VERSION 5.8 ;
BUSBITCHARS "[]" ;
DIVIDERCHAR "/" ;
UNITS
    DATABASE MICRONS 1000 ;
END UNITS

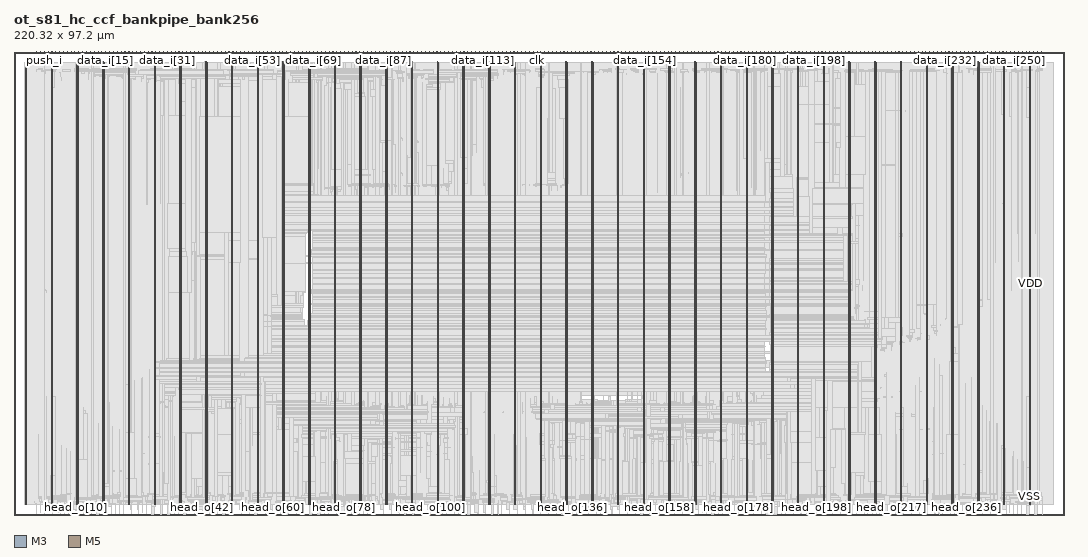
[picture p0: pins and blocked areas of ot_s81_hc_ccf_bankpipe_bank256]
MACRO ot_s81_hc_ccf_bankpipe_bank256
  FOREIGN ot_s81_hc_ccf_bankpipe_bank256 0 0 ;
  CLASS BLOCK ;
  SIZE 220.32 BY 97.2 ;
  PIN clk
    DIRECTION INPUT ;
    USE SIGNAL ;
    PORT
      LAYER M3 ;
        RECT  109.764 97.056 109.782 97.2 ;
    END
  END clk
  PIN data_i[0]
    DIRECTION INPUT ;
    USE SIGNAL ;
    PORT
      LAYER M5 ;
        RECT  7.152 97.008 7.176 97.2 ;
    END
  END data_i[0]
  PIN data_i[100]
    DIRECTION INPUT ;
    USE SIGNAL ;
    PORT
      LAYER M5 ;
        RECT  87.936 97.008 87.96 97.2 ;
    END
  END data_i[100]
  PIN data_i[101]
    DIRECTION INPUT ;
    USE SIGNAL ;
    PORT
      LAYER M3 ;
        RECT  88.74 97.056 88.758 97.2 ;
    END
  END data_i[101]
  PIN data_i[102]
    DIRECTION INPUT ;
    USE SIGNAL ;
    PORT
      LAYER M5 ;
        RECT  89.568 97.008 89.592 97.2 ;
    END
  END data_i[102]
  PIN data_i[103]
    DIRECTION INPUT ;
    USE SIGNAL ;
    PORT
      LAYER M3 ;
        RECT  90.36 97.056 90.378 97.2 ;
    END
  END data_i[103]
  PIN data_i[104]
    DIRECTION INPUT ;
    USE SIGNAL ;
    PORT
      LAYER M5 ;
        RECT  91.152 97.008 91.176 97.2 ;
    END
  END data_i[104]
  PIN data_i[105]
    DIRECTION INPUT ;
    USE SIGNAL ;
    PORT
      LAYER M3 ;
        RECT  91.98 97.056 91.998 97.2 ;
    END
  END data_i[105]
  PIN data_i[106]
    DIRECTION INPUT ;
    USE SIGNAL ;
    PORT
      LAYER M5 ;
        RECT  92.784 97.008 92.808 97.2 ;
    END
  END data_i[106]
  PIN data_i[107]
    DIRECTION INPUT ;
    USE SIGNAL ;
    PORT
      LAYER M3 ;
        RECT  93.6 97.056 93.618 97.2 ;
    END
  END data_i[107]
  PIN data_i[108]
    DIRECTION INPUT ;
    USE SIGNAL ;
    PORT
      LAYER M5 ;
        RECT  94.416 97.008 94.44 97.2 ;
    END
  END data_i[108]
  PIN data_i[109]
    DIRECTION INPUT ;
    USE SIGNAL ;
    PORT
      LAYER M3 ;
        RECT  95.22 97.056 95.238 97.2 ;
    END
  END data_i[109]
  PIN data_i[10]
    DIRECTION INPUT ;
    USE SIGNAL ;
    PORT
      LAYER M5 ;
        RECT  15.216 97.008 15.24 97.2 ;
    END
  END data_i[10]
  PIN data_i[110]
    DIRECTION INPUT ;
    USE SIGNAL ;
    PORT
      LAYER M5 ;
        RECT  96 97.008 96.024 97.2 ;
    END
  END data_i[110]
  PIN data_i[111]
    DIRECTION INPUT ;
    USE SIGNAL ;
    PORT
      LAYER M3 ;
        RECT  96.804 97.056 96.822 97.2 ;
    END
  END data_i[111]
  PIN data_i[112]
    DIRECTION INPUT ;
    USE SIGNAL ;
    PORT
      LAYER M5 ;
        RECT  97.632 97.008 97.656 97.2 ;
    END
  END data_i[112]
  PIN data_i[113]
    DIRECTION INPUT ;
    USE SIGNAL ;
    PORT
      LAYER M3 ;
        RECT  98.424 97.056 98.442 97.2 ;
    END
  END data_i[113]
  PIN data_i[114]
    DIRECTION INPUT ;
    USE SIGNAL ;
    PORT
      LAYER M5 ;
        RECT  99.264 97.008 99.288 97.2 ;
    END
  END data_i[114]
  PIN data_i[115]
    DIRECTION INPUT ;
    USE SIGNAL ;
    PORT
      LAYER M3 ;
        RECT  100.044 97.056 100.062 97.2 ;
    END
  END data_i[115]
  PIN data_i[116]
    DIRECTION INPUT ;
    USE SIGNAL ;
    PORT
      LAYER M5 ;
        RECT  100.848 97.008 100.872 97.2 ;
    END
  END data_i[116]
  PIN data_i[117]
    DIRECTION INPUT ;
    USE SIGNAL ;
    PORT
      LAYER M3 ;
        RECT  101.664 97.056 101.682 97.2 ;
    END
  END data_i[117]
  PIN data_i[118]
    DIRECTION INPUT ;
    USE SIGNAL ;
    PORT
      LAYER M5 ;
        RECT  102.48 97.008 102.504 97.2 ;
    END
  END data_i[118]
  PIN data_i[119]
    DIRECTION INPUT ;
    USE SIGNAL ;
    PORT
      LAYER M3 ;
        RECT  103.284 97.056 103.302 97.2 ;
    END
  END data_i[119]
  PIN data_i[11]
    DIRECTION INPUT ;
    USE SIGNAL ;
    PORT
      LAYER M3 ;
        RECT  16.02 97.056 16.038 97.2 ;
    END
  END data_i[11]
  PIN data_i[120]
    DIRECTION INPUT ;
    USE SIGNAL ;
    PORT
      LAYER M5 ;
        RECT  104.112 97.008 104.136 97.2 ;
    END
  END data_i[120]
  PIN data_i[121]
    DIRECTION INPUT ;
    USE SIGNAL ;
    PORT
      LAYER M3 ;
        RECT  104.904 97.056 104.922 97.2 ;
    END
  END data_i[121]
  PIN data_i[122]
    DIRECTION INPUT ;
    USE SIGNAL ;
    PORT
      LAYER M5 ;
        RECT  105.696 97.008 105.72 97.2 ;
    END
  END data_i[122]
  PIN data_i[123]
    DIRECTION INPUT ;
    USE SIGNAL ;
    PORT
      LAYER M3 ;
        RECT  106.524 97.056 106.542 97.2 ;
    END
  END data_i[123]
  PIN data_i[124]
    DIRECTION INPUT ;
    USE SIGNAL ;
    PORT
      LAYER M5 ;
        RECT  107.328 97.008 107.352 97.2 ;
    END
  END data_i[124]
  PIN data_i[125]
    DIRECTION INPUT ;
    USE SIGNAL ;
    PORT
      LAYER M3 ;
        RECT  108.144 97.056 108.162 97.2 ;
    END
  END data_i[125]
  PIN data_i[126]
    DIRECTION INPUT ;
    USE SIGNAL ;
    PORT
      LAYER M5 ;
        RECT  108.96 97.008 108.984 97.2 ;
    END
  END data_i[126]
  PIN data_i[127]
    DIRECTION INPUT ;
    USE SIGNAL ;
    PORT
      LAYER M5 ;
        RECT  110.544 97.008 110.568 97.2 ;
    END
  END data_i[127]
  PIN data_i[128]
    DIRECTION INPUT ;
    USE SIGNAL ;
    PORT
      LAYER M3 ;
        RECT  111.348 97.056 111.366 97.2 ;
    END
  END data_i[128]
  PIN data_i[129]
    DIRECTION INPUT ;
    USE SIGNAL ;
    PORT
      LAYER M5 ;
        RECT  112.176 97.008 112.2 97.2 ;
    END
  END data_i[129]
  PIN data_i[12]
    DIRECTION INPUT ;
    USE SIGNAL ;
    PORT
      LAYER M5 ;
        RECT  16.848 97.008 16.872 97.2 ;
    END
  END data_i[12]
  PIN data_i[130]
    DIRECTION INPUT ;
    USE SIGNAL ;
    PORT
      LAYER M3 ;
        RECT  112.968 97.056 112.986 97.2 ;
    END
  END data_i[130]
  PIN data_i[131]
    DIRECTION INPUT ;
    USE SIGNAL ;
    PORT
      LAYER M5 ;
        RECT  113.76 97.008 113.784 97.2 ;
    END
  END data_i[131]
  PIN data_i[132]
    DIRECTION INPUT ;
    USE SIGNAL ;
    PORT
      LAYER M3 ;
        RECT  114.588 97.056 114.606 97.2 ;
    END
  END data_i[132]
  PIN data_i[133]
    DIRECTION INPUT ;
    USE SIGNAL ;
    PORT
      LAYER M5 ;
        RECT  115.392 97.008 115.416 97.2 ;
    END
  END data_i[133]
  PIN data_i[134]
    DIRECTION INPUT ;
    USE SIGNAL ;
    PORT
      LAYER M3 ;
        RECT  116.208 97.056 116.226 97.2 ;
    END
  END data_i[134]
  PIN data_i[135]
    DIRECTION INPUT ;
    USE SIGNAL ;
    PORT
      LAYER M5 ;
        RECT  117.024 97.008 117.048 97.2 ;
    END
  END data_i[135]
  PIN data_i[136]
    DIRECTION INPUT ;
    USE SIGNAL ;
    PORT
      LAYER M3 ;
        RECT  117.828 97.056 117.846 97.2 ;
    END
  END data_i[136]
  PIN data_i[137]
    DIRECTION INPUT ;
    USE SIGNAL ;
    PORT
      LAYER M5 ;
        RECT  118.608 97.008 118.632 97.2 ;
    END
  END data_i[137]
  PIN data_i[138]
    DIRECTION INPUT ;
    USE SIGNAL ;
    PORT
      LAYER M3 ;
        RECT  119.448 97.056 119.466 97.2 ;
    END
  END data_i[138]
  PIN data_i[139]
    DIRECTION INPUT ;
    USE SIGNAL ;
    PORT
      LAYER M5 ;
        RECT  120.24 97.008 120.264 97.2 ;
    END
  END data_i[139]
  PIN data_i[13]
    DIRECTION INPUT ;
    USE SIGNAL ;
    PORT
      LAYER M3 ;
        RECT  17.64 97.056 17.658 97.2 ;
    END
  END data_i[13]
  PIN data_i[140]
    DIRECTION INPUT ;
    USE SIGNAL ;
    PORT
      LAYER M3 ;
        RECT  121.068 97.056 121.086 97.2 ;
    END
  END data_i[140]
  PIN data_i[141]
    DIRECTION INPUT ;
    USE SIGNAL ;
    PORT
      LAYER M5 ;
        RECT  121.872 97.008 121.896 97.2 ;
    END
  END data_i[141]
  PIN data_i[142]
    DIRECTION INPUT ;
    USE SIGNAL ;
    PORT
      LAYER M3 ;
        RECT  122.688 97.056 122.706 97.2 ;
    END
  END data_i[142]
  PIN data_i[143]
    DIRECTION INPUT ;
    USE SIGNAL ;
    PORT
      LAYER M5 ;
        RECT  123.456 97.008 123.48 97.2 ;
    END
  END data_i[143]
  PIN data_i[144]
    DIRECTION INPUT ;
    USE SIGNAL ;
    PORT
      LAYER M3 ;
        RECT  124.272 97.056 124.29 97.2 ;
    END
  END data_i[144]
  PIN data_i[145]
    DIRECTION INPUT ;
    USE SIGNAL ;
    PORT
      LAYER M5 ;
        RECT  125.088 97.008 125.112 97.2 ;
    END
  END data_i[145]
  PIN data_i[146]
    DIRECTION INPUT ;
    USE SIGNAL ;
    PORT
      LAYER M3 ;
        RECT  125.892 97.056 125.91 97.2 ;
    END
  END data_i[146]
  PIN data_i[147]
    DIRECTION INPUT ;
    USE SIGNAL ;
    PORT
      LAYER M5 ;
        RECT  126.72 97.008 126.744 97.2 ;
    END
  END data_i[147]
  PIN data_i[148]
    DIRECTION INPUT ;
    USE SIGNAL ;
    PORT
      LAYER M3 ;
        RECT  127.512 97.056 127.53 97.2 ;
    END
  END data_i[148]
  PIN data_i[149]
    DIRECTION INPUT ;
    USE SIGNAL ;
    PORT
      LAYER M5 ;
        RECT  128.304 97.008 128.328 97.2 ;
    END
  END data_i[149]
  PIN data_i[14]
    DIRECTION INPUT ;
    USE SIGNAL ;
    PORT
      LAYER M5 ;
        RECT  18.432 97.008 18.456 97.2 ;
    END
  END data_i[14]
  PIN data_i[150]
    DIRECTION INPUT ;
    USE SIGNAL ;
    PORT
      LAYER M3 ;
        RECT  129.132 97.056 129.15 97.2 ;
    END
  END data_i[150]
  PIN data_i[151]
    DIRECTION INPUT ;
    USE SIGNAL ;
    PORT
      LAYER M5 ;
        RECT  129.936 97.008 129.96 97.2 ;
    END
  END data_i[151]
  PIN data_i[152]
    DIRECTION INPUT ;
    USE SIGNAL ;
    PORT
      LAYER M3 ;
        RECT  130.752 97.056 130.77 97.2 ;
    END
  END data_i[152]
  PIN data_i[153]
    DIRECTION INPUT ;
    USE SIGNAL ;
    PORT
      LAYER M5 ;
        RECT  131.568 97.008 131.592 97.2 ;
    END
  END data_i[153]
  PIN data_i[154]
    DIRECTION INPUT ;
    USE SIGNAL ;
    PORT
      LAYER M3 ;
        RECT  132.372 97.056 132.39 97.2 ;
    END
  END data_i[154]
  PIN data_i[155]
    DIRECTION INPUT ;
    USE SIGNAL ;
    PORT
      LAYER M5 ;
        RECT  133.152 97.008 133.176 97.2 ;
    END
  END data_i[155]
  PIN data_i[156]
    DIRECTION INPUT ;
    USE SIGNAL ;
    PORT
      LAYER M3 ;
        RECT  133.992 97.056 134.01 97.2 ;
    END
  END data_i[156]
  PIN data_i[157]
    DIRECTION INPUT ;
    USE SIGNAL ;
    PORT
      LAYER M5 ;
        RECT  134.784 97.008 134.808 97.2 ;
    END
  END data_i[157]
  PIN data_i[158]
    DIRECTION INPUT ;
    USE SIGNAL ;
    PORT
      LAYER M3 ;
        RECT  135.612 97.056 135.63 97.2 ;
    END
  END data_i[158]
  PIN data_i[159]
    DIRECTION INPUT ;
    USE SIGNAL ;
    PORT
      LAYER M5 ;
        RECT  136.416 97.008 136.44 97.2 ;
    END
  END data_i[159]
  PIN data_i[15]
    DIRECTION INPUT ;
    USE SIGNAL ;
    PORT
      LAYER M3 ;
        RECT  19.26 97.056 19.278 97.2 ;
    END
  END data_i[15]
  PIN data_i[160]
    DIRECTION INPUT ;
    USE SIGNAL ;
    PORT
      LAYER M3 ;
        RECT  137.232 97.056 137.25 97.2 ;
    END
  END data_i[160]
  PIN data_i[161]
    DIRECTION INPUT ;
    USE SIGNAL ;
    PORT
      LAYER M5 ;
        RECT  138 97.008 138.024 97.2 ;
    END
  END data_i[161]
  PIN data_i[162]
    DIRECTION INPUT ;
    USE SIGNAL ;
    PORT
      LAYER M3 ;
        RECT  138.816 97.056 138.834 97.2 ;
    END
  END data_i[162]
  PIN data_i[163]
    DIRECTION INPUT ;
    USE SIGNAL ;
    PORT
      LAYER M5 ;
        RECT  139.632 97.008 139.656 97.2 ;
    END
  END data_i[163]
  PIN data_i[164]
    DIRECTION INPUT ;
    USE SIGNAL ;
    PORT
      LAYER M3 ;
        RECT  140.436 97.056 140.454 97.2 ;
    END
  END data_i[164]
  PIN data_i[165]
    DIRECTION INPUT ;
    USE SIGNAL ;
    PORT
      LAYER M5 ;
        RECT  141.264 97.008 141.288 97.2 ;
    END
  END data_i[165]
  PIN data_i[166]
    DIRECTION INPUT ;
    USE SIGNAL ;
    PORT
      LAYER M3 ;
        RECT  142.056 97.056 142.074 97.2 ;
    END
  END data_i[166]
  PIN data_i[167]
    DIRECTION INPUT ;
    USE SIGNAL ;
    PORT
      LAYER M5 ;
        RECT  142.848 97.008 142.872 97.2 ;
    END
  END data_i[167]
  PIN data_i[168]
    DIRECTION INPUT ;
    USE SIGNAL ;
    PORT
      LAYER M3 ;
        RECT  143.676 97.056 143.694 97.2 ;
    END
  END data_i[168]
  PIN data_i[169]
    DIRECTION INPUT ;
    USE SIGNAL ;
    PORT
      LAYER M5 ;
        RECT  144.48 97.008 144.504 97.2 ;
    END
  END data_i[169]
  PIN data_i[16]
    DIRECTION INPUT ;
    USE SIGNAL ;
    PORT
      LAYER M5 ;
        RECT  20.064 97.008 20.088 97.2 ;
    END
  END data_i[16]
  PIN data_i[170]
    DIRECTION INPUT ;
    USE SIGNAL ;
    PORT
      LAYER M3 ;
        RECT  145.296 97.056 145.314 97.2 ;
    END
  END data_i[170]
  PIN data_i[171]
    DIRECTION INPUT ;
    USE SIGNAL ;
    PORT
      LAYER M5 ;
        RECT  146.112 97.008 146.136 97.2 ;
    END
  END data_i[171]
  PIN data_i[172]
    DIRECTION INPUT ;
    USE SIGNAL ;
    PORT
      LAYER M3 ;
        RECT  146.916 97.056 146.934 97.2 ;
    END
  END data_i[172]
  PIN data_i[173]
    DIRECTION INPUT ;
    USE SIGNAL ;
    PORT
      LAYER M5 ;
        RECT  147.696 97.008 147.72 97.2 ;
    END
  END data_i[173]
  PIN data_i[174]
    DIRECTION INPUT ;
    USE SIGNAL ;
    PORT
      LAYER M3 ;
        RECT  148.536 97.056 148.554 97.2 ;
    END
  END data_i[174]
  PIN data_i[175]
    DIRECTION INPUT ;
    USE SIGNAL ;
    PORT
      LAYER M5 ;
        RECT  149.328 97.008 149.352 97.2 ;
    END
  END data_i[175]
  PIN data_i[176]
    DIRECTION INPUT ;
    USE SIGNAL ;
    PORT
      LAYER M3 ;
        RECT  150.156 97.056 150.174 97.2 ;
    END
  END data_i[176]
  PIN data_i[177]
    DIRECTION INPUT ;
    USE SIGNAL ;
    PORT
      LAYER M5 ;
        RECT  150.96 97.008 150.984 97.2 ;
    END
  END data_i[177]
  PIN data_i[178]
    DIRECTION INPUT ;
    USE SIGNAL ;
    PORT
      LAYER M3 ;
        RECT  151.776 97.056 151.794 97.2 ;
    END
  END data_i[178]
  PIN data_i[179]
    DIRECTION INPUT ;
    USE SIGNAL ;
    PORT
      LAYER M5 ;
        RECT  152.544 97.008 152.568 97.2 ;
    END
  END data_i[179]
  PIN data_i[17]
    DIRECTION INPUT ;
    USE SIGNAL ;
    PORT
      LAYER M3 ;
        RECT  20.88 97.056 20.898 97.2 ;
    END
  END data_i[17]
  PIN data_i[180]
    DIRECTION INPUT ;
    USE SIGNAL ;
    PORT
      LAYER M3 ;
        RECT  153.36 97.056 153.378 97.2 ;
    END
  END data_i[180]
  PIN data_i[181]
    DIRECTION INPUT ;
    USE SIGNAL ;
    PORT
      LAYER M5 ;
        RECT  154.176 97.008 154.2 97.2 ;
    END
  END data_i[181]
  PIN data_i[182]
    DIRECTION INPUT ;
    USE SIGNAL ;
    PORT
      LAYER M3 ;
        RECT  154.98 97.056 154.998 97.2 ;
    END
  END data_i[182]
  PIN data_i[183]
    DIRECTION INPUT ;
    USE SIGNAL ;
    PORT
      LAYER M5 ;
        RECT  155.808 97.008 155.832 97.2 ;
    END
  END data_i[183]
  PIN data_i[184]
    DIRECTION INPUT ;
    USE SIGNAL ;
    PORT
      LAYER M3 ;
        RECT  156.6 97.056 156.618 97.2 ;
    END
  END data_i[184]
  PIN data_i[185]
    DIRECTION INPUT ;
    USE SIGNAL ;
    PORT
      LAYER M5 ;
        RECT  157.392 97.008 157.416 97.2 ;
    END
  END data_i[185]
  PIN data_i[186]
    DIRECTION INPUT ;
    USE SIGNAL ;
    PORT
      LAYER M3 ;
        RECT  158.22 97.056 158.238 97.2 ;
    END
  END data_i[186]
  PIN data_i[187]
    DIRECTION INPUT ;
    USE SIGNAL ;
    PORT
      LAYER M5 ;
        RECT  159.024 97.008 159.048 97.2 ;
    END
  END data_i[187]
  PIN data_i[188]
    DIRECTION INPUT ;
    USE SIGNAL ;
    PORT
      LAYER M3 ;
        RECT  159.84 97.056 159.858 97.2 ;
    END
  END data_i[188]
  PIN data_i[189]
    DIRECTION INPUT ;
    USE SIGNAL ;
    PORT
      LAYER M5 ;
        RECT  160.656 97.008 160.68 97.2 ;
    END
  END data_i[189]
  PIN data_i[18]
    DIRECTION INPUT ;
    USE SIGNAL ;
    PORT
      LAYER M5 ;
        RECT  21.696 97.008 21.72 97.2 ;
    END
  END data_i[18]
  PIN data_i[190]
    DIRECTION INPUT ;
    USE SIGNAL ;
    PORT
      LAYER M3 ;
        RECT  161.46 97.056 161.478 97.2 ;
    END
  END data_i[190]
  PIN data_i[191]
    DIRECTION INPUT ;
    USE SIGNAL ;
    PORT
      LAYER M5 ;
        RECT  162.24 97.008 162.264 97.2 ;
    END
  END data_i[191]
  PIN data_i[192]
    DIRECTION INPUT ;
    USE SIGNAL ;
    PORT
      LAYER M3 ;
        RECT  163.08 97.056 163.098 97.2 ;
    END
  END data_i[192]
  PIN data_i[193]
    DIRECTION INPUT ;
    USE SIGNAL ;
    PORT
      LAYER M5 ;
        RECT  163.872 97.008 163.896 97.2 ;
    END
  END data_i[193]
  PIN data_i[194]
    DIRECTION INPUT ;
    USE SIGNAL ;
    PORT
      LAYER M3 ;
        RECT  164.7 97.056 164.718 97.2 ;
    END
  END data_i[194]
  PIN data_i[195]
    DIRECTION INPUT ;
    USE SIGNAL ;
    PORT
      LAYER M5 ;
        RECT  165.504 97.008 165.528 97.2 ;
    END
  END data_i[195]
  PIN data_i[196]
    DIRECTION INPUT ;
    USE SIGNAL ;
    PORT
      LAYER M3 ;
        RECT  166.32 97.056 166.338 97.2 ;
    END
  END data_i[196]
  PIN data_i[197]
    DIRECTION INPUT ;
    USE SIGNAL ;
    PORT
      LAYER M5 ;
        RECT  167.088 97.008 167.112 97.2 ;
    END
  END data_i[197]
  PIN data_i[198]
    DIRECTION INPUT ;
    USE SIGNAL ;
    PORT
      LAYER M3 ;
        RECT  167.904 97.056 167.922 97.2 ;
    END
  END data_i[198]
  PIN data_i[199]
    DIRECTION INPUT ;
    USE SIGNAL ;
    PORT
      LAYER M5 ;
        RECT  168.72 97.008 168.744 97.2 ;
    END
  END data_i[199]
  PIN data_i[19]
    DIRECTION INPUT ;
    USE SIGNAL ;
    PORT
      LAYER M3 ;
        RECT  22.5 97.056 22.518 97.2 ;
    END
  END data_i[19]
  PIN data_i[1]
    DIRECTION INPUT ;
    USE SIGNAL ;
    PORT
      LAYER M3 ;
        RECT  7.956 97.056 7.974 97.2 ;
    END
  END data_i[1]
  PIN data_i[200]
    DIRECTION INPUT ;
    USE SIGNAL ;
    PORT
      LAYER M3 ;
        RECT  169.524 97.056 169.542 97.2 ;
    END
  END data_i[200]
  PIN data_i[201]
    DIRECTION INPUT ;
    USE SIGNAL ;
    PORT
      LAYER M5 ;
        RECT  170.352 97.008 170.376 97.2 ;
    END
  END data_i[201]
  PIN data_i[202]
    DIRECTION INPUT ;
    USE SIGNAL ;
    PORT
      LAYER M3 ;
        RECT  171.144 97.056 171.162 97.2 ;
    END
  END data_i[202]
  PIN data_i[203]
    DIRECTION INPUT ;
    USE SIGNAL ;
    PORT
      LAYER M5 ;
        RECT  171.936 97.008 171.96 97.2 ;
    END
  END data_i[203]
  PIN data_i[204]
    DIRECTION INPUT ;
    USE SIGNAL ;
    PORT
      LAYER M3 ;
        RECT  172.764 97.056 172.782 97.2 ;
    END
  END data_i[204]
  PIN data_i[205]
    DIRECTION INPUT ;
    USE SIGNAL ;
    PORT
      LAYER M5 ;
        RECT  173.568 97.008 173.592 97.2 ;
    END
  END data_i[205]
  PIN data_i[206]
    DIRECTION INPUT ;
    USE SIGNAL ;
    PORT
      LAYER M3 ;
        RECT  174.384 97.056 174.402 97.2 ;
    END
  END data_i[206]
  PIN data_i[207]
    DIRECTION INPUT ;
    USE SIGNAL ;
    PORT
      LAYER M5 ;
        RECT  175.2 97.008 175.224 97.2 ;
    END
  END data_i[207]
  PIN data_i[208]
    DIRECTION INPUT ;
    USE SIGNAL ;
    PORT
      LAYER M3 ;
        RECT  176.004 97.056 176.022 97.2 ;
    END
  END data_i[208]
  PIN data_i[209]
    DIRECTION INPUT ;
    USE SIGNAL ;
    PORT
      LAYER M5 ;
        RECT  176.784 97.008 176.808 97.2 ;
    END
  END data_i[209]
  PIN data_i[20]
    DIRECTION INPUT ;
    USE SIGNAL ;
    PORT
      LAYER M5 ;
        RECT  23.28 97.008 23.304 97.2 ;
    END
  END data_i[20]
  PIN data_i[210]
    DIRECTION INPUT ;
    USE SIGNAL ;
    PORT
      LAYER M3 ;
        RECT  177.624 97.056 177.642 97.2 ;
    END
  END data_i[210]
  PIN data_i[211]
    DIRECTION INPUT ;
    USE SIGNAL ;
    PORT
      LAYER M5 ;
        RECT  178.416 97.008 178.44 97.2 ;
    END
  END data_i[211]
  PIN data_i[212]
    DIRECTION INPUT ;
    USE SIGNAL ;
    PORT
      LAYER M3 ;
        RECT  179.244 97.056 179.262 97.2 ;
    END
  END data_i[212]
  PIN data_i[213]
    DIRECTION INPUT ;
    USE SIGNAL ;
    PORT
      LAYER M5 ;
        RECT  180.048 97.008 180.072 97.2 ;
    END
  END data_i[213]
  PIN data_i[214]
    DIRECTION INPUT ;
    USE SIGNAL ;
    PORT
      LAYER M3 ;
        RECT  180.828 97.056 180.846 97.2 ;
    END
  END data_i[214]
  PIN data_i[215]
    DIRECTION INPUT ;
    USE SIGNAL ;
    PORT
      LAYER M5 ;
        RECT  181.632 97.008 181.656 97.2 ;
    END
  END data_i[215]
  PIN data_i[216]
    DIRECTION INPUT ;
    USE SIGNAL ;
    PORT
      LAYER M3 ;
        RECT  182.448 97.056 182.466 97.2 ;
    END
  END data_i[216]
  PIN data_i[217]
    DIRECTION INPUT ;
    USE SIGNAL ;
    PORT
      LAYER M5 ;
        RECT  183.264 97.008 183.288 97.2 ;
    END
  END data_i[217]
  PIN data_i[218]
    DIRECTION INPUT ;
    USE SIGNAL ;
    PORT
      LAYER M3 ;
        RECT  184.068 97.056 184.086 97.2 ;
    END
  END data_i[218]
  PIN data_i[219]
    DIRECTION INPUT ;
    USE SIGNAL ;
    PORT
      LAYER M5 ;
        RECT  184.896 97.008 184.92 97.2 ;
    END
  END data_i[219]
  PIN data_i[21]
    DIRECTION INPUT ;
    USE SIGNAL ;
    PORT
      LAYER M3 ;
        RECT  24.12 97.056 24.138 97.2 ;
    END
  END data_i[21]
  PIN data_i[220]
    DIRECTION INPUT ;
    USE SIGNAL ;
    PORT
      LAYER M3 ;
        RECT  185.688 97.056 185.706 97.2 ;
    END
  END data_i[220]
  PIN data_i[221]
    DIRECTION INPUT ;
    USE SIGNAL ;
    PORT
      LAYER M5 ;
        RECT  186.48 97.008 186.504 97.2 ;
    END
  END data_i[221]
  PIN data_i[222]
    DIRECTION INPUT ;
    USE SIGNAL ;
    PORT
      LAYER M3 ;
        RECT  187.308 97.056 187.326 97.2 ;
    END
  END data_i[222]
  PIN data_i[223]
    DIRECTION INPUT ;
    USE SIGNAL ;
    PORT
      LAYER M5 ;
        RECT  188.112 97.008 188.136 97.2 ;
    END
  END data_i[223]
  PIN data_i[224]
    DIRECTION INPUT ;
    USE SIGNAL ;
    PORT
      LAYER M3 ;
        RECT  188.928 97.056 188.946 97.2 ;
    END
  END data_i[224]
  PIN data_i[225]
    DIRECTION INPUT ;
    USE SIGNAL ;
    PORT
      LAYER M5 ;
        RECT  189.744 97.008 189.768 97.2 ;
    END
  END data_i[225]
  PIN data_i[226]
    DIRECTION INPUT ;
    USE SIGNAL ;
    PORT
      LAYER M3 ;
        RECT  190.548 97.056 190.566 97.2 ;
    END
  END data_i[226]
  PIN data_i[227]
    DIRECTION INPUT ;
    USE SIGNAL ;
    PORT
      LAYER M5 ;
        RECT  191.328 97.008 191.352 97.2 ;
    END
  END data_i[227]
  PIN data_i[228]
    DIRECTION INPUT ;
    USE SIGNAL ;
    PORT
      LAYER M3 ;
        RECT  192.168 97.056 192.186 97.2 ;
    END
  END data_i[228]
  PIN data_i[229]
    DIRECTION INPUT ;
    USE SIGNAL ;
    PORT
      LAYER M5 ;
        RECT  192.96 97.008 192.984 97.2 ;
    END
  END data_i[229]
  PIN data_i[22]
    DIRECTION INPUT ;
    USE SIGNAL ;
    PORT
      LAYER M5 ;
        RECT  24.912 97.008 24.936 97.2 ;
    END
  END data_i[22]
  PIN data_i[230]
    DIRECTION INPUT ;
    USE SIGNAL ;
    PORT
      LAYER M3 ;
        RECT  193.788 97.056 193.806 97.2 ;
    END
  END data_i[230]
  PIN data_i[231]
    DIRECTION INPUT ;
    USE SIGNAL ;
    PORT
      LAYER M5 ;
        RECT  194.592 97.008 194.616 97.2 ;
    END
  END data_i[231]
  PIN data_i[232]
    DIRECTION INPUT ;
    USE SIGNAL ;
    PORT
      LAYER M3 ;
        RECT  195.372 97.056 195.39 97.2 ;
    END
  END data_i[232]
  PIN data_i[233]
    DIRECTION INPUT ;
    USE SIGNAL ;
    PORT
      LAYER M5 ;
        RECT  196.176 97.008 196.2 97.2 ;
    END
  END data_i[233]
  PIN data_i[234]
    DIRECTION INPUT ;
    USE SIGNAL ;
    PORT
      LAYER M3 ;
        RECT  196.992 97.056 197.01 97.2 ;
    END
  END data_i[234]
  PIN data_i[235]
    DIRECTION INPUT ;
    USE SIGNAL ;
    PORT
      LAYER M5 ;
        RECT  197.808 97.008 197.832 97.2 ;
    END
  END data_i[235]
  PIN data_i[236]
    DIRECTION INPUT ;
    USE SIGNAL ;
    PORT
      LAYER M3 ;
        RECT  198.612 97.056 198.63 97.2 ;
    END
  END data_i[236]
  PIN data_i[237]
    DIRECTION INPUT ;
    USE SIGNAL ;
    PORT
      LAYER M5 ;
        RECT  199.44 97.008 199.464 97.2 ;
    END
  END data_i[237]
  PIN data_i[238]
    DIRECTION INPUT ;
    USE SIGNAL ;
    PORT
      LAYER M3 ;
        RECT  200.232 97.056 200.25 97.2 ;
    END
  END data_i[238]
  PIN data_i[239]
    DIRECTION INPUT ;
    USE SIGNAL ;
    PORT
      LAYER M5 ;
        RECT  201.024 97.008 201.048 97.2 ;
    END
  END data_i[239]
  PIN data_i[23]
    DIRECTION INPUT ;
    USE SIGNAL ;
    PORT
      LAYER M3 ;
        RECT  25.704 97.056 25.722 97.2 ;
    END
  END data_i[23]
  PIN data_i[240]
    DIRECTION INPUT ;
    USE SIGNAL ;
    PORT
      LAYER M3 ;
        RECT  201.852 97.056 201.87 97.2 ;
    END
  END data_i[240]
  PIN data_i[241]
    DIRECTION INPUT ;
    USE SIGNAL ;
    PORT
      LAYER M5 ;
        RECT  202.656 97.008 202.68 97.2 ;
    END
  END data_i[241]
  PIN data_i[242]
    DIRECTION INPUT ;
    USE SIGNAL ;
    PORT
      LAYER M3 ;
        RECT  203.472 97.056 203.49 97.2 ;
    END
  END data_i[242]
  PIN data_i[243]
    DIRECTION INPUT ;
    USE SIGNAL ;
    PORT
      LAYER M5 ;
        RECT  204.288 97.008 204.312 97.2 ;
    END
  END data_i[243]
  PIN data_i[244]
    DIRECTION INPUT ;
    USE SIGNAL ;
    PORT
      LAYER M3 ;
        RECT  205.092 97.056 205.11 97.2 ;
    END
  END data_i[244]
  PIN data_i[245]
    DIRECTION INPUT ;
    USE SIGNAL ;
    PORT
      LAYER M5 ;
        RECT  205.872 97.008 205.896 97.2 ;
    END
  END data_i[245]
  PIN data_i[246]
    DIRECTION INPUT ;
    USE SIGNAL ;
    PORT
      LAYER M3 ;
        RECT  206.712 97.056 206.73 97.2 ;
    END
  END data_i[246]
  PIN data_i[247]
    DIRECTION INPUT ;
    USE SIGNAL ;
    PORT
      LAYER M5 ;
        RECT  207.504 97.008 207.528 97.2 ;
    END
  END data_i[247]
  PIN data_i[248]
    DIRECTION INPUT ;
    USE SIGNAL ;
    PORT
      LAYER M3 ;
        RECT  208.332 97.056 208.35 97.2 ;
    END
  END data_i[248]
  PIN data_i[249]
    DIRECTION INPUT ;
    USE SIGNAL ;
    PORT
      LAYER M5 ;
        RECT  209.136 97.008 209.16 97.2 ;
    END
  END data_i[249]
  PIN data_i[24]
    DIRECTION INPUT ;
    USE SIGNAL ;
    PORT
      LAYER M5 ;
        RECT  26.544 97.008 26.568 97.2 ;
    END
  END data_i[24]
  PIN data_i[250]
    DIRECTION INPUT ;
    USE SIGNAL ;
    PORT
      LAYER M3 ;
        RECT  209.916 97.056 209.934 97.2 ;
    END
  END data_i[250]
  PIN data_i[251]
    DIRECTION INPUT ;
    USE SIGNAL ;
    PORT
      LAYER M5 ;
        RECT  210.72 97.008 210.744 97.2 ;
    END
  END data_i[251]
  PIN data_i[252]
    DIRECTION INPUT ;
    USE SIGNAL ;
    PORT
      LAYER M3 ;
        RECT  211.536 97.056 211.554 97.2 ;
    END
  END data_i[252]
  PIN data_i[253]
    DIRECTION INPUT ;
    USE SIGNAL ;
    PORT
      LAYER M5 ;
        RECT  212.352 97.008 212.376 97.2 ;
    END
  END data_i[253]
  PIN data_i[254]
    DIRECTION INPUT ;
    USE SIGNAL ;
    PORT
      LAYER M3 ;
        RECT  213.156 97.056 213.174 97.2 ;
    END
  END data_i[254]
  PIN data_i[255]
    DIRECTION INPUT ;
    USE SIGNAL ;
    PORT
      LAYER M5 ;
        RECT  213.984 97.008 214.008 97.2 ;
    END
  END data_i[255]
  PIN data_i[25]
    DIRECTION INPUT ;
    USE SIGNAL ;
    PORT
      LAYER M3 ;
        RECT  27.324 97.056 27.342 97.2 ;
    END
  END data_i[25]
  PIN data_i[26]
    DIRECTION INPUT ;
    USE SIGNAL ;
    PORT
      LAYER M5 ;
        RECT  28.128 97.008 28.152 97.2 ;
    END
  END data_i[26]
  PIN data_i[27]
    DIRECTION INPUT ;
    USE SIGNAL ;
    PORT
      LAYER M3 ;
        RECT  28.944 97.056 28.962 97.2 ;
    END
  END data_i[27]
  PIN data_i[28]
    DIRECTION INPUT ;
    USE SIGNAL ;
    PORT
      LAYER M5 ;
        RECT  29.76 97.008 29.784 97.2 ;
    END
  END data_i[28]
  PIN data_i[29]
    DIRECTION INPUT ;
    USE SIGNAL ;
    PORT
      LAYER M3 ;
        RECT  30.564 97.056 30.582 97.2 ;
    END
  END data_i[29]
  PIN data_i[2]
    DIRECTION INPUT ;
    USE SIGNAL ;
    PORT
      LAYER M5 ;
        RECT  8.736 97.008 8.76 97.2 ;
    END
  END data_i[2]
  PIN data_i[30]
    DIRECTION INPUT ;
    USE SIGNAL ;
    PORT
      LAYER M5 ;
        RECT  31.392 97.008 31.416 97.2 ;
    END
  END data_i[30]
  PIN data_i[31]
    DIRECTION INPUT ;
    USE SIGNAL ;
    PORT
      LAYER M3 ;
        RECT  32.184 97.056 32.202 97.2 ;
    END
  END data_i[31]
  PIN data_i[32]
    DIRECTION INPUT ;
    USE SIGNAL ;
    PORT
      LAYER M5 ;
        RECT  32.976 97.008 33 97.2 ;
    END
  END data_i[32]
  PIN data_i[33]
    DIRECTION INPUT ;
    USE SIGNAL ;
    PORT
      LAYER M3 ;
        RECT  33.804 97.056 33.822 97.2 ;
    END
  END data_i[33]
  PIN data_i[34]
    DIRECTION INPUT ;
    USE SIGNAL ;
    PORT
      LAYER M5 ;
        RECT  34.608 97.008 34.632 97.2 ;
    END
  END data_i[34]
  PIN data_i[35]
    DIRECTION INPUT ;
    USE SIGNAL ;
    PORT
      LAYER M3 ;
        RECT  35.424 97.056 35.442 97.2 ;
    END
  END data_i[35]
  PIN data_i[36]
    DIRECTION INPUT ;
    USE SIGNAL ;
    PORT
      LAYER M5 ;
        RECT  36.24 97.008 36.264 97.2 ;
    END
  END data_i[36]
  PIN data_i[37]
    DIRECTION INPUT ;
    USE SIGNAL ;
    PORT
      LAYER M3 ;
        RECT  37.044 97.056 37.062 97.2 ;
    END
  END data_i[37]
  PIN data_i[38]
    DIRECTION INPUT ;
    USE SIGNAL ;
    PORT
      LAYER M5 ;
        RECT  37.824 97.008 37.848 97.2 ;
    END
  END data_i[38]
  PIN data_i[39]
    DIRECTION INPUT ;
    USE SIGNAL ;
    PORT
      LAYER M3 ;
        RECT  38.664 97.056 38.682 97.2 ;
    END
  END data_i[39]
  PIN data_i[3]
    DIRECTION INPUT ;
    USE SIGNAL ;
    PORT
      LAYER M3 ;
        RECT  9.576 97.056 9.594 97.2 ;
    END
  END data_i[3]
  PIN data_i[40]
    DIRECTION INPUT ;
    USE SIGNAL ;
    PORT
      LAYER M5 ;
        RECT  39.456 97.008 39.48 97.2 ;
    END
  END data_i[40]
  PIN data_i[41]
    DIRECTION INPUT ;
    USE SIGNAL ;
    PORT
      LAYER M3 ;
        RECT  40.248 97.056 40.266 97.2 ;
    END
  END data_i[41]
  PIN data_i[42]
    DIRECTION INPUT ;
    USE SIGNAL ;
    PORT
      LAYER M5 ;
        RECT  41.088 97.008 41.112 97.2 ;
    END
  END data_i[42]
  PIN data_i[43]
    DIRECTION INPUT ;
    USE SIGNAL ;
    PORT
      LAYER M3 ;
        RECT  41.868 97.056 41.886 97.2 ;
    END
  END data_i[43]
  PIN data_i[44]
    DIRECTION INPUT ;
    USE SIGNAL ;
    PORT
      LAYER M5 ;
        RECT  42.672 97.008 42.696 97.2 ;
    END
  END data_i[44]
  PIN data_i[45]
    DIRECTION INPUT ;
    USE SIGNAL ;
    PORT
      LAYER M3 ;
        RECT  43.488 97.056 43.506 97.2 ;
    END
  END data_i[45]
  PIN data_i[46]
    DIRECTION INPUT ;
    USE SIGNAL ;
    PORT
      LAYER M5 ;
        RECT  44.304 97.008 44.328 97.2 ;
    END
  END data_i[46]
  PIN data_i[47]
    DIRECTION INPUT ;
    USE SIGNAL ;
    PORT
      LAYER M3 ;
        RECT  45.108 97.056 45.126 97.2 ;
    END
  END data_i[47]
  PIN data_i[48]
    DIRECTION INPUT ;
    USE SIGNAL ;
    PORT
      LAYER M5 ;
        RECT  45.936 97.008 45.96 97.2 ;
    END
  END data_i[48]
  PIN data_i[49]
    DIRECTION INPUT ;
    USE SIGNAL ;
    PORT
      LAYER M3 ;
        RECT  46.728 97.056 46.746 97.2 ;
    END
  END data_i[49]
  PIN data_i[4]
    DIRECTION INPUT ;
    USE SIGNAL ;
    PORT
      LAYER M5 ;
        RECT  10.368 97.008 10.392 97.2 ;
    END
  END data_i[4]
  PIN data_i[50]
    DIRECTION INPUT ;
    USE SIGNAL ;
    PORT
      LAYER M5 ;
        RECT  47.52 97.008 47.544 97.2 ;
    END
  END data_i[50]
  PIN data_i[51]
    DIRECTION INPUT ;
    USE SIGNAL ;
    PORT
      LAYER M3 ;
        RECT  48.348 97.056 48.366 97.2 ;
    END
  END data_i[51]
  PIN data_i[52]
    DIRECTION INPUT ;
    USE SIGNAL ;
    PORT
      LAYER M5 ;
        RECT  49.152 97.008 49.176 97.2 ;
    END
  END data_i[52]
  PIN data_i[53]
    DIRECTION INPUT ;
    USE SIGNAL ;
    PORT
      LAYER M3 ;
        RECT  49.968 97.056 49.986 97.2 ;
    END
  END data_i[53]
  PIN data_i[54]
    DIRECTION INPUT ;
    USE SIGNAL ;
    PORT
      LAYER M5 ;
        RECT  50.784 97.008 50.808 97.2 ;
    END
  END data_i[54]
  PIN data_i[55]
    DIRECTION INPUT ;
    USE SIGNAL ;
    PORT
      LAYER M3 ;
        RECT  51.588 97.056 51.606 97.2 ;
    END
  END data_i[55]
  PIN data_i[56]
    DIRECTION INPUT ;
    USE SIGNAL ;
    PORT
      LAYER M5 ;
        RECT  52.368 97.008 52.392 97.2 ;
    END
  END data_i[56]
  PIN data_i[57]
    DIRECTION INPUT ;
    USE SIGNAL ;
    PORT
      LAYER M3 ;
        RECT  53.208 97.056 53.226 97.2 ;
    END
  END data_i[57]
  PIN data_i[58]
    DIRECTION INPUT ;
    USE SIGNAL ;
    PORT
      LAYER M5 ;
        RECT  54 97.008 54.024 97.2 ;
    END
  END data_i[58]
  PIN data_i[59]
    DIRECTION INPUT ;
    USE SIGNAL ;
    PORT
      LAYER M3 ;
        RECT  54.792 97.056 54.81 97.2 ;
    END
  END data_i[59]
  PIN data_i[5]
    DIRECTION INPUT ;
    USE SIGNAL ;
    PORT
      LAYER M3 ;
        RECT  11.196 97.056 11.214 97.2 ;
    END
  END data_i[5]
  PIN data_i[60]
    DIRECTION INPUT ;
    USE SIGNAL ;
    PORT
      LAYER M5 ;
        RECT  55.632 97.008 55.656 97.2 ;
    END
  END data_i[60]
  PIN data_i[61]
    DIRECTION INPUT ;
    USE SIGNAL ;
    PORT
      LAYER M3 ;
        RECT  56.412 97.056 56.43 97.2 ;
    END
  END data_i[61]
  PIN data_i[62]
    DIRECTION INPUT ;
    USE SIGNAL ;
    PORT
      LAYER M5 ;
        RECT  57.216 97.008 57.24 97.2 ;
    END
  END data_i[62]
  PIN data_i[63]
    DIRECTION INPUT ;
    USE SIGNAL ;
    PORT
      LAYER M3 ;
        RECT  58.032 97.056 58.05 97.2 ;
    END
  END data_i[63]
  PIN data_i[64]
    DIRECTION INPUT ;
    USE SIGNAL ;
    PORT
      LAYER M5 ;
        RECT  58.848 97.008 58.872 97.2 ;
    END
  END data_i[64]
  PIN data_i[65]
    DIRECTION INPUT ;
    USE SIGNAL ;
    PORT
      LAYER M3 ;
        RECT  59.652 97.056 59.67 97.2 ;
    END
  END data_i[65]
  PIN data_i[66]
    DIRECTION INPUT ;
    USE SIGNAL ;
    PORT
      LAYER M5 ;
        RECT  60.48 97.008 60.504 97.2 ;
    END
  END data_i[66]
  PIN data_i[67]
    DIRECTION INPUT ;
    USE SIGNAL ;
    PORT
      LAYER M3 ;
        RECT  61.272 97.056 61.29 97.2 ;
    END
  END data_i[67]
  PIN data_i[68]
    DIRECTION INPUT ;
    USE SIGNAL ;
    PORT
      LAYER M5 ;
        RECT  62.064 97.008 62.088 97.2 ;
    END
  END data_i[68]
  PIN data_i[69]
    DIRECTION INPUT ;
    USE SIGNAL ;
    PORT
      LAYER M3 ;
        RECT  62.892 97.056 62.91 97.2 ;
    END
  END data_i[69]
  PIN data_i[6]
    DIRECTION INPUT ;
    USE SIGNAL ;
    PORT
      LAYER M5 ;
        RECT  12 97.008 12.024 97.2 ;
    END
  END data_i[6]
  PIN data_i[70]
    DIRECTION INPUT ;
    USE SIGNAL ;
    PORT
      LAYER M5 ;
        RECT  63.696 97.008 63.72 97.2 ;
    END
  END data_i[70]
  PIN data_i[71]
    DIRECTION INPUT ;
    USE SIGNAL ;
    PORT
      LAYER M3 ;
        RECT  64.512 97.056 64.53 97.2 ;
    END
  END data_i[71]
  PIN data_i[72]
    DIRECTION INPUT ;
    USE SIGNAL ;
    PORT
      LAYER M5 ;
        RECT  65.328 97.008 65.352 97.2 ;
    END
  END data_i[72]
  PIN data_i[73]
    DIRECTION INPUT ;
    USE SIGNAL ;
    PORT
      LAYER M3 ;
        RECT  66.132 97.056 66.15 97.2 ;
    END
  END data_i[73]
  PIN data_i[74]
    DIRECTION INPUT ;
    USE SIGNAL ;
    PORT
      LAYER M5 ;
        RECT  66.912 97.008 66.936 97.2 ;
    END
  END data_i[74]
  PIN data_i[75]
    DIRECTION INPUT ;
    USE SIGNAL ;
    PORT
      LAYER M3 ;
        RECT  67.752 97.056 67.77 97.2 ;
    END
  END data_i[75]
  PIN data_i[76]
    DIRECTION INPUT ;
    USE SIGNAL ;
    PORT
      LAYER M5 ;
        RECT  68.544 97.008 68.568 97.2 ;
    END
  END data_i[76]
  PIN data_i[77]
    DIRECTION INPUT ;
    USE SIGNAL ;
    PORT
      LAYER M3 ;
        RECT  69.336 97.056 69.354 97.2 ;
    END
  END data_i[77]
  PIN data_i[78]
    DIRECTION INPUT ;
    USE SIGNAL ;
    PORT
      LAYER M5 ;
        RECT  70.176 97.008 70.2 97.2 ;
    END
  END data_i[78]
  PIN data_i[79]
    DIRECTION INPUT ;
    USE SIGNAL ;
    PORT
      LAYER M3 ;
        RECT  70.956 97.056 70.974 97.2 ;
    END
  END data_i[79]
  PIN data_i[7]
    DIRECTION INPUT ;
    USE SIGNAL ;
    PORT
      LAYER M3 ;
        RECT  12.78 97.056 12.798 97.2 ;
    END
  END data_i[7]
  PIN data_i[80]
    DIRECTION INPUT ;
    USE SIGNAL ;
    PORT
      LAYER M5 ;
        RECT  71.76 97.008 71.784 97.2 ;
    END
  END data_i[80]
  PIN data_i[81]
    DIRECTION INPUT ;
    USE SIGNAL ;
    PORT
      LAYER M3 ;
        RECT  72.576 97.056 72.594 97.2 ;
    END
  END data_i[81]
  PIN data_i[82]
    DIRECTION INPUT ;
    USE SIGNAL ;
    PORT
      LAYER M5 ;
        RECT  73.392 97.008 73.416 97.2 ;
    END
  END data_i[82]
  PIN data_i[83]
    DIRECTION INPUT ;
    USE SIGNAL ;
    PORT
      LAYER M3 ;
        RECT  74.196 97.056 74.214 97.2 ;
    END
  END data_i[83]
  PIN data_i[84]
    DIRECTION INPUT ;
    USE SIGNAL ;
    PORT
      LAYER M5 ;
        RECT  75.024 97.008 75.048 97.2 ;
    END
  END data_i[84]
  PIN data_i[85]
    DIRECTION INPUT ;
    USE SIGNAL ;
    PORT
      LAYER M3 ;
        RECT  75.816 97.056 75.834 97.2 ;
    END
  END data_i[85]
  PIN data_i[86]
    DIRECTION INPUT ;
    USE SIGNAL ;
    PORT
      LAYER M5 ;
        RECT  76.608 97.008 76.632 97.2 ;
    END
  END data_i[86]
  PIN data_i[87]
    DIRECTION INPUT ;
    USE SIGNAL ;
    PORT
      LAYER M3 ;
        RECT  77.436 97.056 77.454 97.2 ;
    END
  END data_i[87]
  PIN data_i[88]
    DIRECTION INPUT ;
    USE SIGNAL ;
    PORT
      LAYER M5 ;
        RECT  78.24 97.008 78.264 97.2 ;
    END
  END data_i[88]
  PIN data_i[89]
    DIRECTION INPUT ;
    USE SIGNAL ;
    PORT
      LAYER M3 ;
        RECT  79.056 97.056 79.074 97.2 ;
    END
  END data_i[89]
  PIN data_i[8]
    DIRECTION INPUT ;
    USE SIGNAL ;
    PORT
      LAYER M5 ;
        RECT  13.584 97.008 13.608 97.2 ;
    END
  END data_i[8]
  PIN data_i[90]
    DIRECTION INPUT ;
    USE SIGNAL ;
    PORT
      LAYER M5 ;
        RECT  79.872 97.008 79.896 97.2 ;
    END
  END data_i[90]
  PIN data_i[91]
    DIRECTION INPUT ;
    USE SIGNAL ;
    PORT
      LAYER M3 ;
        RECT  80.676 97.056 80.694 97.2 ;
    END
  END data_i[91]
  PIN data_i[92]
    DIRECTION INPUT ;
    USE SIGNAL ;
    PORT
      LAYER M5 ;
        RECT  81.456 97.008 81.48 97.2 ;
    END
  END data_i[92]
  PIN data_i[93]
    DIRECTION INPUT ;
    USE SIGNAL ;
    PORT
      LAYER M3 ;
        RECT  82.26 97.056 82.278 97.2 ;
    END
  END data_i[93]
  PIN data_i[94]
    DIRECTION INPUT ;
    USE SIGNAL ;
    PORT
      LAYER M5 ;
        RECT  83.088 97.008 83.112 97.2 ;
    END
  END data_i[94]
  PIN data_i[95]
    DIRECTION INPUT ;
    USE SIGNAL ;
    PORT
      LAYER M3 ;
        RECT  83.88 97.056 83.898 97.2 ;
    END
  END data_i[95]
  PIN data_i[96]
    DIRECTION INPUT ;
    USE SIGNAL ;
    PORT
      LAYER M5 ;
        RECT  84.72 97.008 84.744 97.2 ;
    END
  END data_i[96]
  PIN data_i[97]
    DIRECTION INPUT ;
    USE SIGNAL ;
    PORT
      LAYER M3 ;
        RECT  85.5 97.056 85.518 97.2 ;
    END
  END data_i[97]
  PIN data_i[98]
    DIRECTION INPUT ;
    USE SIGNAL ;
    PORT
      LAYER M5 ;
        RECT  86.304 97.008 86.328 97.2 ;
    END
  END data_i[98]
  PIN data_i[99]
    DIRECTION INPUT ;
    USE SIGNAL ;
    PORT
      LAYER M3 ;
        RECT  87.12 97.056 87.138 97.2 ;
    END
  END data_i[99]
  PIN data_i[9]
    DIRECTION INPUT ;
    USE SIGNAL ;
    PORT
      LAYER M3 ;
        RECT  14.4 97.056 14.418 97.2 ;
    END
  END data_i[9]
  PIN head_o[0]
    DIRECTION OUTPUT ;
    USE SIGNAL ;
    PORT
      LAYER M3 ;
        RECT  4.716 0 4.734 0.144 ;
    END
  END head_o[0]
  PIN head_o[100]
    DIRECTION OUTPUT ;
    USE SIGNAL ;
    PORT
      LAYER M3 ;
        RECT  87.408 0 87.426 0.144 ;
    END
  END head_o[100]
  PIN head_o[101]
    DIRECTION OUTPUT ;
    USE SIGNAL ;
    PORT
      LAYER M5 ;
        RECT  88.224 0 88.248 0.192 ;
    END
  END head_o[101]
  PIN head_o[102]
    DIRECTION OUTPUT ;
    USE SIGNAL ;
    PORT
      LAYER M3 ;
        RECT  89.064 0 89.082 0.144 ;
    END
  END head_o[102]
  PIN head_o[103]
    DIRECTION OUTPUT ;
    USE SIGNAL ;
    PORT
      LAYER M5 ;
        RECT  89.904 0 89.928 0.192 ;
    END
  END head_o[103]
  PIN head_o[104]
    DIRECTION OUTPUT ;
    USE SIGNAL ;
    PORT
      LAYER M3 ;
        RECT  90.72 0 90.738 0.144 ;
    END
  END head_o[104]
  PIN head_o[105]
    DIRECTION OUTPUT ;
    USE SIGNAL ;
    PORT
      LAYER M5 ;
        RECT  91.536 0 91.56 0.192 ;
    END
  END head_o[105]
  PIN head_o[106]
    DIRECTION OUTPUT ;
    USE SIGNAL ;
    PORT
      LAYER M3 ;
        RECT  92.376 0 92.394 0.144 ;
    END
  END head_o[106]
  PIN head_o[107]
    DIRECTION OUTPUT ;
    USE SIGNAL ;
    PORT
      LAYER M5 ;
        RECT  93.216 0 93.24 0.192 ;
    END
  END head_o[107]
  PIN head_o[108]
    DIRECTION OUTPUT ;
    USE SIGNAL ;
    PORT
      LAYER M3 ;
        RECT  94.032 0 94.05 0.144 ;
    END
  END head_o[108]
  PIN head_o[109]
    DIRECTION OUTPUT ;
    USE SIGNAL ;
    PORT
      LAYER M5 ;
        RECT  94.848 0 94.872 0.192 ;
    END
  END head_o[109]
  PIN head_o[10]
    DIRECTION OUTPUT ;
    USE SIGNAL ;
    PORT
      LAYER M3 ;
        RECT  12.996 0 13.014 0.144 ;
    END
  END head_o[10]
  PIN head_o[110]
    DIRECTION OUTPUT ;
    USE SIGNAL ;
    PORT
      LAYER M3 ;
        RECT  95.688 0 95.706 0.144 ;
    END
  END head_o[110]
  PIN head_o[111]
    DIRECTION OUTPUT ;
    USE SIGNAL ;
    PORT
      LAYER M5 ;
        RECT  96.528 0 96.552 0.192 ;
    END
  END head_o[111]
  PIN head_o[112]
    DIRECTION OUTPUT ;
    USE SIGNAL ;
    PORT
      LAYER M3 ;
        RECT  97.344 0 97.362 0.144 ;
    END
  END head_o[112]
  PIN head_o[113]
    DIRECTION OUTPUT ;
    USE SIGNAL ;
    PORT
      LAYER M5 ;
        RECT  98.16 0 98.184 0.192 ;
    END
  END head_o[113]
  PIN head_o[114]
    DIRECTION OUTPUT ;
    USE SIGNAL ;
    PORT
      LAYER M3 ;
        RECT  99 0 99.018 0.144 ;
    END
  END head_o[114]
  PIN head_o[115]
    DIRECTION OUTPUT ;
    USE SIGNAL ;
    PORT
      LAYER M5 ;
        RECT  99.792 0 99.816 0.192 ;
    END
  END head_o[115]
  PIN head_o[116]
    DIRECTION OUTPUT ;
    USE SIGNAL ;
    PORT
      LAYER M3 ;
        RECT  100.656 0 100.674 0.144 ;
    END
  END head_o[116]
  PIN head_o[117]
    DIRECTION OUTPUT ;
    USE SIGNAL ;
    PORT
      LAYER M5 ;
        RECT  101.472 0 101.496 0.192 ;
    END
  END head_o[117]
  PIN head_o[118]
    DIRECTION OUTPUT ;
    USE SIGNAL ;
    PORT
      LAYER M3 ;
        RECT  102.312 0 102.33 0.144 ;
    END
  END head_o[118]
  PIN head_o[119]
    DIRECTION OUTPUT ;
    USE SIGNAL ;
    PORT
      LAYER M5 ;
        RECT  103.104 0 103.128 0.192 ;
    END
  END head_o[119]
  PIN head_o[11]
    DIRECTION OUTPUT ;
    USE SIGNAL ;
    PORT
      LAYER M5 ;
        RECT  13.824 0 13.848 0.192 ;
    END
  END head_o[11]
  PIN head_o[120]
    DIRECTION OUTPUT ;
    USE SIGNAL ;
    PORT
      LAYER M3 ;
        RECT  103.932 0 103.95 0.144 ;
    END
  END head_o[120]
  PIN head_o[121]
    DIRECTION OUTPUT ;
    USE SIGNAL ;
    PORT
      LAYER M5 ;
        RECT  104.784 0 104.808 0.192 ;
    END
  END head_o[121]
  PIN head_o[122]
    DIRECTION OUTPUT ;
    USE SIGNAL ;
    PORT
      LAYER M3 ;
        RECT  105.588 0 105.606 0.144 ;
    END
  END head_o[122]
  PIN head_o[123]
    DIRECTION OUTPUT ;
    USE SIGNAL ;
    PORT
      LAYER M5 ;
        RECT  106.416 0 106.44 0.192 ;
    END
  END head_o[123]
  PIN head_o[124]
    DIRECTION OUTPUT ;
    USE SIGNAL ;
    PORT
      LAYER M3 ;
        RECT  107.244 0 107.262 0.144 ;
    END
  END head_o[124]
  PIN head_o[125]
    DIRECTION OUTPUT ;
    USE SIGNAL ;
    PORT
      LAYER M5 ;
        RECT  108.096 0 108.12 0.192 ;
    END
  END head_o[125]
  PIN head_o[126]
    DIRECTION OUTPUT ;
    USE SIGNAL ;
    PORT
      LAYER M3 ;
        RECT  108.9 0 108.918 0.144 ;
    END
  END head_o[126]
  PIN head_o[127]
    DIRECTION OUTPUT ;
    USE SIGNAL ;
    PORT
      LAYER M5 ;
        RECT  109.728 0 109.752 0.192 ;
    END
  END head_o[127]
  PIN head_o[128]
    DIRECTION OUTPUT ;
    USE SIGNAL ;
    PORT
      LAYER M3 ;
        RECT  110.556 0 110.574 0.144 ;
    END
  END head_o[128]
  PIN head_o[129]
    DIRECTION OUTPUT ;
    USE SIGNAL ;
    PORT
      LAYER M5 ;
        RECT  111.408 0 111.432 0.192 ;
    END
  END head_o[129]
  PIN head_o[12]
    DIRECTION OUTPUT ;
    USE SIGNAL ;
    PORT
      LAYER M3 ;
        RECT  14.652 0 14.67 0.144 ;
    END
  END head_o[12]
  PIN head_o[130]
    DIRECTION OUTPUT ;
    USE SIGNAL ;
    PORT
      LAYER M3 ;
        RECT  112.212 0 112.23 0.144 ;
    END
  END head_o[130]
  PIN head_o[131]
    DIRECTION OUTPUT ;
    USE SIGNAL ;
    PORT
      LAYER M5 ;
        RECT  113.04 0 113.064 0.192 ;
    END
  END head_o[131]
  PIN head_o[132]
    DIRECTION OUTPUT ;
    USE SIGNAL ;
    PORT
      LAYER M3 ;
        RECT  113.868 0 113.886 0.144 ;
    END
  END head_o[132]
  PIN head_o[133]
    DIRECTION OUTPUT ;
    USE SIGNAL ;
    PORT
      LAYER M5 ;
        RECT  114.672 0 114.696 0.192 ;
    END
  END head_o[133]
  PIN head_o[134]
    DIRECTION OUTPUT ;
    USE SIGNAL ;
    PORT
      LAYER M3 ;
        RECT  115.524 0 115.542 0.144 ;
    END
  END head_o[134]
  PIN head_o[135]
    DIRECTION OUTPUT ;
    USE SIGNAL ;
    PORT
      LAYER M5 ;
        RECT  116.352 0 116.376 0.192 ;
    END
  END head_o[135]
  PIN head_o[136]
    DIRECTION OUTPUT ;
    USE SIGNAL ;
    PORT
      LAYER M3 ;
        RECT  117.18 0 117.198 0.144 ;
    END
  END head_o[136]
  PIN head_o[137]
    DIRECTION OUTPUT ;
    USE SIGNAL ;
    PORT
      LAYER M5 ;
        RECT  117.984 0 118.008 0.192 ;
    END
  END head_o[137]
  PIN head_o[138]
    DIRECTION OUTPUT ;
    USE SIGNAL ;
    PORT
      LAYER M3 ;
        RECT  118.836 0 118.854 0.144 ;
    END
  END head_o[138]
  PIN head_o[139]
    DIRECTION OUTPUT ;
    USE SIGNAL ;
    PORT
      LAYER M5 ;
        RECT  119.664 0 119.688 0.192 ;
    END
  END head_o[139]
  PIN head_o[13]
    DIRECTION OUTPUT ;
    USE SIGNAL ;
    PORT
      LAYER M5 ;
        RECT  15.456 0 15.48 0.192 ;
    END
  END head_o[13]
  PIN head_o[140]
    DIRECTION OUTPUT ;
    USE SIGNAL ;
    PORT
      LAYER M3 ;
        RECT  120.492 0 120.51 0.144 ;
    END
  END head_o[140]
  PIN head_o[141]
    DIRECTION OUTPUT ;
    USE SIGNAL ;
    PORT
      LAYER M5 ;
        RECT  121.296 0 121.32 0.192 ;
    END
  END head_o[141]
  PIN head_o[142]
    DIRECTION OUTPUT ;
    USE SIGNAL ;
    PORT
      LAYER M3 ;
        RECT  122.148 0 122.166 0.144 ;
    END
  END head_o[142]
  PIN head_o[143]
    DIRECTION OUTPUT ;
    USE SIGNAL ;
    PORT
      LAYER M5 ;
        RECT  122.976 0 123 0.192 ;
    END
  END head_o[143]
  PIN head_o[144]
    DIRECTION OUTPUT ;
    USE SIGNAL ;
    PORT
      LAYER M3 ;
        RECT  123.804 0 123.822 0.144 ;
    END
  END head_o[144]
  PIN head_o[145]
    DIRECTION OUTPUT ;
    USE SIGNAL ;
    PORT
      LAYER M5 ;
        RECT  124.608 0 124.632 0.192 ;
    END
  END head_o[145]
  PIN head_o[146]
    DIRECTION OUTPUT ;
    USE SIGNAL ;
    PORT
      LAYER M3 ;
        RECT  125.46 0 125.478 0.144 ;
    END
  END head_o[146]
  PIN head_o[147]
    DIRECTION OUTPUT ;
    USE SIGNAL ;
    PORT
      LAYER M5 ;
        RECT  126.288 0 126.312 0.192 ;
    END
  END head_o[147]
  PIN head_o[148]
    DIRECTION OUTPUT ;
    USE SIGNAL ;
    PORT
      LAYER M3 ;
        RECT  127.116 0 127.134 0.144 ;
    END
  END head_o[148]
  PIN head_o[149]
    DIRECTION OUTPUT ;
    USE SIGNAL ;
    PORT
      LAYER M5 ;
        RECT  127.92 0 127.944 0.192 ;
    END
  END head_o[149]
  PIN head_o[14]
    DIRECTION OUTPUT ;
    USE SIGNAL ;
    PORT
      LAYER M3 ;
        RECT  16.308 0 16.326 0.144 ;
    END
  END head_o[14]
  PIN head_o[150]
    DIRECTION OUTPUT ;
    USE SIGNAL ;
    PORT
      LAYER M3 ;
        RECT  128.772 0 128.79 0.144 ;
    END
  END head_o[150]
  PIN head_o[151]
    DIRECTION OUTPUT ;
    USE SIGNAL ;
    PORT
      LAYER M5 ;
        RECT  129.6 0 129.624 0.192 ;
    END
  END head_o[151]
  PIN head_o[152]
    DIRECTION OUTPUT ;
    USE SIGNAL ;
    PORT
      LAYER M3 ;
        RECT  130.392 0 130.41 0.144 ;
    END
  END head_o[152]
  PIN head_o[153]
    DIRECTION OUTPUT ;
    USE SIGNAL ;
    PORT
      LAYER M5 ;
        RECT  131.232 0 131.256 0.192 ;
    END
  END head_o[153]
  PIN head_o[154]
    DIRECTION OUTPUT ;
    USE SIGNAL ;
    PORT
      LAYER M3 ;
        RECT  132.048 0 132.066 0.144 ;
    END
  END head_o[154]
  PIN head_o[155]
    DIRECTION OUTPUT ;
    USE SIGNAL ;
    PORT
      LAYER M5 ;
        RECT  132.864 0 132.888 0.192 ;
    END
  END head_o[155]
  PIN head_o[156]
    DIRECTION OUTPUT ;
    USE SIGNAL ;
    PORT
      LAYER M3 ;
        RECT  133.704 0 133.722 0.144 ;
    END
  END head_o[156]
  PIN head_o[157]
    DIRECTION OUTPUT ;
    USE SIGNAL ;
    PORT
      LAYER M5 ;
        RECT  134.544 0 134.568 0.192 ;
    END
  END head_o[157]
  PIN head_o[158]
    DIRECTION OUTPUT ;
    USE SIGNAL ;
    PORT
      LAYER M3 ;
        RECT  135.36 0 135.378 0.144 ;
    END
  END head_o[158]
  PIN head_o[159]
    DIRECTION OUTPUT ;
    USE SIGNAL ;
    PORT
      LAYER M5 ;
        RECT  136.176 0 136.2 0.192 ;
    END
  END head_o[159]
  PIN head_o[15]
    DIRECTION OUTPUT ;
    USE SIGNAL ;
    PORT
      LAYER M5 ;
        RECT  17.136 0 17.16 0.192 ;
    END
  END head_o[15]
  PIN head_o[160]
    DIRECTION OUTPUT ;
    USE SIGNAL ;
    PORT
      LAYER M3 ;
        RECT  137.016 0 137.034 0.144 ;
    END
  END head_o[160]
  PIN head_o[161]
    DIRECTION OUTPUT ;
    USE SIGNAL ;
    PORT
      LAYER M5 ;
        RECT  137.856 0 137.88 0.192 ;
    END
  END head_o[161]
  PIN head_o[162]
    DIRECTION OUTPUT ;
    USE SIGNAL ;
    PORT
      LAYER M3 ;
        RECT  138.672 0 138.69 0.144 ;
    END
  END head_o[162]
  PIN head_o[163]
    DIRECTION OUTPUT ;
    USE SIGNAL ;
    PORT
      LAYER M5 ;
        RECT  139.488 0 139.512 0.192 ;
    END
  END head_o[163]
  PIN head_o[164]
    DIRECTION OUTPUT ;
    USE SIGNAL ;
    PORT
      LAYER M3 ;
        RECT  140.328 0 140.346 0.144 ;
    END
  END head_o[164]
  PIN head_o[165]
    DIRECTION OUTPUT ;
    USE SIGNAL ;
    PORT
      LAYER M5 ;
        RECT  141.168 0 141.192 0.192 ;
    END
  END head_o[165]
  PIN head_o[166]
    DIRECTION OUTPUT ;
    USE SIGNAL ;
    PORT
      LAYER M3 ;
        RECT  141.984 0 142.002 0.144 ;
    END
  END head_o[166]
  PIN head_o[167]
    DIRECTION OUTPUT ;
    USE SIGNAL ;
    PORT
      LAYER M5 ;
        RECT  142.8 0 142.824 0.192 ;
    END
  END head_o[167]
  PIN head_o[168]
    DIRECTION OUTPUT ;
    USE SIGNAL ;
    PORT
      LAYER M3 ;
        RECT  143.64 0 143.658 0.144 ;
    END
  END head_o[168]
  PIN head_o[169]
    DIRECTION OUTPUT ;
    USE SIGNAL ;
    PORT
      LAYER M5 ;
        RECT  144.48 0 144.504 0.192 ;
    END
  END head_o[169]
  PIN head_o[16]
    DIRECTION OUTPUT ;
    USE SIGNAL ;
    PORT
      LAYER M3 ;
        RECT  17.964 0 17.982 0.144 ;
    END
  END head_o[16]
  PIN head_o[170]
    DIRECTION OUTPUT ;
    USE SIGNAL ;
    PORT
      LAYER M3 ;
        RECT  145.296 0 145.314 0.144 ;
    END
  END head_o[170]
  PIN head_o[171]
    DIRECTION OUTPUT ;
    USE SIGNAL ;
    PORT
      LAYER M5 ;
        RECT  146.112 0 146.136 0.192 ;
    END
  END head_o[171]
  PIN head_o[172]
    DIRECTION OUTPUT ;
    USE SIGNAL ;
    PORT
      LAYER M3 ;
        RECT  146.952 0 146.97 0.144 ;
    END
  END head_o[172]
  PIN head_o[173]
    DIRECTION OUTPUT ;
    USE SIGNAL ;
    PORT
      LAYER M5 ;
        RECT  147.792 0 147.816 0.192 ;
    END
  END head_o[173]
  PIN head_o[174]
    DIRECTION OUTPUT ;
    USE SIGNAL ;
    PORT
      LAYER M3 ;
        RECT  148.608 0 148.626 0.144 ;
    END
  END head_o[174]
  PIN head_o[175]
    DIRECTION OUTPUT ;
    USE SIGNAL ;
    PORT
      LAYER M5 ;
        RECT  149.424 0 149.448 0.192 ;
    END
  END head_o[175]
  PIN head_o[176]
    DIRECTION OUTPUT ;
    USE SIGNAL ;
    PORT
      LAYER M3 ;
        RECT  150.264 0 150.282 0.144 ;
    END
  END head_o[176]
  PIN head_o[177]
    DIRECTION OUTPUT ;
    USE SIGNAL ;
    PORT
      LAYER M5 ;
        RECT  151.056 0 151.08 0.192 ;
    END
  END head_o[177]
  PIN head_o[178]
    DIRECTION OUTPUT ;
    USE SIGNAL ;
    PORT
      LAYER M3 ;
        RECT  151.92 0 151.938 0.144 ;
    END
  END head_o[178]
  PIN head_o[179]
    DIRECTION OUTPUT ;
    USE SIGNAL ;
    PORT
      LAYER M5 ;
        RECT  152.736 0 152.76 0.192 ;
    END
  END head_o[179]
  PIN head_o[17]
    DIRECTION OUTPUT ;
    USE SIGNAL ;
    PORT
      LAYER M5 ;
        RECT  18.768 0 18.792 0.192 ;
    END
  END head_o[17]
  PIN head_o[180]
    DIRECTION OUTPUT ;
    USE SIGNAL ;
    PORT
      LAYER M3 ;
        RECT  153.576 0 153.594 0.144 ;
    END
  END head_o[180]
  PIN head_o[181]
    DIRECTION OUTPUT ;
    USE SIGNAL ;
    PORT
      LAYER M5 ;
        RECT  154.368 0 154.392 0.192 ;
    END
  END head_o[181]
  PIN head_o[182]
    DIRECTION OUTPUT ;
    USE SIGNAL ;
    PORT
      LAYER M3 ;
        RECT  155.232 0 155.25 0.144 ;
    END
  END head_o[182]
  PIN head_o[183]
    DIRECTION OUTPUT ;
    USE SIGNAL ;
    PORT
      LAYER M5 ;
        RECT  156.048 0 156.072 0.192 ;
    END
  END head_o[183]
  PIN head_o[184]
    DIRECTION OUTPUT ;
    USE SIGNAL ;
    PORT
      LAYER M3 ;
        RECT  156.852 0 156.87 0.144 ;
    END
  END head_o[184]
  PIN head_o[185]
    DIRECTION OUTPUT ;
    USE SIGNAL ;
    PORT
      LAYER M5 ;
        RECT  157.68 0 157.704 0.192 ;
    END
  END head_o[185]
  PIN head_o[186]
    DIRECTION OUTPUT ;
    USE SIGNAL ;
    PORT
      LAYER M3 ;
        RECT  158.508 0 158.526 0.144 ;
    END
  END head_o[186]
  PIN head_o[187]
    DIRECTION OUTPUT ;
    USE SIGNAL ;
    PORT
      LAYER M5 ;
        RECT  159.36 0 159.384 0.192 ;
    END
  END head_o[187]
  PIN head_o[188]
    DIRECTION OUTPUT ;
    USE SIGNAL ;
    PORT
      LAYER M3 ;
        RECT  160.164 0 160.182 0.144 ;
    END
  END head_o[188]
  PIN head_o[189]
    DIRECTION OUTPUT ;
    USE SIGNAL ;
    PORT
      LAYER M5 ;
        RECT  160.992 0 161.016 0.192 ;
    END
  END head_o[189]
  PIN head_o[18]
    DIRECTION OUTPUT ;
    USE SIGNAL ;
    PORT
      LAYER M3 ;
        RECT  19.62 0 19.638 0.144 ;
    END
  END head_o[18]
  PIN head_o[190]
    DIRECTION OUTPUT ;
    USE SIGNAL ;
    PORT
      LAYER M3 ;
        RECT  161.82 0 161.838 0.144 ;
    END
  END head_o[190]
  PIN head_o[191]
    DIRECTION OUTPUT ;
    USE SIGNAL ;
    PORT
      LAYER M5 ;
        RECT  162.672 0 162.696 0.192 ;
    END
  END head_o[191]
  PIN head_o[192]
    DIRECTION OUTPUT ;
    USE SIGNAL ;
    PORT
      LAYER M3 ;
        RECT  163.476 0 163.494 0.144 ;
    END
  END head_o[192]
  PIN head_o[193]
    DIRECTION OUTPUT ;
    USE SIGNAL ;
    PORT
      LAYER M5 ;
        RECT  164.304 0 164.328 0.192 ;
    END
  END head_o[193]
  PIN head_o[194]
    DIRECTION OUTPUT ;
    USE SIGNAL ;
    PORT
      LAYER M3 ;
        RECT  165.132 0 165.15 0.144 ;
    END
  END head_o[194]
  PIN head_o[195]
    DIRECTION OUTPUT ;
    USE SIGNAL ;
    PORT
      LAYER M5 ;
        RECT  165.984 0 166.008 0.192 ;
    END
  END head_o[195]
  PIN head_o[196]
    DIRECTION OUTPUT ;
    USE SIGNAL ;
    PORT
      LAYER M3 ;
        RECT  166.788 0 166.806 0.144 ;
    END
  END head_o[196]
  PIN head_o[197]
    DIRECTION OUTPUT ;
    USE SIGNAL ;
    PORT
      LAYER M5 ;
        RECT  167.616 0 167.64 0.192 ;
    END
  END head_o[197]
  PIN head_o[198]
    DIRECTION OUTPUT ;
    USE SIGNAL ;
    PORT
      LAYER M3 ;
        RECT  168.444 0 168.462 0.144 ;
    END
  END head_o[198]
  PIN head_o[199]
    DIRECTION OUTPUT ;
    USE SIGNAL ;
    PORT
      LAYER M5 ;
        RECT  169.248 0 169.272 0.192 ;
    END
  END head_o[199]
  PIN head_o[19]
    DIRECTION OUTPUT ;
    USE SIGNAL ;
    PORT
      LAYER M5 ;
        RECT  20.448 0 20.472 0.192 ;
    END
  END head_o[19]
  PIN head_o[1]
    DIRECTION OUTPUT ;
    USE SIGNAL ;
    PORT
      LAYER M5 ;
        RECT  5.568 0 5.592 0.192 ;
    END
  END head_o[1]
  PIN head_o[200]
    DIRECTION OUTPUT ;
    USE SIGNAL ;
    PORT
      LAYER M3 ;
        RECT  170.1 0 170.118 0.144 ;
    END
  END head_o[200]
  PIN head_o[201]
    DIRECTION OUTPUT ;
    USE SIGNAL ;
    PORT
      LAYER M5 ;
        RECT  170.928 0 170.952 0.192 ;
    END
  END head_o[201]
  PIN head_o[202]
    DIRECTION OUTPUT ;
    USE SIGNAL ;
    PORT
      LAYER M3 ;
        RECT  171.756 0 171.774 0.144 ;
    END
  END head_o[202]
  PIN head_o[203]
    DIRECTION OUTPUT ;
    USE SIGNAL ;
    PORT
      LAYER M5 ;
        RECT  172.56 0 172.584 0.192 ;
    END
  END head_o[203]
  PIN head_o[204]
    DIRECTION OUTPUT ;
    USE SIGNAL ;
    PORT
      LAYER M3 ;
        RECT  173.412 0 173.43 0.144 ;
    END
  END head_o[204]
  PIN head_o[205]
    DIRECTION OUTPUT ;
    USE SIGNAL ;
    PORT
      LAYER M5 ;
        RECT  174.24 0 174.264 0.192 ;
    END
  END head_o[205]
  PIN head_o[206]
    DIRECTION OUTPUT ;
    USE SIGNAL ;
    PORT
      LAYER M3 ;
        RECT  175.068 0 175.086 0.144 ;
    END
  END head_o[206]
  PIN head_o[207]
    DIRECTION OUTPUT ;
    USE SIGNAL ;
    PORT
      LAYER M5 ;
        RECT  175.872 0 175.896 0.192 ;
    END
  END head_o[207]
  PIN head_o[208]
    DIRECTION OUTPUT ;
    USE SIGNAL ;
    PORT
      LAYER M3 ;
        RECT  176.724 0 176.742 0.144 ;
    END
  END head_o[208]
  PIN head_o[209]
    DIRECTION OUTPUT ;
    USE SIGNAL ;
    PORT
      LAYER M5 ;
        RECT  177.552 0 177.576 0.192 ;
    END
  END head_o[209]
  PIN head_o[20]
    DIRECTION OUTPUT ;
    USE SIGNAL ;
    PORT
      LAYER M3 ;
        RECT  21.276 0 21.294 0.144 ;
    END
  END head_o[20]
  PIN head_o[210]
    DIRECTION OUTPUT ;
    USE SIGNAL ;
    PORT
      LAYER M3 ;
        RECT  178.38 0 178.398 0.144 ;
    END
  END head_o[210]
  PIN head_o[211]
    DIRECTION OUTPUT ;
    USE SIGNAL ;
    PORT
      LAYER M5 ;
        RECT  179.184 0 179.208 0.192 ;
    END
  END head_o[211]
  PIN head_o[212]
    DIRECTION OUTPUT ;
    USE SIGNAL ;
    PORT
      LAYER M3 ;
        RECT  180.036 0 180.054 0.144 ;
    END
  END head_o[212]
  PIN head_o[213]
    DIRECTION OUTPUT ;
    USE SIGNAL ;
    PORT
      LAYER M5 ;
        RECT  180.864 0 180.888 0.192 ;
    END
  END head_o[213]
  PIN head_o[214]
    DIRECTION OUTPUT ;
    USE SIGNAL ;
    PORT
      LAYER M3 ;
        RECT  181.692 0 181.71 0.144 ;
    END
  END head_o[214]
  PIN head_o[215]
    DIRECTION OUTPUT ;
    USE SIGNAL ;
    PORT
      LAYER M5 ;
        RECT  182.496 0 182.52 0.192 ;
    END
  END head_o[215]
  PIN head_o[216]
    DIRECTION OUTPUT ;
    USE SIGNAL ;
    PORT
      LAYER M3 ;
        RECT  183.312 0 183.33 0.144 ;
    END
  END head_o[216]
  PIN head_o[217]
    DIRECTION OUTPUT ;
    USE SIGNAL ;
    PORT
      LAYER M5 ;
        RECT  184.176 0 184.2 0.192 ;
    END
  END head_o[217]
  PIN head_o[218]
    DIRECTION OUTPUT ;
    USE SIGNAL ;
    PORT
      LAYER M3 ;
        RECT  184.968 0 184.986 0.144 ;
    END
  END head_o[218]
  PIN head_o[219]
    DIRECTION OUTPUT ;
    USE SIGNAL ;
    PORT
      LAYER M5 ;
        RECT  185.808 0 185.832 0.192 ;
    END
  END head_o[219]
  PIN head_o[21]
    DIRECTION OUTPUT ;
    USE SIGNAL ;
    PORT
      LAYER M5 ;
        RECT  22.08 0 22.104 0.192 ;
    END
  END head_o[21]
  PIN head_o[220]
    DIRECTION OUTPUT ;
    USE SIGNAL ;
    PORT
      LAYER M3 ;
        RECT  186.624 0 186.642 0.144 ;
    END
  END head_o[220]
  PIN head_o[221]
    DIRECTION OUTPUT ;
    USE SIGNAL ;
    PORT
      LAYER M5 ;
        RECT  187.44 0 187.464 0.192 ;
    END
  END head_o[221]
  PIN head_o[222]
    DIRECTION OUTPUT ;
    USE SIGNAL ;
    PORT
      LAYER M3 ;
        RECT  188.28 0 188.298 0.144 ;
    END
  END head_o[222]
  PIN head_o[223]
    DIRECTION OUTPUT ;
    USE SIGNAL ;
    PORT
      LAYER M5 ;
        RECT  189.12 0 189.144 0.192 ;
    END
  END head_o[223]
  PIN head_o[224]
    DIRECTION OUTPUT ;
    USE SIGNAL ;
    PORT
      LAYER M3 ;
        RECT  189.936 0 189.954 0.144 ;
    END
  END head_o[224]
  PIN head_o[225]
    DIRECTION OUTPUT ;
    USE SIGNAL ;
    PORT
      LAYER M5 ;
        RECT  190.752 0 190.776 0.192 ;
    END
  END head_o[225]
  PIN head_o[226]
    DIRECTION OUTPUT ;
    USE SIGNAL ;
    PORT
      LAYER M3 ;
        RECT  191.592 0 191.61 0.144 ;
    END
  END head_o[226]
  PIN head_o[227]
    DIRECTION OUTPUT ;
    USE SIGNAL ;
    PORT
      LAYER M5 ;
        RECT  192.432 0 192.456 0.192 ;
    END
  END head_o[227]
  PIN head_o[228]
    DIRECTION OUTPUT ;
    USE SIGNAL ;
    PORT
      LAYER M3 ;
        RECT  193.248 0 193.266 0.144 ;
    END
  END head_o[228]
  PIN head_o[229]
    DIRECTION OUTPUT ;
    USE SIGNAL ;
    PORT
      LAYER M5 ;
        RECT  194.064 0 194.088 0.192 ;
    END
  END head_o[229]
  PIN head_o[22]
    DIRECTION OUTPUT ;
    USE SIGNAL ;
    PORT
      LAYER M3 ;
        RECT  22.932 0 22.95 0.144 ;
    END
  END head_o[22]
  PIN head_o[230]
    DIRECTION OUTPUT ;
    USE SIGNAL ;
    PORT
      LAYER M3 ;
        RECT  194.904 0 194.922 0.144 ;
    END
  END head_o[230]
  PIN head_o[231]
    DIRECTION OUTPUT ;
    USE SIGNAL ;
    PORT
      LAYER M5 ;
        RECT  195.744 0 195.768 0.192 ;
    END
  END head_o[231]
  PIN head_o[232]
    DIRECTION OUTPUT ;
    USE SIGNAL ;
    PORT
      LAYER M3 ;
        RECT  196.56 0 196.578 0.144 ;
    END
  END head_o[232]
  PIN head_o[233]
    DIRECTION OUTPUT ;
    USE SIGNAL ;
    PORT
      LAYER M5 ;
        RECT  197.376 0 197.4 0.192 ;
    END
  END head_o[233]
  PIN head_o[234]
    DIRECTION OUTPUT ;
    USE SIGNAL ;
    PORT
      LAYER M3 ;
        RECT  198.216 0 198.234 0.144 ;
    END
  END head_o[234]
  PIN head_o[235]
    DIRECTION OUTPUT ;
    USE SIGNAL ;
    PORT
      LAYER M5 ;
        RECT  199.056 0 199.08 0.192 ;
    END
  END head_o[235]
  PIN head_o[236]
    DIRECTION OUTPUT ;
    USE SIGNAL ;
    PORT
      LAYER M3 ;
        RECT  199.872 0 199.89 0.144 ;
    END
  END head_o[236]
  PIN head_o[237]
    DIRECTION OUTPUT ;
    USE SIGNAL ;
    PORT
      LAYER M5 ;
        RECT  200.688 0 200.712 0.192 ;
    END
  END head_o[237]
  PIN head_o[238]
    DIRECTION OUTPUT ;
    USE SIGNAL ;
    PORT
      LAYER M3 ;
        RECT  201.528 0 201.546 0.144 ;
    END
  END head_o[238]
  PIN head_o[239]
    DIRECTION OUTPUT ;
    USE SIGNAL ;
    PORT
      LAYER M5 ;
        RECT  202.368 0 202.392 0.192 ;
    END
  END head_o[239]
  PIN head_o[23]
    DIRECTION OUTPUT ;
    USE SIGNAL ;
    PORT
      LAYER M5 ;
        RECT  23.76 0 23.784 0.192 ;
    END
  END head_o[23]
  PIN head_o[240]
    DIRECTION OUTPUT ;
    USE SIGNAL ;
    PORT
      LAYER M3 ;
        RECT  203.184 0 203.202 0.144 ;
    END
  END head_o[240]
  PIN head_o[241]
    DIRECTION OUTPUT ;
    USE SIGNAL ;
    PORT
      LAYER M5 ;
        RECT  204 0 204.024 0.192 ;
    END
  END head_o[241]
  PIN head_o[242]
    DIRECTION OUTPUT ;
    USE SIGNAL ;
    PORT
      LAYER M3 ;
        RECT  204.84 0 204.858 0.144 ;
    END
  END head_o[242]
  PIN head_o[243]
    DIRECTION OUTPUT ;
    USE SIGNAL ;
    PORT
      LAYER M5 ;
        RECT  205.632 0 205.656 0.192 ;
    END
  END head_o[243]
  PIN head_o[244]
    DIRECTION OUTPUT ;
    USE SIGNAL ;
    PORT
      LAYER M3 ;
        RECT  206.496 0 206.514 0.144 ;
    END
  END head_o[244]
  PIN head_o[245]
    DIRECTION OUTPUT ;
    USE SIGNAL ;
    PORT
      LAYER M5 ;
        RECT  207.312 0 207.336 0.192 ;
    END
  END head_o[245]
  PIN head_o[246]
    DIRECTION OUTPUT ;
    USE SIGNAL ;
    PORT
      LAYER M3 ;
        RECT  208.152 0 208.17 0.144 ;
    END
  END head_o[246]
  PIN head_o[247]
    DIRECTION OUTPUT ;
    USE SIGNAL ;
    PORT
      LAYER M5 ;
        RECT  208.944 0 208.968 0.192 ;
    END
  END head_o[247]
  PIN head_o[248]
    DIRECTION OUTPUT ;
    USE SIGNAL ;
    PORT
      LAYER M3 ;
        RECT  209.772 0 209.79 0.144 ;
    END
  END head_o[248]
  PIN head_o[249]
    DIRECTION OUTPUT ;
    USE SIGNAL ;
    PORT
      LAYER M5 ;
        RECT  210.624 0 210.648 0.192 ;
    END
  END head_o[249]
  PIN head_o[24]
    DIRECTION OUTPUT ;
    USE SIGNAL ;
    PORT
      LAYER M3 ;
        RECT  24.552 0 24.57 0.144 ;
    END
  END head_o[24]
  PIN head_o[250]
    DIRECTION OUTPUT ;
    USE SIGNAL ;
    PORT
      LAYER M3 ;
        RECT  211.428 0 211.446 0.144 ;
    END
  END head_o[250]
  PIN head_o[251]
    DIRECTION OUTPUT ;
    USE SIGNAL ;
    PORT
      LAYER M5 ;
        RECT  212.256 0 212.28 0.192 ;
    END
  END head_o[251]
  PIN head_o[252]
    DIRECTION OUTPUT ;
    USE SIGNAL ;
    PORT
      LAYER M3 ;
        RECT  213.084 0 213.102 0.144 ;
    END
  END head_o[252]
  PIN head_o[253]
    DIRECTION OUTPUT ;
    USE SIGNAL ;
    PORT
      LAYER M5 ;
        RECT  213.936 0 213.96 0.192 ;
    END
  END head_o[253]
  PIN head_o[254]
    DIRECTION OUTPUT ;
    USE SIGNAL ;
    PORT
      LAYER M3 ;
        RECT  214.74 0 214.758 0.144 ;
    END
  END head_o[254]
  PIN head_o[255]
    DIRECTION OUTPUT ;
    USE SIGNAL ;
    PORT
      LAYER M5 ;
        RECT  215.568 0 215.592 0.192 ;
    END
  END head_o[255]
  PIN head_o[25]
    DIRECTION OUTPUT ;
    USE SIGNAL ;
    PORT
      LAYER M5 ;
        RECT  25.392 0 25.416 0.192 ;
    END
  END head_o[25]
  PIN head_o[26]
    DIRECTION OUTPUT ;
    USE SIGNAL ;
    PORT
      LAYER M3 ;
        RECT  26.208 0 26.226 0.144 ;
    END
  END head_o[26]
  PIN head_o[27]
    DIRECTION OUTPUT ;
    USE SIGNAL ;
    PORT
      LAYER M5 ;
        RECT  27.024 0 27.048 0.192 ;
    END
  END head_o[27]
  PIN head_o[28]
    DIRECTION OUTPUT ;
    USE SIGNAL ;
    PORT
      LAYER M3 ;
        RECT  27.864 0 27.882 0.144 ;
    END
  END head_o[28]
  PIN head_o[29]
    DIRECTION OUTPUT ;
    USE SIGNAL ;
    PORT
      LAYER M5 ;
        RECT  28.704 0 28.728 0.192 ;
    END
  END head_o[29]
  PIN head_o[2]
    DIRECTION OUTPUT ;
    USE SIGNAL ;
    PORT
      LAYER M3 ;
        RECT  6.372 0 6.39 0.144 ;
    END
  END head_o[2]
  PIN head_o[30]
    DIRECTION OUTPUT ;
    USE SIGNAL ;
    PORT
      LAYER M3 ;
        RECT  29.52 0 29.538 0.144 ;
    END
  END head_o[30]
  PIN head_o[31]
    DIRECTION OUTPUT ;
    USE SIGNAL ;
    PORT
      LAYER M5 ;
        RECT  30.336 0 30.36 0.192 ;
    END
  END head_o[31]
  PIN head_o[32]
    DIRECTION OUTPUT ;
    USE SIGNAL ;
    PORT
      LAYER M3 ;
        RECT  31.176 0 31.194 0.144 ;
    END
  END head_o[32]
  PIN head_o[33]
    DIRECTION OUTPUT ;
    USE SIGNAL ;
    PORT
      LAYER M5 ;
        RECT  32.016 0 32.04 0.192 ;
    END
  END head_o[33]
  PIN head_o[34]
    DIRECTION OUTPUT ;
    USE SIGNAL ;
    PORT
      LAYER M3 ;
        RECT  32.832 0 32.85 0.144 ;
    END
  END head_o[34]
  PIN head_o[35]
    DIRECTION OUTPUT ;
    USE SIGNAL ;
    PORT
      LAYER M5 ;
        RECT  33.648 0 33.672 0.192 ;
    END
  END head_o[35]
  PIN head_o[36]
    DIRECTION OUTPUT ;
    USE SIGNAL ;
    PORT
      LAYER M3 ;
        RECT  34.488 0 34.506 0.144 ;
    END
  END head_o[36]
  PIN head_o[37]
    DIRECTION OUTPUT ;
    USE SIGNAL ;
    PORT
      LAYER M5 ;
        RECT  35.328 0 35.352 0.192 ;
    END
  END head_o[37]
  PIN head_o[38]
    DIRECTION OUTPUT ;
    USE SIGNAL ;
    PORT
      LAYER M3 ;
        RECT  36.144 0 36.162 0.144 ;
    END
  END head_o[38]
  PIN head_o[39]
    DIRECTION OUTPUT ;
    USE SIGNAL ;
    PORT
      LAYER M5 ;
        RECT  36.96 0 36.984 0.192 ;
    END
  END head_o[39]
  PIN head_o[3]
    DIRECTION OUTPUT ;
    USE SIGNAL ;
    PORT
      LAYER M5 ;
        RECT  7.2 0 7.224 0.192 ;
    END
  END head_o[3]
  PIN head_o[40]
    DIRECTION OUTPUT ;
    USE SIGNAL ;
    PORT
      LAYER M3 ;
        RECT  37.8 0 37.818 0.144 ;
    END
  END head_o[40]
  PIN head_o[41]
    DIRECTION OUTPUT ;
    USE SIGNAL ;
    PORT
      LAYER M5 ;
        RECT  38.64 0 38.664 0.192 ;
    END
  END head_o[41]
  PIN head_o[42]
    DIRECTION OUTPUT ;
    USE SIGNAL ;
    PORT
      LAYER M3 ;
        RECT  39.456 0 39.474 0.144 ;
    END
  END head_o[42]
  PIN head_o[43]
    DIRECTION OUTPUT ;
    USE SIGNAL ;
    PORT
      LAYER M5 ;
        RECT  40.272 0 40.296 0.192 ;
    END
  END head_o[43]
  PIN head_o[44]
    DIRECTION OUTPUT ;
    USE SIGNAL ;
    PORT
      LAYER M3 ;
        RECT  41.112 0 41.13 0.144 ;
    END
  END head_o[44]
  PIN head_o[45]
    DIRECTION OUTPUT ;
    USE SIGNAL ;
    PORT
      LAYER M5 ;
        RECT  41.952 0 41.976 0.192 ;
    END
  END head_o[45]
  PIN head_o[46]
    DIRECTION OUTPUT ;
    USE SIGNAL ;
    PORT
      LAYER M3 ;
        RECT  42.768 0 42.786 0.144 ;
    END
  END head_o[46]
  PIN head_o[47]
    DIRECTION OUTPUT ;
    USE SIGNAL ;
    PORT
      LAYER M5 ;
        RECT  43.584 0 43.608 0.192 ;
    END
  END head_o[47]
  PIN head_o[48]
    DIRECTION OUTPUT ;
    USE SIGNAL ;
    PORT
      LAYER M3 ;
        RECT  44.424 0 44.442 0.144 ;
    END
  END head_o[48]
  PIN head_o[49]
    DIRECTION OUTPUT ;
    USE SIGNAL ;
    PORT
      LAYER M5 ;
        RECT  45.216 0 45.24 0.192 ;
    END
  END head_o[49]
  PIN head_o[4]
    DIRECTION OUTPUT ;
    USE SIGNAL ;
    PORT
      LAYER M3 ;
        RECT  8.028 0 8.046 0.144 ;
    END
  END head_o[4]
  PIN head_o[50]
    DIRECTION OUTPUT ;
    USE SIGNAL ;
    PORT
      LAYER M3 ;
        RECT  46.08 0 46.098 0.144 ;
    END
  END head_o[50]
  PIN head_o[51]
    DIRECTION OUTPUT ;
    USE SIGNAL ;
    PORT
      LAYER M5 ;
        RECT  46.896 0 46.92 0.192 ;
    END
  END head_o[51]
  PIN head_o[52]
    DIRECTION OUTPUT ;
    USE SIGNAL ;
    PORT
      LAYER M3 ;
        RECT  47.736 0 47.754 0.144 ;
    END
  END head_o[52]
  PIN head_o[53]
    DIRECTION OUTPUT ;
    USE SIGNAL ;
    PORT
      LAYER M5 ;
        RECT  48.528 0 48.552 0.192 ;
    END
  END head_o[53]
  PIN head_o[54]
    DIRECTION OUTPUT ;
    USE SIGNAL ;
    PORT
      LAYER M3 ;
        RECT  49.392 0 49.41 0.144 ;
    END
  END head_o[54]
  PIN head_o[55]
    DIRECTION OUTPUT ;
    USE SIGNAL ;
    PORT
      LAYER M5 ;
        RECT  50.208 0 50.232 0.192 ;
    END
  END head_o[55]
  PIN head_o[56]
    DIRECTION OUTPUT ;
    USE SIGNAL ;
    PORT
      LAYER M3 ;
        RECT  51.012 0 51.03 0.144 ;
    END
  END head_o[56]
  PIN head_o[57]
    DIRECTION OUTPUT ;
    USE SIGNAL ;
    PORT
      LAYER M5 ;
        RECT  51.84 0 51.864 0.192 ;
    END
  END head_o[57]
  PIN head_o[58]
    DIRECTION OUTPUT ;
    USE SIGNAL ;
    PORT
      LAYER M3 ;
        RECT  52.668 0 52.686 0.144 ;
    END
  END head_o[58]
  PIN head_o[59]
    DIRECTION OUTPUT ;
    USE SIGNAL ;
    PORT
      LAYER M5 ;
        RECT  53.52 0 53.544 0.192 ;
    END
  END head_o[59]
  PIN head_o[5]
    DIRECTION OUTPUT ;
    USE SIGNAL ;
    PORT
      LAYER M5 ;
        RECT  8.832 0 8.856 0.192 ;
    END
  END head_o[5]
  PIN head_o[60]
    DIRECTION OUTPUT ;
    USE SIGNAL ;
    PORT
      LAYER M3 ;
        RECT  54.324 0 54.342 0.144 ;
    END
  END head_o[60]
  PIN head_o[61]
    DIRECTION OUTPUT ;
    USE SIGNAL ;
    PORT
      LAYER M5 ;
        RECT  55.152 0 55.176 0.192 ;
    END
  END head_o[61]
  PIN head_o[62]
    DIRECTION OUTPUT ;
    USE SIGNAL ;
    PORT
      LAYER M3 ;
        RECT  55.98 0 55.998 0.144 ;
    END
  END head_o[62]
  PIN head_o[63]
    DIRECTION OUTPUT ;
    USE SIGNAL ;
    PORT
      LAYER M5 ;
        RECT  56.832 0 56.856 0.192 ;
    END
  END head_o[63]
  PIN head_o[64]
    DIRECTION OUTPUT ;
    USE SIGNAL ;
    PORT
      LAYER M3 ;
        RECT  57.636 0 57.654 0.144 ;
    END
  END head_o[64]
  PIN head_o[65]
    DIRECTION OUTPUT ;
    USE SIGNAL ;
    PORT
      LAYER M5 ;
        RECT  58.464 0 58.488 0.192 ;
    END
  END head_o[65]
  PIN head_o[66]
    DIRECTION OUTPUT ;
    USE SIGNAL ;
    PORT
      LAYER M3 ;
        RECT  59.292 0 59.31 0.144 ;
    END
  END head_o[66]
  PIN head_o[67]
    DIRECTION OUTPUT ;
    USE SIGNAL ;
    PORT
      LAYER M5 ;
        RECT  60.144 0 60.168 0.192 ;
    END
  END head_o[67]
  PIN head_o[68]
    DIRECTION OUTPUT ;
    USE SIGNAL ;
    PORT
      LAYER M3 ;
        RECT  60.948 0 60.966 0.144 ;
    END
  END head_o[68]
  PIN head_o[69]
    DIRECTION OUTPUT ;
    USE SIGNAL ;
    PORT
      LAYER M5 ;
        RECT  61.776 0 61.8 0.192 ;
    END
  END head_o[69]
  PIN head_o[6]
    DIRECTION OUTPUT ;
    USE SIGNAL ;
    PORT
      LAYER M3 ;
        RECT  9.684 0 9.702 0.144 ;
    END
  END head_o[6]
  PIN head_o[70]
    DIRECTION OUTPUT ;
    USE SIGNAL ;
    PORT
      LAYER M3 ;
        RECT  62.604 0 62.622 0.144 ;
    END
  END head_o[70]
  PIN head_o[71]
    DIRECTION OUTPUT ;
    USE SIGNAL ;
    PORT
      LAYER M5 ;
        RECT  63.408 0 63.432 0.192 ;
    END
  END head_o[71]
  PIN head_o[72]
    DIRECTION OUTPUT ;
    USE SIGNAL ;
    PORT
      LAYER M3 ;
        RECT  64.26 0 64.278 0.144 ;
    END
  END head_o[72]
  PIN head_o[73]
    DIRECTION OUTPUT ;
    USE SIGNAL ;
    PORT
      LAYER M5 ;
        RECT  65.088 0 65.112 0.192 ;
    END
  END head_o[73]
  PIN head_o[74]
    DIRECTION OUTPUT ;
    USE SIGNAL ;
    PORT
      LAYER M3 ;
        RECT  65.916 0 65.934 0.144 ;
    END
  END head_o[74]
  PIN head_o[75]
    DIRECTION OUTPUT ;
    USE SIGNAL ;
    PORT
      LAYER M5 ;
        RECT  66.72 0 66.744 0.192 ;
    END
  END head_o[75]
  PIN head_o[76]
    DIRECTION OUTPUT ;
    USE SIGNAL ;
    PORT
      LAYER M3 ;
        RECT  67.572 0 67.59 0.144 ;
    END
  END head_o[76]
  PIN head_o[77]
    DIRECTION OUTPUT ;
    USE SIGNAL ;
    PORT
      LAYER M5 ;
        RECT  68.4 0 68.424 0.192 ;
    END
  END head_o[77]
  PIN head_o[78]
    DIRECTION OUTPUT ;
    USE SIGNAL ;
    PORT
      LAYER M3 ;
        RECT  69.228 0 69.246 0.144 ;
    END
  END head_o[78]
  PIN head_o[79]
    DIRECTION OUTPUT ;
    USE SIGNAL ;
    PORT
      LAYER M5 ;
        RECT  70.032 0 70.056 0.192 ;
    END
  END head_o[79]
  PIN head_o[7]
    DIRECTION OUTPUT ;
    USE SIGNAL ;
    PORT
      LAYER M5 ;
        RECT  10.512 0 10.536 0.192 ;
    END
  END head_o[7]
  PIN head_o[80]
    DIRECTION OUTPUT ;
    USE SIGNAL ;
    PORT
      LAYER M3 ;
        RECT  70.884 0 70.902 0.144 ;
    END
  END head_o[80]
  PIN head_o[81]
    DIRECTION OUTPUT ;
    USE SIGNAL ;
    PORT
      LAYER M5 ;
        RECT  71.712 0 71.736 0.192 ;
    END
  END head_o[81]
  PIN head_o[82]
    DIRECTION OUTPUT ;
    USE SIGNAL ;
    PORT
      LAYER M3 ;
        RECT  72.54 0 72.558 0.144 ;
    END
  END head_o[82]
  PIN head_o[83]
    DIRECTION OUTPUT ;
    USE SIGNAL ;
    PORT
      LAYER M5 ;
        RECT  73.344 0 73.368 0.192 ;
    END
  END head_o[83]
  PIN head_o[84]
    DIRECTION OUTPUT ;
    USE SIGNAL ;
    PORT
      LAYER M3 ;
        RECT  74.196 0 74.214 0.144 ;
    END
  END head_o[84]
  PIN head_o[85]
    DIRECTION OUTPUT ;
    USE SIGNAL ;
    PORT
      LAYER M5 ;
        RECT  75.024 0 75.048 0.192 ;
    END
  END head_o[85]
  PIN head_o[86]
    DIRECTION OUTPUT ;
    USE SIGNAL ;
    PORT
      LAYER M3 ;
        RECT  75.852 0 75.87 0.144 ;
    END
  END head_o[86]
  PIN head_o[87]
    DIRECTION OUTPUT ;
    USE SIGNAL ;
    PORT
      LAYER M5 ;
        RECT  76.656 0 76.68 0.192 ;
    END
  END head_o[87]
  PIN head_o[88]
    DIRECTION OUTPUT ;
    USE SIGNAL ;
    PORT
      LAYER M3 ;
        RECT  77.472 0 77.49 0.144 ;
    END
  END head_o[88]
  PIN head_o[89]
    DIRECTION OUTPUT ;
    USE SIGNAL ;
    PORT
      LAYER M5 ;
        RECT  78.336 0 78.36 0.192 ;
    END
  END head_o[89]
  PIN head_o[8]
    DIRECTION OUTPUT ;
    USE SIGNAL ;
    PORT
      LAYER M3 ;
        RECT  11.34 0 11.358 0.144 ;
    END
  END head_o[8]
  PIN head_o[90]
    DIRECTION OUTPUT ;
    USE SIGNAL ;
    PORT
      LAYER M3 ;
        RECT  79.128 0 79.146 0.144 ;
    END
  END head_o[90]
  PIN head_o[91]
    DIRECTION OUTPUT ;
    USE SIGNAL ;
    PORT
      LAYER M5 ;
        RECT  79.968 0 79.992 0.192 ;
    END
  END head_o[91]
  PIN head_o[92]
    DIRECTION OUTPUT ;
    USE SIGNAL ;
    PORT
      LAYER M3 ;
        RECT  80.784 0 80.802 0.144 ;
    END
  END head_o[92]
  PIN head_o[93]
    DIRECTION OUTPUT ;
    USE SIGNAL ;
    PORT
      LAYER M5 ;
        RECT  81.6 0 81.624 0.192 ;
    END
  END head_o[93]
  PIN head_o[94]
    DIRECTION OUTPUT ;
    USE SIGNAL ;
    PORT
      LAYER M3 ;
        RECT  82.44 0 82.458 0.144 ;
    END
  END head_o[94]
  PIN head_o[95]
    DIRECTION OUTPUT ;
    USE SIGNAL ;
    PORT
      LAYER M5 ;
        RECT  83.28 0 83.304 0.192 ;
    END
  END head_o[95]
  PIN head_o[96]
    DIRECTION OUTPUT ;
    USE SIGNAL ;
    PORT
      LAYER M3 ;
        RECT  84.096 0 84.114 0.144 ;
    END
  END head_o[96]
  PIN head_o[97]
    DIRECTION OUTPUT ;
    USE SIGNAL ;
    PORT
      LAYER M5 ;
        RECT  84.912 0 84.936 0.192 ;
    END
  END head_o[97]
  PIN head_o[98]
    DIRECTION OUTPUT ;
    USE SIGNAL ;
    PORT
      LAYER M3 ;
        RECT  85.752 0 85.77 0.144 ;
    END
  END head_o[98]
  PIN head_o[99]
    DIRECTION OUTPUT ;
    USE SIGNAL ;
    PORT
      LAYER M5 ;
        RECT  86.592 0 86.616 0.192 ;
    END
  END head_o[99]
  PIN head_o[9]
    DIRECTION OUTPUT ;
    USE SIGNAL ;
    PORT
      LAYER M5 ;
        RECT  12.144 0 12.168 0.192 ;
    END
  END head_o[9]
  PIN hv_o
    DIRECTION OUTPUT ;
    USE SIGNAL ;
    PORT
      LAYER M3 ;
        RECT  214.776 97.056 214.794 97.2 ;
    END
  END hv_o
  PIN ovf_o
    DIRECTION OUTPUT ;
    USE SIGNAL ;
    PORT
      LAYER M5 ;
        RECT  215.568 97.008 215.592 97.2 ;
    END
  END ovf_o
  PIN pop_i
    DIRECTION INPUT ;
    USE SIGNAL ;
    PORT
      LAYER M5 ;
        RECT  5.52 97.008 5.544 97.2 ;
    END
  END pop_i
  PIN push_i
    DIRECTION INPUT ;
    USE SIGNAL ;
    PORT
      LAYER M3 ;
        RECT  6.336 97.056 6.354 97.2 ;
    END
  END push_i
  PIN srs
    DIRECTION INPUT ;
    USE SIGNAL ;
    PORT
      LAYER M3 ;
        RECT  4.716 97.056 4.734 97.2 ;
    END
  END srs
  PIN VDD
    DIRECTION INOUT ;
    USE POWER ;
    PORT
      LAYER M5 ;
        RECT  213.192 2.151 213.312 95.049 ;
        RECT  207.792 2.151 207.912 95.049 ;
        RECT  202.392 2.151 202.512 95.049 ;
        RECT  196.992 2.151 197.112 95.049 ;
        RECT  191.592 2.151 191.712 95.049 ;
        RECT  186.192 2.151 186.312 95.049 ;
        RECT  180.792 2.151 180.912 95.049 ;
        RECT  175.392 2.151 175.512 95.049 ;
        RECT  169.992 2.151 170.112 95.049 ;
        RECT  164.592 2.151 164.712 95.049 ;
        RECT  159.192 2.151 159.312 95.049 ;
        RECT  153.792 2.151 153.912 95.049 ;
        RECT  148.392 2.151 148.512 95.049 ;
        RECT  142.992 2.151 143.112 95.049 ;
        RECT  137.592 2.151 137.712 95.049 ;
        RECT  132.192 2.151 132.312 95.049 ;
        RECT  126.792 2.151 126.912 95.049 ;
        RECT  121.392 2.151 121.512 95.049 ;
        RECT  115.992 2.151 116.112 95.049 ;
        RECT  110.592 2.151 110.712 95.049 ;
        RECT  105.192 2.151 105.312 95.049 ;
        RECT  99.792 2.151 99.912 95.049 ;
        RECT  94.392 2.151 94.512 95.049 ;
        RECT  88.992 2.151 89.112 95.049 ;
        RECT  83.592 2.151 83.712 95.049 ;
        RECT  78.192 2.151 78.312 95.049 ;
        RECT  72.792 2.151 72.912 95.049 ;
        RECT  67.392 2.151 67.512 95.049 ;
        RECT  61.992 2.151 62.112 95.049 ;
        RECT  56.592 2.151 56.712 95.049 ;
        RECT  51.192 2.151 51.312 95.049 ;
        RECT  45.792 2.151 45.912 95.049 ;
        RECT  40.392 2.151 40.512 95.049 ;
        RECT  34.992 2.151 35.112 95.049 ;
        RECT  29.592 2.151 29.712 95.049 ;
        RECT  24.192 2.151 24.312 95.049 ;
        RECT  18.792 2.151 18.912 95.049 ;
        RECT  13.392 2.151 13.512 95.049 ;
        RECT  7.992 2.151 8.112 95.049 ;
        RECT  2.592 2.151 2.712 95.049 ;
    END
  END VDD
  PIN VSS
    DIRECTION INOUT ;
    USE GROUND ;
    PORT
      LAYER M5 ;
        RECT  213 2.137 213.12 95.063 ;
        RECT  207.6 2.137 207.72 95.063 ;
        RECT  202.2 2.137 202.32 95.063 ;
        RECT  196.8 2.137 196.92 95.063 ;
        RECT  191.4 2.137 191.52 95.063 ;
        RECT  186 2.137 186.12 95.063 ;
        RECT  180.6 2.137 180.72 95.063 ;
        RECT  175.2 2.137 175.32 95.063 ;
        RECT  169.8 2.137 169.92 95.063 ;
        RECT  164.4 2.137 164.52 95.063 ;
        RECT  159 2.137 159.12 95.063 ;
        RECT  153.6 2.137 153.72 95.063 ;
        RECT  148.2 2.137 148.32 95.063 ;
        RECT  142.8 2.137 142.92 95.063 ;
        RECT  137.4 2.137 137.52 95.063 ;
        RECT  132 2.137 132.12 95.063 ;
        RECT  126.6 2.137 126.72 95.063 ;
        RECT  121.2 2.137 121.32 95.063 ;
        RECT  115.8 2.137 115.92 95.063 ;
        RECT  110.4 2.137 110.52 95.063 ;
        RECT  105 2.137 105.12 95.063 ;
        RECT  99.6 2.137 99.72 95.063 ;
        RECT  94.2 2.137 94.32 95.063 ;
        RECT  88.8 2.137 88.92 95.063 ;
        RECT  83.4 2.137 83.52 95.063 ;
        RECT  78 2.137 78.12 95.063 ;
        RECT  72.6 2.137 72.72 95.063 ;
        RECT  67.2 2.137 67.32 95.063 ;
        RECT  61.8 2.137 61.92 95.063 ;
        RECT  56.4 2.137 56.52 95.063 ;
        RECT  51 2.137 51.12 95.063 ;
        RECT  45.6 2.137 45.72 95.063 ;
        RECT  40.2 2.137 40.32 95.063 ;
        RECT  34.8 2.137 34.92 95.063 ;
        RECT  29.4 2.137 29.52 95.063 ;
        RECT  24 2.137 24.12 95.063 ;
        RECT  18.6 2.137 18.72 95.063 ;
        RECT  13.2 2.137 13.32 95.063 ;
        RECT  7.8 2.137 7.92 95.063 ;
        RECT  2.4 2.137 2.52 95.063 ;
    END
  END VSS
  OBS
    LAYER RVTN ;
     RECT  2.16 2.16 218.16 2.295 ;
     RECT  2.16 2.565 218.16 2.835 ;
     RECT  2.16 3.105 218.16 3.375 ;
     RECT  2.16 3.645 218.16 3.915 ;
     RECT  2.16 4.185 218.16 4.455 ;
     RECT  2.16 4.725 218.16 4.995 ;
     RECT  2.16 5.265 218.16 5.535 ;
     RECT  2.16 5.805 218.16 6.075 ;
     RECT  2.16 6.345 218.16 6.615 ;
     RECT  2.16 6.885 218.16 7.155 ;
     RECT  2.16 7.425 218.16 7.695 ;
     RECT  2.16 7.965 218.16 8.235 ;
     RECT  2.16 8.505 218.16 8.775 ;
     RECT  2.16 9.045 218.16 9.315 ;
     RECT  2.16 9.585 218.16 9.855 ;
     RECT  2.16 10.125 218.16 10.395 ;
     RECT  2.16 10.665 218.16 10.935 ;
     RECT  2.16 11.205 218.16 11.475 ;
     RECT  2.16 11.745 218.16 12.015 ;
     RECT  2.16 12.285 218.16 12.555 ;
     RECT  2.16 12.825 218.16 13.095 ;
     RECT  2.16 13.365 218.16 13.635 ;
     RECT  2.16 13.905 218.16 14.175 ;
     RECT  2.16 14.445 218.16 14.715 ;
     RECT  2.16 14.985 218.16 15.255 ;
     RECT  2.16 15.525 218.16 15.795 ;
     RECT  2.16 16.065 218.16 16.335 ;
     RECT  2.16 16.605 218.16 16.875 ;
     RECT  2.16 17.145 218.16 17.415 ;
     RECT  2.16 17.685 218.16 17.955 ;
     RECT  2.16 18.225 218.16 18.495 ;
     RECT  2.16 18.765 218.16 19.035 ;
     RECT  2.16 19.305 218.16 19.575 ;
     RECT  2.16 19.845 218.16 20.115 ;
     RECT  2.16 20.385 218.16 20.655 ;
     RECT  2.16 20.925 218.16 21.195 ;
     RECT  2.16 21.465 218.16 21.735 ;
     RECT  2.16 22.005 218.16 22.275 ;
     RECT  2.16 22.545 218.16 22.815 ;
     RECT  2.16 23.085 218.16 23.355 ;
     RECT  2.16 23.625 218.16 23.76 ;
     RECT  2.16 23.76 60.588 23.895 ;
     RECT  159.516 23.76 218.16 23.895 ;
     RECT  2.16 24.165 60.588 24.435 ;
     RECT  159.516 24.165 218.16 24.435 ;
     RECT  2.16 24.705 60.588 24.975 ;
     RECT  159.516 24.705 218.16 24.975 ;
     RECT  2.16 25.245 60.588 25.515 ;
     RECT  159.516 25.245 218.16 25.515 ;
     RECT  2.16 25.785 60.588 26.055 ;
     RECT  159.516 25.785 218.16 26.055 ;
     RECT  2.16 26.325 60.588 26.595 ;
     RECT  159.516 26.325 218.16 26.595 ;
     RECT  2.16 26.865 60.588 27.135 ;
     RECT  159.516 26.865 218.16 27.135 ;
     RECT  2.16 27.405 60.588 27.675 ;
     RECT  159.516 27.405 218.16 27.675 ;
     RECT  2.16 27.945 60.588 28.215 ;
     RECT  159.516 27.945 218.16 28.215 ;
     RECT  2.16 28.485 60.588 28.755 ;
     RECT  159.516 28.485 218.16 28.755 ;
     RECT  2.16 29.025 60.588 29.295 ;
     RECT  159.516 29.025 218.16 29.295 ;
     RECT  2.16 29.565 60.588 29.835 ;
     RECT  159.516 29.565 218.16 29.835 ;
     RECT  2.16 30.105 60.588 30.375 ;
     RECT  159.516 30.105 218.16 30.375 ;
     RECT  2.16 30.645 60.588 30.915 ;
     RECT  159.516 30.645 218.16 30.915 ;
     RECT  2.16 31.185 60.588 31.455 ;
     RECT  159.516 31.185 218.16 31.455 ;
     RECT  2.16 31.725 60.588 31.995 ;
     RECT  159.516 31.725 218.16 31.995 ;
     RECT  2.16 32.265 60.588 32.535 ;
     RECT  159.516 32.265 218.16 32.535 ;
     RECT  2.16 32.805 60.588 33.075 ;
     RECT  159.516 32.805 218.16 33.075 ;
     RECT  2.16 33.345 60.588 33.615 ;
     RECT  159.516 33.345 218.16 33.615 ;
     RECT  2.16 33.885 60.588 34.155 ;
     RECT  159.516 33.885 218.16 34.155 ;
     RECT  2.16 34.425 60.588 34.695 ;
     RECT  159.516 34.425 218.16 34.695 ;
     RECT  2.16 34.965 60.588 35.235 ;
     RECT  159.516 34.965 218.16 35.235 ;
     RECT  2.16 35.505 60.588 35.775 ;
     RECT  159.516 35.505 218.16 35.775 ;
     RECT  2.16 36.045 60.588 36.315 ;
     RECT  159.516 36.045 218.16 36.315 ;
     RECT  2.16 36.585 60.588 36.855 ;
     RECT  159.516 36.585 218.16 36.855 ;
     RECT  2.16 37.125 60.588 37.395 ;
     RECT  159.516 37.125 218.16 37.395 ;
     RECT  2.16 37.665 60.588 37.935 ;
     RECT  159.516 37.665 218.16 37.935 ;
     RECT  2.16 38.205 60.588 38.475 ;
     RECT  159.516 38.205 218.16 38.475 ;
     RECT  2.16 38.745 60.588 39.015 ;
     RECT  159.516 38.745 218.16 39.015 ;
     RECT  2.16 39.285 60.588 39.555 ;
     RECT  159.516 39.285 218.16 39.555 ;
     RECT  2.16 39.825 60.588 40.095 ;
     RECT  159.516 39.825 218.16 40.095 ;
     RECT  2.16 40.365 60.588 40.635 ;
     RECT  159.516 40.365 218.16 40.635 ;
     RECT  2.16 40.905 60.588 41.175 ;
     RECT  159.516 40.905 218.16 41.175 ;
     RECT  2.16 41.445 60.588 41.715 ;
     RECT  159.516 41.445 218.16 41.715 ;
     RECT  2.16 41.985 60.588 42.255 ;
     RECT  159.516 41.985 218.16 42.255 ;
     RECT  2.16 42.525 60.588 42.795 ;
     RECT  159.516 42.525 218.16 42.795 ;
     RECT  2.16 43.065 60.588 43.335 ;
     RECT  159.516 43.065 218.16 43.335 ;
     RECT  2.16 43.605 60.588 43.875 ;
     RECT  159.516 43.605 218.16 43.875 ;
     RECT  2.16 44.145 60.588 44.415 ;
     RECT  159.516 44.145 218.16 44.415 ;
     RECT  2.16 44.685 60.588 44.955 ;
     RECT  159.516 44.685 218.16 44.955 ;
     RECT  2.16 45.225 60.588 45.495 ;
     RECT  159.516 45.225 218.16 45.495 ;
     RECT  2.16 45.765 60.588 46.035 ;
     RECT  159.516 45.765 218.16 46.035 ;
     RECT  2.16 46.305 60.588 46.575 ;
     RECT  159.516 46.305 218.16 46.575 ;
     RECT  2.16 46.845 60.588 47.115 ;
     RECT  159.516 46.845 218.16 47.115 ;
     RECT  2.16 47.385 60.588 47.655 ;
     RECT  159.516 47.385 218.16 47.655 ;
     RECT  2.16 47.925 60.588 48.195 ;
     RECT  159.516 47.925 218.16 48.195 ;
     RECT  2.16 48.465 60.588 48.735 ;
     RECT  159.516 48.465 218.16 48.735 ;
     RECT  2.16 49.005 60.588 49.275 ;
     RECT  159.516 49.005 218.16 49.275 ;
     RECT  2.16 49.545 60.588 49.815 ;
     RECT  159.516 49.545 218.16 49.815 ;
     RECT  2.16 50.085 60.588 50.355 ;
     RECT  159.516 50.085 218.16 50.355 ;
     RECT  2.16 50.625 60.588 50.895 ;
     RECT  159.516 50.625 218.16 50.895 ;
     RECT  2.16 51.165 60.588 51.435 ;
     RECT  159.516 51.165 218.16 51.435 ;
     RECT  2.16 51.705 60.588 51.975 ;
     RECT  159.516 51.705 218.16 51.975 ;
     RECT  2.16 52.245 60.588 52.515 ;
     RECT  159.516 52.245 218.16 52.515 ;
     RECT  2.16 52.785 60.588 53.055 ;
     RECT  159.516 52.785 218.16 53.055 ;
     RECT  2.16 53.325 60.588 53.595 ;
     RECT  159.516 53.325 218.16 53.595 ;
     RECT  2.16 53.865 60.588 54.135 ;
     RECT  159.516 53.865 218.16 54.135 ;
     RECT  2.16 54.405 60.588 54.675 ;
     RECT  159.516 54.405 218.16 54.675 ;
     RECT  2.16 54.945 60.588 55.215 ;
     RECT  159.516 54.945 218.16 55.215 ;
     RECT  2.16 55.485 60.588 55.755 ;
     RECT  159.516 55.485 218.16 55.755 ;
     RECT  2.16 56.025 60.588 56.295 ;
     RECT  159.516 56.025 218.16 56.295 ;
     RECT  2.16 56.565 60.588 56.835 ;
     RECT  159.516 56.565 218.16 56.835 ;
     RECT  2.16 57.105 60.588 57.375 ;
     RECT  159.516 57.105 218.16 57.375 ;
     RECT  2.16 57.645 60.588 57.915 ;
     RECT  159.516 57.645 218.16 57.915 ;
     RECT  2.16 58.185 60.588 58.455 ;
     RECT  159.516 58.185 218.16 58.455 ;
     RECT  2.16 58.725 60.588 58.995 ;
     RECT  159.516 58.725 218.16 58.995 ;
     RECT  2.16 59.265 60.588 59.535 ;
     RECT  159.516 59.265 218.16 59.535 ;
     RECT  2.16 59.805 60.588 60.075 ;
     RECT  159.516 59.805 218.16 60.075 ;
     RECT  2.16 60.345 60.588 60.615 ;
     RECT  159.516 60.345 218.16 60.615 ;
     RECT  2.16 60.885 60.588 61.155 ;
     RECT  159.516 60.885 218.16 61.155 ;
     RECT  2.16 61.425 60.588 61.695 ;
     RECT  159.516 61.425 218.16 61.695 ;
     RECT  2.16 61.965 60.588 62.235 ;
     RECT  159.516 61.965 218.16 62.235 ;
     RECT  2.16 62.505 60.588 62.775 ;
     RECT  159.516 62.505 218.16 62.775 ;
     RECT  2.16 63.045 60.588 63.315 ;
     RECT  159.516 63.045 218.16 63.315 ;
     RECT  2.16 63.585 60.588 63.855 ;
     RECT  159.516 63.585 218.16 63.855 ;
     RECT  2.16 64.125 60.588 64.395 ;
     RECT  159.516 64.125 218.16 64.395 ;
     RECT  2.16 64.665 60.588 64.935 ;
     RECT  159.516 64.665 218.16 64.935 ;
     RECT  2.16 65.205 60.588 65.475 ;
     RECT  159.516 65.205 218.16 65.475 ;
     RECT  2.16 65.745 60.588 66.015 ;
     RECT  159.516 65.745 218.16 66.015 ;
     RECT  2.16 66.285 60.588 66.555 ;
     RECT  159.516 66.285 218.16 66.555 ;
     RECT  2.16 66.825 60.588 67.095 ;
     RECT  159.516 66.825 218.16 67.095 ;
     RECT  2.16 67.365 60.588 67.635 ;
     RECT  159.516 67.365 218.16 67.635 ;
     RECT  2.16 67.905 60.588 68.175 ;
     RECT  159.516 67.905 218.16 68.175 ;
     RECT  2.16 68.445 60.588 68.715 ;
     RECT  159.516 68.445 218.16 68.715 ;
     RECT  2.16 68.985 60.588 69.12 ;
     RECT  159.516 68.985 218.16 69.12 ;
     RECT  2.16 69.12 218.16 69.255 ;
     RECT  2.16 69.525 218.16 69.795 ;
     RECT  2.16 70.065 218.16 70.335 ;
     RECT  2.16 70.605 218.16 70.875 ;
     RECT  2.16 71.145 218.16 71.415 ;
     RECT  2.16 71.685 218.16 71.955 ;
     RECT  2.16 72.225 218.16 72.495 ;
     RECT  2.16 72.765 218.16 73.035 ;
     RECT  2.16 73.305 218.16 73.575 ;
     RECT  2.16 73.845 218.16 74.115 ;
     RECT  2.16 74.385 218.16 74.655 ;
     RECT  2.16 74.925 218.16 75.195 ;
     RECT  2.16 75.465 218.16 75.735 ;
     RECT  2.16 76.005 218.16 76.275 ;
     RECT  2.16 76.545 218.16 76.815 ;
     RECT  2.16 77.085 218.16 77.355 ;
     RECT  2.16 77.625 218.16 77.895 ;
     RECT  2.16 78.165 218.16 78.435 ;
     RECT  2.16 78.705 218.16 78.975 ;
     RECT  2.16 79.245 218.16 79.515 ;
     RECT  2.16 79.785 218.16 80.055 ;
     RECT  2.16 80.325 218.16 80.595 ;
     RECT  2.16 80.865 218.16 81.135 ;
     RECT  2.16 81.405 218.16 81.675 ;
     RECT  2.16 81.945 218.16 82.215 ;
     RECT  2.16 82.485 218.16 82.755 ;
     RECT  2.16 83.025 218.16 83.295 ;
     RECT  2.16 83.565 218.16 83.835 ;
     RECT  2.16 84.105 218.16 84.375 ;
     RECT  2.16 84.645 218.16 84.915 ;
     RECT  2.16 85.185 218.16 85.455 ;
     RECT  2.16 85.725 218.16 85.995 ;
     RECT  2.16 86.265 218.16 86.535 ;
     RECT  2.16 86.805 218.16 87.075 ;
     RECT  2.16 87.345 218.16 87.615 ;
     RECT  2.16 87.885 218.16 88.155 ;
     RECT  2.16 88.425 218.16 88.695 ;
     RECT  2.16 88.965 218.16 89.235 ;
     RECT  2.16 89.505 218.16 89.775 ;
     RECT  2.16 90.045 218.16 90.315 ;
     RECT  2.16 90.585 218.16 90.855 ;
     RECT  2.16 91.125 218.16 91.395 ;
     RECT  2.16 91.665 218.16 91.935 ;
     RECT  2.16 92.205 218.16 92.475 ;
     RECT  2.16 92.745 218.16 93.015 ;
     RECT  2.16 93.285 218.16 93.555 ;
     RECT  2.16 93.825 218.16 94.095 ;
     RECT  2.16 94.365 218.16 94.635 ;
     RECT  2.16 94.905 218.16 95.04 ;
    LAYER RVTP ;
     RECT  2.16 2.295 218.16 2.565 ;
     RECT  2.16 2.835 218.16 3.105 ;
     RECT  2.16 3.375 218.16 3.645 ;
     RECT  2.16 3.915 218.16 4.185 ;
     RECT  2.16 4.455 218.16 4.725 ;
     RECT  2.16 4.995 218.16 5.265 ;
     RECT  2.16 5.535 218.16 5.805 ;
     RECT  2.16 6.075 218.16 6.345 ;
     RECT  2.16 6.615 218.16 6.885 ;
     RECT  2.16 7.155 218.16 7.425 ;
     RECT  2.16 7.695 218.16 7.965 ;
     RECT  2.16 8.235 218.16 8.505 ;
     RECT  2.16 8.775 218.16 9.045 ;
     RECT  2.16 9.315 218.16 9.585 ;
     RECT  2.16 9.855 218.16 10.125 ;
     RECT  2.16 10.395 218.16 10.665 ;
     RECT  2.16 10.935 218.16 11.205 ;
     RECT  2.16 11.475 218.16 11.745 ;
     RECT  2.16 12.015 218.16 12.285 ;
     RECT  2.16 12.555 218.16 12.825 ;
     RECT  2.16 13.095 218.16 13.365 ;
     RECT  2.16 13.635 218.16 13.905 ;
     RECT  2.16 14.175 218.16 14.445 ;
     RECT  2.16 14.715 218.16 14.985 ;
     RECT  2.16 15.255 218.16 15.525 ;
     RECT  2.16 15.795 218.16 16.065 ;
     RECT  2.16 16.335 218.16 16.605 ;
     RECT  2.16 16.875 218.16 17.145 ;
     RECT  2.16 17.415 218.16 17.685 ;
     RECT  2.16 17.955 218.16 18.225 ;
     RECT  2.16 18.495 218.16 18.765 ;
     RECT  2.16 19.035 218.16 19.305 ;
     RECT  2.16 19.575 218.16 19.845 ;
     RECT  2.16 20.115 218.16 20.385 ;
     RECT  2.16 20.655 218.16 20.925 ;
     RECT  2.16 21.195 218.16 21.465 ;
     RECT  2.16 21.735 218.16 22.005 ;
     RECT  2.16 22.275 218.16 22.545 ;
     RECT  2.16 22.815 218.16 23.085 ;
     RECT  2.16 23.355 218.16 23.625 ;
     RECT  2.16 23.895 60.588 24.165 ;
     RECT  159.516 23.895 218.16 24.165 ;
     RECT  2.16 24.435 60.588 24.705 ;
     RECT  159.516 24.435 218.16 24.705 ;
     RECT  2.16 24.975 60.588 25.245 ;
     RECT  159.516 24.975 218.16 25.245 ;
     RECT  2.16 25.515 60.588 25.785 ;
     RECT  159.516 25.515 218.16 25.785 ;
     RECT  2.16 26.055 60.588 26.325 ;
     RECT  159.516 26.055 218.16 26.325 ;
     RECT  2.16 26.595 60.588 26.865 ;
     RECT  159.516 26.595 218.16 26.865 ;
     RECT  2.16 27.135 60.588 27.405 ;
     RECT  159.516 27.135 218.16 27.405 ;
     RECT  2.16 27.675 60.588 27.945 ;
     RECT  159.516 27.675 218.16 27.945 ;
     RECT  2.16 28.215 60.588 28.485 ;
     RECT  159.516 28.215 218.16 28.485 ;
     RECT  2.16 28.755 60.588 29.025 ;
     RECT  159.516 28.755 218.16 29.025 ;
     RECT  2.16 29.295 60.588 29.565 ;
     RECT  159.516 29.295 218.16 29.565 ;
     RECT  2.16 29.835 60.588 30.105 ;
     RECT  159.516 29.835 218.16 30.105 ;
     RECT  2.16 30.375 60.588 30.645 ;
     RECT  159.516 30.375 218.16 30.645 ;
     RECT  2.16 30.915 60.588 31.185 ;
     RECT  159.516 30.915 218.16 31.185 ;
     RECT  2.16 31.455 60.588 31.725 ;
     RECT  159.516 31.455 218.16 31.725 ;
     RECT  2.16 31.995 60.588 32.265 ;
     RECT  159.516 31.995 218.16 32.265 ;
     RECT  2.16 32.535 60.588 32.805 ;
     RECT  159.516 32.535 218.16 32.805 ;
     RECT  2.16 33.075 60.588 33.345 ;
     RECT  159.516 33.075 218.16 33.345 ;
     RECT  2.16 33.615 60.588 33.885 ;
     RECT  159.516 33.615 218.16 33.885 ;
     RECT  2.16 34.155 60.588 34.425 ;
     RECT  159.516 34.155 218.16 34.425 ;
     RECT  2.16 34.695 60.588 34.965 ;
     RECT  159.516 34.695 218.16 34.965 ;
     RECT  2.16 35.235 60.588 35.505 ;
     RECT  159.516 35.235 218.16 35.505 ;
     RECT  2.16 35.775 60.588 36.045 ;
     RECT  159.516 35.775 218.16 36.045 ;
     RECT  2.16 36.315 60.588 36.585 ;
     RECT  159.516 36.315 218.16 36.585 ;
     RECT  2.16 36.855 60.588 37.125 ;
     RECT  159.516 36.855 218.16 37.125 ;
     RECT  2.16 37.395 60.588 37.665 ;
     RECT  159.516 37.395 218.16 37.665 ;
     RECT  2.16 37.935 60.588 38.205 ;
     RECT  159.516 37.935 218.16 38.205 ;
     RECT  2.16 38.475 60.588 38.745 ;
     RECT  159.516 38.475 218.16 38.745 ;
     RECT  2.16 39.015 60.588 39.285 ;
     RECT  159.516 39.015 218.16 39.285 ;
     RECT  2.16 39.555 60.588 39.825 ;
     RECT  159.516 39.555 218.16 39.825 ;
     RECT  2.16 40.095 60.588 40.365 ;
     RECT  159.516 40.095 218.16 40.365 ;
     RECT  2.16 40.635 60.588 40.905 ;
     RECT  159.516 40.635 218.16 40.905 ;
     RECT  2.16 41.175 60.588 41.445 ;
     RECT  159.516 41.175 218.16 41.445 ;
     RECT  2.16 41.715 60.588 41.985 ;
     RECT  159.516 41.715 218.16 41.985 ;
     RECT  2.16 42.255 60.588 42.525 ;
     RECT  159.516 42.255 218.16 42.525 ;
     RECT  2.16 42.795 60.588 43.065 ;
     RECT  159.516 42.795 218.16 43.065 ;
     RECT  2.16 43.335 60.588 43.605 ;
     RECT  159.516 43.335 218.16 43.605 ;
     RECT  2.16 43.875 60.588 44.145 ;
     RECT  159.516 43.875 218.16 44.145 ;
     RECT  2.16 44.415 60.588 44.685 ;
     RECT  159.516 44.415 218.16 44.685 ;
     RECT  2.16 44.955 60.588 45.225 ;
     RECT  159.516 44.955 218.16 45.225 ;
     RECT  2.16 45.495 60.588 45.765 ;
     RECT  159.516 45.495 218.16 45.765 ;
     RECT  2.16 46.035 60.588 46.305 ;
     RECT  159.516 46.035 218.16 46.305 ;
     RECT  2.16 46.575 60.588 46.845 ;
     RECT  159.516 46.575 218.16 46.845 ;
     RECT  2.16 47.115 60.588 47.385 ;
     RECT  159.516 47.115 218.16 47.385 ;
     RECT  2.16 47.655 60.588 47.925 ;
     RECT  159.516 47.655 218.16 47.925 ;
     RECT  2.16 48.195 60.588 48.465 ;
     RECT  159.516 48.195 218.16 48.465 ;
     RECT  2.16 48.735 60.588 49.005 ;
     RECT  159.516 48.735 218.16 49.005 ;
     RECT  2.16 49.275 60.588 49.545 ;
     RECT  159.516 49.275 218.16 49.545 ;
     RECT  2.16 49.815 60.588 50.085 ;
     RECT  159.516 49.815 218.16 50.085 ;
     RECT  2.16 50.355 60.588 50.625 ;
     RECT  159.516 50.355 218.16 50.625 ;
     RECT  2.16 50.895 60.588 51.165 ;
     RECT  159.516 50.895 218.16 51.165 ;
     RECT  2.16 51.435 60.588 51.705 ;
     RECT  159.516 51.435 218.16 51.705 ;
     RECT  2.16 51.975 60.588 52.245 ;
     RECT  159.516 51.975 218.16 52.245 ;
     RECT  2.16 52.515 60.588 52.785 ;
     RECT  159.516 52.515 218.16 52.785 ;
     RECT  2.16 53.055 60.588 53.325 ;
     RECT  159.516 53.055 218.16 53.325 ;
     RECT  2.16 53.595 60.588 53.865 ;
     RECT  159.516 53.595 218.16 53.865 ;
     RECT  2.16 54.135 60.588 54.405 ;
     RECT  159.516 54.135 218.16 54.405 ;
     RECT  2.16 54.675 60.588 54.945 ;
     RECT  159.516 54.675 218.16 54.945 ;
     RECT  2.16 55.215 60.588 55.485 ;
     RECT  159.516 55.215 218.16 55.485 ;
     RECT  2.16 55.755 60.588 56.025 ;
     RECT  159.516 55.755 218.16 56.025 ;
     RECT  2.16 56.295 60.588 56.565 ;
     RECT  159.516 56.295 218.16 56.565 ;
     RECT  2.16 56.835 60.588 57.105 ;
     RECT  159.516 56.835 218.16 57.105 ;
     RECT  2.16 57.375 60.588 57.645 ;
     RECT  159.516 57.375 218.16 57.645 ;
     RECT  2.16 57.915 60.588 58.185 ;
     RECT  159.516 57.915 218.16 58.185 ;
     RECT  2.16 58.455 60.588 58.725 ;
     RECT  159.516 58.455 218.16 58.725 ;
     RECT  2.16 58.995 60.588 59.265 ;
     RECT  159.516 58.995 218.16 59.265 ;
     RECT  2.16 59.535 60.588 59.805 ;
     RECT  159.516 59.535 218.16 59.805 ;
     RECT  2.16 60.075 60.588 60.345 ;
     RECT  159.516 60.075 218.16 60.345 ;
     RECT  2.16 60.615 60.588 60.885 ;
     RECT  159.516 60.615 218.16 60.885 ;
     RECT  2.16 61.155 60.588 61.425 ;
     RECT  159.516 61.155 218.16 61.425 ;
     RECT  2.16 61.695 60.588 61.965 ;
     RECT  159.516 61.695 218.16 61.965 ;
     RECT  2.16 62.235 60.588 62.505 ;
     RECT  159.516 62.235 218.16 62.505 ;
     RECT  2.16 62.775 60.588 63.045 ;
     RECT  159.516 62.775 218.16 63.045 ;
     RECT  2.16 63.315 60.588 63.585 ;
     RECT  159.516 63.315 218.16 63.585 ;
     RECT  2.16 63.855 60.588 64.125 ;
     RECT  159.516 63.855 218.16 64.125 ;
     RECT  2.16 64.395 60.588 64.665 ;
     RECT  159.516 64.395 218.16 64.665 ;
     RECT  2.16 64.935 60.588 65.205 ;
     RECT  159.516 64.935 218.16 65.205 ;
     RECT  2.16 65.475 60.588 65.745 ;
     RECT  159.516 65.475 218.16 65.745 ;
     RECT  2.16 66.015 60.588 66.285 ;
     RECT  159.516 66.015 218.16 66.285 ;
     RECT  2.16 66.555 60.588 66.825 ;
     RECT  159.516 66.555 218.16 66.825 ;
     RECT  2.16 67.095 60.588 67.365 ;
     RECT  159.516 67.095 218.16 67.365 ;
     RECT  2.16 67.635 60.588 67.905 ;
     RECT  159.516 67.635 218.16 67.905 ;
     RECT  2.16 68.175 60.588 68.445 ;
     RECT  159.516 68.175 218.16 68.445 ;
     RECT  2.16 68.715 60.588 68.985 ;
     RECT  159.516 68.715 218.16 68.985 ;
     RECT  2.16 69.255 218.16 69.525 ;
     RECT  2.16 69.795 218.16 70.065 ;
     RECT  2.16 70.335 218.16 70.605 ;
     RECT  2.16 70.875 218.16 71.145 ;
     RECT  2.16 71.415 218.16 71.685 ;
     RECT  2.16 71.955 218.16 72.225 ;
     RECT  2.16 72.495 218.16 72.765 ;
     RECT  2.16 73.035 218.16 73.305 ;
     RECT  2.16 73.575 218.16 73.845 ;
     RECT  2.16 74.115 218.16 74.385 ;
     RECT  2.16 74.655 218.16 74.925 ;
     RECT  2.16 75.195 218.16 75.465 ;
     RECT  2.16 75.735 218.16 76.005 ;
     RECT  2.16 76.275 218.16 76.545 ;
     RECT  2.16 76.815 218.16 77.085 ;
     RECT  2.16 77.355 218.16 77.625 ;
     RECT  2.16 77.895 218.16 78.165 ;
     RECT  2.16 78.435 218.16 78.705 ;
     RECT  2.16 78.975 218.16 79.245 ;
     RECT  2.16 79.515 218.16 79.785 ;
     RECT  2.16 80.055 218.16 80.325 ;
     RECT  2.16 80.595 218.16 80.865 ;
     RECT  2.16 81.135 218.16 81.405 ;
     RECT  2.16 81.675 218.16 81.945 ;
     RECT  2.16 82.215 218.16 82.485 ;
     RECT  2.16 82.755 218.16 83.025 ;
     RECT  2.16 83.295 218.16 83.565 ;
     RECT  2.16 83.835 218.16 84.105 ;
     RECT  2.16 84.375 218.16 84.645 ;
     RECT  2.16 84.915 218.16 85.185 ;
     RECT  2.16 85.455 218.16 85.725 ;
     RECT  2.16 85.995 218.16 86.265 ;
     RECT  2.16 86.535 218.16 86.805 ;
     RECT  2.16 87.075 218.16 87.345 ;
     RECT  2.16 87.615 218.16 87.885 ;
     RECT  2.16 88.155 218.16 88.425 ;
     RECT  2.16 88.695 218.16 88.965 ;
     RECT  2.16 89.235 218.16 89.505 ;
     RECT  2.16 89.775 218.16 90.045 ;
     RECT  2.16 90.315 218.16 90.585 ;
     RECT  2.16 90.855 218.16 91.125 ;
     RECT  2.16 91.395 218.16 91.665 ;
     RECT  2.16 91.935 218.16 92.205 ;
     RECT  2.16 92.475 218.16 92.745 ;
     RECT  2.16 93.015 218.16 93.285 ;
     RECT  2.16 93.555 218.16 93.825 ;
     RECT  2.16 94.095 218.16 94.365 ;
     RECT  2.16 94.635 218.16 94.905 ;
    LAYER M1 ;
     RECT  2.16 2.151 218.16 23.769 ;
     RECT  62.64 25.92 157.464 66.984 ;
     RECT  2.16 23.769 60.588 69.111 ;
     RECT  159.516 23.769 218.16 69.111 ;
     RECT  2.16 69.111 218.16 95.049 ;
    LAYER M2 ;
     RECT  2.16 2.151 6.367 95.049 ;
     RECT  6.367 1.728 6.503 95.049 ;
     RECT  6.503 2.151 12.991 95.049 ;
     RECT  12.991 2.106 13.199 95.049 ;
     RECT  13.199 2.151 16.303 95.049 ;
     RECT  16.303 2.106 16.763 95.049 ;
     RECT  16.763 2.151 19.615 95.049 ;
     RECT  19.615 1.728 19.823 95.049 ;
     RECT  19.823 2.151 22.927 95.049 ;
     RECT  22.927 2.106 23.495 95.049 ;
     RECT  23.495 2.151 24.115 95.049 ;
     RECT  24.115 2.151 24.215 95.13 ;
     RECT  24.215 2.151 24.547 95.049 ;
     RECT  24.547 1.728 24.755 95.049 ;
     RECT  24.755 2.151 29.515 95.049 ;
     RECT  29.515 1.728 29.615 95.049 ;
     RECT  29.615 2.151 31.171 95.049 ;
     RECT  31.171 2.106 31.595 95.049 ;
     RECT  31.595 2.151 32.827 95.049 ;
     RECT  32.827 2.106 33.215 95.049 ;
     RECT  33.215 2.151 37.795 95.049 ;
     RECT  37.795 2.106 38.291 95.049 ;
     RECT  38.291 2.151 39.451 95.049 ;
     RECT  39.451 1.728 39.911 95.049 ;
     RECT  39.911 2.151 40.027 95.049 ;
     RECT  40.027 2.151 40.271 95.13 ;
     RECT  40.271 2.151 42.763 95.049 ;
     RECT  42.763 1.728 43.259 95.049 ;
     RECT  43.259 2.151 46.075 95.049 ;
     RECT  46.075 2.106 46.571 95.049 ;
     RECT  46.571 2.151 49.387 95.049 ;
     RECT  49.387 1.728 49.595 95.049 ;
     RECT  49.595 2.151 51.007 95.049 ;
     RECT  51.007 1.728 51.179 95.049 ;
     RECT  51.179 2.151 52.663 95.049 ;
     RECT  52.663 2.106 53.267 95.049 ;
     RECT  53.267 2.151 56.191 95.049 ;
     RECT  56.191 2.151 56.435 95.13 ;
     RECT  56.435 2.151 59.287 95.049 ;
     RECT  59.287 1.728 59.639 95.049 ;
     RECT  59.639 2.151 60.588 95.049 ;
     RECT  60.588 62.586 60.899 62.694 ;
     RECT  60.899 62.586 60.971 62.604 ;
     RECT  60.588 27.846 61.007 28.008 ;
     RECT  60.588 2.151 61.151 26.82 ;
     RECT  61.007 27.918 61.151 28.008 ;
     RECT  60.588 39.258 61.187 39.276 ;
     RECT  60.588 32.85 61.547 33.408 ;
     RECT  60.588 52.722 61.547 52.974 ;
     RECT  61.151 27.99 61.655 28.008 ;
     RECT  61.547 32.85 61.655 33.336 ;
     RECT  60.588 59.85 61.699 59.868 ;
     RECT  61.655 33.048 61.907 33.336 ;
     RECT  61.151 2.151 62.311 26.784 ;
     RECT  62.311 47.16 62.347 47.178 ;
     RECT  60.588 30.15 62.383 30.168 ;
     RECT  60.588 31.086 62.383 31.104 ;
     RECT  60.588 54.342 62.383 54.36 ;
     RECT  62.347 46.854 62.455 47.178 ;
     RECT  60.588 66.726 62.491 95.049 ;
     RECT  62.311 2.151 62.599 27.054 ;
     RECT  62.599 2.106 62.64 27.054 ;
     RECT  61.411 29.07 62.64 29.088 ;
     RECT  62.383 30.15 62.64 31.104 ;
     RECT  62.275 31.968 62.64 31.986 ;
     RECT  61.907 33.282 62.64 33.336 ;
     RECT  62.455 46.854 62.64 47.259 ;
     RECT  61.547 52.866 62.64 52.974 ;
     RECT  62.383 54.342 62.64 54.864 ;
     RECT  61.699 59.85 62.64 60.489 ;
     RECT  62.491 66.636 62.64 95.049 ;
     RECT  62.64 2.106 63.131 95.049 ;
     RECT  63.131 2.151 64.255 95.049 ;
     RECT  64.255 2.106 64.535 95.049 ;
     RECT  64.535 2.151 65.911 95.049 ;
     RECT  65.911 2.106 66.551 95.049 ;
     RECT  66.551 2.151 67.567 95.049 ;
     RECT  67.567 1.728 67.667 95.049 ;
     RECT  67.667 2.151 69.223 95.049 ;
     RECT  69.223 1.728 69.503 95.049 ;
     RECT  69.503 2.151 70.879 95.049 ;
     RECT  70.879 2.106 71.411 95.049 ;
     RECT  71.411 2.151 72.535 95.049 ;
     RECT  72.535 1.728 72.815 95.049 ;
     RECT  72.815 2.151 74.191 95.049 ;
     RECT  74.191 1.728 74.327 95.049 ;
     RECT  74.327 2.151 75.847 95.049 ;
     RECT  75.847 2.106 76.595 95.049 ;
     RECT  76.595 2.151 79.123 95.049 ;
     RECT  79.123 2.106 79.331 95.049 ;
     RECT  79.331 2.151 80.779 95.049 ;
     RECT  80.779 2.106 81.059 95.049 ;
     RECT  81.059 2.151 82.435 95.049 ;
     RECT  82.435 2.106 83.219 95.049 ;
     RECT  83.219 2.151 84.091 95.049 ;
     RECT  84.091 1.728 84.299 95.049 ;
     RECT  84.299 2.151 89.059 95.049 ;
     RECT  89.059 1.728 89.375 95.049 ;
     RECT  89.375 2.151 92.371 95.049 ;
     RECT  92.371 2.106 93.011 95.049 ;
     RECT  93.011 2.151 94.027 95.049 ;
     RECT  94.027 2.106 94.631 95.049 ;
     RECT  94.631 2.151 95.683 95.049 ;
     RECT  95.683 2.106 95.927 95.049 ;
     RECT  95.927 2.151 98.995 95.049 ;
     RECT  98.995 2.106 99.419 95.049 ;
     RECT  99.419 2.151 105.583 95.049 ;
     RECT  105.583 2.106 106.295 95.049 ;
     RECT  106.295 2.151 107.239 95.049 ;
     RECT  107.239 1.728 107.411 95.049 ;
     RECT  107.411 2.151 112.207 95.049 ;
     RECT  112.207 2.106 112.343 95.049 ;
     RECT  112.343 2.151 118.831 95.049 ;
     RECT  118.831 1.728 119.003 95.049 ;
     RECT  119.003 1.728 119.075 24.264 ;
     RECT  119.075 2.151 121.991 24.264 ;
     RECT  121.991 2.151 122.143 24.228 ;
     RECT  122.143 1.728 122.279 24.228 ;
     RECT  122.279 2.151 122.387 24.228 ;
     RECT  122.387 2.151 125.455 23.922 ;
     RECT  125.455 1.728 125.843 23.922 ;
     RECT  125.843 2.151 126.319 23.922 ;
     RECT  119.003 25.056 126.319 95.049 ;
     RECT  126.319 2.151 126.707 95.049 ;
     RECT  126.707 2.151 128.299 23.922 ;
     RECT  128.299 2.151 128.767 24.228 ;
     RECT  128.767 2.106 129.083 24.228 ;
     RECT  129.083 2.151 130.351 24.228 ;
     RECT  130.351 2.151 130.387 24.264 ;
     RECT  130.387 1.728 130.523 24.264 ;
     RECT  130.523 2.151 130.783 24.264 ;
     RECT  130.783 2.151 132.043 24.309 ;
     RECT  132.043 2.07 132.331 24.309 ;
     RECT  126.707 25.056 132.331 95.049 ;
     RECT  132.331 2.07 132.755 95.049 ;
     RECT  132.755 2.151 137.011 95.049 ;
     RECT  137.011 1.728 137.327 95.049 ;
     RECT  137.327 2.151 138.667 95.049 ;
     RECT  138.667 1.728 139.055 95.049 ;
     RECT  139.055 2.151 140.323 95.049 ;
     RECT  140.323 1.728 140.531 95.049 ;
     RECT  140.531 2.151 145.291 95.049 ;
     RECT  145.291 2.106 145.931 95.049 ;
     RECT  145.931 2.151 148.603 95.049 ;
     RECT  148.603 1.728 148.775 95.049 ;
     RECT  150.151 97.038 150.187 97.056 ;
     RECT  150.187 97.038 150.287 97.128 ;
     RECT  148.775 2.151 151.915 95.049 ;
     RECT  151.915 1.728 152.195 95.049 ;
     RECT  152.195 2.151 155.227 95.049 ;
     RECT  155.227 1.728 155.435 95.049 ;
     RECT  155.435 2.151 157.464 95.049 ;
     RECT  157.464 30.852 157.631 33.03 ;
     RECT  158.539 27.072 158.575 27.09 ;
     RECT  158.575 27.072 158.719 27.234 ;
     RECT  157.464 28.836 158.755 29.592 ;
     RECT  157.631 30.852 158.791 32.328 ;
     RECT  158.791 30.726 159.043 32.328 ;
     RECT  157.464 2.151 159.187 25.884 ;
     RECT  158.755 28.836 159.223 29.934 ;
     RECT  159.043 30.726 159.223 32.904 ;
     RECT  159.187 2.151 159.439 26.154 ;
     RECT  158.719 27.072 159.439 27.324 ;
     RECT  159.223 28.836 159.439 32.904 ;
     RECT  157.464 33.858 159.439 34.344 ;
     RECT  159.439 2.151 159.516 27.324 ;
     RECT  159.439 28.836 159.516 34.794 ;
     RECT  157.464 36.486 159.516 95.049 ;
     RECT  159.516 2.151 160.159 95.049 ;
     RECT  160.159 1.728 160.727 95.049 ;
     RECT  160.727 2.151 161.815 95.049 ;
     RECT  161.815 2.106 162.347 95.049 ;
     RECT  162.347 2.151 165.127 95.049 ;
     RECT  165.127 2.106 165.407 95.049 ;
     RECT  165.407 2.151 168.439 95.049 ;
     RECT  168.439 1.728 168.647 95.049 ;
     RECT  168.647 2.151 171.751 95.049 ;
     RECT  171.751 1.728 171.995 95.049 ;
     RECT  171.995 2.151 175.063 95.049 ;
     RECT  175.063 1.728 175.523 95.049 ;
     RECT  175.523 2.151 176.719 95.049 ;
     RECT  176.719 1.728 177.179 95.049 ;
     RECT  177.179 2.151 191.587 95.049 ;
     RECT  191.587 1.728 191.723 95.049 ;
     RECT  191.723 2.151 196.555 95.049 ;
     RECT  196.555 2.106 196.727 95.049 ;
     RECT  196.727 2.151 198.211 95.049 ;
     RECT  198.211 1.728 198.347 95.049 ;
     RECT  198.347 2.151 204.835 95.049 ;
     RECT  204.835 2.106 205.475 95.049 ;
     RECT  205.475 2.151 211.423 95.049 ;
     RECT  211.423 2.106 211.523 95.049 ;
     RECT  211.523 2.151 213.079 95.049 ;
     RECT  213.079 2.07 213.251 95.049 ;
     RECT  213.251 2.151 214.735 95.049 ;
     RECT  214.735 2.106 215.195 95.049 ;
     RECT  215.195 2.151 218.16 95.049 ;
    LAYER M3 ;
     RECT  17.964 0.108 17.982 0.187 ;
     RECT  29.52 0.108 29.538 0.187 ;
     RECT  31.176 0.108 31.194 0.187 ;
     RECT  32.832 0.108 32.85 0.187 ;
     RECT  36.144 0.108 36.162 0.187 ;
     RECT  44.424 0.108 44.442 0.187 ;
     RECT  46.08 0.108 46.098 0.187 ;
     RECT  51.012 0.108 51.03 0.187 ;
     RECT  57.636 0.108 57.654 0.187 ;
     RECT  62.604 0.108 62.622 0.187 ;
     RECT  64.26 0.108 64.278 0.187 ;
     RECT  69.228 0.108 69.246 0.187 ;
     RECT  82.44 0.108 82.458 0.187 ;
     RECT  84.096 0.108 84.114 0.187 ;
     RECT  95.688 0.108 95.706 0.187 ;
     RECT  100.656 0.108 100.674 0.187 ;
     RECT  115.524 0.108 115.542 0.187 ;
     RECT  132.048 0.108 132.066 0.187 ;
     RECT  133.704 0.108 133.722 0.187 ;
     RECT  146.952 0.108 146.97 0.187 ;
     RECT  158.508 0.108 158.526 0.187 ;
     RECT  160.164 0.108 160.182 0.187 ;
     RECT  166.788 0.108 166.806 0.187 ;
     RECT  183.312 0.108 183.33 0.187 ;
     RECT  186.624 0.108 186.642 0.187 ;
     RECT  201.528 0.108 201.546 0.187 ;
     RECT  213.084 0.108 213.102 0.187 ;
     RECT  214.74 0.108 214.758 0.187 ;
     RECT  9.684 0.108 9.702 0.571 ;
     RECT  80.784 0.108 80.802 0.571 ;
     RECT  97.344 0.108 97.362 0.571 ;
     RECT  99 0.108 99.018 0.571 ;
     RECT  112.212 0.108 112.23 0.571 ;
     RECT  163.476 0.108 163.494 0.571 ;
     RECT  165.132 0.108 165.15 0.571 ;
     RECT  193.248 0.108 193.266 0.571 ;
     RECT  196.56 0.108 196.578 0.571 ;
     RECT  8.028 0.108 8.046 1.147 ;
     RECT  12.996 0.108 13.014 1.147 ;
     RECT  14.652 0.108 14.67 1.147 ;
     RECT  16.308 0.108 16.326 1.147 ;
     RECT  24.552 0.108 24.57 1.147 ;
     RECT  26.208 0.108 26.226 1.147 ;
     RECT  39.456 0.108 39.474 1.147 ;
     RECT  41.112 0.108 41.13 1.147 ;
     RECT  42.768 0.108 42.786 1.147 ;
     RECT  47.736 0.108 47.754 1.147 ;
     RECT  49.392 0.108 49.41 1.147 ;
     RECT  54.324 0.108 54.342 1.147 ;
     RECT  55.98 0.108 55.998 1.147 ;
     RECT  60.948 0.108 60.966 1.147 ;
     RECT  67.572 0.108 67.59 1.147 ;
     RECT  70.884 0.108 70.902 1.147 ;
     RECT  72.54 0.108 72.558 1.147 ;
     RECT  77.472 0.108 77.49 1.147 ;
     RECT  79.128 0.108 79.146 1.147 ;
     RECT  85.752 0.108 85.77 1.147 ;
     RECT  87.408 0.108 87.426 1.147 ;
     RECT  89.064 0.108 89.082 1.147 ;
     RECT  92.376 0.108 92.394 1.147 ;
     RECT  103.932 0.108 103.95 1.147 ;
     RECT  105.588 0.108 105.606 1.147 ;
     RECT  107.244 0.108 107.262 1.147 ;
     RECT  108.9 0.108 108.918 1.147 ;
     RECT  110.556 0.108 110.574 1.147 ;
     RECT  122.148 0.108 122.166 1.147 ;
     RECT  125.46 0.108 125.478 1.147 ;
     RECT  127.116 0.108 127.134 1.147 ;
     RECT  128.772 0.108 128.79 1.147 ;
     RECT  130.392 0.108 130.41 1.147 ;
     RECT  137.016 0.108 137.034 1.147 ;
     RECT  138.672 0.108 138.69 1.147 ;
     RECT  140.328 0.108 140.346 1.147 ;
     RECT  141.984 0.108 142.002 1.147 ;
     RECT  143.64 0.108 143.658 1.147 ;
     RECT  150.264 0.108 150.282 1.147 ;
     RECT  153.576 0.108 153.594 1.147 ;
     RECT  155.232 0.108 155.25 1.147 ;
     RECT  156.852 0.108 156.87 1.147 ;
     RECT  168.444 0.108 168.462 1.147 ;
     RECT  170.1 0.108 170.118 1.147 ;
     RECT  171.756 0.108 171.774 1.147 ;
     RECT  173.412 0.108 173.43 1.147 ;
     RECT  175.068 0.108 175.086 1.147 ;
     RECT  178.38 0.108 178.398 1.147 ;
     RECT  184.968 0.108 184.986 1.147 ;
     RECT  188.28 0.108 188.298 1.147 ;
     RECT  189.936 0.108 189.954 1.147 ;
     RECT  204.84 0.108 204.858 1.147 ;
     RECT  206.496 0.108 206.514 1.147 ;
     RECT  208.152 0.108 208.17 1.147 ;
     RECT  6.372 0.108 6.39 1.723 ;
     RECT  19.62 0.108 19.638 1.723 ;
     RECT  20.448 0.187 20.466 1.723 ;
     RECT  24.444 1.147 24.57 1.723 ;
     RECT  28.872 0.187 29.538 1.723 ;
     RECT  37.8 0.108 37.818 1.723 ;
     RECT  38.808 1.147 39.474 1.723 ;
     RECT  40.608 1.147 41.13 1.723 ;
     RECT  42.228 1.147 42.786 1.723 ;
     RECT  43.776 0.187 44.442 1.723 ;
     RECT  49.248 1.147 49.41 1.723 ;
     RECT  50.364 0.187 51.03 1.723 ;
     RECT  52.668 0.108 52.686 1.723 ;
     RECT  59.292 0.108 59.31 1.723 ;
     RECT  67.392 1.147 67.59 1.723 ;
     RECT  68.508 0.187 69.246 1.723 ;
     RECT  72.288 1.147 72.558 1.723 ;
     RECT  73.332 0.187 73.35 1.723 ;
     RECT  74.196 0.108 74.214 1.723 ;
     RECT  83.556 0.187 84.114 1.723 ;
     RECT  88.344 1.147 89.082 1.723 ;
     RECT  89.964 0.187 89.982 1.723 ;
     RECT  106.848 1.147 107.262 1.723 ;
     RECT  118.836 0.108 118.854 1.723 ;
     RECT  119.7 1.147 119.718 1.723 ;
     RECT  121.536 1.147 122.166 1.723 ;
     RECT  125.1 1.147 125.478 1.723 ;
     RECT  126.54 1.147 127.134 1.723 ;
     RECT  129.96 1.147 130.41 1.723 ;
     RECT  136.44 1.147 137.034 1.723 ;
     RECT  138.348 1.147 138.69 1.723 ;
     RECT  139.644 1.147 140.346 1.723 ;
     RECT  148.608 0.108 148.626 1.723 ;
     RECT  151.92 0.108 151.938 1.723 ;
     RECT  154.584 1.147 155.25 1.723 ;
     RECT  159.516 0.187 160.182 1.723 ;
     RECT  161.028 0.187 161.046 1.723 ;
     RECT  168.156 1.147 168.462 1.723 ;
     RECT  171.324 1.147 171.774 1.723 ;
     RECT  174.42 1.147 175.086 1.723 ;
     RECT  175.968 0.187 175.986 1.723 ;
     RECT  176.724 0.108 176.742 1.723 ;
     RECT  191.592 0.108 191.61 1.723 ;
     RECT  198.216 0.108 198.234 1.723 ;
     RECT  6.372 1.723 6.498 1.751 ;
     RECT  19.62 1.723 20.466 1.751 ;
     RECT  42.228 1.723 44.442 1.751 ;
     RECT  68.508 1.723 69.498 1.751 ;
     RECT  118.836 1.723 119.718 1.751 ;
     RECT  136.44 1.723 137.322 1.751 ;
     RECT  151.92 1.723 152.19 1.751 ;
     RECT  159.516 1.723 161.046 1.751 ;
     RECT  174.42 1.723 175.986 1.751 ;
     RECT  176.724 1.723 177.174 1.751 ;
     RECT  198.216 1.723 198.342 1.751 ;
     RECT  131.364 0.187 132.066 2.065 ;
     RECT  133.308 0.187 133.722 2.065 ;
     RECT  212.472 0.187 213.102 2.065 ;
     RECT  12.564 1.147 13.014 2.101 ;
     RECT  16.02 1.147 16.326 2.101 ;
     RECT  17.388 0.187 17.982 2.101 ;
     RECT  22.932 0.108 22.95 2.101 ;
     RECT  30.708 0.187 31.194 2.101 ;
     RECT  32.112 0.187 32.85 2.101 ;
     RECT  33.696 0.187 33.714 2.101 ;
     RECT  37.692 1.723 37.818 2.101 ;
     RECT  38.808 1.723 41.13 2.101 ;
     RECT  45.36 0.187 46.098 2.101 ;
     RECT  52.632 1.723 52.686 2.101 ;
     RECT  53.784 1.147 54.342 2.101 ;
     RECT  61.956 0.187 62.622 2.101 ;
     RECT  63.756 0.187 64.278 2.101 ;
     RECT  65.088 0.187 65.106 2.101 ;
     RECT  65.916 0.108 65.934 2.101 ;
     RECT  70.524 1.147 70.902 2.101 ;
     RECT  75.852 0.108 75.87 2.101 ;
     RECT  76.968 1.147 77.49 2.101 ;
     RECT  78.84 1.147 79.146 2.101 ;
     RECT  80.244 0.571 80.802 2.101 ;
     RECT  83.556 1.723 84.294 2.101 ;
     RECT  92.16 1.147 92.394 2.101 ;
     RECT  93.24 0.187 93.258 2.101 ;
     RECT  94.032 0.108 94.05 2.101 ;
     RECT  95.076 0.187 95.706 2.101 ;
     RECT  98.424 0.571 99.018 2.101 ;
     RECT  100.116 0.187 100.674 2.101 ;
     RECT  104.904 1.147 105.606 2.101 ;
     RECT  106.848 1.723 107.406 2.101 ;
     RECT  111.708 0.571 112.23 2.101 ;
     RECT  128.268 1.147 128.79 2.101 ;
     RECT  145.296 0.108 145.314 2.101 ;
     RECT  146.376 0.187 146.97 2.101 ;
     RECT  161.82 0.108 161.838 2.101 ;
     RECT  163.008 0.571 163.494 2.101 ;
     RECT  164.556 0.571 165.15 2.101 ;
     RECT  195.84 0.571 196.578 2.101 ;
     RECT  197.424 0.187 197.442 2.101 ;
     RECT  204.12 1.147 204.858 2.101 ;
     RECT  211.428 0.108 211.446 2.101 ;
     RECT  214.056 0.187 214.758 2.101 ;
     RECT  215.784 0.187 215.802 2.101 ;
     RECT  22.932 2.101 23.49 2.129 ;
     RECT  30.708 2.101 33.714 2.129 ;
     RECT  61.956 2.101 65.106 2.129 ;
     RECT  65.916 2.101 66.546 2.129 ;
     RECT  70.524 2.101 71.406 2.129 ;
     RECT  75.852 2.101 77.49 2.129 ;
     RECT  92.16 2.101 93.258 2.129 ;
     RECT  94.032 2.101 95.922 2.129 ;
     RECT  104.904 2.101 107.406 2.129 ;
     RECT  145.296 2.101 146.97 2.129 ;
     RECT  161.82 2.101 163.494 2.129 ;
     RECT  204.12 2.101 205.47 2.129 ;
     RECT  214.056 2.101 215.802 2.129 ;
     RECT  12.564 2.101 13.194 2.143 ;
     RECT  16.02 2.101 17.982 2.143 ;
     RECT  18.828 1.147 18.846 2.143 ;
     RECT  23.4 2.129 23.49 2.143 ;
     RECT  24.444 1.723 24.75 2.143 ;
     RECT  34.488 0.108 34.506 2.143 ;
     RECT  35.532 0.187 36.162 2.143 ;
     RECT  55.512 1.147 55.998 2.143 ;
     RECT  56.952 0.187 57.654 2.143 ;
     RECT  61.956 2.129 62.097 2.143 ;
     RECT  66.384 2.129 66.546 2.143 ;
     RECT  67.392 1.723 67.662 2.143 ;
     RECT  76.428 2.129 77.49 2.143 ;
     RECT  114.84 0.187 115.542 2.143 ;
     RECT  116.424 0.187 116.442 2.143 ;
     RECT  120.492 0.108 120.51 2.143 ;
     RECT  121.536 1.723 122.274 2.143 ;
     RECT  137.304 1.751 137.322 2.143 ;
     RECT  143.064 1.147 143.658 2.143 ;
     RECT  147.852 0.187 147.87 2.143 ;
     RECT  148.608 1.723 148.77 2.143 ;
     RECT  153.072 1.147 153.594 2.143 ;
     RECT  157.788 0.187 158.526 2.143 ;
     RECT  159.516 1.751 159.642 2.143 ;
     RECT  164.556 2.101 165.402 2.143 ;
     RECT  180.036 0.108 180.054 2.143 ;
     RECT  180.9 0.187 180.918 2.143 ;
     RECT  186.192 0.187 186.642 2.143 ;
     RECT  190.836 0.187 190.854 2.143 ;
     RECT  191.592 1.723 191.718 2.143 ;
     RECT  200.808 0.187 201.546 2.143 ;
     RECT  202.356 0.571 202.374 2.143 ;
     RECT  153.072 2.143 153.705 2.191 ;
     RECT  19.8 1.751 20.466 2.219 ;
     RECT  31.572 2.129 33.714 2.219 ;
     RECT  34.488 2.143 36.162 2.219 ;
     RECT  42.228 1.751 42.246 2.219 ;
     RECT  43.236 1.751 44.442 2.219 ;
     RECT  45.36 2.101 46.566 2.219 ;
     RECT  47.304 1.147 47.754 2.219 ;
     RECT  49.248 1.723 49.59 2.219 ;
     RECT  52.632 2.101 54.342 2.219 ;
     RECT  60.444 1.147 60.966 2.219 ;
     RECT  63 2.129 63.774 2.219 ;
     RECT  64.512 2.129 65.106 2.219 ;
     RECT  66.384 2.143 67.662 2.219 ;
     RECT  69.372 1.751 69.498 2.219 ;
     RECT  70.524 2.129 70.542 2.219 ;
     RECT  76.428 2.143 78.105 2.219 ;
     RECT  80.244 2.101 81.054 2.219 ;
     RECT  81.864 0.187 82.458 2.219 ;
     RECT  83.196 2.101 84.294 2.219 ;
     RECT  85.032 1.147 85.77 2.219 ;
     RECT  92.16 2.129 92.178 2.219 ;
     RECT  102.312 0.108 102.33 2.219 ;
     RECT  120.492 2.143 122.274 2.219 ;
     RECT  123.012 0.187 123.03 2.219 ;
     RECT  128.268 2.101 129.078 2.219 ;
     RECT  131.364 2.065 133.722 2.219 ;
     RECT  135.36 0.108 135.378 2.219 ;
     RECT  136.44 1.751 136.458 2.219 ;
     RECT  137.304 2.143 137.505 2.219 ;
     RECT  138.348 1.723 140.526 2.219 ;
     RECT  145.764 2.129 146.97 2.219 ;
     RECT  147.852 2.143 148.77 2.219 ;
     RECT  149.904 1.147 150.282 2.219 ;
     RECT  162.288 2.129 163.494 2.219 ;
     RECT  171.324 1.723 171.99 2.219 ;
     RECT  179.172 0.187 179.19 2.219 ;
     RECT  182.664 0.187 183.33 2.219 ;
     RECT  190.836 2.143 191.718 2.219 ;
     RECT  192.564 0.571 193.266 2.219 ;
     RECT  194.076 0.187 194.094 2.219 ;
     RECT  198.324 1.751 198.342 2.219 ;
     RECT  200.808 2.143 202.374 2.219 ;
     RECT  206.208 1.147 206.514 2.219 ;
     RECT  215.172 2.129 215.802 2.219 ;
     RECT  49.284 2.219 49.59 2.227 ;
     RECT  50.364 1.723 51.174 2.227 ;
     RECT  61.815 2.143 62.097 2.227 ;
     RECT  88.344 1.723 89.982 2.227 ;
     RECT  90.72 0.108 90.738 2.227 ;
     RECT  101.556 0.187 101.574 2.227 ;
     RECT  129.96 1.723 130.518 2.227 ;
     RECT  151.128 0.187 151.146 2.227 ;
     RECT  205.308 2.129 205.47 2.227 ;
     RECT  206.208 2.219 206.406 2.227 ;
     RECT  7.452 1.147 8.046 2.263 ;
     RECT  10.512 0.187 10.53 2.263 ;
     RECT  11.34 0.108 11.358 2.263 ;
     RECT  25.956 1.147 26.226 2.263 ;
     RECT  37.692 2.101 41.13 2.263 ;
     RECT  47.304 2.219 47.646 2.263 ;
     RECT  59.292 1.723 59.634 2.263 ;
     RECT  60.444 2.219 60.93 2.263 ;
     RECT  72.288 1.723 73.35 2.263 ;
     RECT  74.196 1.723 74.322 2.263 ;
     RECT  75.06 0.187 75.078 2.263 ;
     RECT  86.76 1.147 87.426 2.263 ;
     RECT  110.052 1.147 110.574 2.263 ;
     RECT  111.708 2.101 112.338 2.263 ;
     RECT  113.112 0.571 113.13 2.263 ;
     RECT  113.868 0.108 113.886 2.263 ;
     RECT  117.18 0.108 117.198 2.263 ;
     RECT  118.08 0.187 118.098 2.263 ;
     RECT  121.215 2.219 122.274 2.263 ;
     RECT  129.852 2.227 130.518 2.263 ;
     RECT  134.568 0.187 134.586 2.263 ;
     RECT  147.852 2.219 148.497 2.263 ;
     RECT  149.904 2.219 149.922 2.263 ;
     RECT  151.056 2.227 151.146 2.263 ;
     RECT  153.072 2.191 153.774 2.263 ;
     RECT  154.584 1.723 155.43 2.263 ;
     RECT  160.632 1.751 161.046 2.263 ;
     RECT  175.215 1.751 175.986 2.263 ;
     RECT  177.048 1.751 177.174 2.263 ;
     RECT  177.984 1.147 178.398 2.263 ;
     RECT  180.036 2.143 180.918 2.263 ;
     RECT  181.692 0.108 181.71 2.263 ;
     RECT  194.904 0.108 194.922 2.263 ;
     RECT  199.08 0.571 199.098 2.263 ;
     RECT  210.636 0.187 210.654 2.263 ;
     RECT  211.428 2.101 211.518 2.263 ;
     RECT  4.716 0.108 4.734 2.335 ;
     RECT  6.48 1.751 6.498 2.335 ;
     RECT  7.308 2.263 8.046 2.335 ;
     RECT  20.016 2.219 20.466 2.335 ;
     RECT  21.276 0.108 21.294 2.335 ;
     RECT  22.176 0.187 22.194 2.335 ;
     RECT  25.956 2.263 26.298 2.335 ;
     RECT  27.864 0.108 27.882 2.335 ;
     RECT  30.708 2.129 30.798 2.335 ;
     RECT  45.36 2.219 45.954 2.335 ;
     RECT  55.512 2.143 57.654 2.335 ;
     RECT  67.176 2.219 67.662 2.335 ;
     RECT  68.508 1.751 68.526 2.335 ;
     RECT  71.352 2.129 71.406 2.335 ;
     RECT  77.256 2.219 78.105 2.335 ;
     RECT  78.84 2.101 79.326 2.335 ;
     RECT  88.344 2.227 90.738 2.335 ;
     RECT  92.988 2.129 93.258 2.335 ;
     RECT  94.032 2.129 95.094 2.335 ;
     RECT  95.868 2.129 95.922 2.335 ;
     RECT  96.696 0.571 97.362 2.335 ;
     RECT  104.904 2.129 105.297 2.335 ;
     RECT  108.576 1.147 108.918 2.335 ;
     RECT  110.052 2.263 110.934 2.335 ;
     RECT  114.84 2.143 116.442 2.335 ;
     RECT  117.18 2.263 118.278 2.335 ;
     RECT  119.052 1.751 119.718 2.335 ;
     RECT  141.84 1.147 142.002 2.335 ;
     RECT  142.815 2.143 143.658 2.335 ;
     RECT  152.172 1.751 152.19 2.335 ;
     RECT  153.072 2.263 155.43 2.335 ;
     RECT  156.204 1.147 156.87 2.335 ;
     RECT  168.156 1.723 168.642 2.335 ;
     RECT  169.596 1.147 170.118 2.335 ;
     RECT  174.42 1.751 174.438 2.335 ;
     RECT  180.036 2.263 181.71 2.335 ;
     RECT  184.716 1.147 184.986 2.335 ;
     RECT  187.92 1.147 188.298 2.335 ;
     RECT  190.872 2.219 191.718 2.335 ;
     RECT  194.364 2.263 194.922 2.335 ;
     RECT  195.84 2.101 197.442 2.335 ;
     RECT  198.36 2.263 199.098 2.335 ;
     RECT  199.872 0.108 199.89 2.335 ;
     RECT  203.184 0.108 203.202 2.335 ;
     RECT  208.944 0.571 208.962 2.335 ;
     RECT  209.772 0.108 209.79 2.335 ;
     RECT  210.636 2.263 211.518 2.335 ;
     RECT  212.472 2.065 213.246 2.335 ;
     RECT  214.056 2.129 214.074 2.335 ;
     RECT  2.415 2.143 2.505 2.413 ;
     RECT  6.48 2.335 8.046 2.413 ;
     RECT  12.564 2.143 13.305 2.413 ;
     RECT  16.02 2.143 18.846 2.413 ;
     RECT  28.872 1.723 29.61 2.413 ;
     RECT  30.348 2.335 30.798 2.413 ;
     RECT  49.284 2.227 51.174 2.413 ;
     RECT  137.376 2.219 137.505 2.413 ;
     RECT  138.24 2.335 138.258 2.413 ;
     RECT  202.215 2.219 202.374 2.413 ;
     RECT  203.112 2.335 203.202 2.413 ;
     RECT  111.708 2.263 113.13 2.461 ;
     RECT  113.868 2.263 114.03 2.461 ;
     RECT  4.572 2.335 4.734 2.489 ;
     RECT  6.48 2.413 8.097 2.489 ;
     RECT  8.964 0.571 9.702 2.489 ;
     RECT  10.512 2.263 11.358 2.489 ;
     RECT  16.02 2.413 18.897 2.489 ;
     RECT  20.016 2.335 21.294 2.489 ;
     RECT  31.608 2.219 33.354 2.489 ;
     RECT  37.152 2.263 41.13 2.489 ;
     RECT  46.728 2.263 47.646 2.489 ;
     RECT  63 2.219 63.666 2.489 ;
     RECT  80.244 2.219 80.946 2.489 ;
     RECT  92.124 2.335 92.142 2.489 ;
     RECT  101.484 2.227 101.574 2.489 ;
     RECT  106.128 2.129 107.406 2.489 ;
     RECT  114.84 2.335 118.278 2.489 ;
     RECT  123.804 0.108 123.822 2.489 ;
     RECT  125.1 1.723 127.134 2.489 ;
     RECT  131.472 2.219 133.722 2.489 ;
     RECT  135.9 2.263 136.35 2.489 ;
     RECT  152.172 2.335 156.87 2.489 ;
     RECT  179.856 2.335 181.71 2.489 ;
     RECT  190.872 2.335 191.754 2.489 ;
     RECT  194.364 2.335 197.442 2.489 ;
     RECT  205.308 2.227 206.406 2.489 ;
     RECT  208.944 2.335 209.79 2.489 ;
     RECT  117.792 2.489 118.278 2.561 ;
     RECT  166.212 0.187 166.806 2.569 ;
     RECT  5.58 0.571 5.598 2.605 ;
     RECT  14.4 1.147 14.67 2.605 ;
     RECT  22.176 2.335 22.482 2.605 ;
     RECT  23.4 2.143 24.75 2.605 ;
     RECT  25.848 2.335 26.298 2.605 ;
     RECT  27.036 0.571 27.054 2.605 ;
     RECT  27.792 2.335 27.882 2.605 ;
     RECT  42.084 2.263 42.102 2.605 ;
     RECT  71.352 2.335 71.55 2.605 ;
     RECT  72.288 2.263 74.322 2.605 ;
     RECT  75.06 2.263 75.438 2.605 ;
     RECT  95.868 2.335 97.362 2.605 ;
     RECT  98.424 2.101 100.674 2.605 ;
     RECT  103.356 1.147 103.95 2.605 ;
     RECT  104.724 2.335 105.297 2.605 ;
     RECT  108.468 2.335 109.134 2.605 ;
     RECT  109.98 2.335 110.934 2.605 ;
     RECT  111.708 2.461 114.03 2.605 ;
     RECT  114.84 2.489 117.054 2.605 ;
     RECT  125.964 2.489 127.134 2.605 ;
     RECT  134.568 2.263 134.622 2.605 ;
     RECT  141.732 2.335 143.658 2.605 ;
     RECT  144.504 0.571 144.522 2.605 ;
     RECT  156.852 2.489 156.87 2.605 ;
     RECT  157.788 2.143 159.642 2.605 ;
     RECT  169.488 2.335 170.118 2.605 ;
     RECT  173.016 1.147 173.43 2.605 ;
     RECT  174.348 2.335 174.438 2.605 ;
     RECT  184.608 2.335 184.986 2.605 ;
     RECT  186.015 2.143 186.642 2.605 ;
     RECT  189.252 1.147 189.954 2.605 ;
     RECT  198.36 2.335 199.89 2.605 ;
     RECT  200.808 2.219 201.402 2.605 ;
     RECT  202.215 2.413 203.202 2.605 ;
     RECT  210.636 2.335 214.074 2.605 ;
     RECT  7.308 2.489 8.097 2.641 ;
     RECT  12.564 2.413 13.497 2.641 ;
     RECT  27.792 2.605 28.062 2.641 ;
     RECT  28.872 2.413 30.798 2.641 ;
     RECT  37.152 2.489 40.698 2.641 ;
     RECT  55.08 2.335 57.942 2.641 ;
     RECT  59.292 2.263 60.93 2.641 ;
     RECT  64.62 2.219 65.106 2.641 ;
     RECT  82.152 2.219 82.458 2.641 ;
     RECT  83.196 2.219 84.186 2.641 ;
     RECT  86.148 2.263 87.426 2.641 ;
     RECT  88.2 2.335 90.738 2.641 ;
     RECT  107.712 2.605 109.134 2.641 ;
     RECT  109.98 2.605 117.054 2.641 ;
     RECT  117.828 2.561 118.278 2.641 ;
     RECT  119.052 2.335 120.474 2.641 ;
     RECT  134.28 2.605 134.622 2.641 ;
     RECT  139.248 2.219 140.526 2.641 ;
     RECT  150.696 2.263 151.146 2.641 ;
     RECT  152.172 2.489 156.042 2.641 ;
     RECT  166.212 2.569 166.842 2.641 ;
     RECT  168.012 2.335 168.75 2.641 ;
     RECT  169.488 2.605 170.55 2.641 ;
     RECT  171.324 2.219 171.882 2.641 ;
     RECT  187.812 2.335 188.514 2.641 ;
     RECT  189.252 2.605 190.062 2.641 ;
     RECT  202.215 2.605 203.346 2.641 ;
     RECT  204.12 2.129 204.174 2.641 ;
     RECT  183.6 2.263 183.726 2.669 ;
     RECT  16.02 2.489 17.262 2.731 ;
     RECT  18.108 2.489 18.897 2.731 ;
     RECT  36.972 2.641 40.698 2.731 ;
     RECT  49.284 2.413 51.297 2.731 ;
     RECT  54.9 2.641 57.942 2.731 ;
     RECT  103.356 2.605 105.297 2.731 ;
     RECT  128.268 2.219 128.502 2.731 ;
     RECT  139.248 2.641 140.814 2.731 ;
     RECT  141.732 2.605 144.522 2.731 ;
     RECT  156.852 2.605 159.642 2.731 ;
     RECT  160.632 2.263 161.154 2.731 ;
     RECT  164.415 2.143 165.402 2.731 ;
     RECT  183.636 2.669 183.726 2.731 ;
     RECT  184.608 2.605 186.822 2.731 ;
     RECT  187.812 2.641 190.062 2.731 ;
     RECT  4.356 2.641 4.374 2.759 ;
     RECT  5.58 2.605 6.426 2.759 ;
     RECT  11.844 2.641 13.497 2.759 ;
     RECT  25.848 2.605 27.054 2.759 ;
     RECT  44.964 2.335 45.954 2.759 ;
     RECT  54.9 2.731 58.158 2.759 ;
     RECT  71.352 2.605 75.438 2.759 ;
     RECT  76.428 2.219 76.518 2.759 ;
     RECT  91.62 2.605 91.638 2.759 ;
     RECT  103.32 2.731 105.297 2.759 ;
     RECT  107.712 2.641 117.054 2.759 ;
     RECT  145.764 2.219 146.286 2.759 ;
     RECT  150.696 2.641 156.042 2.759 ;
     RECT  156.852 2.731 161.154 2.759 ;
     RECT  166.212 2.641 167.238 2.759 ;
     RECT  168.012 2.641 171.882 2.759 ;
     RECT  173.016 2.605 174.438 2.759 ;
     RECT  184.608 2.731 190.062 2.759 ;
     RECT  202.215 2.641 204.174 2.759 ;
     RECT  210.204 2.605 214.074 2.759 ;
     RECT  86.148 2.641 90.738 2.767 ;
     RECT  166.212 2.759 167.166 2.795 ;
     RECT  12.672 2.759 13.497 2.803 ;
     RECT  14.4 2.605 15.174 2.803 ;
     RECT  102.384 2.335 102.402 2.803 ;
     RECT  103.32 2.759 103.446 2.803 ;
     RECT  34.488 2.219 35.694 2.831 ;
     RECT  150.876 2.759 155.898 2.831 ;
     RECT  9.216 2.489 9.702 2.875 ;
     RECT  10.512 2.489 11.034 2.875 ;
     RECT  21.672 2.605 22.482 2.875 ;
     RECT  23.4 2.605 24.858 2.875 ;
     RECT  25.848 2.759 26.874 2.875 ;
     RECT  59.004 2.641 60.93 2.875 ;
     RECT  64.62 2.641 65.178 2.875 ;
     RECT  66.384 2.219 66.402 2.875 ;
     RECT  67.176 2.335 68.526 2.875 ;
     RECT  69.372 2.219 69.39 2.875 ;
     RECT  92.988 2.335 95.094 2.875 ;
     RECT  95.868 2.605 97.542 2.875 ;
     RECT  207.504 1.147 208.17 2.875 ;
     RECT  208.944 2.489 209.106 2.875 ;
     RECT  210.708 2.759 214.074 2.875 ;
     RECT  5.58 2.759 5.742 2.911 ;
     RECT  27.792 2.641 30.798 2.911 ;
     RECT  70.38 2.335 70.398 2.911 ;
     RECT  98.316 2.605 100.746 2.911 ;
     RECT  124.164 2.605 124.182 2.911 ;
     RECT  125.1 2.489 125.154 2.911 ;
     RECT  139.248 2.731 144.522 2.911 ;
     RECT  168.012 2.759 170.514 2.911 ;
     RECT  173.016 2.759 173.61 2.911 ;
     RECT  180.54 2.489 181.71 2.911 ;
     RECT  182.556 2.227 182.574 2.911 ;
     RECT  183.636 2.731 183.762 2.911 ;
     RECT  184.608 2.759 186.678 2.911 ;
     RECT  187.452 2.759 190.062 2.911 ;
     RECT  207.504 2.875 209.106 2.911 ;
     RECT  36.648 2.731 40.698 3.001 ;
     RECT  45.036 2.759 45.954 3.001 ;
     RECT  46.728 2.489 47.43 3.001 ;
     RECT  104.292 2.759 105.297 3.001 ;
     RECT  139.248 2.911 144.846 3.001 ;
     RECT  9.216 2.875 11.034 3.029 ;
     RECT  21.672 2.875 26.874 3.029 ;
     RECT  27.648 2.911 30.798 3.029 ;
     RECT  31.608 2.489 32.418 3.029 ;
     RECT  34.488 2.831 35.406 3.029 ;
     RECT  41.616 2.605 42.102 3.029 ;
     RECT  43.416 2.219 44.19 3.029 ;
     RECT  45.036 3.001 47.43 3.029 ;
     RECT  48.528 2.605 48.546 3.029 ;
     RECT  49.284 2.731 51.858 3.029 ;
     RECT  55.116 2.759 58.158 3.029 ;
     RECT  58.896 2.875 60.93 3.029 ;
     RECT  71.352 2.759 75.258 3.029 ;
     RECT  76.428 2.759 76.446 3.029 ;
     RECT  98.316 2.911 100.854 3.029 ;
     RECT  101.592 2.641 101.61 3.029 ;
     RECT  124.164 2.911 125.154 3.029 ;
     RECT  128.196 2.731 128.502 3.029 ;
     RECT  147.132 2.263 148.497 3.029 ;
     RECT  172.836 2.911 173.61 3.029 ;
     RECT  174.42 2.759 174.438 3.029 ;
     RECT  183.636 2.911 186.678 3.029 ;
     RECT  210.708 2.875 214.218 3.029 ;
     RECT  18.108 2.731 18.954 3.037 ;
     RECT  92.988 2.875 97.542 3.037 ;
     RECT  107.712 2.759 114.246 3.101 ;
     RECT  151.236 2.831 155.898 3.101 ;
     RECT  41.724 3.029 42.102 3.109 ;
     RECT  50.112 3.029 51.858 3.145 ;
     RECT  52.632 2.219 53.91 3.145 ;
     RECT  67.176 2.875 69.39 3.145 ;
     RECT  70.272 2.911 70.398 3.145 ;
     RECT  77.256 2.335 79.326 3.145 ;
     RECT  102.384 2.803 103.446 3.145 ;
     RECT  104.292 3.001 105.354 3.145 ;
     RECT  106.128 2.489 106.758 3.145 ;
     RECT  129.672 2.263 130.518 3.145 ;
     RECT  135.9 2.489 136.242 3.145 ;
     RECT  137.376 2.413 138.258 3.145 ;
     RECT  147.996 3.029 148.497 3.145 ;
     RECT  149.22 2.263 149.922 3.145 ;
     RECT  164.16 2.731 165.402 3.145 ;
     RECT  166.176 2.803 166.194 3.145 ;
     RECT  175.215 2.263 176.238 3.145 ;
     RECT  177.048 2.263 179.046 3.145 ;
     RECT  205.308 2.489 206.226 3.145 ;
     RECT  215.28 2.219 215.73 3.145 ;
     RECT  12.672 2.803 15.174 3.181 ;
     RECT  15.984 2.731 17.262 3.181 ;
     RECT  29.088 3.029 30.798 3.181 ;
     RECT  31.608 3.029 32.31 3.181 ;
     RECT  61.776 2.227 62.097 3.181 ;
     RECT  63.288 2.489 63.666 3.181 ;
     RECT  64.62 2.875 66.402 3.181 ;
     RECT  67.176 3.145 70.398 3.181 ;
     RECT  82.152 2.641 84.186 3.181 ;
     RECT  85.032 2.219 85.23 3.181 ;
     RECT  121.215 2.263 122.886 3.181 ;
     RECT  134.28 2.641 134.91 3.181 ;
     RECT  135.828 3.145 136.242 3.181 ;
     RECT  146.052 2.759 146.286 3.181 ;
     RECT  147.132 3.029 147.258 3.181 ;
     RECT  162.288 2.219 163.35 3.181 ;
     RECT  164.16 3.145 166.194 3.181 ;
     RECT  171.252 2.759 171.882 3.181 ;
     RECT  172.836 3.029 173.322 3.181 ;
     RECT  175.215 3.145 179.046 3.181 ;
     RECT  180.54 2.911 182.574 3.181 ;
     RECT  187.452 2.911 190.134 3.181 ;
     RECT  190.872 2.489 191.697 3.181 ;
     RECT  192.564 2.219 193.23 3.181 ;
     RECT  194.364 2.489 197.262 3.181 ;
     RECT  203.76 2.759 204.174 3.181 ;
     RECT  205.128 3.145 206.226 3.181 ;
     RECT  111.96 3.101 114.246 3.197 ;
     RECT  92.808 3.037 97.542 3.259 ;
     RECT  7.308 2.641 8.226 3.271 ;
     RECT  33.3 2.489 33.354 3.271 ;
     RECT  36.324 3.001 40.698 3.271 ;
     RECT  45.216 3.029 47.43 3.271 ;
     RECT  61.776 3.181 62.226 3.271 ;
     RECT  63.288 3.181 66.402 3.271 ;
     RECT  67.14 3.181 70.398 3.271 ;
     RECT  71.352 3.029 73.782 3.271 ;
     RECT  81.972 3.181 85.23 3.271 ;
     RECT  86.148 2.767 91.494 3.271 ;
     RECT  137.052 3.145 138.258 3.271 ;
     RECT  139.248 3.001 145.206 3.271 ;
     RECT  157.104 2.759 161.154 3.271 ;
     RECT  162.288 3.181 166.194 3.271 ;
     RECT  12.672 3.181 17.262 3.299 ;
     RECT  29.088 3.181 32.31 3.299 ;
     RECT  81.468 3.271 91.494 3.299 ;
     RECT  92.808 3.259 97.578 3.299 ;
     RECT  117.828 2.641 120.474 3.299 ;
     RECT  131.472 2.489 133.254 3.299 ;
     RECT  137.052 3.271 145.206 3.299 ;
     RECT  157.104 3.271 166.194 3.299 ;
     RECT  174.816 3.181 179.766 3.299 ;
     RECT  192.42 3.181 197.262 3.299 ;
     RECT  203.76 3.181 206.226 3.299 ;
     RECT  207.216 2.911 209.106 3.299 ;
     RECT  214.2 3.029 214.218 3.299 ;
     RECT  176.4 3.299 179.766 3.301 ;
     RECT  180.54 3.181 182.682 3.301 ;
     RECT  50.112 3.145 53.91 3.307 ;
     RECT  104.292 3.145 106.758 3.307 ;
     RECT  107.712 3.101 111.222 3.307 ;
     RECT  133.092 3.299 133.254 3.307 ;
     RECT  134.28 3.181 136.242 3.307 ;
     RECT  137.052 3.299 141.426 3.307 ;
     RECT  96.48 3.299 97.578 3.335 ;
     RECT  113.292 3.197 114.246 3.335 ;
     RECT  124.164 3.029 124.938 3.335 ;
     RECT  77.256 3.145 79.542 3.341 ;
     RECT  7.308 3.271 8.334 3.343 ;
     RECT  9.216 3.029 10.926 3.343 ;
     RECT  98.316 3.029 100.818 3.343 ;
     RECT  118.62 3.299 120.474 3.343 ;
     RECT  121.215 3.181 123.174 3.343 ;
     RECT  125.964 2.605 127.278 3.343 ;
     RECT  128.196 3.029 128.322 3.343 ;
     RECT  129.456 3.145 130.518 3.343 ;
     RECT  205.704 3.299 206.226 3.343 ;
     RECT  97.704 3.343 100.818 3.371 ;
     RECT  12.744 3.299 17.262 3.379 ;
     RECT  18.108 3.037 19.062 3.379 ;
     RECT  20.016 2.489 20.682 3.379 ;
     RECT  21.672 3.029 22.23 3.379 ;
     RECT  61.776 3.271 66.402 3.379 ;
     RECT  67.14 3.271 73.782 3.379 ;
     RECT  118.62 3.343 123.174 3.379 ;
     RECT  124.164 3.335 124.902 3.379 ;
     RECT  129.456 3.343 130.626 3.379 ;
     RECT  198.36 2.605 201.402 3.379 ;
     RECT  202.215 2.759 202.914 3.379 ;
     RECT  207.216 3.299 208.242 3.379 ;
     RECT  208.98 3.299 209.106 3.379 ;
     RECT  115.092 2.759 117.054 3.403 ;
     RECT  117.828 3.299 117.846 3.403 ;
     RECT  129.06 3.379 130.626 3.403 ;
     RECT  131.472 3.299 132.297 3.403 ;
     RECT  192.744 3.299 197.262 3.403 ;
     RECT  77.976 3.341 79.542 3.415 ;
     RECT  80.352 2.489 80.694 3.415 ;
     RECT  104.292 3.307 111.222 3.437 ;
     RECT  162.864 3.299 166.194 3.437 ;
     RECT  11.844 2.759 11.862 3.451 ;
     RECT  33.156 3.271 33.354 3.451 ;
     RECT  125.964 3.343 128.322 3.451 ;
     RECT  207.18 3.379 208.242 3.451 ;
     RECT  208.98 3.379 209.214 3.451 ;
     RECT  215.208 3.145 215.73 3.451 ;
     RECT  5.292 2.911 5.742 3.541 ;
     RECT  12.744 3.379 19.062 3.541 ;
     RECT  20.016 3.379 22.23 3.541 ;
     RECT  59.04 3.029 60.93 3.541 ;
     RECT  76.212 3.145 76.23 3.541 ;
     RECT  77.976 3.415 80.694 3.541 ;
     RECT  81.468 3.299 91.458 3.541 ;
     RECT  7.308 3.343 10.926 3.547 ;
     RECT  208.98 3.451 209.79 3.547 ;
     RECT  210.708 3.029 213.462 3.547 ;
     RECT  12.744 3.541 22.23 3.569 ;
     RECT  36.324 3.271 40.95 3.569 ;
     RECT  50.112 3.307 54.126 3.569 ;
     RECT  59.04 3.541 60.966 3.569 ;
     RECT  61.776 3.379 73.782 3.569 ;
     RECT  77.22 3.415 77.238 3.569 ;
     RECT  77.976 3.541 91.458 3.569 ;
     RECT  107.532 3.437 111.222 3.569 ;
     RECT  111.96 3.197 112.41 3.569 ;
     RECT  118.62 3.379 124.902 3.569 ;
     RECT  125.676 3.451 128.322 3.569 ;
     RECT  162.864 3.437 163.134 3.569 ;
     RECT  171.252 3.181 173.322 3.569 ;
     RECT  176.4 3.301 182.682 3.569 ;
     RECT  198.36 3.379 202.914 3.569 ;
     RECT  208.98 3.547 213.462 3.569 ;
     RECT  5.076 3.541 5.742 3.581 ;
     RECT  13.215 3.569 22.23 3.605 ;
     RECT  37.944 3.569 40.95 3.605 ;
     RECT  48.636 3.181 48.798 3.605 ;
     RECT  92.808 3.299 95.742 3.605 ;
     RECT  207.072 3.451 208.242 3.605 ;
     RECT  187.452 3.181 191.697 3.649 ;
     RECT  212.508 3.569 213.426 3.677 ;
     RECT  36.324 3.569 37.17 3.685 ;
     RECT  92.808 3.605 94.77 3.685 ;
     RECT  102.024 3.145 103.446 3.685 ;
     RECT  115.092 3.403 117.846 3.685 ;
     RECT  147.996 3.145 149.922 3.685 ;
     RECT  164.16 3.437 166.194 3.685 ;
     RECT  166.968 2.795 167.166 3.685 ;
     RECT  23.004 3.029 26.874 3.713 ;
     RECT  50.112 3.569 52.434 3.713 ;
     RECT  11.808 3.451 11.862 3.721 ;
     RECT  33.156 3.451 33.462 3.721 ;
     RECT  34.488 3.029 35.097 3.721 ;
     RECT  43.632 3.029 44.19 3.721 ;
     RECT  60.336 3.569 60.966 3.721 ;
     RECT  61.776 3.569 63.27 3.721 ;
     RECT  147.996 3.685 150.498 3.721 ;
     RECT  151.236 3.101 155.862 3.721 ;
     RECT  164.16 3.685 167.166 3.721 ;
     RECT  167.94 2.911 170.514 3.721 ;
     RECT  183.672 3.029 186.678 3.721 ;
     RECT  192.744 3.403 197.334 3.721 ;
     RECT  198.36 3.569 200.934 3.721 ;
     RECT  201.672 3.569 202.914 3.721 ;
     RECT  203.76 3.299 204.966 3.721 ;
     RECT  6.732 3.547 10.926 3.725 ;
     RECT  123.804 3.569 124.902 3.773 ;
     RECT  133.092 3.307 141.426 3.773 ;
     RECT  41.724 3.109 42.354 3.811 ;
     RECT  43.632 3.721 44.262 3.811 ;
     RECT  45.216 3.271 47.754 3.811 ;
     RECT  55.116 3.029 58.014 3.811 ;
     RECT  59.04 3.569 59.562 3.811 ;
     RECT  74.664 3.029 75.006 3.811 ;
     RECT  157.104 3.299 161.946 3.811 ;
     RECT  108.288 3.569 111.222 3.835 ;
     RECT  5.22 3.581 5.742 3.839 ;
     RECT  23.472 3.713 26.874 3.839 ;
     RECT  29.088 3.299 32.274 3.839 ;
     RECT  37.944 3.605 39.474 3.839 ;
     RECT  92.448 3.685 94.77 3.839 ;
     RECT  102.024 3.685 103.518 3.839 ;
     RECT  104.292 3.437 106.758 3.839 ;
     RECT  118.62 3.569 122.994 3.839 ;
     RECT  133.092 3.773 140.562 3.839 ;
     RECT  147.996 3.721 155.862 3.839 ;
     RECT  176.58 3.569 182.682 3.839 ;
     RECT  187.452 3.649 191.754 3.839 ;
     RECT  214.236 3.451 215.73 3.839 ;
     RECT  16.2 3.605 22.23 3.847 ;
     RECT  164.16 3.721 170.514 3.869 ;
     RECT  5.22 3.839 5.598 3.875 ;
     RECT  16.2 3.847 22.338 3.875 ;
     RECT  33.048 3.721 35.097 3.875 ;
     RECT  41.724 3.811 42.822 3.875 ;
     RECT  64.044 3.569 73.782 3.875 ;
     RECT  78.015 3.569 85.77 3.875 ;
     RECT  133.164 3.839 140.562 3.875 ;
     RECT  142.2 3.299 145.206 3.875 ;
     RECT  155.844 3.839 155.862 3.875 ;
     RECT  192.744 3.721 197.478 3.875 ;
     RECT  198.252 3.721 200.934 3.875 ;
     RECT  66.6 3.875 73.782 3.883 ;
     RECT  74.592 3.811 75.006 3.883 ;
     RECT  100.872 3.847 100.89 3.883 ;
     RECT  126.252 3.569 128.322 3.883 ;
     RECT  129.06 3.403 132.297 3.883 ;
     RECT  95.688 3.605 95.742 3.911 ;
     RECT  187.452 3.839 189.162 3.911 ;
     RECT  53.244 3.569 54.126 3.919 ;
     RECT  146.052 3.181 147.258 3.931 ;
     RECT  147.996 3.839 151.146 3.931 ;
     RECT  156.744 3.811 161.946 3.931 ;
     RECT  183.672 3.721 186.714 3.931 ;
     RECT  187.452 3.911 188.046 3.931 ;
     RECT  26.712 3.839 26.874 3.955 ;
     RECT  27.648 3.029 28.026 3.955 ;
     RECT  45.216 3.811 47.79 3.955 ;
     RECT  6.876 3.725 10.926 3.983 ;
     RECT  33.516 3.875 35.097 3.983 ;
     RECT  35.892 3.685 37.17 3.983 ;
     RECT  55.008 3.811 59.562 3.983 ;
     RECT  66.6 3.883 75.006 3.983 ;
     RECT  75.78 3.541 76.23 3.983 ;
     RECT  114.732 3.685 117.846 3.983 ;
     RECT  146.052 3.931 151.146 3.983 ;
     RECT  156.456 3.931 161.946 3.983 ;
     RECT  7.704 3.983 10.926 3.991 ;
     RECT  40.215 3.605 40.95 3.991 ;
     RECT  41.724 3.875 42.03 3.991 ;
     RECT  43.632 3.811 44.478 3.991 ;
     RECT  50.112 3.713 51.678 3.991 ;
     RECT  174.816 3.299 175.554 3.991 ;
     RECT  176.616 3.839 182.682 3.991 ;
     RECT  183.672 3.931 188.046 3.991 ;
     RECT  135.18 3.875 140.562 4.061 ;
     RECT  26.712 3.955 28.134 4.075 ;
     RECT  42.804 3.875 42.822 4.081 ;
     RECT  43.596 3.991 44.478 4.081 ;
     RECT  7.704 3.991 11.07 4.109 ;
     RECT  16.2 3.875 17.694 4.109 ;
     RECT  33.66 3.983 35.097 4.109 ;
     RECT  37.98 3.839 39.474 4.109 ;
     RECT  45.216 3.955 48.078 4.109 ;
     RECT  66.6 3.983 68.814 4.109 ;
     RECT  78.015 3.875 80.01 4.109 ;
     RECT  83.268 3.875 85.77 4.109 ;
     RECT  93.132 3.839 94.77 4.109 ;
     RECT  104.292 3.839 106.722 4.109 ;
     RECT  113.292 3.335 113.778 4.109 ;
     RECT  122.976 3.839 122.994 4.109 ;
     RECT  126.252 3.883 132.297 4.109 ;
     RECT  133.164 3.875 134.19 4.109 ;
     RECT  136.152 4.061 140.562 4.109 ;
     RECT  146.052 3.983 147.258 4.109 ;
     RECT  156.744 3.983 161.946 4.109 ;
     RECT  171.252 3.569 172.962 4.109 ;
     RECT  176.616 3.991 188.046 4.109 ;
     RECT  192.78 3.875 197.478 4.109 ;
     RECT  86.58 3.569 91.458 4.117 ;
     RECT  97.704 3.371 100.134 4.123 ;
     RECT  100.872 3.883 101.286 4.123 ;
     RECT  18.54 3.875 22.338 4.145 ;
     RECT  23.472 3.839 25.83 4.145 ;
     RECT  42.804 4.081 44.478 4.145 ;
     RECT  50.076 3.991 51.678 4.145 ;
     RECT  60.336 3.721 63.27 4.145 ;
     RECT  66.6 4.109 68.67 4.145 ;
     RECT  97.704 4.123 101.286 4.145 ;
     RECT  104.292 4.109 106.506 4.145 ;
     RECT  112.248 3.569 112.41 4.145 ;
     RECT  118.62 3.839 122.202 4.145 ;
     RECT  136.368 4.109 140.454 4.145 ;
     RECT  148.215 3.983 151.146 4.145 ;
     RECT  152.208 3.839 155.07 4.145 ;
     RECT  160.524 4.109 161.946 4.145 ;
     RECT  164.304 3.869 170.514 4.145 ;
     RECT  171.252 4.109 172.854 4.145 ;
     RECT  183.996 4.109 184.014 4.145 ;
     RECT  194.22 4.109 197.478 4.145 ;
     RECT  207.108 3.605 208.242 4.145 ;
     RECT  26.712 4.075 28.314 4.157 ;
     RECT  86.58 4.117 92.07 4.157 ;
     RECT  34.452 4.109 35.097 4.181 ;
     RECT  40.215 3.991 42.03 4.181 ;
     RECT  69.588 3.983 75.006 4.181 ;
     RECT  74.196 4.181 75.006 4.189 ;
     RECT  75.78 3.983 75.87 4.189 ;
     RECT  96.48 3.335 96.786 4.189 ;
     RECT  98.604 4.145 101.286 4.189 ;
     RECT  102.024 3.839 103.302 4.189 ;
     RECT  207.252 4.145 208.242 4.189 ;
     RECT  208.98 3.569 211.734 4.189 ;
     RECT  80.748 3.875 82.386 4.217 ;
     RECT  164.304 4.145 168.174 4.217 ;
     RECT  198.936 3.875 200.934 4.217 ;
     RECT  104.292 4.145 106.434 4.219 ;
     RECT  45.216 4.109 45.99 4.225 ;
     RECT  77.148 3.721 77.166 4.225 ;
     RECT  95.94 4.189 96.786 4.225 ;
     RECT  124.884 3.773 124.902 4.225 ;
     RECT  146.052 4.109 146.106 4.225 ;
     RECT  195.66 4.145 197.478 4.225 ;
     RECT  201.672 3.721 204.966 4.225 ;
     RECT  205.704 3.343 206.262 4.225 ;
     RECT  17.388 4.109 17.694 4.253 ;
     RECT  38.304 4.109 38.61 4.253 ;
     RECT  39.42 4.109 39.474 4.253 ;
     RECT  46.764 4.109 48.078 4.253 ;
     RECT  98.604 4.189 103.302 4.253 ;
     RECT  108.288 3.835 111.438 4.253 ;
     RECT  176.652 4.109 183.114 4.253 ;
     RECT  9.828 4.109 11.07 4.261 ;
     RECT  11.808 3.721 11.934 4.261 ;
     RECT  28.008 4.157 28.314 4.261 ;
     RECT  29.088 3.839 30.618 4.261 ;
     RECT  34.704 4.181 35.097 4.261 ;
     RECT  35.892 3.983 36.234 4.261 ;
     RECT  131.472 4.109 132.297 4.261 ;
     RECT  145.944 4.225 146.106 4.261 ;
     RECT  174.096 3.991 175.554 4.261 ;
     RECT  31.356 3.839 32.274 4.289 ;
     RECT  42.804 4.145 43.902 4.289 ;
     RECT  66.6 4.145 67.986 4.289 ;
     RECT  37.044 3.983 37.17 4.301 ;
     RECT  74.196 4.189 75.87 4.301 ;
     RECT  104.148 4.219 106.434 4.301 ;
     RECT  174.096 4.261 175.662 4.301 ;
     RECT  207.252 4.189 211.734 4.349 ;
     RECT  49.176 3.883 49.338 4.351 ;
     RECT  9.828 4.261 11.934 4.379 ;
     RECT  20.7 4.145 22.338 4.379 ;
     RECT  28.008 4.261 30.618 4.379 ;
     RECT  66.6 4.289 67.806 4.379 ;
     RECT  69.588 4.181 73.386 4.379 ;
     RECT  74.196 4.301 75.078 4.379 ;
     RECT  78.015 4.109 79.974 4.379 ;
     RECT  81.9 4.217 82.386 4.379 ;
     RECT  83.415 4.109 85.77 4.379 ;
     RECT  100.728 4.253 103.302 4.379 ;
     RECT  104.724 4.301 106.434 4.379 ;
     RECT  108.828 4.253 111.438 4.379 ;
     RECT  113.292 4.109 113.67 4.379 ;
     RECT  118.908 4.145 122.202 4.379 ;
     RECT  123.804 3.773 124.038 4.379 ;
     RECT  162.936 3.569 163.134 4.379 ;
     RECT  169.236 4.145 170.514 4.379 ;
     RECT  171.252 4.145 172.53 4.379 ;
     RECT  174.24 4.301 175.662 4.379 ;
     RECT  178.272 4.253 183.114 4.379 ;
     RECT  189.108 3.911 189.162 4.379 ;
     RECT  192.78 4.109 193.086 4.379 ;
     RECT  195.66 4.225 198.162 4.379 ;
     RECT  201.672 4.225 206.262 4.379 ;
     RECT  207.252 4.349 210.654 4.379 ;
     RECT  214.236 3.839 214.506 4.379 ;
     RECT  11.052 4.379 11.934 4.415 ;
     RECT  20.7 4.379 20.934 4.415 ;
     RECT  28.008 4.379 29.697 4.415 ;
     RECT  64.044 3.875 65.826 4.415 ;
     RECT  76.644 4.225 77.166 4.415 ;
     RECT  78.015 4.379 79.902 4.415 ;
     RECT  83.415 4.379 85.626 4.415 ;
     RECT  86.58 4.157 91.458 4.415 ;
     RECT  100.728 4.379 102.69 4.415 ;
     RECT  104.724 4.379 105.57 4.415 ;
     RECT  126.252 4.109 126.897 4.415 ;
     RECT  127.692 4.109 130.626 4.415 ;
     RECT  136.368 4.145 139.734 4.415 ;
     RECT  148.215 4.145 149.67 4.415 ;
     RECT  171.252 4.379 172.458 4.415 ;
     RECT  178.272 4.379 182.106 4.415 ;
     RECT  198.936 4.217 199.674 4.415 ;
     RECT  201.672 4.379 203.994 4.415 ;
     RECT  95.94 4.225 96.966 4.445 ;
     RECT  189.9 3.839 191.754 4.445 ;
     RECT  192.816 4.379 193.086 4.445 ;
     RECT  86.688 4.415 91.458 4.451 ;
     RECT  98.604 4.253 99.897 4.451 ;
     RECT  100.728 4.415 101.574 4.451 ;
     RECT  184.86 4.109 188.046 4.451 ;
     RECT  11.88 4.415 11.934 4.459 ;
     RECT  148.215 4.415 148.914 4.487 ;
     RECT  179.136 4.415 182.106 4.487 ;
     RECT  184.932 4.451 188.046 4.487 ;
     RECT  199.008 4.415 199.674 4.487 ;
     RECT  82.044 4.379 82.386 4.493 ;
     RECT  40.215 4.181 41.166 4.495 ;
     RECT  11.88 4.459 11.97 4.496 ;
     RECT  82.188 4.493 82.386 4.496 ;
     RECT  113.292 4.379 113.31 4.507 ;
     RECT  161.928 4.145 161.946 4.507 ;
     RECT  74.988 4.379 75.078 4.523 ;
     RECT  79.092 4.415 79.902 4.523 ;
     RECT  82.188 4.496 82.278 4.523 ;
     RECT  83.415 4.415 85.05 4.523 ;
     RECT  86.688 4.451 89.622 4.523 ;
     RECT  47.232 4.253 48.078 4.531 ;
     RECT  52.416 3.713 52.434 4.531 ;
     RECT  53.244 3.919 54.162 4.531 ;
     RECT  55.008 3.983 57.762 4.531 ;
     RECT  161.928 4.507 162.018 4.531 ;
     RECT  190.764 4.445 191.754 4.531 ;
     RECT  40.212 4.495 41.166 4.541 ;
     RECT  44.856 4.225 45.99 4.541 ;
     RECT  47.232 4.531 48.186 4.541 ;
     RECT  52.416 4.531 57.762 4.541 ;
     RECT  102.672 4.415 102.69 4.541 ;
     RECT  133.524 4.109 134.19 4.541 ;
     RECT  160.524 4.145 161.01 4.541 ;
     RECT  28.044 4.415 28.458 4.559 ;
     RECT  29.268 4.415 29.697 4.559 ;
     RECT  50.112 4.145 51.678 4.559 ;
     RECT  60.948 4.145 63.27 4.559 ;
     RECT  86.868 4.523 89.622 4.559 ;
     RECT  96.084 4.445 96.966 4.559 ;
     RECT  112.86 4.507 113.31 4.559 ;
     RECT  123.12 4.507 123.282 4.559 ;
     RECT  156.744 4.109 159.297 4.559 ;
     RECT  168.156 4.217 168.174 4.559 ;
     RECT  186.015 4.487 188.046 4.559 ;
     RECT  204.732 4.379 206.262 4.559 ;
     RECT  211.428 4.349 211.734 4.559 ;
     RECT  214.236 4.379 214.362 4.648 ;
     RECT  21.672 4.379 22.338 4.649 ;
     RECT  26.712 4.157 27.27 4.649 ;
     RECT  34.704 4.261 36.234 4.649 ;
     RECT  47.304 4.541 48.186 4.649 ;
     RECT  50.364 4.559 51.678 4.649 ;
     RECT  64.368 4.415 65.826 4.649 ;
     RECT  96.084 4.559 96.786 4.649 ;
     RECT  106.344 4.379 106.434 4.649 ;
     RECT  133.668 4.541 134.19 4.649 ;
     RECT  153.612 4.145 155.07 4.649 ;
     RECT  204.732 4.559 204.93 4.649 ;
     RECT  214.128 4.648 214.362 4.649 ;
     RECT  215.424 3.839 215.586 4.649 ;
     RECT  40.215 4.541 41.166 4.685 ;
     RECT  52.668 4.541 57.762 4.685 ;
     RECT  64.368 4.649 65.754 4.685 ;
     RECT  86.976 4.559 89.622 4.685 ;
     RECT  96.084 4.649 96.642 4.685 ;
     RECT  106.344 4.649 106.362 4.685 ;
     RECT  146.844 4.109 147.258 4.685 ;
     RECT  202.14 4.415 203.994 4.685 ;
     RECT  204.732 4.649 204.786 4.685 ;
     RECT  207.252 4.379 209.79 4.685 ;
     RECT  214.128 4.649 214.146 4.685 ;
     RECT  215.424 4.649 215.442 4.685 ;
     RECT  35.928 4.649 36.234 4.721 ;
     RECT  86.976 4.685 89.586 4.757 ;
     RECT  207.252 4.685 208.17 4.757 ;
     RECT  22.104 4.649 22.338 4.793 ;
     RECT  47.412 4.649 48.186 4.793 ;
     RECT  49.14 4.351 49.338 5.161 ;
     RECT  99.252 4.451 99.897 5.947 ;
     RECT  100.728 4.451 101.286 5.947 ;
     RECT  38.376 4.253 38.61 5.971 ;
     RECT  39.456 4.253 39.474 5.971 ;
     RECT  80.748 4.217 81.09 5.971 ;
     RECT  82.26 4.523 82.278 5.971 ;
     RECT  169.272 4.379 170.514 5.971 ;
     RECT  18.54 4.145 19.962 5.999 ;
     RECT  45 4.541 45.99 5.999 ;
     RECT  78.015 4.415 78.354 5.999 ;
     RECT  86.976 4.757 89.097 5.999 ;
     RECT  99.252 5.947 101.286 5.999 ;
     RECT  186.015 4.559 187.434 5.999 ;
     RECT  31.428 4.289 32.274 6.547 ;
     RECT  74.988 4.523 75.042 6.547 ;
     RECT  75.852 4.301 75.87 6.547 ;
     RECT  174.24 4.379 174.402 6.547 ;
     RECT  18.615 5.999 19.962 6.575 ;
     RECT  187.416 5.999 187.434 6.575 ;
     RECT  42.012 4.181 42.03 6.583 ;
     RECT  31.428 6.547 32.454 6.611 ;
     RECT  99.252 5.999 99.897 6.817 ;
     RECT  61.308 4.559 63.27 7.123 ;
     RECT  179.748 4.487 182.106 7.123 ;
     RECT  22.104 4.793 22.23 7.151 ;
     RECT  80.748 5.971 82.278 7.151 ;
     RECT  99.18 6.817 99.897 7.151 ;
     RECT  190.764 4.531 191.79 7.151 ;
     RECT  37.152 4.301 37.17 7.663 ;
     RECT  38.376 5.971 39.474 7.663 ;
     RECT  86.976 5.999 87.498 7.663 ;
     RECT  178.272 4.415 178.29 7.663 ;
     RECT  23.472 4.145 25.686 7.691 ;
     RECT  191.415 7.151 191.79 7.691 ;
     RECT  42.804 4.289 43.722 8.239 ;
     RECT  45 5.999 45.897 8.239 ;
     RECT  81.072 7.151 82.278 8.239 ;
     RECT  83.415 4.523 84.474 8.239 ;
     RECT  176.652 4.253 177.534 8.239 ;
     RECT  178.272 7.663 178.506 8.239 ;
     RECT  7.704 4.109 8.802 8.267 ;
     RECT  100.728 5.999 101.286 8.267 ;
     RECT  199.62 4.487 199.674 8.267 ;
     RECT  42.804 8.239 45.897 8.815 ;
     RECT  175.215 4.379 175.662 8.815 ;
     RECT  176.652 8.239 178.506 8.815 ;
     RECT  31.428 6.611 31.662 8.843 ;
     RECT  96.084 4.685 96.498 8.843 ;
     RECT  202.14 4.685 203.238 8.843 ;
     RECT  22.104 7.151 22.122 9.163 ;
     RECT  20.7 4.415 20.718 9.211 ;
     RECT  26.856 4.649 26.946 9.211 ;
     RECT  22.104 9.163 22.554 9.239 ;
     RECT  20.7 9.211 21.006 9.248 ;
     RECT  26.784 9.211 26.946 9.341 ;
     RECT  168.696 5.971 170.514 9.391 ;
     RECT  97.704 4.145 97.722 9.419 ;
     RECT  202.215 8.843 203.238 9.419 ;
     RECT  171.252 4.415 172.026 9.931 ;
     RECT  212.508 3.677 213.354 9.959 ;
     RECT  142.272 3.875 144.45 10.319 ;
     RECT  199.62 8.267 199.638 10.597 ;
     RECT  199.224 10.597 199.638 10.637 ;
     RECT  28.44 4.559 28.458 10.699 ;
     RECT  29.415 4.559 29.697 10.741 ;
     RECT  30.456 4.379 30.618 10.741 ;
     RECT  96.084 8.843 96.102 10.741 ;
     RECT  28.224 10.699 28.458 10.769 ;
     RECT  29.415 10.741 30.618 10.829 ;
     RECT  95.976 10.741 96.102 10.829 ;
     RECT  199.584 10.637 199.638 10.829 ;
     RECT  69.588 4.379 73.242 10.831 ;
     RECT  74.196 4.379 74.214 10.831 ;
     RECT  74.988 6.547 75.87 10.831 ;
     RECT  66.96 4.379 67.806 10.859 ;
     RECT  74.196 10.831 75.87 10.859 ;
     RECT  79.092 4.523 79.506 10.859 ;
     RECT  133.668 4.649 134.154 10.859 ;
     RECT  141.408 3.773 141.426 10.859 ;
     RECT  144.396 10.319 144.45 10.859 ;
     RECT  145.656 4.261 146.106 10.859 ;
     RECT  147.24 4.685 147.258 10.859 ;
     RECT  64.368 4.685 65.358 10.975 ;
     RECT  131.472 4.261 132.39 10.975 ;
     RECT  142.272 10.319 143.55 10.975 ;
     RECT  163.116 4.379 163.134 11.101 ;
     RECT  164.304 4.217 167.346 11.101 ;
     RECT  67.032 10.859 67.806 11.129 ;
     RECT  127.692 4.415 129.042 11.129 ;
     RECT  136.368 4.415 138.654 11.129 ;
     RECT  139.716 4.415 139.734 11.129 ;
     RECT  211.716 4.559 211.734 11.129 ;
     RECT  74.268 10.859 75.87 11.201 ;
     RECT  135.18 4.061 135.378 11.245 ;
     RECT  142.2 10.975 143.55 11.245 ;
     RECT  145.728 10.859 146.106 11.245 ;
     RECT  146.844 10.975 146.862 11.245 ;
     RECT  126.54 4.415 126.897 11.399 ;
     RECT  127.692 11.129 128.322 11.399 ;
     RECT  136.98 11.129 138.654 11.399 ;
     RECT  110.415 4.379 111.438 11.407 ;
     RECT  112.968 4.559 113.31 11.407 ;
     RECT  117.828 3.983 117.846 11.407 ;
     RECT  148.215 4.487 148.59 11.407 ;
     RECT  155.052 4.649 155.07 11.407 ;
     RECT  112.968 11.407 113.418 11.435 ;
     RECT  117.828 11.407 117.99 11.435 ;
     RECT  152.208 4.145 152.802 11.435 ;
     RECT  155.052 11.407 155.25 11.435 ;
     RECT  123.264 4.559 123.282 11.515 ;
     RECT  124.02 4.379 124.038 11.515 ;
     RECT  135.18 11.245 136.134 11.515 ;
     RECT  156.744 4.559 156.762 11.515 ;
     RECT  67.215 11.129 67.806 11.669 ;
     RECT  118.908 4.379 119.646 11.669 ;
     RECT  123.264 11.515 124.038 11.669 ;
     RECT  124.884 4.225 125.478 11.669 ;
     RECT  129.852 4.415 129.87 11.669 ;
     RECT  133.668 10.859 134.082 11.669 ;
     RECT  149.652 4.415 149.67 11.669 ;
     RECT  150.624 4.145 151.146 11.669 ;
     RECT  153.615 4.649 154.098 11.669 ;
     RECT  77.22 4.531 77.238 11.677 ;
     RECT  78.015 5.999 78.297 11.677 ;
     RECT  13.215 3.605 15.426 11.705 ;
     RECT  90.432 4.451 91.458 11.705 ;
     RECT  210.636 4.379 210.654 11.705 ;
     RECT  69.588 10.831 73.314 11.785 ;
     RECT  120.78 4.379 122.202 11.785 ;
     RECT  123.264 11.669 123.318 11.785 ;
     RECT  125.028 11.669 125.478 11.785 ;
     RECT  130.608 4.415 130.626 11.785 ;
     RECT  148.215 11.407 148.77 11.785 ;
     RECT  152.244 11.435 152.802 11.785 ;
     RECT  153.615 11.669 153.897 11.785 ;
     RECT  157.932 4.559 159.297 11.785 ;
     RECT  110.415 11.407 111.51 11.939 ;
     RECT  113.004 11.435 113.418 11.939 ;
     RECT  117.864 11.435 117.99 11.939 ;
     RECT  120.78 11.785 123.318 11.939 ;
     RECT  155.088 11.435 155.25 11.939 ;
     RECT  114.732 3.983 117.054 11.947 ;
     RECT  120.78 11.939 121.806 11.947 ;
     RECT  156.744 11.515 156.906 11.947 ;
     RECT  60.588 7.123 63.27 12.209 ;
     RECT  114.444 11.947 117.054 12.209 ;
     RECT  150.696 11.669 151.146 12.209 ;
     RECT  86.616 7.663 87.498 12.253 ;
     RECT  11.88 4.496 11.934 12.281 ;
     RECT  96.084 10.829 96.102 12.281 ;
     RECT  209.556 4.685 209.79 12.281 ;
     RECT  79.164 10.859 79.506 12.289 ;
     RECT  79.02 12.289 79.506 12.317 ;
     RECT  75.024 11.201 75.87 12.361 ;
     RECT  81.072 8.239 84.474 12.479 ;
     RECT  114.444 12.209 116.838 12.479 ;
     RECT  118.944 11.669 119.646 12.488 ;
     RECT  77.22 11.677 78.297 12.523 ;
     RECT  79.02 12.317 79.326 12.523 ;
     RECT  110.415 11.939 111.366 12.523 ;
     RECT  192.96 4.445 193.086 12.712 ;
     RECT  88.815 5.999 89.097 12.721 ;
     RECT  157.824 11.785 159.354 12.749 ;
     RECT  192.816 12.712 193.086 12.749 ;
     RECT  26.856 9.341 26.946 12.757 ;
     RECT  88.704 12.721 89.097 12.797 ;
     RECT  77.22 12.523 79.326 12.821 ;
     RECT  160.956 4.541 161.01 12.865 ;
     RECT  26.856 12.757 26.982 12.901 ;
     RECT  90.432 11.705 90.918 12.901 ;
     RECT  194.22 4.145 194.814 12.901 ;
     RECT  26.856 12.901 27.342 12.941 ;
     RECT  90.108 12.901 90.918 12.941 ;
     RECT  194.22 12.901 195.03 12.941 ;
     RECT  86.508 12.253 87.498 13.243 ;
     RECT  69.444 11.785 73.314 13.289 ;
     RECT  86.508 13.243 87.57 13.289 ;
     RECT  58.68 3.983 59.562 13.297 ;
     RECT  48.6 5.161 49.338 13.369 ;
     RECT  11.88 12.281 11.898 13.397 ;
     RECT  209.772 12.281 209.79 13.397 ;
     RECT  81.072 12.479 81.882 13.405 ;
     RECT  82.692 12.479 84.474 13.405 ;
     RECT  70.92 13.289 73.314 13.483 ;
     RECT  70.92 13.483 73.458 13.559 ;
     RECT  81.072 13.405 84.474 13.829 ;
     RECT  11.052 4.415 11.07 13.973 ;
     RECT  207.252 4.757 208.062 13.973 ;
     RECT  77.22 12.821 79.11 14.059 ;
     RECT  85.212 8.815 85.23 14.059 ;
     RECT  90.432 12.941 90.918 14.059 ;
     RECT  77.22 14.059 79.794 14.099 ;
     RECT  85.212 14.059 85.698 14.099 ;
     RECT  90.432 14.059 91.602 14.099 ;
     RECT  82.692 13.829 84.474 14.203 ;
     RECT  85.212 14.099 85.23 14.203 ;
     RECT  113.004 11.939 113.274 14.215 ;
     RECT  90.432 14.099 91.314 14.237 ;
     RECT  82.692 14.203 85.23 14.243 ;
     RECT  112.68 14.215 113.274 14.251 ;
     RECT  114.444 12.479 115.074 14.251 ;
     RECT  114.012 14.251 115.074 14.369 ;
     RECT  70.92 13.559 73.314 14.521 ;
     RECT  88.815 12.797 89.097 14.521 ;
     RECT  9.972 4.379 9.99 14.549 ;
     RECT  86.508 13.289 87.498 14.549 ;
     RECT  104.724 4.415 105.498 14.549 ;
     RECT  207.252 13.973 207.897 14.549 ;
     RECT  161.928 4.531 162.162 14.639 ;
     RECT  155.088 11.939 155.106 14.779 ;
     RECT  155.088 14.779 155.79 14.791 ;
     RECT  156.636 11.947 156.906 14.791 ;
     RECT  155.088 14.791 156.906 14.819 ;
     RECT  75.024 12.361 76.302 14.827 ;
     RECT  77.22 14.099 79.11 14.827 ;
     RECT  155.088 14.819 155.106 14.827 ;
     RECT  156.06 14.819 156.906 14.827 ;
     RECT  157.824 12.749 157.842 14.827 ;
     RECT  112.572 14.251 113.274 14.861 ;
     RECT  60.588 12.209 62.766 14.881 ;
     RECT  110.376 12.523 111.366 14.881 ;
     RECT  113.004 14.861 113.274 14.881 ;
     RECT  137.016 11.399 138.438 14.881 ;
     RECT  141.264 10.975 141.282 14.881 ;
     RECT  75.024 14.827 79.11 14.909 ;
     RECT  86.508 14.549 86.67 14.909 ;
     RECT  126.576 11.399 126.897 14.909 ;
     RECT  133.704 11.669 134.082 14.909 ;
     RECT  141.192 14.881 141.282 14.909 ;
     RECT  152.244 11.785 153.897 14.909 ;
     RECT  152.316 14.909 153.897 14.917 ;
     RECT  154.764 14.827 155.106 14.917 ;
     RECT  156.06 14.827 157.842 14.957 ;
     RECT  75.024 14.909 76.446 15.101 ;
     RECT  74.268 11.201 74.286 15.151 ;
     RECT  75.024 15.101 76.302 15.151 ;
     RECT  58.68 13.297 59.598 15.179 ;
     RECT  86.58 14.909 86.67 15.197 ;
     RECT  81.072 13.829 81.882 15.211 ;
     RECT  82.692 14.243 84.474 15.211 ;
     RECT  156.636 14.957 157.842 15.215 ;
     RECT  77.22 14.909 79.11 15.259 ;
     RECT  161.928 14.639 162.054 15.295 ;
     RECT  163.116 11.101 167.346 15.295 ;
     RECT  90.432 14.237 90.918 15.307 ;
     RECT  115.815 12.479 116.838 15.307 ;
     RECT  117.864 11.939 117.882 15.307 ;
     RECT  81.072 15.211 84.474 15.389 ;
     RECT  148.215 11.785 149.418 15.403 ;
     RECT  110.304 14.881 111.366 15.421 ;
     RECT  192.96 12.749 193.086 15.421 ;
     RECT  68.4 15.403 68.418 15.449 ;
     RECT  77.22 15.259 79.506 15.449 ;
     RECT  133.776 14.909 134.082 15.457 ;
     RECT  110.304 15.421 111.402 15.485 ;
     RECT  192.816 15.421 193.086 15.485 ;
     RECT  135.144 11.515 136.134 15.499 ;
     RECT  113.004 14.881 113.346 15.595 ;
     RECT  145.728 11.245 146.862 15.601 ;
     RECT  147.6 15.403 149.418 15.601 ;
     RECT  112.32 15.595 113.346 15.635 ;
     RECT  152.316 14.917 155.106 15.677 ;
     RECT  114.444 14.369 115.074 15.685 ;
     RECT  115.815 15.307 117.882 15.685 ;
     RECT  67.215 11.669 67.626 15.691 ;
     RECT  145.728 15.601 149.418 15.691 ;
     RECT  145.656 15.691 149.814 15.719 ;
     RECT  114.444 15.685 117.882 15.725 ;
     RECT  152.316 15.677 153.897 15.725 ;
     RECT  137.016 14.881 138.51 15.835 ;
     RECT  139.824 11.245 139.842 15.835 ;
     RECT  141.192 14.909 141.21 15.835 ;
     RECT  148.104 15.719 149.814 15.869 ;
     RECT  74.268 15.151 76.302 15.871 ;
     RECT  118.944 12.488 119.61 15.871 ;
     RECT  120.672 11.947 121.806 15.871 ;
     RECT  133.776 15.457 134.298 15.871 ;
     RECT  135.144 15.499 136.206 15.871 ;
     RECT  141.048 15.835 141.21 15.871 ;
     RECT  148.215 15.869 149.814 15.899 ;
     RECT  118.944 15.871 121.806 15.917 ;
     RECT  60.588 14.881 62.874 15.961 ;
     RECT  79.992 15.835 80.154 15.961 ;
     RECT  81.072 15.389 81.882 15.961 ;
     RECT  129.096 11.245 129.114 15.961 ;
     RECT  129.888 11.785 130.626 15.961 ;
     RECT  133.776 15.871 136.206 15.961 ;
     RECT  140.904 15.871 141.21 15.961 ;
     RECT  144.396 10.859 144.414 15.961 ;
     RECT  82.692 15.389 84.474 15.979 ;
     RECT  85.212 14.243 85.23 15.979 ;
     RECT  115.815 15.725 117.882 15.979 ;
     RECT  90.216 15.307 90.918 15.989 ;
     RECT  140.904 15.961 141.282 15.989 ;
     RECT  60.588 15.961 63.126 16.013 ;
     RECT  79.992 15.961 81.882 16.013 ;
     RECT  115.815 15.979 117.99 16.013 ;
     RECT  126.615 14.909 126.897 16.027 ;
     RECT  74.268 15.871 76.41 16.033 ;
     RECT  77.22 15.449 79.11 16.033 ;
     RECT  58.68 15.179 58.698 16.105 ;
     RECT  59.436 15.179 59.598 16.105 ;
     RECT  133.416 15.961 136.206 16.109 ;
     RECT  70.92 14.521 73.53 16.118 ;
     RECT  74.268 16.033 79.11 16.118 ;
     RECT  141.192 15.989 141.282 16.123 ;
     RECT  142.2 11.245 143.586 16.123 ;
     RECT  64.368 10.975 65.43 16.141 ;
     RECT  90.432 15.989 90.918 16.141 ;
     RECT  144.396 15.961 144.666 16.141 ;
     RECT  145.656 15.719 146.862 16.141 ;
     RECT  82.692 15.979 85.23 16.205 ;
     RECT  90.432 16.141 91.242 16.205 ;
     RECT  88.815 14.521 89.478 16.231 ;
     RECT  131.472 10.975 132.462 16.231 ;
     RECT  137.016 15.835 139.842 16.231 ;
     RECT  79.992 16.013 80.154 16.259 ;
     RECT  107.532 3.569 107.55 16.259 ;
     RECT  135.144 16.109 136.206 16.259 ;
     RECT  168.084 9.391 170.514 16.259 ;
     RECT  120.672 15.917 121.806 16.267 ;
     RECT  122.652 11.939 123.318 16.267 ;
     RECT  79.992 16.259 80.01 16.295 ;
     RECT  67.215 15.691 68.274 16.301 ;
     RECT  144.396 16.141 146.862 16.301 ;
     RECT  60.588 16.013 62.946 16.304 ;
     RECT  129.096 15.961 130.626 16.304 ;
     RECT  60.588 16.304 62.874 16.315 ;
     RECT  60.408 16.315 62.874 16.331 ;
     RECT  64.296 16.141 65.574 16.349 ;
     RECT  28.44 10.769 28.458 16.363 ;
     RECT  30.456 10.829 30.618 16.363 ;
     RECT  126.576 16.027 126.897 16.363 ;
     RECT  70.92 16.118 79.11 16.375 ;
     RECT  137.016 16.231 140.418 16.397 ;
     RECT  117.864 16.013 117.99 16.405 ;
     RECT  118.944 15.917 119.61 16.405 ;
     RECT  129.888 16.304 130.626 16.405 ;
     RECT  131.436 16.231 132.462 16.405 ;
     RECT  70.92 16.375 79.254 16.411 ;
     RECT  64.332 16.349 65.574 16.445 ;
     RECT  117.864 16.405 119.61 16.445 ;
     RECT  133.416 16.109 134.082 16.459 ;
     RECT  144.396 16.301 144.414 16.459 ;
     RECT  29.415 10.829 29.697 16.501 ;
     RECT  30.456 16.363 30.798 16.501 ;
     RECT  128.052 11.399 128.322 16.507 ;
     RECT  141.192 16.123 143.586 16.507 ;
     RECT  144.36 16.459 144.414 16.507 ;
     RECT  28.224 16.363 28.458 16.529 ;
     RECT  33.66 4.109 33.678 16.529 ;
     RECT  64.332 16.445 65.43 16.529 ;
     RECT  29.415 16.501 30.798 16.541 ;
     RECT  141.192 16.507 144.414 16.541 ;
     RECT  81.072 16.013 81.882 16.681 ;
     RECT  82.692 16.205 84.474 16.681 ;
     RECT  110.304 15.485 111.366 16.681 ;
     RECT  129.888 16.405 132.462 16.681 ;
     RECT  133.344 16.459 134.082 16.681 ;
     RECT  60.408 16.331 62.766 16.799 ;
     RECT  129.888 16.681 134.082 16.799 ;
     RECT  179.352 7.123 182.106 16.799 ;
     RECT  50.112 14.521 50.13 16.807 ;
     RECT  51.015 4.649 51.678 16.807 ;
     RECT  88.776 16.231 89.478 16.807 ;
     RECT  90.432 16.205 90.918 16.807 ;
     RECT  175.215 8.815 178.506 16.807 ;
     RECT  100.728 8.267 100.746 16.835 ;
     RECT  129.888 16.799 132.822 16.835 ;
     RECT  195.768 4.379 198.162 16.835 ;
     RECT  42.768 8.815 45.897 16.843 ;
     RECT  86.58 15.197 86.634 16.843 ;
     RECT  87.48 14.549 87.498 16.843 ;
     RECT  93.384 4.109 94.77 16.843 ;
     RECT  135.144 16.259 136.134 16.843 ;
     RECT  150.696 12.209 151.11 16.843 ;
     RECT  5.22 3.875 5.238 16.871 ;
     RECT  104.724 14.549 105.297 16.871 ;
     RECT  184.932 4.487 185.274 16.871 ;
     RECT  66.42 16.118 66.438 16.891 ;
     RECT  67.215 16.301 67.626 16.891 ;
     RECT  69.444 13.289 70.074 16.915 ;
     RECT  115.815 16.013 117.126 16.939 ;
     RECT  117.864 16.445 117.882 16.939 ;
     RECT  133.632 16.799 134.082 16.939 ;
     RECT  135.108 16.843 136.134 16.939 ;
     RECT  152.316 15.725 152.802 16.951 ;
     RECT  153.54 15.725 153.897 16.951 ;
     RECT  150.48 16.843 151.11 16.973 ;
     RECT  152.316 16.951 153.897 17.021 ;
     RECT  86.58 16.843 87.678 17.032 ;
     RECT  133.632 16.939 136.134 17.035 ;
     RECT  115.815 16.939 117.882 17.069 ;
     RECT  133.632 17.035 136.206 17.069 ;
     RECT  29.415 16.541 30.618 17.075 ;
     RECT  81.072 16.681 84.474 17.077 ;
     RECT  88.776 16.807 90.918 17.077 ;
     RECT  110.232 16.681 111.366 17.105 ;
     RECT  115.815 17.069 117.126 17.105 ;
     RECT  127.8 16.507 128.322 17.105 ;
     RECT  60.588 16.799 62.766 17.113 ;
     RECT  120.672 16.267 123.318 17.117 ;
     RECT  133.776 17.069 136.206 17.117 ;
     RECT  69.408 16.915 70.074 17.131 ;
     RECT  70.92 16.411 79.506 17.131 ;
     RECT  142.2 16.541 144.414 17.131 ;
     RECT  110.304 17.105 111.366 17.141 ;
     RECT  68.436 17.035 68.454 17.179 ;
     RECT  69.408 17.131 79.506 17.179 ;
     RECT  36.036 4.721 36.234 17.185 ;
     RECT  37.152 7.663 39.474 17.185 ;
     RECT  66.42 16.891 67.626 17.185 ;
     RECT  68.436 17.179 79.506 17.185 ;
     RECT  125.028 11.785 125.586 17.221 ;
     RECT  126.54 16.363 126.897 17.221 ;
     RECT  145.62 16.301 146.862 17.275 ;
     RECT  141.192 16.541 141.21 17.311 ;
     RECT  142.2 17.131 144.846 17.311 ;
     RECT  80.532 17.077 84.474 17.323 ;
     RECT  85.212 16.205 85.23 17.323 ;
     RECT  141.192 17.311 144.846 17.323 ;
     RECT  145.62 17.275 147.222 17.323 ;
     RECT  50.112 16.807 51.678 17.339 ;
     RECT  175.215 16.807 178.578 17.339 ;
     RECT  34.704 4.649 35.097 17.383 ;
     RECT  36.036 17.185 39.474 17.383 ;
     RECT  23.472 7.691 25.362 17.411 ;
     RECT  80.532 17.323 85.23 17.419 ;
     RECT  86.184 17.032 87.678 17.419 ;
     RECT  88.776 17.077 91.026 17.419 ;
     RECT  64.368 16.529 65.43 17.455 ;
     RECT  66.42 17.185 79.506 17.455 ;
     RECT  80.46 17.419 85.23 17.455 ;
     RECT  66.42 17.455 85.23 17.491 ;
     RECT  86.184 17.419 91.026 17.491 ;
     RECT  124.128 11.785 124.146 17.491 ;
     RECT  125.028 17.221 126.897 17.491 ;
     RECT  148.215 15.899 149.418 17.491 ;
     RECT  141.192 17.323 147.222 17.563 ;
     RECT  64.224 17.455 65.43 17.581 ;
     RECT  66.42 17.491 91.026 17.581 ;
     RECT  60.588 17.113 62.838 17.611 ;
     RECT  163.008 15.295 167.346 17.618 ;
     RECT  124.128 17.491 126.897 17.651 ;
     RECT  129.888 16.835 132.462 17.653 ;
     RECT  140.94 17.563 147.222 17.653 ;
     RECT  148.032 17.491 149.418 17.653 ;
     RECT  135 17.117 136.206 17.689 ;
     RECT  137.016 16.397 139.842 17.689 ;
     RECT  60.588 17.611 63.378 17.761 ;
     RECT  64.224 17.581 65.574 17.761 ;
     RECT  186.015 5.999 186.678 17.851 ;
     RECT  189.9 4.445 189.918 17.851 ;
     RECT  55.116 4.685 57.762 17.879 ;
     RECT  171.252 9.931 172.422 17.879 ;
     RECT  129.096 16.304 129.114 17.887 ;
     RECT  129.888 17.653 132.606 17.887 ;
     RECT  133.776 17.117 134.19 17.887 ;
     RECT  135 17.689 139.842 17.887 ;
     RECT  171.756 17.879 172.422 17.887 ;
     RECT  173.628 6.547 174.402 17.887 ;
     RECT  185.904 17.851 186.678 17.888 ;
     RECT  189.9 17.851 190.566 17.888 ;
     RECT  125.028 17.651 126.897 17.915 ;
     RECT  133.776 17.887 139.842 17.923 ;
     RECT  22.104 9.239 22.122 17.951 ;
     RECT  140.94 17.653 149.418 17.959 ;
     RECT  92.34 17.923 92.358 17.995 ;
     RECT  129.096 17.887 132.606 17.995 ;
     RECT  91.908 17.995 92.358 18.031 ;
     RECT  133.74 17.923 139.842 18.031 ;
     RECT  191.415 7.691 191.697 18.031 ;
     RECT  133.74 18.031 140.058 18.139 ;
     RECT  93.384 16.843 95.202 18.149 ;
     RECT  129.096 17.995 132.714 18.149 ;
     RECT  171.756 17.887 174.402 18.149 ;
     RECT  60.588 17.761 65.574 18.193 ;
     RECT  66.384 17.581 91.026 18.193 ;
     RECT  128.052 17.105 128.322 18.193 ;
     RECT  129.096 18.149 132.606 18.193 ;
     RECT  191.415 18.031 192.114 18.221 ;
     RECT  60.588 18.193 91.026 18.229 ;
     RECT  91.908 18.031 92.502 18.229 ;
     RECT  60.588 18.229 92.502 18.265 ;
     RECT  133.56 18.139 140.058 18.265 ;
     RECT  140.796 17.959 149.598 18.265 ;
     RECT  120.672 17.117 121.806 18.301 ;
     RECT  122.652 17.117 123.318 18.301 ;
     RECT  60.588 18.265 92.646 18.419 ;
     RECT  133.56 18.265 149.598 18.419 ;
     RECT  126.615 17.915 126.897 18.421 ;
     RECT  133.56 18.419 140.058 18.455 ;
     RECT  20.7 9.248 20.718 18.527 ;
     RECT  206.208 4.559 206.262 18.527 ;
     RECT  55.116 17.879 55.458 18.535 ;
     RECT  126.615 18.421 127.278 18.571 ;
     RECT  128.052 18.193 132.606 18.571 ;
     RECT  124.128 17.651 124.146 18.619 ;
     RECT  125.028 17.915 125.586 18.619 ;
     RECT  124.128 18.619 125.586 18.661 ;
     RECT  152.316 17.021 152.802 18.661 ;
     RECT  153.54 17.021 153.897 18.661 ;
     RECT  60.588 18.419 92.61 18.689 ;
     RECT  77.472 18.689 92.466 18.725 ;
     RECT  126.615 18.571 132.606 18.733 ;
     RECT  120.672 18.301 123.318 18.769 ;
     RECT  124.128 18.661 125.802 18.769 ;
     RECT  58.68 16.105 59.598 18.805 ;
     RECT  60.588 18.689 76.734 18.805 ;
     RECT  158.832 12.749 159.354 18.805 ;
     RECT  161.748 15.295 162.054 18.833 ;
     RECT  120.672 18.769 125.802 18.841 ;
     RECT  126.54 18.733 132.606 18.841 ;
     RECT  155.088 15.677 155.106 18.841 ;
     RECT  156.636 15.215 156.906 18.955 ;
     RECT  58.68 18.805 76.734 18.995 ;
     RECT  156.024 18.955 156.906 18.995 ;
     RECT  140.796 18.419 149.598 19.003 ;
     RECT  152.316 18.661 153.897 19.003 ;
     RECT  152.316 19.003 153.954 19.075 ;
     RECT  17.676 4.253 17.694 19.103 ;
     RECT  77.472 18.725 92.43 19.103 ;
     RECT  206.244 18.527 206.262 19.103 ;
     RECT  47.412 4.793 47.754 19.111 ;
     RECT  56.232 17.879 57.762 19.111 ;
     RECT  150.696 16.973 151.11 19.111 ;
     RECT  152.316 19.075 154.026 19.111 ;
     RECT  133.56 18.455 139.986 19.139 ;
     RECT  117.864 17.069 117.882 19.195 ;
     RECT  118.944 16.445 119.61 19.201 ;
     RECT  77.472 19.103 91.35 19.229 ;
     RECT  133.56 19.139 135.846 19.229 ;
     RECT  77.472 19.229 86.598 19.265 ;
     RECT  87.588 19.229 91.35 19.265 ;
     RECT  113.004 15.635 113.346 19.273 ;
     RECT  157.824 15.215 157.842 19.273 ;
     RECT  136.692 19.139 139.986 19.345 ;
     RECT  140.796 19.003 149.67 19.345 ;
     RECT  157.824 19.273 157.914 19.345 ;
     RECT  117.864 19.195 117.99 19.381 ;
     RECT  118.908 19.201 119.61 19.381 ;
     RECT  150.696 19.111 154.026 19.381 ;
     RECT  156.384 18.995 156.906 19.381 ;
     RECT  157.824 19.345 157.95 19.381 ;
     RECT  112.86 19.273 113.346 19.471 ;
     RECT  136.692 19.345 149.67 19.471 ;
     RECT  150.552 19.381 154.026 19.471 ;
     RECT  112.32 19.471 113.346 19.483 ;
     RECT  114.444 15.725 115.074 19.483 ;
     RECT  93.384 18.149 94.497 19.499 ;
     RECT  117.864 19.381 119.61 19.507 ;
     RECT  156.384 19.381 156.942 19.507 ;
     RECT  157.752 19.381 157.95 19.507 ;
     RECT  75.852 18.995 76.734 19.543 ;
     RECT  77.472 19.265 84.474 19.543 ;
     RECT  115.815 17.105 116.838 19.579 ;
     RECT  117.756 19.507 119.61 19.579 ;
     RECT  120.672 18.841 132.606 19.579 ;
     RECT  154.764 18.841 155.106 19.579 ;
     RECT  92.268 19.103 92.43 19.615 ;
     RECT  136.692 19.471 154.026 19.651 ;
     RECT  154.764 19.579 155.142 19.651 ;
     RECT  158.76 18.805 159.354 19.651 ;
     RECT  16.596 4.109 16.614 19.679 ;
     RECT  204.732 4.685 204.75 19.679 ;
     RECT  92.268 19.615 92.61 19.723 ;
     RECT  75.852 19.543 84.474 19.741 ;
     RECT  75.78 19.741 84.474 19.769 ;
     RECT  112.32 19.483 115.074 19.771 ;
     RECT  115.815 19.579 132.606 19.771 ;
     RECT  58.68 18.995 74.898 19.777 ;
     RECT  110.376 17.141 111.366 19.777 ;
     RECT  110.376 19.777 111.582 19.849 ;
     RECT  112.32 19.771 132.606 19.849 ;
     RECT  160.848 12.865 161.01 19.849 ;
     RECT  161.82 18.833 162.054 19.849 ;
     RECT  58.68 19.777 75.042 19.885 ;
     RECT  75.78 19.769 76.77 19.885 ;
     RECT  90.9 19.265 91.35 19.885 ;
     RECT  58.68 19.885 76.77 19.901 ;
     RECT  58.68 19.901 76.734 19.913 ;
     RECT  136.692 19.651 155.142 19.921 ;
     RECT  156.384 19.507 157.95 19.921 ;
     RECT  47.34 19.111 47.754 19.949 ;
     RECT  58.68 19.913 76.626 19.949 ;
     RECT  133.56 19.229 135.738 19.963 ;
     RECT  90.9 19.885 91.458 20.047 ;
     RECT  92.268 19.723 92.682 20.047 ;
     RECT  87.588 19.265 90.162 20.075 ;
     RECT  77.58 19.769 84.474 20.083 ;
     RECT  85.356 19.265 86.598 20.083 ;
     RECT  110.376 19.849 132.606 20.083 ;
     RECT  158.76 19.651 159.93 20.083 ;
     RECT  160.848 19.849 162.054 20.083 ;
     RECT  93.528 19.499 94.497 20.107 ;
     RECT  136.692 19.921 157.95 20.111 ;
     RECT  77.58 20.083 86.598 20.119 ;
     RECT  109.584 20.047 109.602 20.119 ;
     RECT  110.376 20.083 132.642 20.119 ;
     RECT  133.56 19.963 135.882 20.119 ;
     RECT  109.584 20.119 132.642 20.155 ;
     RECT  146.772 20.111 157.95 20.155 ;
     RECT  133.452 20.119 135.882 20.191 ;
     RECT  136.692 20.111 145.782 20.191 ;
     RECT  109.332 20.155 132.642 20.281 ;
     RECT  133.452 20.191 145.782 20.281 ;
     RECT  109.332 20.281 145.782 20.309 ;
     RECT  109.332 20.309 139.518 20.345 ;
     RECT  140.256 20.309 145.782 20.345 ;
     RECT  146.772 20.155 157.986 20.347 ;
     RECT  158.76 20.083 162.054 20.347 ;
     RECT  55.008 18.535 55.458 20.389 ;
     RECT  56.232 19.111 57.906 20.389 ;
     RECT  58.68 19.949 76.23 20.389 ;
     RECT  99.615 7.151 99.897 20.443 ;
     RECT  93.528 20.107 94.554 20.477 ;
     RECT  99.504 20.443 99.897 20.489 ;
     RECT  87.696 20.075 90.162 20.659 ;
     RECT  90.9 20.047 92.682 20.659 ;
     RECT  93.528 20.477 94.497 20.659 ;
     RECT  124.812 20.345 139.518 20.687 ;
     RECT  184.932 16.871 184.95 20.695 ;
     RECT  186.015 17.888 186.678 20.695 ;
     RECT  189.144 4.379 189.162 20.695 ;
     RECT  188.46 20.695 189.162 20.731 ;
     RECT  124.812 20.687 132.786 20.849 ;
     RECT  77.58 20.119 86.778 21.001 ;
     RECT  124.812 20.849 132.642 21.053 ;
     RECT  77.58 21.001 86.85 21.091 ;
     RECT  146.772 20.347 162.054 21.091 ;
     RECT  55.008 20.389 76.23 21.115 ;
     RECT  188.316 20.731 189.162 21.119 ;
     RECT  133.56 20.687 139.518 21.127 ;
     RECT  140.256 20.345 145.566 21.127 ;
     RECT  109.332 20.345 124.074 21.199 ;
     RECT  124.812 21.053 132.498 21.199 ;
     RECT  188.316 21.119 188.334 21.2 ;
     RECT  55.008 21.115 76.338 21.271 ;
     RECT  77.4 21.091 86.85 21.271 ;
     RECT  106.632 21.211 106.65 21.271 ;
     RECT  146.376 21.091 162.054 21.271 ;
     RECT  184.932 20.695 186.678 21.293 ;
     RECT  41.976 6.583 42.03 21.361 ;
     RECT  14.508 11.705 15.426 21.389 ;
     RECT  109.332 21.199 132.498 21.389 ;
     RECT  109.332 21.389 111.402 21.397 ;
     RECT  87.696 20.659 94.497 21.403 ;
     RECT  99.615 20.489 99.897 21.403 ;
     RECT  105.015 16.871 105.297 21.403 ;
     RECT  184.932 21.293 184.95 21.437 ;
     RECT  55.008 21.271 86.85 21.499 ;
     RECT  98.604 21.403 98.622 21.499 ;
     RECT  102.6 21.403 102.618 21.499 ;
     RECT  109.008 21.397 111.402 21.499 ;
     RECT  87.696 21.403 94.518 21.533 ;
     RECT  98.604 21.499 98.73 21.533 ;
     RECT  99.615 21.403 99.918 21.533 ;
     RECT  102.6 21.499 102.726 21.533 ;
     RECT  105.015 21.403 105.318 21.533 ;
     RECT  87.696 21.533 94.497 21.569 ;
     RECT  55.008 21.499 86.886 21.629 ;
     RECT  98.712 21.533 98.73 21.629 ;
     RECT  102.708 21.533 102.726 21.629 ;
     RECT  133.56 21.127 145.566 21.629 ;
     RECT  106.596 21.271 106.65 21.631 ;
     RECT  136.584 21.629 145.566 21.631 ;
     RECT  146.376 21.271 162.126 21.631 ;
     RECT  108.504 21.499 111.402 21.659 ;
     RECT  106.596 21.631 106.974 21.677 ;
     RECT  112.14 21.389 132.498 21.677 ;
     RECT  133.56 21.629 135.846 21.677 ;
     RECT  55.008 21.629 86.814 21.773 ;
     RECT  40.215 4.685 40.734 21.775 ;
     RECT  41.544 21.361 42.03 21.775 ;
     RECT  136.584 21.631 162.126 21.811 ;
     RECT  163.008 17.618 167.31 21.811 ;
     RECT  169.815 16.259 170.514 21.937 ;
     RECT  203.976 4.685 203.994 21.965 ;
     RECT  14.508 21.389 14.994 22.001 ;
     RECT  34.704 17.383 39.474 22.045 ;
     RECT  40.215 21.775 42.03 22.045 ;
     RECT  99.615 21.533 99.897 22.072 ;
     RECT  136.584 21.811 167.31 22.073 ;
     RECT  133.56 21.677 135.594 22.081 ;
     RECT  55.008 21.773 86.778 22.109 ;
     RECT  136.584 22.073 146.646 22.109 ;
     RECT  146.196 22.109 146.646 22.157 ;
     RECT  131.616 21.677 132.498 22.171 ;
     RECT  108.9 21.659 111.402 22.207 ;
     RECT  112.14 21.677 130.878 22.207 ;
     RECT  77.832 22.109 86.778 22.235 ;
     RECT  108.9 22.207 130.878 22.235 ;
     RECT  55.008 22.109 76.986 22.271 ;
     RECT  42.768 16.843 45.99 22.315 ;
     RECT  42.768 22.315 46.53 22.343 ;
     RECT  133.524 22.081 135.594 22.459 ;
     RECT  34.704 22.045 42.03 22.469 ;
     RECT  48.492 13.369 49.338 22.513 ;
     RECT  50.112 17.339 51.642 22.513 ;
     RECT  87.696 21.569 91.602 22.513 ;
     RECT  92.34 21.569 94.497 22.513 ;
     RECT  108.9 22.235 112.482 22.513 ;
     RECT  113.472 22.235 130.878 22.513 ;
     RECT  131.616 22.171 132.75 22.513 ;
     RECT  168.084 16.259 169.074 22.513 ;
     RECT  169.815 21.937 170.658 22.513 ;
     RECT  177.876 17.339 178.578 22.513 ;
     RECT  179.352 16.799 181.602 22.513 ;
     RECT  14.508 22.001 14.526 22.541 ;
     RECT  44.352 22.343 46.53 22.541 ;
     RECT  55.116 22.271 76.986 22.541 ;
     RECT  192.96 15.485 193.086 22.541 ;
     RECT  87.696 22.513 94.626 22.577 ;
     RECT  186.015 21.293 186.678 22.577 ;
     RECT  31.644 8.843 31.662 22.585 ;
     RECT  133.524 22.459 135.81 22.585 ;
     RECT  136.584 22.109 145.386 22.585 ;
     RECT  171.756 18.149 174.33 22.585 ;
     RECT  175.215 17.339 177.066 22.585 ;
     RECT  55.116 22.541 73.674 22.613 ;
     RECT  74.52 22.541 76.986 22.613 ;
     RECT  92.736 22.577 94.626 22.613 ;
     RECT  108.288 22.513 112.482 22.613 ;
     RECT  177.876 22.513 181.602 22.613 ;
     RECT  31.644 22.585 31.698 22.621 ;
     RECT  77.832 22.235 81.882 22.637 ;
     RECT  74.736 22.613 76.986 22.649 ;
     RECT  80.676 22.637 81.846 22.649 ;
     RECT  99.504 22.072 99.897 22.649 ;
     RECT  31.572 22.621 31.698 22.651 ;
     RECT  32.436 6.611 32.454 22.651 ;
     RECT  77.832 22.637 79.938 22.739 ;
     RECT  80.784 22.649 81.846 22.739 ;
     RECT  147.492 22.073 167.31 22.739 ;
     RECT  74.844 22.649 76.986 22.775 ;
     RECT  77.832 22.739 79.542 22.775 ;
     RECT  80.928 22.739 81.846 22.775 ;
     RECT  31.572 22.651 32.454 22.781 ;
     RECT  79.452 22.775 79.542 22.781 ;
     RECT  108.36 22.613 112.482 22.784 ;
     RECT  80.928 22.775 81.774 22.811 ;
     RECT  87.696 22.577 91.962 22.811 ;
     RECT  80.928 22.811 81.702 22.829 ;
     RECT  87.696 22.811 90.162 22.829 ;
     RECT  42.768 22.343 43.47 22.847 ;
     RECT  75.096 22.775 76.986 22.847 ;
     RECT  81.072 22.829 81.63 22.847 ;
     RECT  79.452 22.781 79.47 22.883 ;
     RECT  82.656 22.235 86.778 22.883 ;
     RECT  113.472 22.513 132.75 22.883 ;
     RECT  133.524 22.585 145.386 22.885 ;
     RECT  146.484 22.157 146.646 22.885 ;
     RECT  75.276 22.847 76.986 22.925 ;
     RECT  82.656 22.883 84.654 22.973 ;
     RECT  85.608 22.883 86.778 22.987 ;
     RECT  31.572 22.781 31.698 23.009 ;
     RECT  81.18 22.847 81.63 23.009 ;
     RECT  89.82 22.829 90.162 23.009 ;
     RECT  91.08 22.811 91.962 23.009 ;
     RECT  113.472 22.883 116.838 23.009 ;
     RECT  117.756 22.883 132.75 23.009 ;
     RECT  77.832 22.775 78.57 23.045 ;
     RECT  89.928 23.009 90.162 23.045 ;
     RECT  92.736 22.613 94.497 23.045 ;
     RECT  55.116 22.613 73.53 23.081 ;
     RECT  110.376 22.784 112.482 23.081 ;
     RECT  117.792 23.009 132.75 23.081 ;
     RECT  203.22 9.419 203.238 23.081 ;
     RECT  82.656 22.973 83.79 23.117 ;
     RECT  85.608 22.987 86.814 23.117 ;
     RECT  89.964 23.045 90.162 23.117 ;
     RECT  76.968 22.925 76.986 23.125 ;
     RECT  113.472 23.009 116.19 23.125 ;
     RECT  133.524 22.885 146.646 23.125 ;
     RECT  87.696 22.829 89.097 23.153 ;
     RECT  108.36 22.784 109.638 23.153 ;
     RECT  47.412 19.949 47.754 23.161 ;
     RECT  126.36 23.081 132.75 23.161 ;
     RECT  133.524 23.125 147.222 23.161 ;
     RECT  117.792 23.081 125.262 23.165 ;
     RECT  84.6 22.973 84.654 23.189 ;
     RECT  86.616 23.117 86.814 23.189 ;
     RECT  120.096 23.165 125.262 23.189 ;
     RECT  126.36 23.161 147.222 23.189 ;
     RECT  91.08 23.009 91.782 23.213 ;
     RECT  52.668 4.685 54.27 23.227 ;
     RECT  55.116 23.081 65.61 23.227 ;
     RECT  110.415 23.081 112.482 23.251 ;
     RECT  113.436 23.125 116.19 23.251 ;
     RECT  91.26 23.213 91.782 23.261 ;
     RECT  71.64 23.081 73.53 23.279 ;
     RECT  76.968 23.125 77.166 23.279 ;
     RECT  82.656 23.117 83.697 23.279 ;
     RECT  91.368 23.261 91.782 23.279 ;
     RECT  117.792 23.165 119.358 23.279 ;
     RECT  120.204 23.189 125.262 23.279 ;
     RECT  136.296 23.189 147.222 23.279 ;
     RECT  66.348 23.081 70.866 23.309 ;
     RECT  110.415 23.251 116.19 23.309 ;
     RECT  66.348 23.309 70.578 23.315 ;
     RECT  71.784 23.279 73.53 23.315 ;
     RECT  78.015 23.045 78.57 23.315 ;
     RECT  91.44 23.279 91.782 23.315 ;
     RECT  92.736 23.045 93.042 23.315 ;
     RECT  117.792 23.279 117.81 23.315 ;
     RECT  120.996 23.279 125.262 23.315 ;
     RECT  126.36 23.189 135.378 23.315 ;
     RECT  136.368 23.279 139.842 23.315 ;
     RECT  140.58 23.279 146.682 23.315 ;
     RECT  147.96 22.739 167.31 23.315 ;
     RECT  76.968 23.279 77.094 23.351 ;
     RECT  82.692 23.279 83.697 23.351 ;
     RECT  86.652 23.189 86.814 23.351 ;
     RECT  93.024 23.315 93.042 23.351 ;
     RECT  110.415 23.309 114.138 23.351 ;
     RECT  126.36 23.315 135.162 23.351 ;
     RECT  141.516 23.315 146.682 23.351 ;
     RECT  47.268 23.161 47.754 23.357 ;
     RECT  66.348 23.315 70.038 23.357 ;
     RECT  115.2 23.309 116.19 23.357 ;
     RECT  120.204 23.279 120.258 23.357 ;
     RECT  126.36 23.351 132.57 23.357 ;
     RECT  133.416 23.351 135.162 23.357 ;
     RECT  136.476 23.315 139.842 23.357 ;
     RECT  141.516 23.351 143.982 23.357 ;
     RECT  144.972 23.351 146.682 23.357 ;
     RECT  147.96 23.315 150.786 23.357 ;
     RECT  30.456 17.075 30.618 23.371 ;
     RECT  66.348 23.357 69.75 23.387 ;
     RECT  71.82 23.315 73.53 23.387 ;
     RECT  72.144 23.387 73.53 23.405 ;
     RECT  86.652 23.351 86.778 23.423 ;
     RECT  110.415 23.351 113.022 23.423 ;
     RECT  66.348 23.387 69.246 23.459 ;
     RECT  110.415 23.423 111.51 23.459 ;
     RECT  112.284 23.423 113.022 23.459 ;
     RECT  145.008 23.357 146.682 23.459 ;
     RECT  147.96 23.357 150.75 23.459 ;
     RECT  78.015 23.315 78.297 23.507 ;
     RECT  83.016 23.351 83.697 23.507 ;
     RECT  88.092 23.153 89.097 23.507 ;
     RECT  94.215 23.045 94.497 23.507 ;
     RECT  99.615 22.649 99.897 23.507 ;
     RECT  105.015 21.533 105.297 23.507 ;
     RECT  126.36 23.357 126.897 23.507 ;
     RECT  151.704 23.315 167.31 23.507 ;
     RECT  52.668 23.227 65.61 23.549 ;
     RECT  115.704 23.357 116.19 23.549 ;
     RECT  118.584 23.279 119.358 23.549 ;
     RECT  121.176 23.315 125.262 23.549 ;
     RECT  140.58 23.315 140.598 23.549 ;
     RECT  141.912 23.357 143.982 23.549 ;
     RECT  149.58 23.459 150.75 23.549 ;
     RECT  106.596 21.677 106.614 23.593 ;
     RECT  75.276 22.925 75.834 23.597 ;
     RECT  115.815 23.549 116.19 23.597 ;
     RECT  136.476 23.357 136.566 23.597 ;
     RECT  120.204 23.357 120.222 23.621 ;
     RECT  137.304 23.357 139.842 23.621 ;
     RECT  141.912 23.549 143.91 23.621 ;
     RECT  44.352 22.541 44.514 23.629 ;
     RECT  45.252 22.541 46.53 23.629 ;
     RECT  19.944 6.575 19.962 23.657 ;
     RECT  34.704 22.469 39.474 23.657 ;
     RECT  106.596 23.593 106.686 23.657 ;
     RECT  151.704 23.507 153.705 23.657 ;
     RECT  154.476 23.507 167.31 23.657 ;
     RECT  72.216 23.405 73.53 23.659 ;
     RECT  109.224 23.153 109.638 23.665 ;
     RECT  64.296 23.549 65.61 23.693 ;
     RECT  72.216 23.659 73.566 23.693 ;
     RECT  106.668 23.657 106.686 23.693 ;
     RECT  136.548 23.597 136.566 23.693 ;
     RECT  30.456 23.371 30.762 23.701 ;
     RECT  31.572 23.009 31.662 23.701 ;
     RECT  72.432 23.693 73.566 23.729 ;
     RECT  121.176 23.549 125.154 23.729 ;
     RECT  30.456 23.701 31.662 23.741 ;
     RECT  52.668 23.549 63.342 23.741 ;
     RECT  66.348 23.459 69.066 23.741 ;
     RECT  137.304 23.621 139.05 23.741 ;
     RECT  72.504 23.729 73.386 23.777 ;
     RECT  78.015 23.507 78.105 23.777 ;
     RECT  83.016 23.507 83.505 23.777 ;
     RECT  88.092 23.507 88.905 23.777 ;
     RECT  94.215 23.507 94.305 23.777 ;
     RECT  99.615 23.507 99.705 23.777 ;
     RECT  105.015 23.507 105.105 23.777 ;
     RECT  110.415 23.459 111.186 23.777 ;
     RECT  115.815 23.597 115.974 23.777 ;
     RECT  126.36 23.507 126.705 23.777 ;
     RECT  153.432 23.657 153.705 23.777 ;
     RECT  66.348 23.741 66.366 23.789 ;
     RECT  72.504 23.777 72.522 23.789 ;
     RECT  118.584 23.549 119.286 23.789 ;
     RECT  121.176 23.729 123.642 23.789 ;
     RECT  128.304 23.357 130.878 23.789 ;
     RECT  139.032 23.741 139.05 23.789 ;
     RECT  142.416 23.621 143.91 23.789 ;
     RECT  154.476 23.657 154.782 23.789 ;
     RECT  34.704 23.657 39.438 23.791 ;
     RECT  52.668 23.741 54.27 23.791 ;
     RECT  177.876 22.613 180.897 23.791 ;
     RECT  44.352 23.629 46.53 23.803 ;
     RECT  115.956 23.777 115.974 23.819 ;
     RECT  137.304 23.741 138.15 23.819 ;
     RECT  154.476 23.789 154.746 23.819 ;
     RECT  34.668 23.791 39.438 23.837 ;
     RECT  52.524 23.791 54.27 23.837 ;
     RECT  67.104 23.741 69.066 23.837 ;
     RECT  32.436 22.781 32.454 23.851 ;
     RECT  33.192 23.629 33.21 23.851 ;
     RECT  110.736 23.777 111.186 23.855 ;
     RECT  149.652 23.549 150.75 23.855 ;
     RECT  154.476 23.819 154.71 23.855 ;
     RECT  121.176 23.789 122.382 23.885 ;
     RECT  137.376 23.819 137.826 23.885 ;
     RECT  86.724 23.423 86.742 23.891 ;
     RECT  118.584 23.789 118.998 23.891 ;
     RECT  142.416 23.789 143.73 23.891 ;
     RECT  154.584 23.855 154.674 23.891 ;
     RECT  67.536 23.837 69.066 23.927 ;
     RECT  73.296 23.777 73.386 23.927 ;
     RECT  133.416 23.357 134.838 23.933 ;
     RECT  154.656 23.891 154.674 23.963 ;
     RECT  64.296 23.693 65.538 23.999 ;
     RECT  67.536 23.927 68.958 23.999 ;
     RECT  145.98 23.459 146.682 23.999 ;
     RECT  55.116 23.741 63.342 24.044 ;
     RECT  64.908 23.999 65.538 24.077 ;
     RECT  32.436 23.851 33.21 24.089 ;
     RECT  67.536 23.999 68.49 24.125 ;
     RECT  147.96 23.459 148.806 24.125 ;
     RECT  148.536 24.125 148.806 24.173 ;
     RECT  31.644 23.741 31.662 24.205 ;
     RECT  32.436 24.089 32.454 24.205 ;
     RECT  40.215 22.469 40.734 24.205 ;
     RECT  67.536 24.125 68.13 24.221 ;
     RECT  30.456 23.741 30.618 24.233 ;
     RECT  121.788 23.885 122.382 24.233 ;
     RECT  128.304 23.789 128.718 24.233 ;
     RECT  41.544 22.469 42.03 24.235 ;
     RECT  42.804 22.847 43.47 24.235 ;
     RECT  67.716 24.221 68.13 24.269 ;
     RECT  121.788 24.233 121.986 24.269 ;
     RECT  129.672 23.789 130.878 24.269 ;
     RECT  41.544 24.235 43.47 24.283 ;
     RECT  44.352 23.803 46.638 24.283 ;
     RECT  114.12 23.351 114.138 24.314 ;
     RECT  130.788 24.269 130.878 24.314 ;
     RECT  151.884 23.657 152.694 24.317 ;
     RECT  108.36 23.153 108.378 24.359 ;
     RECT  131.616 23.357 132.354 24.359 ;
     RECT  91.44 23.315 91.458 24.395 ;
     RECT  67.716 24.269 68.094 24.413 ;
     RECT  142.416 23.891 142.614 24.413 ;
     RECT  90.036 23.117 90.162 24.431 ;
     RECT  148.536 24.173 148.698 24.431 ;
     RECT  88.092 23.777 88.542 24.467 ;
     RECT  126.36 23.777 126.702 24.469 ;
     RECT  177.876 23.791 181.206 24.469 ;
     RECT  81.18 23.009 81.198 24.503 ;
     RECT  126.324 24.469 126.702 24.509 ;
     RECT  177.876 24.469 181.53 24.509 ;
     RECT  47.52 23.357 47.754 24.523 ;
     RECT  155.7 23.657 167.31 24.539 ;
     RECT  90.036 24.431 90.054 24.557 ;
     RECT  137.376 23.885 137.754 24.557 ;
     RECT  145.98 23.999 145.998 24.557 ;
     RECT  183.024 4.379 183.114 24.709 ;
     RECT  41.544 24.283 46.638 24.745 ;
     RECT  47.412 24.523 47.754 24.745 ;
     RECT  7.815 8.267 8.802 24.773 ;
     RECT  65.52 24.077 65.538 24.773 ;
     RECT  184.212 24.709 184.23 24.781 ;
     RECT  121.788 24.269 121.806 24.797 ;
     RECT  6.876 3.983 6.894 24.809 ;
     RECT  118.98 23.891 118.998 24.809 ;
     RECT  142.416 24.413 142.542 24.809 ;
     RECT  182.412 24.709 183.114 24.809 ;
     RECT  184.14 24.781 184.23 24.809 ;
     RECT  212.508 9.959 213.297 24.809 ;
     RECT  124.704 23.729 125.154 24.845 ;
     RECT  184.14 24.809 184.158 24.845 ;
     RECT  113.004 23.459 113.022 24.854 ;
     RECT  149.688 23.855 150.75 24.854 ;
     RECT  33.192 24.089 33.21 24.859 ;
     RECT  110.736 23.855 110.754 24.893 ;
     RECT  123.624 23.789 123.642 24.893 ;
     RECT  109.224 23.665 109.674 24.899 ;
     RECT  145.008 23.459 145.026 24.899 ;
     RECT  88.092 24.467 88.11 24.935 ;
     RECT  150.3 24.854 150.75 24.935 ;
     RECT  109.224 24.899 109.242 24.941 ;
     RECT  125.136 24.845 125.154 24.941 ;
     RECT  151.884 24.317 152.226 24.955 ;
     RECT  85.608 23.117 85.626 24.971 ;
     RECT  151.632 24.955 152.226 24.971 ;
     RECT  84.636 23.189 84.654 25.007 ;
     RECT  155.7 24.539 155.718 25.007 ;
     RECT  83.016 23.777 83.034 25.043 ;
     RECT  48.492 22.513 51.642 25.045 ;
     RECT  33.192 24.859 33.462 25.051 ;
     RECT  52.668 23.837 54.27 25.051 ;
     RECT  48.492 25.045 51.93 25.085 ;
     RECT  131.616 24.359 131.85 25.085 ;
     RECT  142.524 24.809 142.542 25.085 ;
     RECT  148.536 24.431 148.59 25.085 ;
     RECT  182.988 24.809 183.114 25.085 ;
     RECT  31.644 24.205 32.454 25.099 ;
     RECT  33.192 25.051 33.606 25.099 ;
     RECT  156.78 24.539 167.31 25.124 ;
     RECT  157.212 25.124 167.31 25.133 ;
     RECT  40.215 24.205 40.806 25.141 ;
     RECT  41.544 24.745 47.754 25.141 ;
     RECT  34.704 23.837 39.438 25.321 ;
     RECT  40.215 25.141 47.754 25.321 ;
     RECT  48.492 25.085 51.642 25.321 ;
     RECT  52.668 25.051 54.342 25.447 ;
     RECT  55.116 24.044 63.27 25.447 ;
     RECT  31.644 25.099 33.786 25.591 ;
     RECT  155.052 25.051 155.07 25.591 ;
     RECT  31.644 25.591 33.858 25.789 ;
     RECT  189.9 17.888 189.918 25.819 ;
     RECT  31.644 25.789 33.966 25.889 ;
     RECT  52.668 25.447 63.27 25.92 ;
     RECT  68.076 24.413 68.094 25.92 ;
     RECT  126.36 24.509 126.378 25.92 ;
     RECT  128.7 24.233 128.718 25.92 ;
     RECT  129.672 24.269 129.69 25.92 ;
     RECT  130.86 24.314 130.878 25.92 ;
     RECT  131.616 25.085 131.634 25.92 ;
     RECT  133.524 23.933 134.082 25.92 ;
     RECT  134.82 23.933 134.838 25.92 ;
     RECT  137.736 24.557 137.754 25.92 ;
     RECT  139.824 23.621 139.842 25.92 ;
     RECT  143.352 23.891 143.37 25.92 ;
     RECT  148.572 25.085 148.59 25.92 ;
     RECT  150.732 24.935 150.75 25.92 ;
     RECT  151.632 24.971 151.65 25.92 ;
     RECT  153.432 23.777 153.45 25.92 ;
     RECT  154.548 25.591 155.07 25.92 ;
     RECT  157.32 25.133 167.31 25.92 ;
     RECT  177.876 24.509 180.897 25.951 ;
     RECT  186.015 22.577 186.297 25.951 ;
     RECT  181.764 25.915 181.782 25.979 ;
     RECT  177.876 25.951 180.99 25.997 ;
     RECT  185.904 25.951 186.297 25.997 ;
     RECT  189.9 25.819 190.422 25.997 ;
     RECT  34.704 25.321 51.642 26.293 ;
     RECT  52.668 25.92 167.31 26.519 ;
     RECT  31.644 25.889 33.786 26.671 ;
     RECT  34.596 26.293 51.642 26.671 ;
     RECT  181.728 26.635 181.746 26.731 ;
     RECT  181.728 26.731 182.07 26.789 ;
     RECT  189.144 21.119 189.162 27.095 ;
     RECT  31.644 26.671 51.642 27.301 ;
     RECT  23.472 17.411 24.297 27.329 ;
     RECT  52.668 26.519 162.99 27.481 ;
     RECT  163.728 26.519 167.31 27.481 ;
     RECT  31.644 27.301 51.894 27.509 ;
     RECT  30.6 24.233 30.618 27.547 ;
     RECT  31.644 27.509 51.642 27.547 ;
     RECT  199.62 10.829 199.638 27.671 ;
     RECT  52.668 27.481 167.31 27.941 ;
     RECT  52.668 27.941 162.198 27.949 ;
     RECT  30.6 27.547 51.642 28.049 ;
     RECT  171.756 22.585 177.066 28.111 ;
     RECT  177.876 25.997 180.897 28.111 ;
     RECT  171.756 28.111 180.897 28.123 ;
     RECT  25.344 17.411 25.362 28.139 ;
     RECT  171.684 28.123 180.897 28.157 ;
     RECT  168.084 22.513 170.658 28.291 ;
     RECT  171.684 28.157 177.066 28.291 ;
     RECT  177.84 28.157 180.897 28.349 ;
     RECT  29.415 17.075 29.697 28.417 ;
     RECT  30.6 28.049 38.394 28.417 ;
     RECT  162.936 27.941 167.31 28.561 ;
     RECT  168.084 28.291 177.066 28.561 ;
     RECT  26.856 12.941 26.946 28.589 ;
     RECT  200.916 4.217 200.934 28.787 ;
     RECT  52.452 27.949 162.198 28.795 ;
     RECT  162.936 28.561 177.066 28.795 ;
     RECT  189.9 25.997 189.918 28.823 ;
     RECT  39.168 28.049 51.642 28.831 ;
     RECT  26.928 28.589 26.946 28.859 ;
     RECT  177.876 28.349 180.897 28.949 ;
     RECT  29.415 28.417 38.394 29.065 ;
     RECT  39.132 28.831 51.642 29.065 ;
     RECT  29.415 29.065 51.642 29.069 ;
     RECT  48.456 29.069 51.642 29.083 ;
     RECT  52.452 28.795 177.066 29.083 ;
     RECT  183.024 25.085 183.114 29.083 ;
     RECT  29.415 29.069 47.538 29.255 ;
     RECT  194.22 12.941 194.814 29.363 ;
     RECT  182.592 29.083 183.114 29.489 ;
     RECT  48.456 29.083 177.066 29.839 ;
     RECT  30.6 29.255 47.538 29.875 ;
     RECT  48.312 29.839 177.066 29.875 ;
     RECT  183.096 29.489 183.114 29.939 ;
     RECT  30.6 29.875 177.066 30.173 ;
     RECT  28.44 16.529 28.458 30.443 ;
     RECT  158.58 30.173 177.066 30.461 ;
     RECT  29.415 29.255 29.697 30.811 ;
     RECT  30.6 30.173 157.59 30.811 ;
     RECT  29.415 30.811 157.59 30.875 ;
     RECT  158.616 30.461 177.066 31.621 ;
     RECT  194.22 29.363 194.238 31.649 ;
     RECT  30.6 30.875 157.59 31.801 ;
     RECT  29.415 30.875 29.697 31.915 ;
     RECT  158.616 31.621 177.102 32.027 ;
     RECT  29.415 31.915 29.862 32.071 ;
     RECT  30.6 31.801 157.878 32.071 ;
     RECT  29.415 32.071 157.878 32.189 ;
     RECT  158.688 32.027 177.102 32.197 ;
     RECT  177.876 28.949 179.874 32.197 ;
     RECT  29.415 32.189 29.862 32.225 ;
     RECT  30.78 32.189 47.61 32.225 ;
     RECT  196.272 16.835 198.162 32.225 ;
     RECT  48.42 32.189 157.878 32.261 ;
     RECT  30.78 32.225 47.394 32.459 ;
     RECT  30.78 32.459 30.798 32.495 ;
     RECT  31.896 32.459 47.394 32.495 ;
     RECT  37.656 32.495 47.394 32.576 ;
     RECT  37.656 32.576 38.142 32.765 ;
     RECT  48.42 32.261 157.626 32.771 ;
     RECT  31.896 32.495 36.882 32.801 ;
     RECT  193.068 22.541 193.086 32.801 ;
     RECT  38.952 32.576 47.394 32.837 ;
     RECT  48.636 32.771 157.626 32.999 ;
     RECT  49.176 32.999 157.626 33.035 ;
     RECT  39.204 32.837 47.394 33.413 ;
     RECT  49.176 33.035 157.554 33.413 ;
     RECT  52.38 33.413 157.554 33.787 ;
     RECT  52.38 33.787 157.878 33.881 ;
     RECT  196.815 32.225 198.162 33.917 ;
     RECT  52.38 33.881 157.554 33.923 ;
     RECT  53.928 33.923 157.554 34.397 ;
     RECT  182.7 34.231 182.718 34.501 ;
     RECT  182.412 34.501 182.718 34.591 ;
     RECT  181.764 34.591 182.718 34.637 ;
     RECT  180.615 28.949 180.897 34.795 ;
     RECT  182.052 34.637 182.718 35.041 ;
     RECT  196.815 33.917 197.478 35.069 ;
     RECT  53.928 34.397 157.464 35.131 ;
     RECT  180.615 34.795 180.99 35.131 ;
     RECT  182.052 35.041 183.006 35.131 ;
     RECT  184.032 34.501 184.05 35.311 ;
     RECT  53.928 35.131 157.554 35.323 ;
     RECT  158.688 32.197 179.874 35.401 ;
     RECT  180.615 35.131 181.278 35.401 ;
     RECT  53.928 35.323 157.734 35.453 ;
     RECT  53.928 35.453 157.554 35.597 ;
     RECT  184.032 35.311 184.23 35.671 ;
     RECT  158.688 35.401 181.278 35.707 ;
     RECT  182.052 35.131 183.042 35.707 ;
     RECT  158.472 35.707 183.042 35.743 ;
     RECT  184.032 35.671 184.266 35.743 ;
     RECT  186.015 25.997 186.297 35.851 ;
     RECT  158.472 35.743 184.266 35.879 ;
     RECT  182.988 35.879 184.266 36.049 ;
     RECT  185.904 35.851 186.297 36.091 ;
     RECT  185.904 36.091 186.858 36.239 ;
     RECT  182.988 36.049 184.374 36.283 ;
     RECT  182.988 36.283 184.518 36.391 ;
     RECT  185.904 36.239 186.426 36.419 ;
     RECT  185.904 36.419 186.297 36.461 ;
     RECT  53.928 35.597 157.464 36.475 ;
     RECT  53.928 36.475 157.554 36.481 ;
     RECT  158.472 35.879 182.106 36.481 ;
     RECT  53.928 36.481 182.106 36.751 ;
     RECT  187.992 36.391 188.01 36.859 ;
     RECT  189.504 36.661 189.522 36.859 ;
     RECT  191.415 18.221 191.697 36.895 ;
     RECT  189.504 36.859 190.206 36.931 ;
     RECT  53.928 36.751 182.214 36.959 ;
     RECT  187.992 36.859 188.298 37.021 ;
     RECT  189.072 36.931 190.206 37.049 ;
     RECT  182.088 36.959 182.214 37.129 ;
     RECT  187.884 37.021 188.298 37.129 ;
     RECT  187.704 37.129 188.298 37.201 ;
     RECT  187.704 37.201 188.586 37.243 ;
     RECT  187.488 37.243 188.586 37.319 ;
     RECT  189.504 37.049 190.206 37.319 ;
     RECT  187.488 37.319 188.442 37.399 ;
     RECT  182.088 37.129 182.25 37.435 ;
     RECT  182.988 36.391 184.878 37.435 ;
     RECT  186.015 36.461 186.297 37.561 ;
     RECT  53.928 36.959 181.35 37.565 ;
     RECT  187.344 37.399 188.442 37.589 ;
     RECT  191.415 36.895 192.114 37.589 ;
     RECT  158.472 37.565 181.35 37.859 ;
     RECT  190.116 37.319 190.206 38.011 ;
     RECT  193.464 37.741 193.482 38.011 ;
     RECT  190.116 38.011 190.422 38.165 ;
     RECT  193.464 38.011 193.554 38.173 ;
     RECT  187.884 37.589 188.442 38.245 ;
     RECT  186.015 37.561 186.426 38.281 ;
     RECT  187.884 38.245 188.91 38.281 ;
     RECT  158.508 37.859 181.35 38.309 ;
     RECT  193.104 38.173 193.554 38.443 ;
     RECT  186.015 38.281 186.462 38.471 ;
     RECT  193.104 38.443 193.842 38.635 ;
     RECT  192.888 38.635 193.842 38.669 ;
     RECT  53.928 37.565 157.662 38.875 ;
     RECT  187.884 38.281 188.946 38.939 ;
     RECT  53.928 38.875 157.878 39.047 ;
     RECT  190.116 38.165 190.134 39.091 ;
     RECT  158.688 38.309 181.35 39.209 ;
     RECT  182.088 37.435 184.878 39.209 ;
     RECT  158.688 39.209 179.442 39.281 ;
     RECT  186.015 38.471 186.39 39.281 ;
     RECT  192.888 38.669 193.554 39.355 ;
     RECT  196.815 35.069 197.097 39.355 ;
     RECT  196.704 39.355 197.097 39.361 ;
     RECT  198.252 39.181 198.27 39.361 ;
     RECT  196.704 39.361 198.27 39.479 ;
     RECT  52.38 33.923 53.118 39.547 ;
     RECT  53.928 39.047 157.59 39.547 ;
     RECT  52.38 39.547 157.59 39.623 ;
     RECT  196.704 39.479 197.097 39.629 ;
     RECT  192.456 39.355 193.554 39.749 ;
     RECT  53.928 39.623 157.59 39.773 ;
     RECT  197.928 39.479 198.27 39.991 ;
     RECT  194.328 39.865 194.346 40.019 ;
     RECT  158.688 39.281 178.398 40.027 ;
     RECT  179.172 39.281 179.442 40.027 ;
     RECT  158.688 40.027 179.442 40.127 ;
     RECT  61.668 39.773 157.59 40.162 ;
     RECT  179.424 40.127 179.442 40.171 ;
     RECT  180.504 39.209 181.35 40.171 ;
     RECT  183.42 39.209 184.878 40.459 ;
     RECT  186.015 39.281 186.297 40.459 ;
     RECT  52.38 39.623 53.118 40.651 ;
     RECT  53.928 39.773 60.894 40.651 ;
     RECT  52.38 40.651 60.894 40.703 ;
     RECT  61.668 40.162 157.626 40.795 ;
     RECT  61.668 40.795 157.878 40.829 ;
     RECT  158.688 40.127 178.686 40.829 ;
     RECT  158.688 40.829 177.21 40.865 ;
     RECT  158.688 40.865 176.778 40.901 ;
     RECT  53.928 40.703 60.894 40.925 ;
     RECT  178.416 40.829 178.686 40.973 ;
     RECT  158.688 40.901 176.418 41.009 ;
     RECT  53.928 40.925 60.714 41.021 ;
     RECT  179.424 40.171 181.35 41.035 ;
     RECT  195.516 41.035 195.534 41.135 ;
     RECT  158.688 41.009 176.13 41.171 ;
     RECT  53.928 41.021 60.57 41.213 ;
     RECT  194.364 41.143 194.382 41.279 ;
     RECT  61.992 40.829 157.878 41.341 ;
     RECT  158.688 41.171 176.094 41.341 ;
     RECT  182.088 39.209 182.682 41.369 ;
     RECT  183.42 40.459 186.297 41.369 ;
     RECT  53.928 41.213 60.534 41.405 ;
     RECT  178.992 41.035 181.35 41.405 ;
     RECT  183.42 41.369 184.878 41.521 ;
     RECT  61.992 41.341 176.094 41.675 ;
     RECT  53.928 41.405 60.39 41.755 ;
     RECT  52.38 40.703 53.118 41.791 ;
     RECT  53.892 41.755 60.39 41.791 ;
     RECT  177.444 41.791 177.462 41.909 ;
     RECT  52.38 41.791 60.39 41.945 ;
     RECT  61.992 41.675 175.497 41.945 ;
     RECT  158.616 41.945 175.497 42.017 ;
     RECT  52.38 41.945 53.19 42.029 ;
     RECT  191.415 37.589 191.697 42.061 ;
     RECT  53.928 41.945 60.39 42.077 ;
     RECT  158.652 42.017 175.497 42.089 ;
     RECT  190.944 42.061 191.697 42.331 ;
     RECT  61.992 41.945 157.878 42.365 ;
     RECT  53.928 42.077 60.354 42.461 ;
     RECT  179.424 41.405 181.35 42.691 ;
     RECT  178.848 42.691 181.35 42.715 ;
     RECT  178.488 42.715 181.35 42.749 ;
     RECT  178.488 42.749 178.506 42.755 ;
     RECT  62.64 42.365 157.878 42.941 ;
     RECT  62.64 42.941 157.77 43.339 ;
     RECT  176.616 42.331 176.634 43.339 ;
     RECT  176.256 43.339 176.634 43.411 ;
     RECT  176.256 43.411 177.21 43.529 ;
     RECT  176.616 43.529 177.21 43.609 ;
     RECT  53.928 42.461 60.174 43.627 ;
     RECT  158.688 42.089 175.497 43.681 ;
     RECT  176.616 43.609 177.282 43.681 ;
     RECT  202.215 9.419 202.497 43.681 ;
     RECT  62.532 43.339 157.77 43.843 ;
     RECT  176.616 43.681 177.318 43.871 ;
     RECT  53.928 43.627 60.714 43.907 ;
     RECT  62.532 43.843 157.878 43.951 ;
     RECT  158.688 43.681 175.554 43.951 ;
     RECT  189.396 39.091 190.134 43.951 ;
     RECT  190.872 42.331 191.697 43.951 ;
     RECT  62.532 43.951 175.554 43.979 ;
     RECT  176.616 43.871 177.246 44.069 ;
     RECT  189.396 43.951 191.697 44.069 ;
     RECT  62.532 43.979 175.497 44.107 ;
     RECT  190.872 44.069 191.697 44.221 ;
     RECT  192.96 39.749 193.554 44.221 ;
     RECT  62.496 44.107 175.497 44.285 ;
     RECT  56.16 43.907 60.714 44.477 ;
     RECT  202.215 43.681 203.202 45.031 ;
     RECT  202.215 45.031 203.238 45.149 ;
     RECT  62.64 44.285 157.59 45.301 ;
     RECT  158.508 44.285 175.497 45.301 ;
     RECT  204.948 43.843 204.966 45.301 ;
     RECT  62.64 45.301 175.497 45.595 ;
     RECT  53.928 43.907 55.278 45.773 ;
     RECT  62.532 45.595 175.497 45.917 ;
     RECT  60.156 44.477 60.714 46.109 ;
     RECT  56.16 44.477 58.986 46.111 ;
     RECT  53.928 45.773 55.206 46.301 ;
     RECT  62.532 45.917 157.59 46.507 ;
     RECT  62.46 46.507 157.59 46.645 ;
     RECT  158.508 45.917 175.497 46.645 ;
     RECT  32.508 32.801 36.882 46.741 ;
     RECT  60.696 46.109 60.714 46.747 ;
     RECT  62.46 46.645 175.497 46.747 ;
     RECT  32.508 46.741 37.314 46.769 ;
     RECT  56.124 46.111 58.986 46.813 ;
     RECT  56.124 46.813 59.094 46.843 ;
     RECT  62.388 46.747 175.497 46.849 ;
     RECT  60.696 46.747 61.254 46.939 ;
     RECT  56.124 46.843 59.598 46.987 ;
     RECT  60.408 46.939 61.254 46.987 ;
     RECT  62.352 46.849 175.497 47.011 ;
     RECT  6.768 46.747 6.786 47.039 ;
     RECT  62.352 47.011 175.842 47.155 ;
     RECT  6.552 47.191 6.57 47.261 ;
     RECT  62.316 47.155 175.842 47.261 ;
     RECT  62.388 47.261 157.554 47.309 ;
     RECT  176.616 44.069 177.138 47.899 ;
     RECT  178.092 47.083 178.11 48.119 ;
     RECT  62.64 47.309 157.554 48.271 ;
     RECT  158.472 47.261 175.842 48.271 ;
     RECT  176.616 47.899 177.174 48.271 ;
     RECT  62.64 48.271 175.842 48.605 ;
     RECT  158.472 48.605 175.842 48.929 ;
     RECT  38.124 32.765 38.142 49.147 ;
     RECT  37.296 46.769 37.314 49.195 ;
     RECT  38.088 49.147 38.142 49.195 ;
     RECT  158.472 48.929 174.078 49.199 ;
     RECT  37.296 49.195 38.142 49.235 ;
     RECT  176.616 48.271 177.318 49.379 ;
     RECT  62.64 48.605 157.554 49.711 ;
     RECT  158.472 49.199 174.006 49.711 ;
     RECT  62.64 49.711 174.006 49.757 ;
     RECT  62.64 49.757 157.554 50.584 ;
     RECT  62.64 50.584 157.59 51.331 ;
     RECT  158.472 49.757 174.006 51.331 ;
     RECT  62.64 51.331 174.006 51.581 ;
     RECT  158.472 51.581 174.006 51.701 ;
     RECT  158.508 51.701 174.006 52.483 ;
     RECT  56.124 46.987 61.254 52.699 ;
     RECT  56.124 52.699 61.542 52.745 ;
     RECT  62.64 51.581 157.59 52.795 ;
     RECT  61.992 52.795 157.59 52.861 ;
     RECT  158.472 52.483 174.006 52.861 ;
     RECT  61.992 52.861 174.006 52.889 ;
     RECT  62.064 52.889 174.006 52.925 ;
     RECT  62.1 52.925 157.59 52.979 ;
     RECT  158.472 52.925 174.006 53.015 ;
     RECT  45 33.413 47.394 53.035 ;
     RECT  158.508 53.015 174.006 53.329 ;
     RECT  39.204 33.413 44.262 53.597 ;
     RECT  49.176 33.413 51.297 53.659 ;
     RECT  205.956 52.951 205.974 53.833 ;
     RECT  49.176 53.659 51.39 53.837 ;
     RECT  158.508 53.329 174.078 53.861 ;
     RECT  62.64 52.979 157.59 53.941 ;
     RECT  32.508 46.769 36.414 54.173 ;
     RECT  62.64 53.941 157.878 54.328 ;
     RECT  32.652 54.173 36.414 54.329 ;
     RECT  62.424 54.328 157.878 54.331 ;
     RECT  38.124 49.235 38.142 54.337 ;
     RECT  39.204 53.597 44.154 54.337 ;
     RECT  62.244 54.331 157.878 54.337 ;
     RECT  38.124 54.337 44.154 54.437 ;
     RECT  62.136 54.337 157.878 54.557 ;
     RECT  62.244 54.557 157.554 54.653 ;
     RECT  37.296 49.235 37.314 54.715 ;
     RECT  37.296 54.715 37.35 54.743 ;
     RECT  38.916 54.437 44.154 54.749 ;
     RECT  62.388 54.653 157.554 54.893 ;
     RECT  37.332 54.743 37.35 55.243 ;
     RECT  38.124 54.437 38.142 55.243 ;
     RECT  32.652 54.329 36.27 55.277 ;
     RECT  37.332 55.243 38.142 55.277 ;
     RECT  158.724 53.861 174.078 55.417 ;
     RECT  62.46 54.893 157.554 55.561 ;
     RECT  158.508 55.417 174.078 55.561 ;
     RECT  62.46 55.561 174.078 55.613 ;
     RECT  32.652 55.277 35.982 55.819 ;
     RECT  62.532 55.613 157.59 56.021 ;
     RECT  62.532 56.021 157.554 56.045 ;
     RECT  174.96 48.929 175.842 57.019 ;
     RECT  176.616 49.379 177.138 57.019 ;
     RECT  62.64 56.045 157.554 57.181 ;
     RECT  158.472 55.613 174.078 57.181 ;
     RECT  37.332 55.277 37.89 57.271 ;
     RECT  174.96 57.019 177.138 57.299 ;
     RECT  62.64 57.181 174.078 57.533 ;
     RECT  45 53.035 47.574 57.547 ;
     RECT  62.64 57.533 157.554 57.643 ;
     RECT  49.176 53.837 51.297 57.677 ;
     RECT  176.616 57.299 177.138 57.991 ;
     RECT  62.532 57.643 157.554 58.109 ;
     RECT  52.38 42.029 53.118 58.123 ;
     RECT  53.928 46.301 54.99 58.123 ;
     RECT  62.64 58.109 157.554 58.261 ;
     RECT  158.472 57.533 174.078 58.261 ;
     RECT  185.616 41.369 186.297 58.351 ;
     RECT  56.124 52.745 61.254 58.487 ;
     RECT  62.64 58.261 174.078 58.699 ;
     RECT  174.96 57.299 175.842 58.699 ;
     RECT  62.64 58.699 175.842 58.829 ;
     RECT  62.64 58.829 172.89 58.877 ;
     RECT  210.672 53.293 210.69 58.963 ;
     RECT  56.16 58.487 61.254 58.987 ;
     RECT  158.472 58.877 172.89 58.991 ;
     RECT  173.808 58.829 175.842 58.991 ;
     RECT  185.616 58.351 186.426 59.027 ;
     RECT  39.024 54.749 44.154 59.233 ;
     RECT  44.928 57.547 47.574 59.233 ;
     RECT  56.16 58.987 61.398 59.323 ;
     RECT  62.64 58.877 157.554 59.419 ;
     RECT  62.532 59.419 157.554 59.605 ;
     RECT  158.472 58.991 166.842 59.605 ;
     RECT  56.16 59.323 61.542 59.611 ;
     RECT  62.532 59.605 166.842 59.611 ;
     RECT  56.16 59.611 166.842 59.933 ;
     RECT  167.58 58.991 172.89 60.376 ;
     RECT  173.808 58.991 175.497 60.376 ;
     RECT  158.508 59.933 166.842 60.691 ;
     RECT  176.616 57.991 177.282 60.763 ;
     RECT  176.616 60.763 177.318 60.809 ;
     RECT  56.16 59.933 157.554 61.045 ;
     RECT  158.472 60.691 166.842 61.045 ;
     RECT  56.16 61.045 166.842 61.277 ;
     RECT  167.58 60.376 175.497 62.155 ;
     RECT  167.58 62.155 175.698 62.311 ;
     RECT  158.472 61.277 166.842 62.609 ;
     RECT  167.58 62.311 175.878 62.699 ;
     RECT  56.16 61.277 157.554 62.851 ;
     RECT  158.472 62.609 163.494 62.851 ;
     RECT  176.616 60.809 177.282 62.851 ;
     RECT  178.236 49.171 178.254 62.851 ;
     RECT  56.16 62.851 163.494 63.197 ;
     RECT  56.16 63.197 157.554 63.925 ;
     RECT  158.472 63.197 163.494 63.925 ;
     RECT  56.16 63.925 163.494 64.541 ;
     RECT  158.472 64.541 163.494 64.634 ;
     RECT  167.58 62.699 175.806 65.083 ;
     RECT  167.58 65.083 175.842 65.281 ;
     RECT  176.616 62.851 178.254 65.281 ;
     RECT  32.184 55.819 35.982 65.309 ;
     RECT  196.815 39.629 197.097 65.371 ;
     RECT  207.615 14.549 207.897 65.371 ;
     RECT  196.704 65.371 197.097 65.408 ;
     RECT  207.504 65.371 207.897 65.408 ;
     RECT  211.968 65.371 211.986 65.408 ;
     RECT  158.508 64.634 163.494 65.467 ;
     RECT  211.752 65.509 211.77 65.549 ;
     RECT  56.16 64.541 157.554 65.551 ;
     RECT  158.472 65.467 163.494 65.551 ;
     RECT  56.16 65.551 163.494 65.693 ;
     RECT  158.472 65.693 163.494 66.479 ;
     RECT  164.232 62.609 166.842 66.929 ;
     RECT  56.16 65.693 157.59 66.984 ;
     RECT  56.16 66.984 63.81 67.199 ;
     RECT  56.16 67.199 63.738 67.229 ;
     RECT  66.528 66.984 66.654 67.711 ;
     RECT  158.724 66.479 163.494 67.711 ;
     RECT  77.832 66.984 77.85 67.771 ;
     RECT  56.16 67.229 62.946 67.805 ;
     RECT  56.16 67.805 62.91 67.901 ;
     RECT  66.384 67.711 66.654 67.915 ;
     RECT  67.824 66.984 67.842 67.915 ;
     RECT  70.74 66.984 70.758 67.973 ;
     RECT  91.152 66.984 91.206 68.107 ;
     RECT  91.008 68.107 91.206 68.179 ;
     RECT  71.892 66.984 72.126 68.215 ;
     RECT  67.824 67.915 68.454 68.341 ;
     RECT  66.384 67.915 66.762 68.377 ;
     RECT  155.484 66.984 155.502 68.377 ;
     RECT  158.472 67.711 163.494 68.441 ;
     RECT  167.58 65.281 178.254 68.477 ;
     RECT  65.232 68.395 65.25 68.491 ;
     RECT  66.384 68.377 66.978 68.491 ;
     RECT  65.232 68.491 66.978 68.621 ;
     RECT  76.608 66.984 76.626 68.719 ;
     RECT  73.512 66.984 73.53 68.731 ;
     RECT  74.376 67.915 74.394 68.731 ;
     RECT  167.868 68.477 178.254 68.747 ;
     RECT  90.792 68.179 91.206 68.755 ;
     RECT  88.344 66.984 88.794 68.836 ;
     RECT  76.608 68.719 77.022 68.881 ;
     RECT  77.76 67.771 77.85 68.881 ;
     RECT  76.608 68.881 77.85 68.923 ;
     RECT  78.804 68.203 78.822 68.923 ;
     RECT  66.384 68.621 66.978 68.971 ;
     RECT  67.824 68.341 68.67 68.971 ;
     RECT  73.512 68.731 74.394 68.971 ;
     RECT  75.24 68.683 75.51 68.971 ;
     RECT  79.992 67.723 80.01 68.971 ;
     RECT  82.476 66.984 83.25 68.971 ;
     RECT  84.888 66.984 84.906 68.971 ;
     RECT  89.604 68.791 89.622 68.971 ;
     RECT  90.792 68.755 91.242 68.971 ;
     RECT  70.2 68.971 70.218 68.989 ;
     RECT  73.512 68.971 75.51 69.019 ;
     RECT  76.608 68.923 78.822 69.019 ;
     RECT  70.2 68.989 70.83 69.061 ;
     RECT  71.64 68.215 72.126 69.061 ;
     RECT  84.6 68.971 85.158 69.061 ;
     RECT  86.004 68.971 86.598 69.061 ;
     RECT  90.576 68.971 91.422 69.061 ;
     RECT  86.004 69.061 86.706 69.067 ;
     RECT  109.404 68.971 109.71 69.067 ;
     RECT  70.2 69.061 72.126 69.103 ;
     RECT  82.008 68.971 83.25 69.103 ;
     RECT  87.696 68.836 88.794 69.103 ;
     RECT  89.604 68.971 89.802 69.103 ;
     RECT  109.368 69.067 109.71 69.103 ;
     RECT  70.2 69.103 72.705 69.115 ;
     RECT  73.512 69.019 78.822 69.115 ;
     RECT  82.008 69.103 83.505 69.115 ;
     RECT  86.004 69.067 86.742 69.115 ;
     RECT  94.215 69.103 94.305 69.115 ;
     RECT  99.615 69.103 99.705 69.115 ;
     RECT  114.768 68.635 114.786 69.115 ;
     RECT  115.815 69.103 115.905 69.115 ;
     RECT  109.368 69.103 110.505 69.151 ;
     RECT  112.86 68.107 112.878 69.151 ;
     RECT  56.16 67.901 62.838 69.163 ;
     RECT  98.712 69.115 98.73 69.163 ;
     RECT  99.615 69.115 99.81 69.163 ;
     RECT  79.884 68.971 80.334 69.179 ;
     RECT  81.828 69.115 83.61 69.179 ;
     RECT  84.42 69.061 85.158 69.179 ;
     RECT  103.572 69.115 103.59 69.179 ;
     RECT  114.012 68.059 114.03 69.179 ;
     RECT  114.768 69.115 115.905 69.179 ;
     RECT  70.2 69.115 78.858 69.187 ;
     RECT  82.368 69.179 83.61 69.211 ;
     RECT  84.42 69.179 84.906 69.211 ;
     RECT  94.215 69.115 94.41 69.211 ;
     RECT  98.712 69.163 98.802 69.211 ;
     RECT  99.615 69.163 99.882 69.211 ;
     RECT  112.644 69.151 112.878 69.211 ;
     RECT  86.004 69.115 86.85 69.223 ;
     RECT  87.696 69.103 89.802 69.223 ;
     RECT  90.576 69.061 91.458 69.223 ;
     RECT  85.68 69.223 91.458 69.245 ;
     RECT  108.216 69.151 108.234 69.245 ;
     RECT  70.092 69.187 78.858 69.251 ;
     RECT  109.044 69.151 110.754 69.251 ;
     RECT  115.164 69.179 115.905 69.251 ;
     RECT  70.092 69.251 78.786 69.259 ;
     RECT  109.404 69.251 110.754 69.259 ;
     RECT  111.744 69.211 113.85 69.259 ;
     RECT  70.02 69.259 78.786 69.287 ;
     RECT  87.552 69.245 91.458 69.287 ;
     RECT  106.596 69.163 106.614 69.292 ;
     RECT  85.68 69.245 86.742 69.293 ;
     RECT  87.552 69.287 89.19 69.293 ;
     RECT  98.604 69.211 98.802 69.293 ;
     RECT  106.596 69.292 106.65 69.293 ;
     RECT  109.404 69.259 113.85 69.296 ;
     RECT  56.16 69.163 62.874 69.307 ;
     RECT  86.436 69.293 86.742 69.323 ;
     RECT  115.2 69.251 115.905 69.323 ;
     RECT  79.884 69.179 80.01 69.331 ;
     RECT  106.632 69.293 106.65 69.331 ;
     RECT  87.552 69.293 89.118 69.341 ;
     RECT  70.776 69.287 78.786 69.359 ;
     RECT  87.552 69.341 89.097 69.359 ;
     RECT  105.015 69.103 105.105 69.373 ;
     RECT  115.416 69.323 115.905 69.373 ;
     RECT  121.215 69.103 121.305 69.373 ;
     RECT  126.615 69.103 126.705 69.373 ;
     RECT  132.015 69.103 132.105 69.373 ;
     RECT  137.415 69.103 137.505 69.373 ;
     RECT  142.815 69.103 142.905 69.373 ;
     RECT  148.215 69.103 148.305 69.373 ;
     RECT  153.615 69.103 153.705 69.373 ;
     RECT  70.776 69.359 78.678 69.437 ;
     RECT  70.812 69.437 78.534 69.449 ;
     RECT  86.472 69.323 86.742 69.449 ;
     RECT  106.632 69.331 107.262 69.449 ;
     RECT  109.404 69.296 110.79 69.449 ;
     RECT  94.215 69.211 94.554 69.457 ;
     RECT  75.492 69.449 78.534 69.485 ;
     RECT  82.368 69.211 84.906 69.485 ;
     RECT  94.215 69.457 95.238 69.485 ;
     RECT  98.604 69.293 98.622 69.485 ;
     RECT  99.615 69.211 99.954 69.485 ;
     RECT  90.108 69.287 91.458 69.493 ;
     RECT  115.416 69.373 116.097 69.493 ;
     RECT  56.16 69.307 62.982 69.521 ;
     RECT  70.848 69.449 74.754 69.521 ;
     RECT  76.608 69.485 78.534 69.521 ;
     RECT  90.108 69.493 91.782 69.521 ;
     RECT  109.404 69.449 110.754 69.521 ;
     RECT  111.996 69.296 113.85 69.521 ;
     RECT  107.244 69.449 107.262 69.533 ;
     RECT  167.868 68.747 173.214 69.725 ;
     RECT  91.152 69.521 91.782 69.899 ;
     RECT  111.996 69.521 113.706 70.123 ;
     RECT  164.232 66.929 166.806 70.367 ;
     RECT  115.416 69.493 116.334 70.573 ;
     RECT  111.888 70.123 113.706 70.601 ;
     RECT  164.268 70.367 166.806 70.709 ;
     RECT  164.268 70.709 166.77 70.877 ;
     RECT  158.472 68.441 163.35 71.105 ;
     RECT  139.752 70.771 139.77 71.275 ;
     RECT  71.496 69.521 74.394 71.323 ;
     RECT  161.676 71.105 163.35 71.375 ;
     RECT  162.9 71.375 163.35 71.411 ;
     RECT  172.008 69.725 173.214 71.447 ;
     RECT  71.496 71.323 74.754 71.453 ;
     RECT  174.42 68.747 178.254 71.455 ;
     RECT  81.504 71.275 81.522 71.609 ;
     RECT  139.752 71.275 140.022 71.609 ;
     RECT  81.252 71.611 81.27 71.837 ;
     RECT  141.552 71.761 141.57 71.837 ;
     RECT  111.996 70.601 113.706 71.879 ;
     RECT  91.224 69.899 91.782 72.121 ;
     RECT  77.4 69.521 78.39 72.149 ;
     RECT  75.492 69.485 75.87 72.391 ;
     RECT  66.384 68.971 68.67 72.419 ;
     RECT  71.496 71.453 74.394 72.419 ;
     RECT  158.472 71.105 160.866 72.419 ;
     RECT  63.72 67.229 63.738 72.661 ;
     RECT  94.215 69.485 94.497 72.661 ;
     RECT  95.22 69.485 95.238 72.661 ;
     RECT  90.108 69.521 90.126 72.689 ;
     RECT  86.472 69.449 86.49 73.237 ;
     RECT  87.696 69.359 89.097 73.237 ;
     RECT  182.088 41.369 182.106 73.339 ;
     RECT  182.88 41.521 184.878 73.339 ;
     RECT  161.676 71.375 162.162 73.499 ;
     RECT  182.088 73.339 184.878 73.517 ;
     RECT  70.02 69.287 70.038 73.543 ;
     RECT  91.224 72.121 92.322 73.813 ;
     RECT  157.572 66.984 157.59 73.885 ;
     RECT  158.472 72.419 160.83 73.885 ;
     RECT  90.576 73.813 92.322 74.353 ;
     RECT  76.608 69.521 76.626 74.381 ;
     RECT  157.572 73.885 160.83 74.849 ;
     RECT  153.615 69.373 153.897 74.857 ;
     RECT  94.215 72.661 95.238 74.929 ;
     RECT  82.476 69.485 83.697 74.957 ;
     RECT  82.476 74.957 82.494 75.533 ;
     RECT  84.42 69.485 84.906 76.109 ;
     RECT  172.476 71.447 173.214 77.009 ;
     RECT  96.192 75.505 96.21 77.791 ;
     RECT  96.948 76.081 96.966 77.791 ;
     RECT  79.524 69.331 80.01 77.819 ;
     RECT  167.868 69.725 171.126 78.089 ;
     RECT  77.4 72.149 78.297 78.097 ;
     RECT  84.42 76.109 84.438 78.187 ;
     RECT  172.476 77.009 172.638 78.205 ;
     RECT  173.484 77.125 173.502 78.205 ;
     RECT  84.42 78.187 84.942 78.359 ;
     RECT  77.004 78.097 78.297 78.619 ;
     RECT  79.524 77.819 79.542 78.619 ;
     RECT  84.42 78.359 84.726 78.653 ;
     RECT  77.004 78.619 79.542 78.665 ;
     RECT  81.504 78.667 81.522 78.899 ;
     RECT  81.252 79.051 81.27 79.229 ;
     RECT  174.42 71.455 178.578 79.439 ;
     RECT  172.476 78.205 173.502 81.751 ;
     RECT  167.868 78.089 171.054 81.985 ;
     RECT  171.864 81.751 173.502 81.985 ;
     RECT  167.868 81.985 173.502 82.061 ;
     RECT  115.2 70.573 116.334 83.227 ;
     RECT  111.996 71.879 112.014 83.255 ;
     RECT  137.415 69.373 137.697 83.497 ;
     RECT  213.015 24.809 213.297 83.497 ;
     RECT  39.024 59.233 47.574 83.525 ;
     RECT  56.16 69.521 62.514 83.525 ;
     RECT  209.304 47.047 209.322 83.533 ;
     RECT  39.168 83.525 47.574 83.561 ;
     RECT  30.672 65.281 30.69 83.767 ;
     RECT  32.364 65.309 35.982 83.795 ;
     RECT  207.615 65.408 207.897 84.001 ;
     RECT  137.376 83.497 137.697 84.065 ;
     RECT  182.88 73.517 184.878 84.811 ;
     RECT  185.616 59.027 186.297 84.811 ;
     RECT  187.02 84.763 187.038 84.839 ;
     RECT  182.88 84.811 186.297 84.848 ;
     RECT  172.476 82.061 173.502 85.243 ;
     RECT  172.152 85.243 173.502 85.517 ;
     RECT  164.304 70.877 166.77 86.161 ;
     RECT  167.868 82.061 171.054 86.161 ;
     RECT  164.304 86.161 171.054 86.237 ;
     RECT  34.632 83.795 35.982 86.701 ;
     RECT  75.312 72.391 75.87 87.781 ;
     RECT  71.496 72.419 73.818 87.809 ;
     RECT  71.496 87.809 73.53 88.385 ;
     RECT  72.036 88.385 73.53 88.655 ;
     RECT  70.02 73.543 70.722 89.203 ;
     RECT  86.472 73.237 89.097 89.203 ;
     RECT  66.384 72.419 66.438 89.231 ;
     RECT  74.7 87.781 75.87 89.231 ;
     RECT  67.215 72.419 68.67 89.537 ;
     RECT  113.076 71.879 113.706 89.537 ;
     RECT  7.815 24.773 8.097 89.743 ;
     RECT  98.46 69.835 98.478 89.743 ;
     RECT  114.48 83.227 116.334 89.743 ;
     RECT  56.16 83.525 56.697 89.771 ;
     RECT  66.42 89.231 66.438 89.771 ;
     RECT  86.472 89.203 89.55 89.771 ;
     RECT  109.692 69.521 110.754 89.771 ;
     RECT  139.752 71.609 139.77 89.771 ;
     RECT  37.332 57.271 38.106 89.779 ;
     RECT  212.544 83.497 213.297 89.779 ;
     RECT  42.876 83.561 47.574 89.807 ;
     RECT  86.472 89.771 87.714 89.807 ;
     RECT  158.112 74.849 160.83 89.807 ;
     RECT  164.304 86.237 166.77 89.807 ;
     RECT  65.232 68.621 65.25 90.049 ;
     RECT  65.232 90.049 65.574 90.077 ;
     RECT  77.004 78.665 78.297 90.149 ;
     RECT  86.652 89.807 87.714 90.239 ;
     RECT  176.328 79.439 178.578 90.347 ;
     RECT  67.215 89.537 68.49 90.509 ;
     RECT  69.444 89.203 70.722 90.589 ;
     RECT  87.012 90.239 87.714 90.619 ;
     RECT  88.815 89.771 89.55 90.619 ;
     RECT  27.9 65.245 27.918 90.625 ;
     RECT  34.632 86.701 36.054 90.625 ;
     RECT  42.876 89.807 43.074 90.625 ;
     RECT  43.848 89.807 47.574 90.625 ;
     RECT  65.556 90.077 65.574 90.625 ;
     RECT  69.372 90.589 70.722 90.625 ;
     RECT  63.72 72.661 63.918 90.661 ;
     RECT  87.012 90.619 89.55 90.661 ;
     RECT  90.576 74.353 92.43 90.661 ;
     RECT  57.672 83.525 62.514 90.689 ;
     RECT  85.68 69.293 85.698 90.689 ;
     RECT  68.22 90.509 68.49 90.751 ;
     RECT  69.372 90.625 70.794 90.751 ;
     RECT  65.556 90.625 66.078 90.763 ;
     RECT  67.215 90.509 67.497 90.763 ;
     RECT  57.672 90.689 59.094 90.779 ;
     RECT  65.556 90.763 67.497 90.779 ;
     RECT  27.828 90.625 27.918 90.823 ;
     RECT  66.708 90.779 67.497 90.893 ;
     RECT  29.415 32.225 29.697 90.895 ;
     RECT  167.868 86.237 171.054 90.923 ;
     RECT  30.672 83.767 31.338 90.931 ;
     RECT  74.7 89.231 75.33 90.931 ;
     RECT  26.784 90.931 26.802 91.021 ;
     RECT  87.012 90.661 92.43 91.049 ;
     RECT  99.615 69.485 99.897 91.093 ;
     RECT  81.612 90.859 81.63 91.129 ;
     RECT  29.415 90.895 29.826 91.165 ;
     RECT  30.672 90.931 31.482 91.165 ;
     RECT  74.232 90.931 75.33 91.165 ;
     RECT  77.004 90.149 77.022 91.195 ;
     RECT  49.212 57.677 51.297 91.201 ;
     RECT  63.468 90.661 63.918 91.201 ;
     RECT  96.192 77.791 96.966 91.201 ;
     RECT  99.615 91.093 99.954 91.201 ;
     RECT  29.415 91.165 31.482 91.229 ;
     RECT  59.976 90.689 62.514 91.285 ;
     RECT  59.976 91.285 62.586 91.291 ;
     RECT  68.22 90.751 70.794 91.291 ;
     RECT  72.036 88.655 73.314 91.291 ;
     RECT  76.968 91.195 77.022 91.291 ;
     RECT  42.876 90.625 47.574 91.319 ;
     RECT  52.236 58.123 55.17 91.319 ;
     RECT  57.564 90.931 57.582 91.319 ;
     RECT  114.156 89.743 116.334 91.319 ;
     RECT  59.976 91.291 62.658 91.327 ;
     RECT  63.468 91.201 64.674 91.327 ;
     RECT  79.524 78.665 79.542 91.327 ;
     RECT  114.156 91.319 116.097 91.327 ;
     RECT  76.968 91.291 77.274 91.328 ;
     RECT  42.876 91.319 44.406 91.363 ;
     RECT  76.968 91.328 77.166 91.373 ;
     RECT  79.524 91.327 79.902 91.373 ;
     RECT  87.012 91.049 91.422 91.399 ;
     RECT  27.828 90.823 28.17 91.435 ;
     RECT  86.652 91.399 91.422 91.435 ;
     RECT  98.028 89.743 98.478 91.435 ;
     RECT  25.452 91.435 25.47 91.471 ;
     RECT  30.636 91.229 31.482 91.471 ;
     RECT  32.364 83.795 33.786 91.471 ;
     RECT  34.56 90.625 36.054 91.471 ;
     RECT  37.332 89.779 38.178 91.471 ;
     RECT  42.84 91.363 44.406 91.471 ;
     RECT  56.268 89.771 56.697 91.471 ;
     RECT  58.392 90.779 59.094 91.471 ;
     RECT  59.976 91.327 64.674 91.471 ;
     RECT  78.015 90.149 78.297 91.471 ;
     RECT  93.708 74.929 95.238 91.471 ;
     RECT  96.12 91.201 96.966 91.471 ;
     RECT  172.476 85.517 173.502 91.499 ;
     RECT  27.828 91.435 28.566 91.561 ;
     RECT  29.415 91.229 29.826 91.561 ;
     RECT  34.524 91.471 36.054 91.561 ;
     RECT  37.152 91.471 38.178 91.561 ;
     RECT  39.168 83.561 42.03 91.561 ;
     RECT  42.804 91.471 44.406 91.561 ;
     RECT  76.968 91.373 77.022 91.561 ;
     RECT  81.504 91.129 81.63 91.561 ;
     RECT  83.415 74.957 83.697 91.561 ;
     RECT  84.42 78.653 84.438 91.561 ;
     RECT  80.964 91.561 81.63 91.579 ;
     RECT  83.415 91.561 84.438 91.579 ;
     RECT  92.16 91.049 92.43 91.579 ;
     RECT  93.708 91.471 96.966 91.579 ;
     RECT  86.4 91.435 91.422 91.589 ;
     RECT  26.784 91.021 26.838 91.597 ;
     RECT  34.524 91.561 38.178 91.597 ;
     RECT  39.168 91.561 44.406 91.597 ;
     RECT  66.852 90.893 67.497 91.597 ;
     RECT  68.22 91.291 73.314 91.597 ;
     RECT  93.564 91.579 96.966 91.625 ;
     RECT  97.812 91.435 98.478 91.633 ;
     RECT  18.615 6.575 18.897 91.669 ;
     RECT  24.015 27.329 24.297 91.669 ;
     RECT  25.164 91.471 25.47 91.669 ;
     RECT  26.784 91.597 26.946 91.669 ;
     RECT  30.636 91.471 33.786 91.669 ;
     RECT  34.524 91.597 44.406 91.669 ;
     RECT  80.496 91.579 81.63 91.669 ;
     RECT  97.812 91.633 98.586 91.669 ;
     RECT  99.615 91.201 100.638 91.675 ;
     RECT  58.392 91.471 64.746 91.697 ;
     RECT  22.824 91.669 22.842 91.705 ;
     RECT  85.608 91.669 85.626 91.705 ;
     RECT  99.432 91.675 100.638 91.705 ;
     RECT  82.8 91.579 84.438 91.741 ;
     RECT  85.5 91.705 85.626 91.741 ;
     RECT  92.16 91.579 92.502 91.741 ;
     RECT  78.015 91.471 79.326 91.769 ;
     RECT  80.496 91.669 81.666 91.769 ;
     RECT  65.556 90.779 65.574 91.831 ;
     RECT  66.852 91.597 73.314 91.831 ;
     RECT  74.088 91.165 75.33 91.831 ;
     RECT  76.716 91.561 77.022 91.831 ;
     RECT  9.936 91.129 9.954 91.859 ;
     RECT  86.976 91.589 91.422 91.867 ;
     RECT  92.16 91.741 92.898 91.867 ;
     RECT  82.8 91.741 84.474 91.903 ;
     RECT  110.415 89.771 110.754 91.903 ;
     RECT  78.015 91.769 78.297 91.915 ;
     RECT  22.464 91.705 22.842 91.939 ;
     RECT  26.748 91.669 27.09 91.939 ;
     RECT  86.976 91.867 92.898 91.967 ;
     RECT  30.636 91.669 44.406 91.975 ;
     RECT  55.08 91.319 55.17 91.975 ;
     RECT  56.268 91.471 56.934 91.975 ;
     RECT  65.484 91.831 75.33 91.975 ;
     RECT  76.176 91.831 77.022 91.975 ;
     RECT  18.615 91.669 19.098 92.011 ;
     RECT  21.528 91.975 21.546 92.011 ;
     RECT  22.464 91.939 22.878 92.011 ;
     RECT  24.015 91.669 25.47 92.011 ;
     RECT  26.604 91.939 27.09 92.011 ;
     RECT  48.024 91.471 48.33 92.011 ;
     RECT  49.104 91.201 51.297 92.011 ;
     RECT  52.236 91.319 54.342 92.011 ;
     RECT  82.8 91.903 84.654 92.011 ;
     RECT  93.708 91.625 96.966 92.011 ;
     RECT  97.74 91.669 98.586 92.011 ;
     RECT  99.324 91.705 100.638 92.011 ;
     RECT  45.288 91.319 47.034 92.101 ;
     RECT  48.024 92.011 51.297 92.101 ;
     RECT  63.648 91.697 64.746 92.101 ;
     RECT  65.484 91.975 77.022 92.101 ;
     RECT  110.415 91.903 111.15 92.101 ;
     RECT  79.308 91.769 79.326 92.129 ;
     RECT  110.052 92.101 111.15 92.137 ;
     RECT  27.828 91.561 29.826 92.209 ;
     RECT  30.6 91.975 44.406 92.209 ;
     RECT  110.052 92.137 111.366 92.209 ;
     RECT  27.828 92.209 44.406 92.245 ;
     RECT  45.288 92.101 51.297 92.245 ;
     RECT  114.012 91.327 116.097 92.251 ;
     RECT  20.124 92.101 20.142 92.281 ;
     RECT  27.828 92.245 51.297 92.281 ;
     RECT  58.392 91.697 62.874 92.281 ;
     RECT  63.648 92.101 77.022 92.281 ;
     RECT  77.94 91.915 78.297 92.281 ;
     RECT  82.728 92.011 84.654 92.281 ;
     RECT  85.5 91.741 86.022 92.281 ;
     RECT  93.708 92.011 100.638 92.281 ;
     RECT  101.412 91.561 101.43 92.281 ;
     RECT  110.052 92.209 111.402 92.281 ;
     RECT  113.076 89.537 113.094 92.281 ;
     RECT  114.012 92.251 116.55 92.281 ;
     RECT  16.956 92.011 17.118 92.299 ;
     RECT  17.892 92.011 19.098 92.299 ;
     RECT  20.124 92.281 20.25 92.299 ;
     RECT  21.528 92.011 22.878 92.299 ;
     RECT  55.08 91.975 56.934 92.347 ;
     RECT  82.656 92.281 86.022 92.347 ;
     RECT  121.215 69.373 121.497 92.347 ;
     RECT  132.015 69.373 132.297 92.347 ;
     RECT  20.124 92.299 22.878 92.371 ;
     RECT  24.015 92.011 27.09 92.371 ;
     RECT  27.828 92.281 51.354 92.371 ;
     RECT  52.128 92.011 54.342 92.371 ;
     RECT  55.08 92.347 57.042 92.371 ;
     RECT  24.015 92.371 51.354 92.399 ;
     RECT  79.344 92.245 79.362 92.399 ;
     RECT  82.584 92.347 86.022 92.407 ;
     RECT  86.976 91.967 92.826 92.429 ;
     RECT  16.956 92.299 19.098 92.443 ;
     RECT  20.124 92.371 22.914 92.443 ;
     RECT  93.708 92.281 101.61 92.443 ;
     RECT  105.015 69.373 105.297 92.443 ;
     RECT  45.18 92.399 51.354 92.479 ;
     RECT  52.128 92.371 57.042 92.479 ;
     RECT  107.172 92.281 107.262 92.479 ;
     RECT  24.015 92.399 25.434 92.515 ;
     RECT  93.708 92.443 101.682 92.515 ;
     RECT  110.016 92.281 111.402 92.515 ;
     RECT  15.624 91.363 15.642 92.551 ;
     RECT  58.032 92.281 62.874 92.551 ;
     RECT  63.648 92.281 78.297 92.551 ;
     RECT  80.496 91.769 81.45 92.551 ;
     RECT  82.584 92.407 86.13 92.551 ;
     RECT  86.976 92.429 88.074 92.551 ;
     RECT  105.015 92.443 105.354 92.551 ;
     RECT  113.076 92.281 116.55 92.551 ;
     RECT  195.66 41.143 195.678 92.551 ;
     RECT  169.815 90.923 171.054 92.635 ;
     RECT  105.012 92.551 105.354 92.641 ;
     RECT  106.596 92.479 107.262 92.641 ;
     RECT  82.584 92.551 88.074 92.669 ;
     RECT  93.708 92.515 101.754 92.669 ;
     RECT  128.592 92.347 128.61 92.669 ;
     RECT  131.832 92.347 132.297 92.669 ;
     RECT  135.072 67.771 135.09 92.669 ;
     RECT  158.868 89.807 160.83 92.669 ;
     RECT  169.524 92.635 171.054 92.669 ;
     RECT  195.66 92.551 195.894 92.669 ;
     RECT  205.92 53.833 205.974 92.669 ;
     RECT  169.524 92.669 170.097 92.705 ;
     RECT  14.508 92.551 14.886 92.713 ;
     RECT  113.076 92.551 117.45 92.713 ;
     RECT  45.18 92.479 57.042 92.741 ;
     RECT  16.956 92.443 22.914 92.749 ;
     RECT  88.815 92.429 92.826 92.749 ;
     RECT  93.708 92.669 101.538 92.749 ;
     RECT  6.624 92.641 6.642 92.785 ;
     RECT  9.828 92.011 9.846 92.785 ;
     RECT  16.956 92.749 22.95 92.785 ;
     RECT  80.28 92.551 81.45 92.785 ;
     RECT  112.14 92.395 112.158 92.785 ;
     RECT  113.076 92.713 117.558 92.785 ;
     RECT  120.384 66.984 120.402 92.821 ;
     RECT  121.215 92.347 122.022 92.821 ;
     RECT  126.615 69.373 126.897 92.821 ;
     RECT  127.764 66.984 127.782 92.821 ;
     RECT  162.9 71.411 163.206 92.821 ;
     RECT  195.66 92.669 195.678 92.821 ;
     RECT  200.34 92.785 200.358 92.821 ;
     RECT  204.3 45.301 204.966 92.821 ;
     RECT  109.98 92.515 111.402 92.875 ;
     RECT  112.14 92.785 117.558 92.875 ;
     RECT  196.815 65.408 197.097 92.875 ;
     RECT  197.928 39.991 198.918 92.875 ;
     RECT  204.3 92.821 205.182 92.875 ;
     RECT  16.596 92.785 22.95 92.911 ;
     RECT  23.832 92.515 25.434 92.911 ;
     RECT  58.032 92.551 78.297 92.911 ;
     RECT  80.28 92.785 81.558 92.911 ;
     RECT  137.415 84.065 137.697 92.911 ;
     RECT  151.632 68.107 151.65 92.911 ;
     RECT  174.42 79.439 175.59 92.911 ;
     RECT  176.328 90.347 176.634 92.911 ;
     RECT  182.88 84.848 184.878 92.911 ;
     RECT  185.616 84.848 186.297 92.911 ;
     RECT  210.564 58.963 210.69 92.911 ;
     RECT  120.384 92.821 122.022 92.923 ;
     RECT  134.136 92.821 134.55 92.923 ;
     RECT  137.415 92.911 138.33 92.923 ;
     RECT  142.815 69.373 143.097 92.923 ;
     RECT  143.856 92.911 143.874 92.923 ;
     RECT  147.384 92.911 147.402 92.923 ;
     RECT  148.215 69.373 148.497 92.923 ;
     RECT  172.764 91.499 173.502 92.923 ;
     RECT  9.468 92.785 9.846 92.939 ;
     RECT  12.096 92.749 12.114 92.939 ;
     RECT  158.112 89.807 158.13 92.939 ;
     RECT  172.044 92.923 173.502 92.939 ;
     RECT  196.815 92.875 198.918 92.939 ;
     RECT  208.836 83.533 209.322 92.939 ;
     RECT  139.86 92.923 139.878 92.947 ;
     RECT  140.688 92.923 140.706 92.947 ;
     RECT  153.036 74.857 153.897 92.947 ;
     RECT  154.728 68.755 154.746 92.947 ;
     RECT  156.564 76.585 156.582 92.947 ;
     RECT  202.215 45.149 203.202 92.947 ;
     RECT  204.048 92.875 205.182 92.947 ;
     RECT  136.692 92.923 138.33 92.957 ;
     RECT  141.48 92.911 141.498 92.957 ;
     RECT  151.632 92.911 152.298 92.957 ;
     RECT  80.28 92.911 81.846 92.975 ;
     RECT  14.256 92.713 14.886 92.983 ;
     RECT  15.624 92.551 15.786 92.983 ;
     RECT  80.28 92.975 81.378 93.019 ;
     RECT  109.98 92.875 117.558 93.019 ;
     RECT  120.384 92.923 122.562 93.053 ;
     RECT  13.215 11.705 13.497 93.055 ;
     RECT  14.256 92.983 15.786 93.055 ;
     RECT  16.596 92.911 25.434 93.055 ;
     RECT  105.012 92.641 107.262 93.055 ;
     RECT  108.216 92.821 108.234 93.055 ;
     RECT  133.452 92.923 134.55 93.055 ;
     RECT  151.632 92.957 152.118 93.055 ;
     RECT  179.424 42.749 181.35 93.055 ;
     RECT  182.088 73.517 182.106 93.055 ;
     RECT  182.88 92.911 186.297 93.055 ;
     RECT  209.304 92.939 209.322 93.055 ;
     RECT  210.204 92.911 210.69 93.055 ;
     RECT  13.14 93.055 25.434 93.067 ;
     RECT  119.412 92.923 119.43 93.067 ;
     RECT  120.384 93.053 121.986 93.067 ;
     RECT  142.815 92.923 143.874 93.067 ;
     RECT  144.9 92.923 144.918 93.067 ;
     RECT  189.396 44.069 190.134 93.067 ;
     RECT  190.872 44.221 193.554 93.067 ;
     RECT  207.18 84.001 207.897 93.067 ;
     RECT  6.624 92.785 6.678 93.091 ;
     RECT  7.815 89.743 8.406 93.091 ;
     RECT  11.16 93.055 11.178 93.091 ;
     RECT  55.188 92.741 57.042 93.091 ;
     RECT  58.032 92.911 78.462 93.091 ;
     RECT  102.672 92.443 102.69 93.091 ;
     RECT  104.184 92.923 104.202 93.091 ;
     RECT  105.012 93.055 107.298 93.091 ;
     RECT  109.692 93.019 117.558 93.091 ;
     RECT  119.412 93.067 121.986 93.091 ;
     RECT  123.732 92.923 123.75 93.091 ;
     RECT  124.488 92.923 124.506 93.091 ;
     RECT  125.352 92.911 125.37 93.091 ;
     RECT  136.692 92.957 138.114 93.091 ;
     RECT  139.752 92.947 140.706 93.091 ;
     RECT  146.34 92.923 146.358 93.091 ;
     RECT  147.384 92.923 148.497 93.091 ;
     RECT  153.036 92.947 154.746 93.091 ;
     RECT  155.484 68.377 155.754 93.091 ;
     RECT  156.564 92.947 156.942 93.091 ;
     RECT  164.304 89.807 165.114 93.091 ;
     RECT  166.176 89.807 166.77 93.091 ;
     RECT  174.42 92.911 176.634 93.091 ;
     RECT  177.804 90.347 178.578 93.091 ;
     RECT  179.424 93.055 186.297 93.091 ;
     RECT  187.884 38.939 188.442 93.091 ;
     RECT  189.396 93.067 193.554 93.091 ;
     RECT  205.956 92.669 205.974 93.091 ;
     RECT  206.82 93.067 208.35 93.091 ;
     RECT  209.304 93.055 210.69 93.091 ;
     RECT  211.5 92.911 211.662 93.091 ;
     RECT  214.272 58.999 214.29 93.091 ;
     RECT  215.208 89.743 215.226 93.091 ;
     RECT  109.512 93.091 121.986 93.119 ;
     RECT  130.5 92.821 131.058 93.163 ;
     RECT  88.815 92.749 101.538 93.209 ;
     RECT  108.216 93.055 108.342 93.209 ;
     RECT  174.204 93.091 176.634 93.209 ;
     RECT  177.444 93.091 186.297 93.209 ;
     RECT  187.884 93.091 193.554 93.209 ;
     RECT  209.304 93.091 211.662 93.209 ;
     RECT  214.272 93.091 215.226 93.209 ;
     RECT  144.9 93.067 145.386 93.211 ;
     RECT  146.34 93.091 148.497 93.211 ;
     RECT  156.564 93.091 157.338 93.211 ;
     RECT  167.868 90.923 168.678 93.211 ;
     RECT  188.136 93.209 193.554 93.211 ;
     RECT  201.312 92.515 201.33 93.211 ;
     RECT  202.215 92.947 205.182 93.211 ;
     RECT  5.724 93.091 6.678 93.217 ;
     RECT  7.815 93.091 8.694 93.217 ;
     RECT  5.724 93.217 8.694 93.245 ;
     RECT  55.188 93.091 78.462 93.245 ;
     RECT  177.444 93.209 178.47 93.245 ;
     RECT  164.304 93.091 166.77 93.259 ;
     RECT  167.76 93.211 168.678 93.259 ;
     RECT  198.864 92.939 198.918 93.259 ;
     RECT  83.196 92.669 88.074 93.281 ;
     RECT  75.204 93.245 78.462 93.289 ;
     RECT  142.524 93.067 143.874 93.289 ;
     RECT  188.136 93.211 193.698 93.289 ;
     RECT  172.044 92.939 172.962 93.293 ;
     RECT  211.176 93.209 211.662 93.302 ;
     RECT  212.544 89.779 213.39 93.302 ;
     RECT  80.136 93.019 81.378 93.307 ;
     RECT  136.512 93.091 138.114 93.307 ;
     RECT  142.416 93.289 143.874 93.307 ;
     RECT  153.036 93.091 155.754 93.307 ;
     RECT  156.564 93.211 158.022 93.307 ;
     RECT  185.328 93.209 186.297 93.307 ;
     RECT  211.176 93.302 213.39 93.307 ;
     RECT  164.304 93.259 168.678 93.317 ;
     RECT  103.644 93.091 107.298 93.325 ;
     RECT  129.996 93.163 131.058 93.325 ;
     RECT  150.48 93.307 150.498 93.325 ;
     RECT  161.676 73.499 162.054 93.325 ;
     RECT  162.9 92.821 163.35 93.325 ;
     RECT  185.328 93.307 186.39 93.325 ;
     RECT  26.208 92.399 43.938 93.353 ;
     RECT  142.416 93.307 143.946 93.353 ;
     RECT  188.136 93.289 194.13 93.353 ;
     RECT  12.636 93.067 25.434 93.361 ;
     RECT  45.18 92.741 54.45 93.361 ;
     RECT  79.632 93.307 81.378 93.361 ;
     RECT  123.732 93.091 125.37 93.361 ;
     RECT  136.152 93.307 138.114 93.361 ;
     RECT  144.9 93.211 148.518 93.361 ;
     RECT  150.444 93.325 150.498 93.361 ;
     RECT  151.344 93.055 152.118 93.361 ;
     RECT  201.312 93.211 205.182 93.361 ;
     RECT  214.488 93.209 215.226 93.361 ;
     RECT  179.388 93.209 184.302 93.389 ;
     RECT  211.176 93.307 213.714 93.389 ;
     RECT  214.488 93.361 215.73 93.389 ;
     RECT  26.496 93.353 43.938 93.403 ;
     RECT  44.712 93.361 54.45 93.403 ;
     RECT  188.136 93.353 193.23 93.437 ;
     RECT  123.552 93.361 125.37 93.448 ;
     RECT  4.752 93.115 4.77 93.451 ;
     RECT  5.724 93.245 5.886 93.451 ;
     RECT  6.624 93.245 8.694 93.451 ;
     RECT  86.004 93.281 88.074 93.451 ;
     RECT  88.815 93.209 91.89 93.451 ;
     RECT  102.672 93.091 102.87 93.451 ;
     RECT  103.644 93.325 108.162 93.451 ;
     RECT  122.796 93.307 122.814 93.451 ;
     RECT  123.552 93.448 125.406 93.451 ;
     RECT  126.615 92.821 127.926 93.451 ;
     RECT  132.015 92.669 132.297 93.451 ;
     RECT  133.308 93.055 134.55 93.451 ;
     RECT  139.752 93.091 141.39 93.451 ;
     RECT  144.18 93.361 148.518 93.451 ;
     RECT  149.58 92.923 149.598 93.451 ;
     RECT  150.444 93.361 152.118 93.451 ;
     RECT  153.036 93.307 158.022 93.451 ;
     RECT  161.676 93.325 163.35 93.451 ;
     RECT  164.304 93.317 165.618 93.451 ;
     RECT  166.572 93.317 168.678 93.451 ;
     RECT  169.668 92.705 170.097 93.451 ;
     RECT  200.34 92.821 200.538 93.451 ;
     RECT  201.276 93.361 205.182 93.451 ;
     RECT  4.752 93.451 5.886 93.479 ;
     RECT  10.08 93.091 11.898 93.479 ;
     RECT  26.496 93.403 54.45 93.479 ;
     RECT  83.196 93.281 85.122 93.479 ;
     RECT  92.628 93.209 101.538 93.479 ;
     RECT  102.564 93.451 108.162 93.479 ;
     RECT  109.512 93.119 111.33 93.479 ;
     RECT  180.144 93.389 184.302 93.479 ;
     RECT  188.136 93.437 190.494 93.479 ;
     RECT  211.5 93.389 213.714 93.479 ;
     RECT  122.796 93.451 125.406 93.485 ;
     RECT  144.18 93.451 152.118 93.485 ;
     RECT  188.136 93.479 188.298 93.485 ;
     RECT  205.956 93.091 208.35 93.485 ;
     RECT  209.304 93.209 210.402 93.485 ;
     RECT  102.564 93.479 106.686 93.487 ;
     RECT  102.42 93.487 106.686 93.488 ;
     RECT  144.18 93.485 149.922 93.488 ;
     RECT  209.304 93.485 210.33 93.488 ;
     RECT  126.18 93.451 127.926 93.499 ;
     RECT  129.672 93.325 131.058 93.499 ;
     RECT  142.416 93.353 143.226 93.499 ;
     RECT  158.868 92.669 160.362 93.499 ;
     RECT  161.28 93.451 163.35 93.499 ;
     RECT  164.088 93.451 165.618 93.499 ;
     RECT  174.42 93.209 176.634 93.499 ;
     RECT  177.444 93.245 178.146 93.499 ;
     RECT  104.184 93.488 106.686 93.502 ;
     RECT  6.624 93.451 9.018 93.515 ;
     RECT  12.636 93.361 25.758 93.515 ;
     RECT  26.532 93.479 37.314 93.515 ;
     RECT  38.16 93.479 53.442 93.515 ;
     RECT  60.444 93.245 74.25 93.515 ;
     RECT  214.848 93.389 215.73 93.515 ;
     RECT  102.42 93.488 103.374 93.533 ;
     RECT  126.144 93.499 128.43 93.533 ;
     RECT  166.572 93.451 170.097 93.533 ;
     RECT  26.532 93.515 32.67 93.581 ;
     RECT  12.636 93.515 15.714 93.623 ;
     RECT  16.452 93.515 25.758 93.623 ;
     RECT  129.348 93.499 131.058 93.631 ;
     RECT  132.015 93.451 134.91 93.631 ;
     RECT  200.34 93.451 205.182 93.631 ;
     RECT  214.992 93.515 215.73 93.631 ;
     RECT  16.524 93.623 25.758 93.659 ;
     RECT  124.668 93.485 125.406 93.721 ;
     RECT  126.144 93.533 127.026 93.721 ;
     RECT  14.364 93.623 15.714 93.749 ;
     RECT  23.94 93.659 25.758 93.749 ;
     RECT  65.592 93.515 74.25 93.749 ;
     RECT  109.512 93.479 111.042 93.749 ;
     RECT  129.348 93.631 134.91 93.749 ;
     RECT  135.756 93.361 138.114 93.749 ;
     RECT  142.308 93.499 143.226 93.749 ;
     RECT  144.18 93.488 149.814 93.749 ;
     RECT  152.856 93.451 158.022 93.749 ;
     RECT  158.868 93.499 165.618 93.749 ;
     RECT  166.572 93.533 168.174 93.749 ;
     RECT  171 92.669 171.054 93.749 ;
     RECT  180.144 93.479 181.026 93.749 ;
     RECT  194.94 92.821 195.678 93.749 ;
     RECT  199.8 93.631 205.182 93.749 ;
     RECT  205.956 93.485 205.974 93.749 ;
     RECT  209.304 93.488 210.222 93.749 ;
     RECT  191.304 93.437 193.23 93.773 ;
     RECT  5.076 93.479 5.886 93.785 ;
     RECT  14.508 93.749 15.678 93.785 ;
     RECT  23.94 93.749 24.39 93.785 ;
     RECT  28.548 93.581 32.67 93.785 ;
     RECT  33.624 93.515 37.314 93.785 ;
     RECT  38.16 93.515 49.554 93.785 ;
     RECT  92.736 93.479 101.538 93.785 ;
     RECT  112.572 93.119 121.986 93.785 ;
     RECT  131.04 93.749 134.298 93.785 ;
     RECT  144.18 93.749 145.71 93.785 ;
     RECT  150.768 93.485 152.118 93.785 ;
     RECT  174.42 93.499 178.146 93.785 ;
     RECT  198.864 93.259 198.954 93.785 ;
     RECT  200.484 93.749 205.182 93.785 ;
     RECT  7.74 93.515 9.018 93.821 ;
     RECT  24.015 93.785 24.39 93.821 ;
     RECT  79.272 93.361 81.378 93.821 ;
     RECT  83.196 93.479 84.186 93.821 ;
     RECT  92.772 93.785 101.538 93.821 ;
     RECT  146.52 93.749 149.67 93.821 ;
     RECT  153.615 93.749 158.022 93.821 ;
     RECT  75.204 93.289 78.534 93.829 ;
     RECT  79.272 93.821 79.65 93.829 ;
     RECT  214.992 93.631 216.054 93.829 ;
     RECT  54.252 93.479 54.45 93.835 ;
     RECT  55.188 93.245 59.67 93.835 ;
     RECT  102.564 93.533 103.374 93.857 ;
     RECT  50.364 93.515 53.442 93.893 ;
     RECT  60.444 93.515 64.746 93.893 ;
     RECT  86.004 93.451 91.89 93.893 ;
     RECT  7.815 93.821 9.018 93.901 ;
     RECT  82.152 93.091 82.35 93.901 ;
     RECT  112.572 93.785 113.202 93.901 ;
     RECT  118.08 93.785 121.986 93.901 ;
     RECT  122.796 93.485 123.822 93.901 ;
     RECT  135.9 93.749 138.114 93.901 ;
     RECT  139.032 93.451 141.39 93.901 ;
     RECT  152.856 93.749 152.874 93.901 ;
     RECT  156.816 93.821 158.022 93.901 ;
     RECT  158.868 93.749 161.694 93.901 ;
     RECT  169.056 93.533 170.097 93.901 ;
     RECT  185.328 93.325 187.146 93.901 ;
     RECT  206.82 93.485 208.35 93.901 ;
     RECT  110.016 93.749 110.898 93.917 ;
     RECT  16.524 93.659 23.022 93.929 ;
     RECT  60.444 93.893 62.37 93.929 ;
     RECT  88.74 93.893 91.89 93.929 ;
     RECT  131.04 93.785 131.094 93.929 ;
     RECT  135.9 93.901 141.642 93.929 ;
     RECT  172.296 93.293 172.962 93.979 ;
     RECT  127.8 93.533 128.43 93.991 ;
     RECT  129.348 93.749 130.302 93.991 ;
     RECT  169.056 93.901 170.262 93.991 ;
     RECT  171 93.749 171.018 93.991 ;
     RECT  12.636 93.623 13.626 94.019 ;
     RECT  16.524 93.929 21.078 94.019 ;
     RECT  26.532 93.581 27.594 94.019 ;
     RECT  28.548 93.785 32.634 94.019 ;
     RECT  43.776 93.785 44.73 94.019 ;
     RECT  65.592 93.749 71.01 94.019 ;
     RECT  80.388 93.821 80.946 94.019 ;
     RECT  81.792 93.901 82.35 94.019 ;
     RECT  127.8 93.991 130.302 94.019 ;
     RECT  142.524 93.749 143.226 94.019 ;
     RECT  145.08 93.785 145.71 94.019 ;
     RECT  156.816 93.901 161.694 94.019 ;
     RECT  169.056 93.991 171.018 94.019 ;
     RECT  174.42 93.785 176.166 94.019 ;
     RECT  181.836 93.479 184.302 94.019 ;
     RECT  185.328 93.901 187.398 94.019 ;
     RECT  214.992 93.829 216.198 94.019 ;
     RECT  54.252 93.835 59.67 94.027 ;
     RECT  84.924 93.479 85.122 94.027 ;
     RECT  86.004 93.893 87.498 94.027 ;
     RECT  172.296 93.979 173.502 94.027 ;
     RECT  174.42 94.019 176.022 94.027 ;
     RECT  21.96 93.929 23.022 94.055 ;
     RECT  26.532 94.019 26.73 94.055 ;
     RECT  28.548 94.019 32.598 94.055 ;
     RECT  33.768 93.785 37.314 94.055 ;
     RECT  65.592 94.019 70.938 94.055 ;
     RECT  75.204 93.829 79.65 94.055 ;
     RECT  81.792 94.019 82.278 94.055 ;
     RECT  92.772 93.821 98.766 94.055 ;
     RECT  99.615 93.821 101.538 94.055 ;
     RECT  215.172 94.019 216.198 94.055 ;
     RECT  38.16 93.785 43.038 94.061 ;
     RECT  71.784 93.749 74.25 94.135 ;
     RECT  166.572 93.749 166.59 94.135 ;
     RECT  172.296 94.027 176.022 94.135 ;
     RECT  107.496 93.479 108.162 94.171 ;
     RECT  108.9 93.865 109.242 94.171 ;
     RECT  216.036 94.055 216.198 94.171 ;
     RECT  6.624 93.515 6.894 94.219 ;
     RECT  10.08 93.479 11.43 94.289 ;
     RECT  107.496 94.171 109.242 94.289 ;
     RECT  216.036 94.171 216.594 94.397 ;
     RECT  5.076 93.785 5.094 94.405 ;
     RECT  7.815 93.901 9.162 94.405 ;
     RECT  10.08 94.289 10.134 94.405 ;
     RECT  45.615 93.785 49.554 94.405 ;
     RECT  50.364 93.893 52.578 94.405 ;
     RECT  124.668 93.721 127.026 94.405 ;
     RECT  144.18 93.785 144.198 94.405 ;
     RECT  150.768 93.785 151.506 94.405 ;
     RECT  169.056 94.019 170.478 94.405 ;
     RECT  24.015 93.821 24.354 94.531 ;
     RECT  5.94 94.219 6.894 94.559 ;
     RECT  7.815 94.405 10.134 94.559 ;
     RECT  12.672 94.019 13.626 94.559 ;
     RECT  16.524 94.019 17.154 94.559 ;
     RECT  18.072 94.019 21.078 94.559 ;
     RECT  25.632 93.749 25.758 94.559 ;
     RECT  26.712 94.055 26.73 94.559 ;
     RECT  28.692 94.055 32.598 94.559 ;
     RECT  38.196 94.061 43.038 94.559 ;
     RECT  43.776 94.019 44.658 94.559 ;
     RECT  45.615 94.405 52.578 94.559 ;
     RECT  54.252 94.027 59.814 94.559 ;
     RECT  60.732 93.929 62.37 94.559 ;
     RECT  63.144 93.893 64.746 94.559 ;
     RECT  65.592 94.055 70.47 94.559 ;
     RECT  71.784 94.135 74.322 94.559 ;
     RECT  75.204 94.055 78.678 94.559 ;
     RECT  84.924 94.027 87.498 94.559 ;
     RECT  88.74 93.929 91.746 94.559 ;
     RECT  92.772 94.055 96.39 94.559 ;
     RECT  104.364 93.502 106.686 94.559 ;
     RECT  107.496 94.289 109.134 94.559 ;
     RECT  114.012 93.785 117.126 94.559 ;
     RECT  118.08 93.901 123.822 94.559 ;
     RECT  124.56 94.405 127.026 94.559 ;
     RECT  129.528 94.019 130.302 94.559 ;
     RECT  135.036 93.901 135.162 94.559 ;
     RECT  135.9 93.929 139.086 94.559 ;
     RECT  139.896 93.929 141.642 94.559 ;
     RECT  146.52 93.821 148.95 94.559 ;
     RECT  150.588 94.405 151.506 94.559 ;
     RECT  152.244 93.901 152.874 94.559 ;
     RECT  153.615 93.821 155.754 94.559 ;
     RECT  162.468 93.749 163.242 94.559 ;
     RECT  165.6 93.749 165.618 94.559 ;
     RECT  167.328 93.749 168.174 94.559 ;
     RECT  168.948 94.405 170.478 94.559 ;
     RECT  172.188 94.135 176.022 94.559 ;
     RECT  181.836 94.019 184.23 94.559 ;
     RECT  186.015 94.019 187.29 94.559 ;
     RECT  188.28 93.485 188.298 94.559 ;
     RECT  189.036 93.479 190.494 94.559 ;
     RECT  195.12 93.749 195.462 94.559 ;
     RECT  200.484 93.785 200.79 94.559 ;
     RECT  202.104 93.785 205.182 94.559 ;
     RECT  211.5 93.479 213.534 94.559 ;
     RECT  145.08 94.019 145.566 94.567 ;
     RECT  38.196 94.559 41.094 94.595 ;
     RECT  45.615 94.559 49.086 94.595 ;
     RECT  150.588 94.559 150.75 94.603 ;
     RECT  95.22 94.559 96.39 94.631 ;
     RECT  81.792 94.055 81.81 94.675 ;
     RECT  199.188 93.901 199.206 94.675 ;
     RECT  4.932 94.405 5.094 94.711 ;
     RECT  7.815 94.559 8.802 94.711 ;
     RECT  10.872 94.289 11.43 94.711 ;
     RECT  14.652 93.785 15.678 94.711 ;
     RECT  23.328 94.531 24.354 94.711 ;
     RECT  25.704 94.559 25.758 94.711 ;
     RECT  43.776 94.559 44.298 94.711 ;
     RECT  49.932 94.559 52.578 94.711 ;
     RECT  53.424 93.893 53.442 94.711 ;
     RECT  59.616 94.559 59.814 94.711 ;
     RECT  63.144 94.559 63.666 94.711 ;
     RECT  64.476 94.559 64.746 94.711 ;
     RECT  71.784 94.559 73.35 94.711 ;
     RECT  74.124 94.559 74.322 94.711 ;
     RECT  79.416 94.055 79.65 94.711 ;
     RECT  80.388 94.019 80.874 94.711 ;
     RECT  83.34 93.821 84.186 94.711 ;
     RECT  88.74 94.559 89.55 94.711 ;
     RECT  102.564 93.857 102.87 94.711 ;
     RECT  106.488 94.559 106.686 94.711 ;
     RECT  112.464 93.901 113.202 94.711 ;
     RECT  118.08 94.559 118.602 94.711 ;
     RECT  124.56 94.559 125.082 94.711 ;
     RECT  125.892 94.559 127.026 94.711 ;
     RECT  127.8 94.019 128.682 94.711 ;
     RECT  131.076 93.929 131.094 94.711 ;
     RECT  131.832 93.785 134.298 94.711 ;
     RECT  135.9 94.559 136.35 94.711 ;
     RECT  138.78 94.559 139.086 94.711 ;
     RECT  152.784 94.559 152.874 94.711 ;
     RECT  153.615 94.559 155.07 94.711 ;
     RECT  157.572 94.019 161.694 94.711 ;
     RECT  163.044 94.559 163.242 94.711 ;
     RECT  163.98 93.749 164.862 94.711 ;
     RECT  166.464 94.135 166.59 94.711 ;
     RECT  167.868 94.559 168.174 94.711 ;
     RECT  177.156 93.785 178.146 94.711 ;
     RECT  179.388 93.389 179.406 94.711 ;
     RECT  180.288 93.749 181.026 94.711 ;
     RECT  189.036 94.559 189.702 94.711 ;
     RECT  191.376 93.773 193.23 94.711 ;
     RECT  196.815 92.939 198.126 94.711 ;
     RECT  200.484 94.559 200.682 94.711 ;
     RECT  206.82 93.901 208.566 94.711 ;
     RECT  2.415 2.413 2.697 94.787 ;
     RECT  7.272 94.711 8.802 94.787 ;
     RECT  12.672 94.559 13.497 94.787 ;
     RECT  61.236 94.559 62.097 94.787 ;
     RECT  93.564 94.559 94.497 94.787 ;
     RECT  125.892 94.711 128.682 94.787 ;
     RECT  142.524 94.019 143.154 94.787 ;
     RECT  4.68 94.711 5.094 94.829 ;
     RECT  5.94 94.559 6.354 94.829 ;
     RECT  12.672 94.787 13.374 94.829 ;
     RECT  14.364 94.711 15.678 94.829 ;
     RECT  16.524 94.559 16.794 94.829 ;
     RECT  20.88 94.559 21.078 94.829 ;
     RECT  23.328 94.711 24.894 94.829 ;
     RECT  28.692 94.559 31.374 94.829 ;
     RECT  32.112 94.559 32.598 94.829 ;
     RECT  33.768 94.055 35.982 94.829 ;
     RECT  36.72 94.055 37.314 94.829 ;
     RECT  38.556 94.595 41.094 94.829 ;
     RECT  41.832 94.559 42.606 94.829 ;
     RECT  43.452 94.711 44.298 94.829 ;
     RECT  45.615 94.595 47.466 94.829 ;
     RECT  48.312 94.595 49.086 94.829 ;
     RECT  49.932 94.711 53.946 94.829 ;
     RECT  54.756 94.559 57.186 94.829 ;
     RECT  57.996 94.559 58.806 94.829 ;
     RECT  59.616 94.711 60.462 94.829 ;
     RECT  61.236 94.787 61.974 94.829 ;
     RECT  62.856 94.711 63.666 94.829 ;
     RECT  64.476 94.711 65.286 94.829 ;
     RECT  66.096 94.559 68.526 94.829 ;
     RECT  69.264 94.559 70.47 94.829 ;
     RECT  71.712 94.711 73.35 94.829 ;
     RECT  74.124 94.711 75.006 94.829 ;
     RECT  75.744 94.559 75.834 94.829 ;
     RECT  76.608 94.559 78.678 94.829 ;
     RECT  79.416 94.711 80.874 94.829 ;
     RECT  81.684 94.675 81.81 94.829 ;
     RECT  83.052 94.711 84.69 94.829 ;
     RECT  88.704 94.711 89.55 94.829 ;
     RECT  90.324 94.559 91.098 94.829 ;
     RECT  91.944 94.711 91.962 94.829 ;
     RECT  92.7 94.711 92.718 94.829 ;
     RECT  93.564 94.787 94.374 94.829 ;
     RECT  97.128 94.055 98.766 94.829 ;
     RECT  99.615 94.055 101.43 94.829 ;
     RECT  102.42 94.711 102.87 94.829 ;
     RECT  104.04 94.711 104.058 94.829 ;
     RECT  104.868 94.559 105.678 94.829 ;
     RECT  106.488 94.711 107.298 94.829 ;
     RECT  108.072 94.559 108.918 94.829 ;
     RECT  110.415 93.917 110.898 94.829 ;
     RECT  112.14 94.711 113.742 94.829 ;
     RECT  114.516 94.559 116.982 94.829 ;
     RECT  117.792 94.711 118.602 94.829 ;
     RECT  119.412 94.559 120.222 94.829 ;
     RECT  120.996 94.559 121.842 94.829 ;
     RECT  122.616 94.559 123.39 94.829 ;
     RECT  124.272 94.711 125.082 94.829 ;
     RECT  127.476 94.787 128.682 94.829 ;
     RECT  129.528 94.559 129.87 94.829 ;
     RECT  130.716 94.711 134.73 94.829 ;
     RECT  135.576 94.711 136.35 94.829 ;
     RECT  137.196 94.559 137.97 94.829 ;
     RECT  138.78 94.711 139.59 94.829 ;
     RECT  140.4 94.559 141.21 94.829 ;
     RECT  144.972 94.567 145.566 94.829 ;
     RECT  146.52 94.559 148.554 94.829 ;
     RECT  151.776 94.675 151.83 94.829 ;
     RECT  152.784 94.711 155.07 94.829 ;
     RECT  156.816 94.019 156.834 94.829 ;
     RECT  157.572 94.711 162.234 94.829 ;
     RECT  163.044 94.711 165.474 94.829 ;
     RECT  166.248 94.711 167.022 94.829 ;
     RECT  167.868 94.711 168.714 94.829 ;
     RECT  169.488 94.559 170.334 94.829 ;
     RECT  171.864 94.711 171.882 94.829 ;
     RECT  172.728 94.559 173.502 94.829 ;
     RECT  174.348 94.559 174.402 94.829 ;
     RECT  176.94 94.711 178.362 94.829 ;
     RECT  179.208 94.711 181.602 94.829 ;
     RECT  182.412 94.559 183.222 94.829 ;
     RECT  184.032 94.559 184.23 94.829 ;
     RECT  185.184 94.027 185.202 94.829 ;
     RECT  186.015 94.559 186.462 94.829 ;
     RECT  187.272 94.559 187.29 94.829 ;
     RECT  188.1 94.711 188.118 94.829 ;
     RECT  188.892 94.711 189.702 94.829 ;
     RECT  190.512 94.711 190.53 94.829 ;
     RECT  191.268 94.711 193.23 94.829 ;
     RECT  195.336 94.559 195.462 94.829 ;
     RECT  196.815 94.711 198.306 94.829 ;
     RECT  200.16 94.711 200.682 94.829 ;
     RECT  202.104 94.559 202.626 94.829 ;
     RECT  203.4 94.559 204.246 94.829 ;
     RECT  205.056 94.559 205.182 94.829 ;
     RECT  206.64 94.711 208.566 94.829 ;
     RECT  209.88 93.749 210.222 94.829 ;
     RECT  211.536 94.559 213.534 94.829 ;
     RECT  38.664 94.829 41.094 94.865 ;
     RECT  85.5 94.559 87.498 94.865 ;
     RECT  112.14 94.829 113.562 94.865 ;
     RECT  127.512 94.829 128.682 94.865 ;
     RECT  159.84 94.829 162.054 94.865 ;
     RECT  215.172 94.055 215.19 94.865 ;
     RECT  10.872 94.711 11.466 94.901 ;
     RECT  21.96 94.055 22.374 94.901 ;
     RECT  40.032 94.865 41.094 94.901 ;
     RECT  216.036 94.397 216.054 94.901 ;
     RECT  4.716 94.829 5.094 94.945 ;
     RECT  11.196 94.901 11.466 94.945 ;
     RECT  16.524 94.829 16.614 94.945 ;
     RECT  18.072 94.559 19.854 94.945 ;
     RECT  25.704 94.711 25.866 94.945 ;
     RECT  27.468 94.019 27.594 94.945 ;
     RECT  32.184 94.829 32.598 94.945 ;
     RECT  33.804 94.829 35.982 94.945 ;
     RECT  37.044 94.829 37.314 94.945 ;
     RECT  45.615 94.829 45.99 94.945 ;
     RECT  79.416 94.829 79.65 94.945 ;
     RECT  80.676 94.829 80.874 94.945 ;
     RECT  83.052 94.829 84.51 94.945 ;
     RECT  87.12 94.865 87.498 94.945 ;
     RECT  97.128 94.829 97.398 94.945 ;
     RECT  98.424 94.829 98.766 94.945 ;
     RECT  99.615 94.829 100.062 94.945 ;
     RECT  100.8 94.829 101.43 94.945 ;
     RECT  129.528 94.829 129.69 94.945 ;
     RECT  142.524 94.787 142.905 94.945 ;
     RECT  144.108 94.405 144.198 94.945 ;
     RECT  145.296 94.829 145.566 94.945 ;
     RECT  150.192 94.603 150.75 94.945 ;
     RECT  184.068 94.829 184.23 94.945 ;
     RECT  186.015 94.829 186.282 94.945 ;
     RECT  191.268 94.829 192.51 94.945 ;
     RECT  194.112 93.353 194.13 94.945 ;
     RECT  195.372 94.829 195.462 94.945 ;
     RECT  199.08 94.675 199.206 94.945 ;
     RECT  202.104 94.829 202.446 94.945 ;
     RECT  205.092 94.829 205.182 94.945 ;
     RECT  206.712 94.829 208.566 94.945 ;
     RECT  209.916 94.829 210.222 94.945 ;
     RECT  213.015 94.829 213.534 94.945 ;
     RECT  100.8 94.945 102.258 94.973 ;
     RECT  108.072 94.829 108.738 95.009 ;
     RECT  169.524 94.829 170.262 95.009 ;
     RECT  4.716 94.945 5.274 95.021 ;
     RECT  7.272 94.787 7.974 95.021 ;
     RECT  8.784 94.787 8.802 95.021 ;
     RECT  14.4 94.829 14.994 95.021 ;
     RECT  16.02 94.945 16.614 95.021 ;
     RECT  21.744 94.945 21.762 95.021 ;
     RECT  23.364 94.829 24.714 95.021 ;
     RECT  25.704 94.945 26.334 95.021 ;
     RECT  32.184 94.945 32.778 95.021 ;
     RECT  33.804 94.945 36.018 95.021 ;
     RECT  37.044 94.945 37.638 95.021 ;
     RECT  41.868 94.829 42.426 95.021 ;
     RECT  43.488 94.829 44.118 95.021 ;
     RECT  49.968 94.829 52.254 95.021 ;
     RECT  53.208 94.829 53.766 95.021 ;
     RECT  54.792 94.829 55.386 95.021 ;
     RECT  62.892 94.829 63.486 95.021 ;
     RECT  64.512 94.829 65.106 95.021 ;
     RECT  70.956 94.945 71.55 95.021 ;
     RECT  72.576 94.829 73.17 95.021 ;
     RECT  74.196 94.829 74.826 95.021 ;
     RECT  76.608 94.829 76.626 95.021 ;
     RECT  80.676 94.945 81.27 95.021 ;
     RECT  82.26 94.945 84.51 95.021 ;
     RECT  90.36 94.829 90.918 95.021 ;
     RECT  91.98 94.945 92.538 95.021 ;
     RECT  95.22 94.631 95.778 95.021 ;
     RECT  100.8 94.973 100.818 95.021 ;
     RECT  101.664 94.973 102.258 95.021 ;
     RECT  103.284 94.945 103.878 95.021 ;
     RECT  104.904 94.829 105.498 95.021 ;
     RECT  111.348 94.945 111.978 95.021 ;
     RECT  112.968 94.865 113.562 95.021 ;
     RECT  114.588 94.829 116.802 95.021 ;
     RECT  119.448 94.829 120.042 95.021 ;
     RECT  121.068 94.829 121.662 95.021 ;
     RECT  122.688 94.829 123.21 95.021 ;
     RECT  124.272 94.829 124.902 95.021 ;
     RECT  129.132 94.945 129.69 95.021 ;
     RECT  130.752 94.829 132.93 95.021 ;
     RECT  133.992 94.829 134.55 95.021 ;
     RECT  138.816 94.829 139.41 95.021 ;
     RECT  140.436 94.829 141.03 95.021 ;
     RECT  143.676 94.945 144.27 95.021 ;
     RECT  149.508 94.945 150.75 95.021 ;
     RECT  153.072 94.829 154.17 95.021 ;
     RECT  156.132 94.945 156.618 95.021 ;
     RECT  157.644 94.829 159.105 95.021 ;
     RECT  159.84 94.865 160.434 95.021 ;
     RECT  161.46 94.865 162.054 95.021 ;
     RECT  163.08 94.829 163.674 95.021 ;
     RECT  169.524 95.009 170.154 95.021 ;
     RECT  171.144 94.945 171.702 95.021 ;
     RECT  172.764 94.829 173.322 95.021 ;
     RECT  176.94 94.829 178.182 95.021 ;
     RECT  179.244 94.829 179.802 95.021 ;
     RECT  180.615 94.829 181.422 95.021 ;
     RECT  182.448 94.829 183.042 95.021 ;
     RECT  188.928 94.829 189.522 95.021 ;
     RECT  193.788 94.945 194.382 95.021 ;
     RECT  198.612 94.945 199.242 95.021 ;
     RECT  201.852 94.945 202.446 95.021 ;
     RECT  206.712 94.945 208.926 95.021 ;
     RECT  209.916 94.945 210.474 95.021 ;
     RECT  211.536 94.829 212.166 95.021 ;
     RECT  213.015 94.945 213.786 95.021 ;
     RECT  2.415 94.787 2.505 95.057 ;
     RECT  7.815 95.021 7.974 95.057 ;
     RECT  17.64 94.945 19.854 95.057 ;
     RECT  23.364 95.021 24.21 95.057 ;
     RECT  28.944 94.829 31.194 95.057 ;
     RECT  34.815 95.021 35.442 95.057 ;
     RECT  45.108 94.945 45.99 95.057 ;
     RECT  49.968 95.021 51.606 95.057 ;
     RECT  66.132 94.829 68.346 95.057 ;
     RECT  72.576 95.021 72.705 95.057 ;
     RECT  77.436 94.829 78.105 95.057 ;
     RECT  83.415 95.021 83.898 95.057 ;
     RECT  93.6 94.829 94.374 95.057 ;
     RECT  98.424 94.945 100.062 95.057 ;
     RECT  104.904 95.021 105.105 95.057 ;
     RECT  110.415 94.829 110.574 95.057 ;
     RECT  115.815 95.021 116.802 95.057 ;
     RECT  121.068 95.021 121.305 95.057 ;
     RECT  125.892 94.787 126.705 95.057 ;
     RECT  132.015 95.021 132.39 95.057 ;
     RECT  142.056 94.945 142.905 95.057 ;
     RECT  148.215 94.829 148.554 95.057 ;
     RECT  153.072 95.021 153.705 95.057 ;
     RECT  158.22 95.021 159.105 95.057 ;
     RECT  164.415 94.829 165.294 95.057 ;
     RECT  169.524 95.021 169.905 95.057 ;
     RECT  175.176 94.559 176.022 95.057 ;
     RECT  180.615 95.021 180.846 95.057 ;
     RECT  190.548 94.945 192.51 95.057 ;
     RECT  196.815 94.829 197.586 95.057 ;
     RECT  201.852 95.021 202.305 95.057 ;
     RECT  206.712 95.021 208.35 95.057 ;
     RECT  213.015 95.021 213.174 95.057 ;
     RECT  24.12 95.057 24.21 95.135 ;
     RECT  40.032 94.901 40.878 95.135 ;
     RECT  56.196 94.829 57.006 95.135 ;
     RECT  12.78 94.829 13.374 95.165 ;
     RECT  29.988 95.057 31.194 95.165 ;
     RECT  45.972 95.057 45.99 95.165 ;
     RECT  61.272 94.829 61.974 95.165 ;
     RECT  94.356 95.057 94.374 95.165 ;
     RECT  190.548 95.057 191.106 95.165 ;
     RECT  23.364 95.057 23.382 95.213 ;
     RECT  110.556 95.057 110.574 95.213 ;
     RECT  142.056 95.057 142.794 95.213 ;
     RECT  153.072 95.057 153.378 95.213 ;
     RECT  175.176 95.057 175.194 95.213 ;
     RECT  215.784 94.981 215.802 95.789 ;
     RECT  9.576 94.559 10.134 96.365 ;
     RECT  11.196 94.945 11.754 96.365 ;
     RECT  17.64 95.057 18.234 96.365 ;
     RECT  19.26 95.057 19.854 96.365 ;
     RECT  27.324 94.945 27.918 96.365 ;
     RECT  30.564 95.165 31.194 96.365 ;
     RECT  38.664 94.865 39.258 96.365 ;
     RECT  40.248 95.135 40.878 96.365 ;
     RECT  46.728 94.829 47.286 96.365 ;
     RECT  48.348 94.829 48.906 96.365 ;
     RECT  49.968 95.057 50.598 96.365 ;
     RECT  56.412 95.135 57.006 96.365 ;
     RECT  58.032 94.829 58.626 96.365 ;
     RECT  59.652 94.829 60.246 96.365 ;
     RECT  66.132 95.057 66.69 96.365 ;
     RECT  67.752 95.057 68.346 96.365 ;
     RECT  69.336 94.829 69.966 96.365 ;
     RECT  77.436 95.057 77.994 96.365 ;
     RECT  79.056 94.945 79.65 96.365 ;
     RECT  85.5 94.865 86.058 96.365 ;
     RECT  87.12 94.945 87.75 96.365 ;
     RECT  88.74 94.829 89.37 96.365 ;
     RECT  96.804 94.945 97.398 96.365 ;
     RECT  98.424 95.057 99.018 96.365 ;
     RECT  116.208 95.057 116.802 96.365 ;
     RECT  117.828 94.829 118.422 96.365 ;
     RECT  125.892 95.057 126.306 96.365 ;
     RECT  127.512 94.865 128.07 96.365 ;
     RECT  135.612 94.829 136.17 96.365 ;
     RECT  137.232 94.829 137.79 96.365 ;
     RECT  145.296 94.945 145.89 96.365 ;
     RECT  146.916 94.829 147.474 96.365 ;
     RECT  158.22 95.057 158.814 96.365 ;
     RECT  164.7 95.057 165.294 96.365 ;
     RECT  166.32 94.829 166.842 96.365 ;
     RECT  167.904 94.829 168.534 96.365 ;
     RECT  177.624 95.021 178.182 96.365 ;
     RECT  184.068 94.945 184.662 96.365 ;
     RECT  185.688 94.945 186.282 96.365 ;
     RECT  187.308 94.945 187.902 96.365 ;
     RECT  192.168 95.057 192.51 96.365 ;
     RECT  195.372 94.945 195.966 96.365 ;
     RECT  196.992 95.057 197.586 96.365 ;
     RECT  200.232 94.829 200.538 96.365 ;
     RECT  203.472 94.829 204.066 96.365 ;
     RECT  205.092 94.945 205.686 96.365 ;
     RECT  206.712 95.057 207.306 96.365 ;
     RECT  106.524 94.829 107.118 96.413 ;
     RECT  108.144 95.009 108.738 96.413 ;
     RECT  150.192 95.021 150.21 97.033 ;
     RECT  4.716 95.021 4.734 97.068 ;
     RECT  6.336 94.829 6.354 97.068 ;
     RECT  7.956 95.057 7.974 97.068 ;
     RECT  9.576 96.365 9.594 97.068 ;
     RECT  11.196 96.365 11.214 97.068 ;
     RECT  12.78 95.165 12.798 97.068 ;
     RECT  14.4 95.021 14.418 97.068 ;
     RECT  16.02 95.021 16.038 97.068 ;
     RECT  17.64 96.365 17.658 97.068 ;
     RECT  19.26 96.365 19.278 97.068 ;
     RECT  20.88 94.829 20.898 97.068 ;
     RECT  22.5 94.945 22.518 97.068 ;
     RECT  24.12 95.135 24.138 97.068 ;
     RECT  25.704 95.021 25.722 97.068 ;
     RECT  27.324 96.365 27.342 97.068 ;
     RECT  28.944 95.057 28.962 97.068 ;
     RECT  30.564 96.365 30.582 97.068 ;
     RECT  32.184 95.021 32.202 97.068 ;
     RECT  33.804 95.021 33.822 97.068 ;
     RECT  35.424 95.057 35.442 97.068 ;
     RECT  37.044 95.021 37.062 97.068 ;
     RECT  38.664 96.365 38.682 97.068 ;
     RECT  40.248 96.365 40.266 97.068 ;
     RECT  41.868 95.021 41.886 97.068 ;
     RECT  43.488 95.021 43.506 97.068 ;
     RECT  45.108 95.057 45.126 97.068 ;
     RECT  46.728 96.365 46.746 97.068 ;
     RECT  48.348 96.365 48.366 97.068 ;
     RECT  49.968 96.365 49.986 97.068 ;
     RECT  51.588 95.057 51.606 97.068 ;
     RECT  53.208 95.021 53.226 97.068 ;
     RECT  54.792 95.021 54.81 97.068 ;
     RECT  56.412 96.365 56.43 97.068 ;
     RECT  58.032 96.365 58.05 97.068 ;
     RECT  59.652 96.365 59.67 97.068 ;
     RECT  61.272 95.165 61.29 97.068 ;
     RECT  62.892 95.021 62.91 97.068 ;
     RECT  64.512 95.021 64.53 97.068 ;
     RECT  66.132 96.365 66.15 97.068 ;
     RECT  67.752 96.365 67.77 97.068 ;
     RECT  69.336 96.365 69.354 97.068 ;
     RECT  70.956 95.021 70.974 97.068 ;
     RECT  72.576 95.057 72.594 97.068 ;
     RECT  74.196 95.021 74.214 97.068 ;
     RECT  75.816 94.829 75.834 97.068 ;
     RECT  77.436 96.365 77.454 97.068 ;
     RECT  79.056 96.365 79.074 97.068 ;
     RECT  80.676 95.021 80.694 97.068 ;
     RECT  82.26 95.021 82.278 97.068 ;
     RECT  83.88 95.057 83.898 97.068 ;
     RECT  85.5 96.365 85.518 97.068 ;
     RECT  87.12 96.365 87.138 97.068 ;
     RECT  88.74 96.365 88.758 97.068 ;
     RECT  90.36 95.021 90.378 97.068 ;
     RECT  91.98 95.021 91.998 97.068 ;
     RECT  93.6 95.057 93.618 97.068 ;
     RECT  95.22 95.021 95.238 97.068 ;
     RECT  96.804 96.365 96.822 97.068 ;
     RECT  98.424 96.365 98.442 97.068 ;
     RECT  100.044 95.057 100.062 97.068 ;
     RECT  101.664 95.021 101.682 97.068 ;
     RECT  103.284 95.021 103.302 97.068 ;
     RECT  104.904 95.057 104.922 97.068 ;
     RECT  106.524 96.413 106.542 97.068 ;
     RECT  108.144 96.413 108.162 97.068 ;
     RECT  109.764 96.331 109.782 97.068 ;
     RECT  111.348 95.021 111.366 97.068 ;
     RECT  112.968 95.021 112.986 97.068 ;
     RECT  114.588 95.021 114.606 97.068 ;
     RECT  116.208 96.365 116.226 97.068 ;
     RECT  117.828 96.365 117.846 97.068 ;
     RECT  119.448 95.021 119.466 97.068 ;
     RECT  121.068 95.057 121.086 97.068 ;
     RECT  122.688 95.021 122.706 97.068 ;
     RECT  124.272 95.021 124.29 97.068 ;
     RECT  125.892 96.365 125.91 97.068 ;
     RECT  127.512 96.365 127.53 97.068 ;
     RECT  129.132 95.021 129.15 97.068 ;
     RECT  130.752 95.021 130.77 97.068 ;
     RECT  132.372 95.057 132.39 97.068 ;
     RECT  133.992 95.021 134.01 97.068 ;
     RECT  135.612 96.365 135.63 97.068 ;
     RECT  137.232 96.365 137.25 97.068 ;
     RECT  138.816 95.021 138.834 97.068 ;
     RECT  140.436 95.021 140.454 97.068 ;
     RECT  142.056 95.213 142.074 97.068 ;
     RECT  143.676 95.021 143.694 97.068 ;
     RECT  145.296 96.365 145.314 97.068 ;
     RECT  146.916 96.365 146.934 97.068 ;
     RECT  148.536 95.057 148.554 97.068 ;
     RECT  150.156 97.033 150.282 97.068 ;
     RECT  151.776 94.829 151.794 97.068 ;
     RECT  153.36 95.213 153.378 97.068 ;
     RECT  154.98 94.829 154.998 97.068 ;
     RECT  156.6 95.021 156.618 97.068 ;
     RECT  158.22 96.365 158.238 97.068 ;
     RECT  159.84 95.021 159.858 97.068 ;
     RECT  161.46 95.021 161.478 97.068 ;
     RECT  163.08 95.021 163.098 97.068 ;
     RECT  164.7 96.365 164.718 97.068 ;
     RECT  166.32 96.365 166.338 97.068 ;
     RECT  167.904 96.365 167.922 97.068 ;
     RECT  169.524 95.057 169.542 97.068 ;
     RECT  171.144 95.021 171.162 97.068 ;
     RECT  172.764 95.021 172.782 97.068 ;
     RECT  174.384 94.829 174.402 97.068 ;
     RECT  176.004 95.057 176.022 97.068 ;
     RECT  177.624 96.365 177.642 97.068 ;
     RECT  179.244 95.021 179.262 97.068 ;
     RECT  180.828 95.057 180.846 97.068 ;
     RECT  182.448 95.021 182.466 97.068 ;
     RECT  184.068 96.365 184.086 97.068 ;
     RECT  185.688 96.365 185.706 97.068 ;
     RECT  187.308 96.365 187.326 97.068 ;
     RECT  188.928 95.021 188.946 97.068 ;
     RECT  190.548 95.165 190.566 97.068 ;
     RECT  192.168 96.365 192.186 97.068 ;
     RECT  193.788 95.021 193.806 97.068 ;
     RECT  195.372 96.365 195.39 97.068 ;
     RECT  196.992 96.365 197.01 97.068 ;
     RECT  198.612 95.021 198.63 97.068 ;
     RECT  200.232 96.365 200.25 97.068 ;
     RECT  201.852 95.057 201.87 97.068 ;
     RECT  203.472 96.365 203.49 97.068 ;
     RECT  205.092 96.365 205.11 97.068 ;
     RECT  206.712 96.365 206.73 97.068 ;
     RECT  208.332 95.057 208.35 97.068 ;
     RECT  209.916 95.021 209.934 97.068 ;
     RECT  211.536 95.021 211.554 97.068 ;
     RECT  213.156 95.057 213.174 97.068 ;
     RECT  214.776 94.981 214.794 97.068 ;
     RECT  150.192 97.068 150.282 97.133 ;
    LAYER M4 ;
     RECT  2.408 2.148 2.512 95.052 ;
     RECT  2.512 2.418 2.704 94.782 ;
     RECT  5.245 94.992 5.555 95.016 ;
     RECT  5.525 0.576 5.609 0.6 ;
     RECT  5.9 94.224 5.987 94.248 ;
     RECT  4.741 93.12 6.433 93.144 ;
     RECT  6.433 93.12 6.473 93.24 ;
     RECT  6.473 93.216 6.565 93.24 ;
     RECT  6.524 47.232 6.611 47.256 ;
     RECT  5.065 3.552 6.721 3.576 ;
     RECT  6.565 93.216 6.725 93.432 ;
     RECT  6.721 3.552 6.761 3.72 ;
     RECT  6.716 46.752 6.803 46.776 ;
     RECT  7.189 1.152 7.481 1.176 ;
     RECT  6.761 3.696 7.513 3.72 ;
     RECT  6.725 93.216 7.729 93.24 ;
     RECT  7.513 3.696 7.808 3.96 ;
     RECT  6.757 42 7.808 42.024 ;
     RECT  7.729 93.216 7.808 93.816 ;
     RECT  7.141 94.992 7.808 95.016 ;
     RECT  7.808 2.148 7.912 95.052 ;
     RECT  7.912 2.418 8.104 95.016 ;
     RECT  8.104 93.216 8.561 93.816 ;
     RECT  8.104 3.36 8.668 4.728 ;
     RECT  8.104 94.992 8.813 95.016 ;
     RECT  8.821 0.576 8.993 0.6 ;
     RECT  8.668 3.936 9.817 4.728 ;
     RECT  10.105 96.336 10.403 96.36 ;
     RECT  10.501 0.192 10.585 0.216 ;
     RECT  9.817 3.792 10.937 4.728 ;
     RECT  8.561 93.456 11.149 93.816 ;
     RECT  11.725 96.336 12.035 96.36 ;
     RECT  12.133 1.152 12.593 1.176 ;
     RECT  10.937 3.936 13.208 4.728 ;
     RECT  8.104 42 13.208 42.024 ;
     RECT  11.149 93.072 13.208 93.816 ;
     RECT  13.208 2.148 13.312 95.052 ;
     RECT  13.312 2.418 13.345 95.052 ;
     RECT  13.345 2.418 13.504 95.16 ;
     RECT  13.504 3.936 13.601 4.728 ;
     RECT  13.504 95.136 13.619 95.16 ;
     RECT  13.601 3.936 14.357 4.584 ;
     RECT  13.813 1.152 14.429 1.176 ;
     RECT  13.504 93.312 14.497 93.48 ;
     RECT  14.357 4.08 14.861 4.584 ;
     RECT  14.497 93.072 14.897 93.48 ;
     RECT  14.965 94.992 15.251 95.016 ;
     RECT  15.445 1.152 16.049 1.176 ;
     RECT  14.861 4.08 16.441 4.392 ;
     RECT  14.897 93.456 16.441 93.48 ;
     RECT  16.585 94.992 16.883 95.016 ;
     RECT  16.441 93.072 16.945 93.48 ;
     RECT  17.125 0.192 17.417 0.216 ;
     RECT  16.945 92.304 17.917 93.48 ;
     RECT  18.205 96.336 18.467 96.36 ;
     RECT  16.441 3.696 18.608 4.392 ;
     RECT  13.504 42 18.608 42.024 ;
     RECT  17.917 92.304 18.608 93.864 ;
     RECT  18.608 2.148 18.712 95.052 ;
     RECT  18.753 1.152 18.864 1.176 ;
     RECT  18.712 2.418 18.904 94.782 ;
     RECT  18.904 92.4 19.001 93.864 ;
     RECT  19.001 93.264 19.469 93.864 ;
     RECT  19.825 96.336 20.099 96.36 ;
     RECT  20.437 0.192 20.521 0.216 ;
     RECT  19.469 93.264 20.905 93.48 ;
     RECT  21.685 94.992 21.773 95.016 ;
     RECT  18.904 3.984 21.877 4.392 ;
     RECT  22.069 0.192 22.205 0.216 ;
     RECT  20.977 9.216 22.508 9.24 ;
     RECT  22.508 9.168 22.595 9.24 ;
     RECT  20.905 92.304 22.817 93.48 ;
     RECT  22.817 92.928 22.925 93.48 ;
     RECT  21.877 3.6 23.281 4.44 ;
     RECT  23.269 95.184 23.393 95.208 ;
     RECT  23.281 3.408 24.008 4.44 ;
     RECT  22.595 9.216 24.008 9.24 ;
     RECT  22.549 12.768 24.008 12.792 ;
     RECT  18.904 42 24.008 42.024 ;
     RECT  22.925 92.928 24.008 93.384 ;
     RECT  24.008 2.148 24.112 95.052 ;
     RECT  24.112 2.418 24.304 95.016 ;
     RECT  24.304 94.992 24.947 95.016 ;
     RECT  24.304 91.728 25.445 91.752 ;
     RECT  24.304 93.168 25.445 93.384 ;
     RECT  23.749 1.152 25.985 1.176 ;
     RECT  25.445 93.36 26.521 93.384 ;
     RECT  26.305 94.992 26.579 95.016 ;
     RECT  26.305 92.256 26.669 92.28 ;
     RECT  24.304 3.984 26.741 4.44 ;
     RECT  24.304 9.216 26.773 9.24 ;
     RECT  26.773 9.216 26.813 9.336 ;
     RECT  24.304 12.768 26.993 12.792 ;
     RECT  26.981 0.576 27.065 0.6 ;
     RECT  26.741 4.128 27.347 4.44 ;
     RECT  27.301 12.912 27.388 12.936 ;
     RECT  26.521 93.36 27.493 93.48 ;
     RECT  27.493 92.64 27.781 93.48 ;
     RECT  27.347 4.128 27.965 4.152 ;
     RECT  27.889 96.336 28.163 96.36 ;
     RECT  27.301 16.8 28.213 16.824 ;
     RECT  27.781 92.64 28.213 93.528 ;
     RECT  26.917 91.632 28.289 91.656 ;
     RECT  28.213 92.64 28.885 93.576 ;
     RECT  28.693 0.192 28.901 0.216 ;
     RECT  28.285 4.08 29.257 4.104 ;
     RECT  29.257 4.08 29.408 4.536 ;
     RECT  26.813 9.312 29.408 9.336 ;
     RECT  28.213 10.704 29.408 10.728 ;
     RECT  28.213 16.368 29.408 16.824 ;
     RECT  24.304 42 29.408 42.024 ;
     RECT  28.885 92.448 29.408 93.576 ;
     RECT  29.408 2.148 29.512 95.052 ;
     RECT  29.512 2.418 29.704 95.052 ;
     RECT  29.704 10.704 29.845 10.824 ;
     RECT  29.704 9.312 29.891 9.336 ;
     RECT  29.845 10.704 29.939 10.728 ;
     RECT  29.704 16.368 29.98 17.064 ;
     RECT  29.98 16.368 29.981 16.632 ;
     RECT  29.749 95.136 30.017 95.16 ;
     RECT  29.704 28.464 30.083 29.208 ;
     RECT  29.704 31.92 30.083 31.944 ;
     RECT  30.325 0.192 30.737 0.216 ;
     RECT  29.704 91.2 30.737 93.768 ;
     RECT  29.981 16.368 30.809 16.536 ;
     RECT  29.704 30.816 30.949 30.84 ;
     RECT  30.949 30.384 31.052 30.84 ;
     RECT  31.052 27.552 31.129 27.576 ;
     RECT  30.083 28.56 31.129 29.208 ;
     RECT  29.704 4.512 31.139 4.536 ;
     RECT  31.052 30.384 31.139 31.368 ;
     RECT  31.129 27.552 31.18 29.208 ;
     RECT  31.139 30.384 31.18 30.6 ;
     RECT  31.18 30.384 31.333 30.408 ;
     RECT  31.165 96.336 31.427 96.36 ;
     RECT  31.18 27.552 31.429 27.912 ;
     RECT  31.333 29.616 31.457 30.408 ;
     RECT  31.457 29.616 31.485 29.64 ;
     RECT  30.737 91.2 31.493 93.48 ;
     RECT  29.704 23.376 31.561 23.832 ;
     RECT  31.429 27.216 31.765 27.912 ;
     RECT  31.765 26.736 31.817 27.912 ;
     RECT  31.817 26.736 31.852 26.856 ;
     RECT  31.237 31.68 31.957 31.944 ;
     RECT  31.201 3.216 32.101 3.24 ;
     RECT  31.561 23.328 32.101 23.832 ;
     RECT  32.005 0.192 32.141 0.216 ;
     RECT  32.101 3.216 32.147 3.72 ;
     RECT  32.147 3.696 32.188 3.72 ;
     RECT  32.101 22.656 32.188 23.832 ;
     RECT  31.727 25.68 32.195 25.704 ;
     RECT  32.188 22.752 32.221 23.832 ;
     RECT  32.221 23.328 32.461 23.832 ;
     RECT  31.852 26.832 32.573 26.856 ;
     RECT  32.173 55.824 32.641 55.848 ;
     RECT  32.569 30.672 32.749 30.696 ;
     RECT  31.957 31.68 32.749 32.328 ;
     RECT  32.497 54.144 32.749 54.168 ;
     RECT  32.641 55.296 32.749 55.848 ;
     RECT  32.461 23.328 32.773 23.88 ;
     RECT  32.749 54.144 32.789 55.848 ;
     RECT  32.773 23.328 32.819 25.128 ;
     RECT  32.677 29.568 32.821 29.592 ;
     RECT  32.749 30.672 32.821 32.328 ;
     RECT  32.819 23.808 32.86 25.128 ;
     RECT  31.493 91.92 32.867 93.48 ;
     RECT  32.389 27.984 32.893 28.008 ;
     RECT  32.749 94.992 33.011 95.016 ;
     RECT  32.86 24.864 33.473 25.128 ;
     RECT  33.505 3.936 33.589 3.96 ;
     RECT  32.867 92.352 33.637 93.48 ;
     RECT  33.637 92.352 33.683 93.768 ;
     RECT  32.893 27.984 33.685 28.44 ;
     RECT  33.637 0.192 33.725 0.216 ;
     RECT  32.821 29.568 33.725 32.328 ;
     RECT  33.685 27.744 33.772 28.44 ;
     RECT  33.473 25.104 33.797 25.128 ;
     RECT  33.685 26.736 33.797 26.76 ;
     RECT  33.772 27.984 34.153 28.44 ;
     RECT  33.725 29.568 34.153 30.12 ;
     RECT  30.809 16.512 34.765 16.536 ;
     RECT  33.683 92.352 34.765 92.76 ;
     RECT  33.683 93.744 34.765 93.768 ;
     RECT  34.765 16.368 34.808 16.536 ;
     RECT  32.86 23.808 34.808 23.88 ;
     RECT  34.153 27.984 34.808 30.12 ;
     RECT  33.725 31.104 34.808 32.328 ;
     RECT  29.704 42 34.808 42.024 ;
     RECT  32.789 54.432 34.808 55.848 ;
     RECT  34.765 92.352 34.808 93.768 ;
     RECT  34.477 94.992 34.808 95.016 ;
     RECT  34.808 2.148 34.912 95.052 ;
     RECT  34.912 2.418 35.104 94.782 ;
     RECT  35.104 3.936 35.219 4.536 ;
     RECT  35.104 31.104 35.219 32.76 ;
     RECT  35.104 26.208 35.245 26.568 ;
     RECT  35.104 92.4 35.363 94.782 ;
     RECT  35.104 27.6 35.381 30.12 ;
     RECT  35.317 0.192 35.561 0.216 ;
     RECT  35.219 31.2 35.993 32.04 ;
     RECT  35.989 94.992 36.275 95.016 ;
     RECT  35.104 23.856 36.313 23.88 ;
     RECT  35.363 92.4 36.313 93.768 ;
     RECT  35.381 28.416 36.461 30.12 ;
     RECT  36.461 29.232 36.533 30.12 ;
     RECT  35.219 3.936 36.659 3.96 ;
     RECT  36.613 22.224 36.812 22.248 ;
     RECT  36.313 23.328 36.812 23.88 ;
     RECT  35.245 26.496 36.815 26.568 ;
     RECT  36.812 22.224 36.899 23.88 ;
     RECT  36.533 29.328 36.961 30.12 ;
     RECT  35.993 31.2 36.961 31.368 ;
     RECT  36.853 27.888 36.995 27.912 ;
     RECT  36.961 29.328 37.069 31.368 ;
     RECT  37.004 4.272 37.091 4.296 ;
     RECT  36.313 91.728 37.141 93.768 ;
     RECT  35.104 54.336 37.321 56.04 ;
     RECT  37.069 29.328 37.669 31.944 ;
     RECT  37.141 91.488 37.685 93.768 ;
     RECT  37.669 29.088 37.717 32.04 ;
     RECT  36.949 1.728 37.721 1.752 ;
     RECT  37.669 49.152 37.753 49.176 ;
     RECT  36.899 23.328 37.793 23.88 ;
     RECT  37.717 28.464 37.811 32.04 ;
     RECT  37.609 94.992 37.859 95.016 ;
     RECT  37.811 28.464 37.901 31.416 ;
     RECT  36.815 25.872 37.933 26.568 ;
     RECT  37.933 25.68 38.041 26.568 ;
     RECT  35.104 16.368 38.051 16.392 ;
     RECT  37.628 20.736 38.051 20.76 ;
     RECT  37.825 77.52 38.147 77.544 ;
     RECT  37.685 91.872 38.149 93.768 ;
     RECT  37.753 49.152 38.181 49.224 ;
     RECT  38.005 24.096 38.245 24.12 ;
     RECT  38.041 25.68 38.291 26.76 ;
     RECT  38.291 26.544 38.437 26.76 ;
     RECT  38.245 24.096 38.531 24.36 ;
     RECT  38.437 26.544 38.723 27.336 ;
     RECT  37.901 29.424 38.723 31.416 ;
     RECT  38.725 25.344 38.761 25.368 ;
     RECT  38.723 26.544 38.771 26.76 ;
     RECT  38.723 29.52 38.801 31.416 ;
     RECT  38.617 32.4 38.801 32.568 ;
     RECT  38.761 25.104 38.812 25.368 ;
     RECT  38.629 1.152 38.837 1.176 ;
     RECT  38.812 25.104 38.845 25.128 ;
     RECT  38.401 3.936 39.059 3.96 ;
     RECT  38.473 22.752 39.059 22.776 ;
     RECT  37.321 54.336 39.157 56.28 ;
     RECT  39.229 96.336 39.491 96.36 ;
     RECT  39.301 28.416 39.517 28.44 ;
     RECT  39.157 54.336 39.625 56.376 ;
     RECT  39.625 54.192 39.769 56.376 ;
     RECT  38.771 26.544 39.841 26.568 ;
     RECT  38.801 29.52 39.877 31.32 ;
     RECT  38.801 32.544 39.877 32.568 ;
     RECT  39.841 26.544 40.028 27.096 ;
     RECT  40.028 26.448 40.069 27.096 ;
     RECT  39.517 28.416 40.069 28.488 ;
     RECT  39.877 29.52 40.069 32.568 ;
     RECT  39.265 3.36 40.208 3.384 ;
     RECT  40.069 4.512 40.208 4.536 ;
     RECT  40.049 22.176 40.208 22.2 ;
     RECT  38.531 24.096 40.208 24.12 ;
     RECT  40.069 25.584 40.208 27.096 ;
     RECT  40.069 28.416 40.208 32.568 ;
     RECT  35.104 42 40.208 42.024 ;
     RECT  38.181 49.2 40.208 49.224 ;
     RECT  39.769 54.144 40.208 56.376 ;
     RECT  39.397 61.152 40.208 61.176 ;
     RECT  39.356 77.76 40.208 77.784 ;
     RECT  38.149 91.872 40.208 94.056 ;
     RECT  40.208 2.148 40.312 95.052 ;
     RECT  40.312 2.418 40.504 94.782 ;
     RECT  40.261 1.152 40.637 1.176 ;
     RECT  40.504 91.872 40.817 94.056 ;
     RECT  40.504 53.568 40.925 56.664 ;
     RECT  40.849 96.336 41.123 96.36 ;
     RECT  40.504 26.496 41.177 27.24 ;
     RECT  40.504 28.464 41.497 32.28 ;
     RECT  40.504 22.656 41.557 22.68 ;
     RECT  41.177 26.496 41.557 26.904 ;
     RECT  41.557 25.68 41.603 26.904 ;
     RECT  41.557 21.888 41.644 22.68 ;
     RECT  41.603 25.68 41.644 26.568 ;
     RECT  40.925 54.048 41.749 56.664 ;
     RECT  40.504 3.696 41.753 3.72 ;
     RECT  41.941 1.152 42.257 1.176 ;
     RECT  40.817 91.872 42.289 93.768 ;
     RECT  40.504 24.096 42.433 24.12 ;
     RECT  41.497 27.984 42.649 32.28 ;
     RECT  42.397 94.992 42.707 95.016 ;
     RECT  41.644 26.544 42.709 26.568 ;
     RECT  42.709 26.16 42.757 26.568 ;
     RECT  42.289 91.728 42.757 93.768 ;
     RECT  42.433 24.096 42.793 24.84 ;
     RECT  42.757 25.968 42.793 26.568 ;
     RECT  42.793 24.096 42.829 26.568 ;
     RECT  42.649 27.84 42.829 32.28 ;
     RECT  42.829 24.096 42.941 32.28 ;
     RECT  42.757 91.68 43.337 93.768 ;
     RECT  41.644 22.656 43.619 22.68 ;
     RECT  42.941 25.296 43.657 32.28 ;
     RECT  42.865 52.992 43.693 53.016 ;
     RECT  41.749 54.048 43.693 56.76 ;
     RECT  43.573 0.192 43.805 0.216 ;
     RECT  43.337 91.728 43.913 93.768 ;
     RECT  40.504 61.056 44.021 61.08 ;
     RECT  42.941 24.096 44.06 24.312 ;
     RECT  43.657 25.296 44.06 32.52 ;
     RECT  44.089 3.936 44.173 3.96 ;
     RECT  44.089 94.992 44.339 95.016 ;
     RECT  44.06 24.096 44.483 32.52 ;
     RECT  43.693 52.992 44.917 56.76 ;
     RECT  45.205 0.192 45.389 0.216 ;
     RECT  45.493 3.312 45.608 3.336 ;
     RECT  44.845 4.512 45.608 4.536 ;
     RECT  44.483 24.096 45.608 25.704 ;
     RECT  44.483 26.88 45.608 32.52 ;
     RECT  40.504 42 45.608 42.024 ;
     RECT  40.504 49.2 45.608 49.224 ;
     RECT  44.917 52.992 45.608 57.576 ;
     RECT  45.452 61.008 45.608 61.032 ;
     RECT  43.913 92.112 45.608 93.768 ;
     RECT  45.608 2.148 45.712 95.052 ;
     RECT  45.712 2.418 45.904 95.052 ;
     RECT  45.904 94.32 45.925 95.052 ;
     RECT  45.925 94.32 46.012 95.16 ;
     RECT  45.904 3.312 46.019 3.96 ;
     RECT  45.904 25.968 46.307 25.992 ;
     RECT  45.904 92.4 46.433 93.048 ;
     RECT  45.904 27.36 46.649 32.52 ;
     RECT  46.433 92.4 46.793 92.712 ;
     RECT  45.904 23.232 46.885 24.168 ;
     RECT  45.904 52.752 47.045 57.336 ;
     RECT  46.885 23.232 47.081 25.128 ;
     RECT  46.649 27.36 47.125 32.28 ;
     RECT  47.125 26.928 47.261 32.28 ;
     RECT  47.18 4.512 47.267 4.536 ;
     RECT  46.885 19.344 47.329 19.368 ;
     RECT  46.885 1.152 47.333 1.176 ;
     RECT  47.081 23.232 47.365 24.888 ;
     RECT  47.329 19.344 47.413 19.944 ;
     RECT  47.365 22.8 47.441 24.888 ;
     RECT  47.441 24.864 47.513 24.888 ;
     RECT  47.257 96.336 47.555 96.36 ;
     RECT  47.441 22.8 47.621 23.832 ;
     RECT  47.413 19.344 47.657 19.368 ;
     RECT  46.793 92.496 48.157 92.712 ;
     RECT  47.261 27.648 48.373 32.28 ;
     RECT  48.157 91.728 48.373 92.712 ;
     RECT  48.373 27.648 48.421 32.76 ;
     RECT  48.421 26.736 48.46 32.76 ;
     RECT  48.373 91.728 48.467 93.192 ;
     RECT  47.045 52.848 49.165 57.336 ;
     RECT  48.877 96.336 49.187 96.36 ;
     RECT  49.165 52.848 49.201 57.672 ;
     RECT  49.165 3.936 49.249 3.96 ;
     RECT  48.46 26.736 49.273 32.328 ;
     RECT  48.517 1.152 49.277 1.176 ;
     RECT  48.467 92.4 49.457 92.712 ;
     RECT  49.201 52.848 49.529 58.152 ;
     RECT  47.621 23.328 49.741 23.832 ;
     RECT  49.741 23.328 49.781 23.928 ;
     RECT  49.273 26.208 49.813 32.328 ;
     RECT  49.457 92.4 50.029 92.52 ;
     RECT  49.781 23.904 50.053 23.928 ;
     RECT  49.813 26.208 50.101 33.096 ;
     RECT  50.197 0.192 50.393 0.216 ;
     RECT  50.06 4.512 50.641 4.536 ;
     RECT  50.053 23.904 50.713 24.648 ;
     RECT  50.569 96.336 50.819 96.36 ;
     RECT  50.641 3.84 51.008 4.536 ;
     RECT  50.713 23.904 51.008 24.744 ;
     RECT  50.101 25.824 51.008 33.096 ;
     RECT  45.904 42 51.008 42.024 ;
     RECT  45.904 49.2 51.008 49.224 ;
     RECT  49.529 52.848 51.008 57.912 ;
     RECT  50.029 92.208 51.008 92.52 ;
     RECT  46.012 94.32 51.008 94.344 ;
     RECT  51.008 2.148 51.112 95.052 ;
     RECT  51.112 2.148 51.304 94.782 ;
     RECT  51.304 26.256 51.473 32.856 ;
     RECT  51.473 26.256 51.923 26.28 ;
     RECT  51.304 23.808 51.964 25.08 ;
     RECT  51.304 92.496 52.019 94.782 ;
     RECT  51.473 27.6 52.333 32.856 ;
     RECT  52.225 94.992 52.403 95.016 ;
     RECT  52.333 27.6 52.405 32.904 ;
     RECT  52.019 92.496 52.405 93.528 ;
     RECT  52.405 92.016 52.412 93.528 ;
     RECT  52.405 4.512 52.489 4.536 ;
     RECT  52.412 91.152 52.499 93.528 ;
     RECT  51.964 23.808 52.553 24.648 ;
     RECT  51.304 42 52.621 42.024 ;
     RECT  52.405 27.6 52.645 33.576 ;
     RECT  51.829 1.728 52.661 1.752 ;
     RECT  52.621 41.616 52.705 42.024 ;
     RECT  52.553 24.624 52.841 24.648 ;
     RECT  52.499 92.016 53.057 93.528 ;
     RECT  53.057 92.016 53.417 93.432 ;
     RECT  51.304 52.848 53.449 58.152 ;
     RECT  53.509 1.152 53.813 1.176 ;
     RECT  52.645 27.6 53.845 33.912 ;
     RECT  53.804 39.552 53.891 39.576 ;
     RECT  53.737 94.992 54.035 95.016 ;
     RECT  53.417 92.928 54.065 93.432 ;
     RECT  53.845 27.6 54.209 34.152 ;
     RECT  52.705 42 54.371 42.024 ;
     RECT  54.133 23.232 54.38 23.256 ;
     RECT  54.325 39.6 54.412 39.624 ;
     RECT  54.097 4.512 54.467 4.536 ;
     RECT  54.38 23.232 54.467 23.736 ;
     RECT  54.493 45.504 54.529 45.528 ;
     RECT  54.133 46.56 54.529 46.584 ;
     RECT  54.467 23.232 54.749 23.352 ;
     RECT  54.065 93.12 54.889 93.432 ;
     RECT  53.449 52.848 55.141 58.296 ;
     RECT  54.889 93.12 55.177 93.864 ;
     RECT  55.177 38.832 55.213 39.048 ;
     RECT  53.804 40.656 55.213 40.68 ;
     RECT  54.209 27.6 55.321 33.624 ;
     RECT  55.069 35.472 55.321 35.496 ;
     RECT  55.093 3.744 55.325 3.768 ;
     RECT  55.141 24.48 55.357 24.504 ;
     RECT  55.213 38.496 55.393 39.048 ;
     RECT  55.393 37.584 55.429 39.048 ;
     RECT  55.321 27.6 55.501 33.768 ;
     RECT  55.321 35.472 55.501 36.024 ;
     RECT  55.141 1.152 55.541 1.176 ;
     RECT  55.177 92.304 55.573 93.864 ;
     RECT  55.501 27.6 55.609 36.024 ;
     RECT  55.429 37.056 55.609 39.048 ;
     RECT  55.357 24.48 55.645 25.032 ;
     RECT  55.429 43.632 55.645 43.656 ;
     RECT  55.609 27.6 55.681 39.048 ;
     RECT  55.645 43.536 55.717 43.656 ;
     RECT  54.749 23.328 55.753 23.352 ;
     RECT  55.645 24.432 55.753 25.032 ;
     RECT  55.717 43.392 55.765 44.088 ;
     RECT  55.753 23.328 55.789 25.032 ;
     RECT  55.765 43.344 55.813 44.088 ;
     RECT  55.813 20.352 55.825 20.376 ;
     RECT  55.213 40.464 55.825 40.68 ;
     RECT  55.825 40.464 55.897 41.16 ;
     RECT  55.681 26.784 56.101 39.048 ;
     RECT  54.529 45.504 56.101 46.584 ;
     RECT  55.897 40.128 56.113 41.16 ;
     RECT  55.813 43.344 56.149 44.136 ;
     RECT  56.101 26.64 56.197 39.048 ;
     RECT  56.113 40.032 56.197 41.16 ;
     RECT  55.789 23.28 56.245 25.032 ;
     RECT  56.197 26.64 56.245 41.16 ;
     RECT  56.101 45.504 56.293 47.448 ;
     RECT  56.149 43.344 56.329 44.184 ;
     RECT  56.293 45.216 56.329 47.448 ;
     RECT  55.861 4.512 56.408 4.536 ;
     RECT  55.825 20.352 56.408 21 ;
     RECT  56.245 23.28 56.408 41.16 ;
     RECT  56.329 43.344 56.408 47.448 ;
     RECT  51.304 49.2 56.408 49.224 ;
     RECT  55.141 52.848 56.408 58.488 ;
     RECT  55.573 92.208 56.408 93.864 ;
     RECT  55.357 94.992 56.408 95.016 ;
     RECT  56.408 2.148 56.512 95.052 ;
     RECT  56.512 2.418 56.704 94.782 ;
     RECT  56.704 4.512 56.867 4.536 ;
     RECT  56.704 23.232 56.867 42.216 ;
     RECT  56.867 23.232 56.915 40.152 ;
     RECT  56.821 0.192 56.981 0.216 ;
     RECT  56.704 91.44 57.011 92.376 ;
     RECT  57.011 92.352 57.053 92.376 ;
     RECT  56.704 93.504 57.053 93.528 ;
     RECT  56.977 96.336 57.251 96.36 ;
     RECT  56.704 3.408 57.299 3.432 ;
     RECT  56.915 34.8 57.485 40.152 ;
     RECT  56.867 41.136 57.665 42.216 ;
     RECT  57.665 41.568 57.773 42.216 ;
     RECT  56.704 19.584 57.788 22.248 ;
     RECT  56.915 23.232 57.788 33.72 ;
     RECT  56.704 49.92 58.057 51.864 ;
     RECT  56.704 60.144 58.069 61.368 ;
     RECT  56.704 52.848 58.129 58.776 ;
     RECT  58.057 49.824 58.165 51.864 ;
     RECT  58.129 52.848 58.165 59.016 ;
     RECT  58.165 49.824 58.261 59.016 ;
     RECT  58.069 60.144 58.261 61.752 ;
     RECT  58.261 49.824 58.309 61.752 ;
     RECT  58.309 49.056 58.417 61.752 ;
     RECT  56.704 43.296 58.453 47.448 ;
     RECT  58.417 48.48 58.453 61.752 ;
     RECT  58.417 68.544 58.453 68.568 ;
     RECT  58.489 66.72 58.673 66.744 ;
     RECT  57.773 41.568 58.781 41.976 ;
     RECT  57.485 35.472 58.853 40.152 ;
     RECT  58.597 96.336 58.883 96.36 ;
     RECT  58.453 67.824 58.885 68.568 ;
     RECT  56.704 69.552 58.885 69.816 ;
     RECT  58.453 43.296 59.029 61.752 ;
     RECT  58.453 1.728 59.357 1.752 ;
     RECT  59.209 16.752 59.413 16.776 ;
     RECT  57.829 3.936 59.459 3.96 ;
     RECT  59.029 43.296 59.497 61.896 ;
     RECT  58.885 67.824 59.605 69.816 ;
     RECT  59.605 67.824 59.653 70.296 ;
     RECT  58.021 93.984 59.681 94.008 ;
     RECT  59.653 67.296 59.701 70.296 ;
     RECT  59.701 67.296 59.713 70.392 ;
     RECT  59.713 67.152 59.749 70.392 ;
     RECT  59.173 65.76 59.797 65.784 ;
     RECT  57.788 19.584 60.001 33.72 ;
     RECT  59.797 64.896 60.073 65.784 ;
     RECT  58.781 41.952 60.085 41.976 ;
     RECT  59.497 43.296 60.085 62.232 ;
     RECT  60.001 19.584 60.217 33.912 ;
     RECT  58.853 35.472 60.253 38.52 ;
     RECT  60.073 64.896 60.277 65.832 ;
     RECT  59.749 67.152 60.277 70.824 ;
     RECT  60.277 64.896 60.325 70.824 ;
     RECT  58.453 92.976 60.325 93 ;
     RECT  59.413 16.416 60.397 16.776 ;
     RECT  60.133 1.152 60.473 1.176 ;
     RECT  60.085 41.952 60.505 62.232 ;
     RECT  60.217 96.336 60.515 96.36 ;
     RECT  60.505 41.376 60.541 62.232 ;
     RECT  60.217 19.584 60.613 34.008 ;
     RECT  60.253 35.136 60.613 38.52 ;
     RECT  60.541 41.184 60.613 62.232 ;
     RECT  60.325 64.848 60.613 70.824 ;
     RECT  58.853 40.032 60.649 40.152 ;
     RECT  60.613 41.184 60.649 63 ;
     RECT  60.613 64.848 60.805 71.64 ;
     RECT  60.613 19.584 61.045 38.52 ;
     RECT  61.045 19.584 61.081 38.904 ;
     RECT  60.649 40.032 61.081 63 ;
     RECT  60.397 16.32 61.109 16.776 ;
     RECT  61.081 19.584 61.189 63 ;
     RECT  61.189 19.296 61.244 63 ;
     RECT  60.325 92.4 61.285 93 ;
     RECT  61.244 18.96 61.297 63 ;
     RECT  60.805 64.224 61.297 71.64 ;
     RECT  61.285 91.92 61.369 93 ;
     RECT  61.369 91.92 61.381 93.336 ;
     RECT  61.381 91.056 61.669 93.336 ;
     RECT  61.436 3.936 61.808 3.96 ;
     RECT  56.704 14.112 61.808 14.136 ;
     RECT  61.109 16.32 61.808 17.16 ;
     RECT  61.297 18.96 61.808 71.64 ;
     RECT  56.704 78.624 61.808 78.648 ;
     RECT  61.669 90.624 61.808 93.336 ;
     RECT  61.808 2.148 61.912 95.052 ;
     RECT  61.912 2.418 61.945 95.052 ;
     RECT  61.765 0.192 61.985 0.216 ;
     RECT  61.945 2.418 62.099 95.16 ;
     RECT  62.099 2.418 62.104 94.782 ;
     RECT  62.104 90.768 62.741 93.336 ;
     RECT  62.104 3.84 63.068 3.864 ;
     RECT  62.104 16.032 63.068 16.344 ;
     RECT  63.068 3.84 63.155 4.296 ;
     RECT  63.068 15.984 63.155 16.344 ;
     RECT  62.104 17.616 63.389 71.64 ;
     RECT  63.457 94.992 63.731 95.016 ;
     RECT  63.397 0.192 63.785 0.216 ;
     RECT  63.155 16.224 64.321 16.344 ;
     RECT  62.741 90.768 64.357 92.712 ;
     RECT  63.389 18.528 64.501 71.64 ;
     RECT  64.357 90.768 64.721 93.192 ;
     RECT  64.321 16.224 64.748 16.44 ;
     RECT  64.721 92.4 64.825 93.192 ;
     RECT  64.748 3.936 64.835 3.96 ;
     RECT  64.748 16.224 64.835 16.488 ;
     RECT  64.835 16.224 65.009 16.44 ;
     RECT  64.501 18.144 65.009 71.64 ;
     RECT  65.077 0.192 65.161 0.216 ;
     RECT  65.077 94.992 65.363 95.016 ;
     RECT  64.825 92.4 65.905 93.24 ;
     RECT  65.905 92.4 65.941 93.528 ;
     RECT  65.941 92.304 66.131 93.528 ;
     RECT  65.009 16.272 66.277 16.44 ;
     RECT  66.277 16.128 66.38 16.44 ;
     RECT  65.009 18.384 66.805 71.64 ;
     RECT  66.661 96.336 66.947 96.36 ;
     RECT  66.38 16.128 67.165 17.016 ;
     RECT  66.805 18.192 67.165 71.64 ;
     RECT  65.689 4.512 67.208 4.536 ;
     RECT  62.104 14.112 67.208 14.136 ;
     RECT  67.165 16.128 67.208 71.64 ;
     RECT  62.104 78.624 67.208 78.648 ;
     RECT  64.721 90.768 67.208 91.08 ;
     RECT  66.131 92.4 67.208 93.528 ;
     RECT  67.208 2.148 67.312 95.052 ;
     RECT  66.709 1.152 67.421 1.176 ;
     RECT  67.312 2.418 67.504 94.782 ;
     RECT  67.504 3.744 68.149 3.96 ;
     RECT  68.149 3.744 68.243 3.768 ;
     RECT  67.504 15.408 68.285 71.64 ;
     RECT  68.285 15.408 68.429 16.008 ;
     RECT  68.285 17.04 68.465 71.64 ;
     RECT  68.389 0.192 68.537 0.216 ;
     RECT  68.317 96.336 68.579 96.36 ;
     RECT  67.504 90.864 69.005 91.08 ;
     RECT  67.504 92.4 69.145 93.768 ;
     RECT  69.005 91.056 69.361 91.08 ;
     RECT  69.145 92.4 69.361 93.912 ;
     RECT  67.504 14.112 69.469 14.136 ;
     RECT  68.429 15.456 69.469 16.008 ;
     RECT  69.469 14.112 69.539 16.008 ;
     RECT  68.465 17.184 69.581 71.64 ;
     RECT  69.361 91.056 70.157 93.912 ;
     RECT  69.937 96.336 70.211 96.36 ;
     RECT  69.581 18.384 70.301 71.64 ;
     RECT  69.397 3.936 70.355 3.96 ;
     RECT  70.297 17.136 70.381 17.16 ;
     RECT  70.021 1.152 70.553 1.176 ;
     RECT  70.301 19.008 70.589 71.64 ;
     RECT  70.589 19.296 71.629 71.64 ;
     RECT  71.629 19.248 71.948 71.64 ;
     RECT  71.948 18.576 71.953 71.64 ;
     RECT  70.765 3.744 72.241 3.768 ;
     RECT  71.701 1.152 72.317 1.176 ;
     RECT  72.241 3.744 72.608 4.536 ;
     RECT  69.539 14.112 72.608 15.72 ;
     RECT  71.953 17.664 72.608 71.64 ;
     RECT  67.504 78.624 72.608 78.648 ;
     RECT  70.157 91.056 72.608 93.864 ;
     RECT  71.521 94.992 72.608 95.016 ;
     RECT  72.608 2.148 72.712 95.052 ;
     RECT  72.712 2.418 72.904 95.016 ;
     RECT  72.904 91.056 73.181 93.864 ;
     RECT  73.321 0.192 73.405 0.216 ;
     RECT  72.904 94.992 73.427 95.016 ;
     RECT  72.904 3.216 73.475 4.536 ;
     RECT  72.904 13.488 73.475 17.16 ;
     RECT  73.475 3.936 73.829 3.96 ;
     RECT  72.904 18.48 74.009 71.64 ;
     RECT  74.009 18.912 74.081 71.64 ;
     RECT  73.475 14.112 74.153 17.16 ;
     RECT  74.153 14.112 74.657 16.584 ;
     RECT  73.181 91.056 74.693 93.768 ;
     RECT  74.828 3.744 74.915 3.768 ;
     RECT  74.977 88.32 75.013 88.344 ;
     RECT  74.797 94.992 75.059 95.016 ;
     RECT  75.005 0.192 75.089 0.216 ;
     RECT  74.761 17.664 75.116 17.832 ;
     RECT  75.116 17.664 75.203 18.168 ;
     RECT  75.013 87.792 75.251 88.344 ;
     RECT  75.251 87.792 75.269 87.816 ;
     RECT  74.693 91.296 75.625 93.768 ;
     RECT  74.657 15.312 75.665 16.584 ;
     RECT  75.203 17.664 75.983 17.688 ;
     RECT  74.081 19.296 76.028 71.64 ;
     RECT  75.625 91.296 76.057 93.912 ;
     RECT  76.028 19.008 76.115 71.64 ;
     RECT  75.983 17.52 76.309 17.688 ;
     RECT  76.309 17.52 76.355 18.216 ;
     RECT  74.657 14.112 76.357 14.232 ;
     RECT  75.665 15.312 76.357 16.248 ;
     RECT  76.355 17.664 76.403 18.216 ;
     RECT  76.057 91.296 76.403 94.104 ;
     RECT  76.556 94.992 76.643 95.016 ;
     RECT  75.697 4.272 76.741 4.296 ;
     RECT  76.403 91.296 76.741 93.912 ;
     RECT  76.403 18.192 76.745 18.216 ;
     RECT  76.741 3.312 76.787 4.296 ;
     RECT  76.645 1.152 76.997 1.176 ;
     RECT  76.741 91.2 76.997 93.912 ;
     RECT  76.115 19.296 77.533 71.64 ;
     RECT  77.533 18.768 77.893 71.64 ;
     RECT  76.787 3.312 78.008 3.336 ;
     RECT  76.357 14.112 78.008 16.248 ;
     RECT  77.893 18.432 78.008 71.64 ;
     RECT  72.904 78.624 78.008 78.648 ;
     RECT  76.997 91.296 78.008 93.912 ;
     RECT  78.008 2.148 78.112 95.052 ;
     RECT  77.965 96.336 78.275 96.36 ;
     RECT  78.112 2.418 78.304 94.782 ;
     RECT  78.304 14.112 78.365 17.64 ;
     RECT  78.365 14.112 78.509 16.632 ;
     RECT  78.304 78.624 78.851 78.648 ;
     RECT  78.325 1.152 78.869 1.176 ;
     RECT  78.365 17.616 78.905 17.64 ;
     RECT  78.304 3.696 78.947 4.296 ;
     RECT  78.509 14.112 78.947 15.576 ;
     RECT  78.947 14.112 79.049 14.136 ;
     RECT  78.304 92.688 79.235 94.008 ;
     RECT  79.285 14.064 79.811 14.088 ;
     RECT  79.621 96.336 79.907 96.36 ;
     RECT  78.304 91.344 79.913 91.656 ;
     RECT  78.947 15.264 79.957 15.576 ;
     RECT  79.957 15.264 80.003 16.248 ;
     RECT  80.003 15.36 80.044 16.248 ;
     RECT  79.957 0.576 80.273 0.6 ;
     RECT  80.044 15.36 80.387 16.008 ;
     RECT  79.621 17.856 80.387 17.88 ;
     RECT  79.235 92.688 80.579 93.768 ;
     RECT  79.913 91.488 80.771 91.656 ;
     RECT  78.304 19.248 81.212 71.64 ;
     RECT  81.241 79.2 81.253 79.224 ;
     RECT  80.771 91.584 81.253 91.656 ;
     RECT  81.212 19.248 81.299 71.832 ;
     RECT  81.253 78.672 81.325 79.224 ;
     RECT  81.241 94.992 81.491 95.016 ;
     RECT  81.325 78.672 81.533 78.696 ;
     RECT  81.299 19.248 81.577 71.304 ;
     RECT  80.387 15.36 81.781 15.384 ;
     RECT  81.589 0.192 81.893 0.216 ;
     RECT  78.947 3.696 82.033 3.72 ;
     RECT  81.781 15.264 82.069 15.384 ;
     RECT  82.069 15.216 82.109 15.384 ;
     RECT  79.765 12.768 82.117 12.792 ;
     RECT  81.817 13.872 82.117 13.896 ;
     RECT  82.033 3.696 82.163 4.488 ;
     RECT  81.241 18.144 82.165 18.168 ;
     RECT  82.163 4.272 82.204 4.488 ;
     RECT  81.565 16.56 82.211 16.584 ;
     RECT  82.117 12.768 82.225 13.896 ;
     RECT  81.253 91.584 82.357 91.944 ;
     RECT  80.579 92.928 82.357 93.768 ;
     RECT  82.204 4.464 82.397 4.488 ;
     RECT  82.165 17.616 82.837 18.168 ;
     RECT  81.577 19.248 82.837 70.872 ;
     RECT  82.357 91.584 83.185 93.768 ;
     RECT  82.837 17.616 83.329 70.872 ;
     RECT  83.185 91.584 83.401 93.816 ;
     RECT  82.861 94.992 83.401 95.016 ;
     RECT  82.225 12.768 83.408 12.792 ;
     RECT  82.225 13.872 83.408 13.896 ;
     RECT  82.109 15.216 83.408 15.288 ;
     RECT  83.329 17.136 83.408 70.872 ;
     RECT  81.973 78.192 83.408 78.216 ;
     RECT  83.401 91.584 83.408 95.016 ;
     RECT  83.408 2.148 83.512 95.052 ;
     RECT  83.269 0.192 83.585 0.216 ;
     RECT  83.512 2.418 83.704 94.782 ;
     RECT  83.704 13.872 83.843 70.872 ;
     RECT  83.704 3.408 83.917 4.248 ;
     RECT  83.843 14.208 84.197 70.872 ;
     RECT  83.704 91.632 84.269 94.782 ;
     RECT  84.269 91.92 84.481 94.782 ;
     RECT  84.197 14.208 84.659 17.352 ;
     RECT  83.704 78.192 84.697 78.216 ;
     RECT  84.659 14.208 84.7 16.2 ;
     RECT  84.7 14.208 84.709 16.008 ;
     RECT  84.481 91.92 84.755 95.016 ;
     RECT  84.697 78.192 84.781 78.648 ;
     RECT  84.781 78.192 84.953 78.216 ;
     RECT  84.901 1.152 85.061 1.176 ;
     RECT  84.709 14.208 85.205 15.192 ;
     RECT  84.197 18.768 85.429 70.872 ;
     RECT  84.659 17.328 85.571 17.352 ;
     RECT  85.429 18.384 85.709 70.872 ;
     RECT  83.917 4.224 85.715 4.248 ;
     RECT  85.525 14.064 85.715 14.088 ;
     RECT  86.029 96.336 86.339 96.36 ;
     RECT  84.755 91.92 86.627 94.056 ;
     RECT  85.205 15.168 86.641 15.192 ;
     RECT  86.641 14.976 86.681 15.192 ;
     RECT  86.581 1.152 86.789 1.176 ;
     RECT  85.709 19.2 87.215 70.872 ;
     RECT  83.704 12.768 87.217 12.792 ;
     RECT  86.677 90.912 87.221 90.936 ;
     RECT  86.627 91.92 87.251 93.816 ;
     RECT  87.251 93.408 87.365 93.816 ;
     RECT  86.173 17.04 87.587 17.064 ;
     RECT  87.541 3.312 87.653 3.72 ;
     RECT  87.215 18.768 87.683 70.872 ;
     RECT  87.721 96.336 87.971 96.36 ;
     RECT  88.213 1.152 88.373 1.176 ;
     RECT  87.653 3.696 88.693 3.72 ;
     RECT  88.693 3.696 88.808 4.536 ;
     RECT  87.217 12.768 88.808 13.656 ;
     RECT  86.681 14.976 88.808 15 ;
     RECT  88.261 17.424 88.808 17.448 ;
     RECT  87.683 19.248 88.808 70.872 ;
     RECT  88.117 90.624 88.808 90.648 ;
     RECT  87.251 91.92 88.808 92.424 ;
     RECT  87.365 93.504 88.808 93.816 ;
     RECT  88.808 2.148 88.912 95.052 ;
     RECT  88.912 2.418 89.104 94.782 ;
     RECT  89.104 18.768 89.453 70.872 ;
     RECT  89.104 91.152 89.507 93.816 ;
     RECT  89.507 91.728 89.548 92.664 ;
     RECT  89.104 17.424 89.597 17.688 ;
     RECT  89.341 96.336 89.603 96.36 ;
     RECT  89.548 91.728 89.891 92.376 ;
     RECT  89.893 0.192 89.993 0.216 ;
     RECT  89.104 13.632 90.083 13.656 ;
     RECT  89.104 14.976 90.131 15.336 ;
     RECT  90.131 15.024 90.245 15.336 ;
     RECT  90.085 12.912 90.323 12.936 ;
     RECT  89.891 92.112 90.781 92.376 ;
     RECT  89.507 93.744 90.781 93.816 ;
     RECT  89.597 17.664 90.961 17.688 ;
     RECT  90.961 17.664 90.989 18.168 ;
     RECT  89.453 19.296 90.989 70.872 ;
     RECT  90.989 17.664 91.181 70.872 ;
     RECT  90.889 94.992 91.187 95.016 ;
     RECT  91.181 17.664 91.217 19.08 ;
     RECT  91.217 17.664 91.235 18.408 ;
     RECT  90.241 3.408 91.244 3.432 ;
     RECT  90.245 15.024 91.285 15.048 ;
     RECT  91.244 3.408 91.325 3.96 ;
     RECT  91.325 3.936 91.331 3.96 ;
     RECT  91.189 16.176 91.427 16.2 ;
     RECT  91.285 13.68 91.523 15.048 ;
     RECT  91.235 18.144 91.523 18.408 ;
     RECT  91.523 14.064 91.613 15.048 ;
     RECT  91.523 18.384 91.859 18.408 ;
     RECT  91.525 1.152 92.189 1.176 ;
     RECT  90.781 92.112 92.405 93.816 ;
     RECT  91.181 20.112 92.609 70.872 ;
     RECT  92.609 19.92 92.636 70.872 ;
     RECT  90.277 10.656 92.677 10.68 ;
     RECT  92.636 19.728 92.723 70.872 ;
     RECT  92.509 94.992 92.819 95.016 ;
     RECT  93.185 0.192 93.269 0.216 ;
     RECT  92.041 4.128 93.589 4.152 ;
     RECT  92.405 92.928 93.596 93.816 ;
     RECT  93.589 3.216 94.208 4.152 ;
     RECT  92.677 10.464 94.208 10.68 ;
     RECT  91.613 15.024 94.208 15.048 ;
     RECT  92.723 20.112 94.208 70.872 ;
     RECT  92.473 91.584 94.208 91.608 ;
     RECT  93.596 92.928 94.208 94.248 ;
     RECT  94.208 2.148 94.312 95.052 ;
     RECT  94.312 2.418 94.345 95.052 ;
     RECT  94.345 2.418 94.451 95.16 ;
     RECT  94.451 2.418 94.504 94.782 ;
     RECT  94.504 20.112 94.565 70.872 ;
     RECT  94.504 91.584 94.565 91.848 ;
     RECT  94.504 3.888 94.601 4.44 ;
     RECT  94.565 91.824 94.745 91.848 ;
     RECT  94.837 0.192 95.105 0.216 ;
     RECT  94.504 92.832 95.677 93.768 ;
     RECT  94.504 10.608 95.965 10.632 ;
     RECT  94.601 4.416 95.969 4.44 ;
     RECT  94.504 15.024 96.035 15.048 ;
     RECT  95.749 94.992 96.035 95.016 ;
     RECT  95.965 10.608 96.049 10.824 ;
     RECT  95.677 92.832 96.109 93.816 ;
     RECT  96.517 0.576 96.725 0.6 ;
     RECT  96.109 92.688 97.013 93.816 ;
     RECT  97.369 96.336 97.667 96.36 ;
     RECT  96.325 3.264 97.957 3.288 ;
     RECT  97.957 3.264 98.003 4.104 ;
     RECT  98.003 3.84 98.044 4.104 ;
     RECT  97.013 93.456 98.305 93.816 ;
     RECT  98.305 93.216 98.377 93.816 ;
     RECT  98.149 0.576 98.453 0.6 ;
     RECT  98.044 3.84 99.169 3.864 ;
     RECT  98.989 96.336 99.299 96.36 ;
     RECT  98.377 92.304 99.421 93.816 ;
     RECT  99.169 3.84 99.608 4.152 ;
     RECT  95.989 6.192 99.608 6.216 ;
     RECT  96.049 10.608 99.608 10.632 ;
     RECT  94.565 20.4 99.608 70.872 ;
     RECT  99.421 91.68 99.608 93.816 ;
     RECT  99.608 2.148 99.712 95.052 ;
     RECT  99.712 2.418 99.904 94.782 ;
     RECT  99.904 10.608 100.019 10.632 ;
     RECT  99.781 0.192 100.145 0.216 ;
     RECT  99.904 5.952 100.307 5.976 ;
     RECT  99.904 4.128 100.613 4.536 ;
     RECT  99.904 92.304 100.883 93.24 ;
     RECT  100.789 94.992 100.883 95.016 ;
     RECT  100.883 92.928 101.041 93.24 ;
     RECT  101.461 0.192 101.585 0.216 ;
     RECT  101.041 92.928 102.38 93.48 ;
     RECT  102.38 92.928 102.467 93.528 ;
     RECT  102.229 94.992 102.515 95.016 ;
     RECT  100.613 4.272 102.701 4.536 ;
     RECT  102.701 4.272 103.273 4.296 ;
     RECT  103.093 1.152 103.385 1.176 ;
     RECT  104.773 1.152 104.933 1.176 ;
     RECT  103.273 3.312 105.008 4.296 ;
     RECT  99.904 20.4 105.008 70.872 ;
     RECT  102.467 92.928 105.008 93.48 ;
     RECT  103.849 94.992 105.008 95.016 ;
     RECT  105.008 2.148 105.112 95.052 ;
     RECT  105.112 2.418 105.304 95.016 ;
     RECT  105.304 94.992 105.731 95.016 ;
     RECT  105.304 4.224 106.297 4.344 ;
     RECT  106.297 3.984 106.337 4.344 ;
     RECT  105.304 93.504 106.445 93.528 ;
     RECT  106.337 3.984 106.585 4.008 ;
     RECT  106.585 3.408 106.625 4.008 ;
     RECT  106.405 1.152 106.877 1.176 ;
     RECT  106.981 96.336 107.089 96.36 ;
     RECT  107.089 96.336 107.363 96.408 ;
     RECT  106.625 3.408 108.353 3.432 ;
     RECT  108.085 1.152 108.605 1.176 ;
     RECT  107.363 96.336 108.709 96.36 ;
     RECT  108.709 96.336 108.995 96.408 ;
     RECT  107.917 93.888 109.681 93.912 ;
     RECT  108.995 96.336 109.793 96.36 ;
     RECT  109.717 1.152 110.081 1.176 ;
     RECT  105.304 20.4 110.408 70.872 ;
     RECT  109.681 93.024 110.408 93.912 ;
     RECT  110.408 2.148 110.501 95.052 ;
     RECT  110.501 2.148 110.512 95.208 ;
     RECT  110.512 2.418 110.585 95.208 ;
     RECT  110.585 2.418 110.704 94.782 ;
     RECT  110.704 20.016 110.819 70.872 ;
     RECT  110.704 3.408 110.873 3.864 ;
     RECT  110.873 3.696 110.915 3.864 ;
     RECT  110.704 16.848 110.915 17.112 ;
     RECT  111.397 0.576 111.737 0.6 ;
     RECT  110.704 92.4 111.989 93.048 ;
     RECT  111.989 92.4 112.169 93 ;
     RECT  111.949 94.992 112.211 95.016 ;
     RECT  110.704 15.456 112.268 15.48 ;
     RECT  110.819 20.4 112.309 70.872 ;
     RECT  110.915 16.848 112.355 16.872 ;
     RECT  112.268 15.456 112.549 15.624 ;
     RECT  112.549 14.832 112.595 15.624 ;
     RECT  112.595 14.832 112.636 15.48 ;
     RECT  110.915 3.84 112.849 3.864 ;
     RECT  112.849 3.84 113.077 4.536 ;
     RECT  113.077 3.168 113.123 4.536 ;
     RECT  113.029 0.576 113.141 0.6 ;
     RECT  113.123 3.168 113.164 3.192 ;
     RECT  112.169 92.88 113.425 93 ;
     RECT  113.123 4.512 113.699 4.536 ;
     RECT  112.309 19.488 113.795 70.872 ;
     RECT  113.533 94.992 113.795 95.016 ;
     RECT  113.653 14.256 114.041 14.28 ;
     RECT  113.425 92.784 114.041 93 ;
     RECT  112.636 15.456 114.505 15.48 ;
     RECT  114.505 15.456 114.721 16.056 ;
     RECT  114.661 0.192 114.869 0.216 ;
     RECT  114.041 92.976 115.045 93 ;
     RECT  113.795 20.4 115.148 70.872 ;
     RECT  115.045 92.976 115.153 93.768 ;
     RECT  114.721 15.312 115.189 16.056 ;
     RECT  114.829 3.936 115.808 3.96 ;
     RECT  115.189 14.736 115.808 16.056 ;
     RECT  115.148 19.776 115.808 70.872 ;
     RECT  115.153 92.256 115.808 93.768 ;
     RECT  115.153 94.992 115.808 95.016 ;
     RECT  115.808 2.148 115.912 95.052 ;
     RECT  115.912 2.418 116.104 94.782 ;
     RECT  116.104 3.408 116.243 3.96 ;
     RECT  116.104 14.592 116.309 16.056 ;
     RECT  116.104 92.256 116.387 94.008 ;
     RECT  116.341 0.192 116.453 0.216 ;
     RECT  116.387 92.256 116.561 93.528 ;
     RECT  116.773 96.336 117.059 96.36 ;
     RECT  116.309 15.312 117.097 16.056 ;
     RECT  117.097 15.312 117.173 16.44 ;
     RECT  116.561 92.928 117.497 93.528 ;
     RECT  116.243 3.408 117.673 3.432 ;
     RECT  117.673 3.408 117.713 3.96 ;
     RECT  117.173 15.984 117.733 16.44 ;
     RECT  117.713 3.936 117.779 3.96 ;
     RECT  116.104 20.256 117.779 70.872 ;
     RECT  117.733 15.984 117.82 16.968 ;
     RECT  117.82 15.984 118.001 16.44 ;
     RECT  117.733 19.2 118.001 19.224 ;
     RECT  117.973 0.192 118.109 0.216 ;
     RECT  118.393 96.336 118.643 96.36 ;
     RECT  117.497 93.024 119.077 93.528 ;
     RECT  117.779 20.352 119.125 70.872 ;
     RECT  118.001 16.032 119.189 16.44 ;
     RECT  119.077 92.976 119.269 93.528 ;
     RECT  119.269 92.928 119.441 93.528 ;
     RECT  119.441 92.976 119.473 93.528 ;
     RECT  119.645 1.152 119.729 1.176 ;
     RECT  119.189 16.032 119.941 16.056 ;
     RECT  119.473 4.512 119.987 4.536 ;
     RECT  119.125 19.776 119.987 70.872 ;
     RECT  119.473 92.976 120.013 94.056 ;
     RECT  120.013 92.976 121.052 95.016 ;
     RECT  120.589 3.408 121.208 3.432 ;
     RECT  119.941 15.888 121.208 16.056 ;
     RECT  120.985 17.088 121.208 17.112 ;
     RECT  120.853 19.344 121.208 19.368 ;
     RECT  119.987 20.352 121.208 70.872 ;
     RECT  121.052 92.832 121.208 95.016 ;
     RECT  121.208 2.148 121.312 95.052 ;
     RECT  121.312 2.418 121.504 95.016 ;
     RECT  121.285 1.152 121.565 1.176 ;
     RECT  121.504 3.408 121.565 4.536 ;
     RECT  121.565 3.936 121.619 4.536 ;
     RECT  121.504 18.528 121.619 18.552 ;
     RECT  121.504 92.352 121.907 95.016 ;
     RECT  121.504 15.984 122.033 17.112 ;
     RECT  121.907 92.352 122.077 94.056 ;
     RECT  122.077 92.928 122.573 94.056 ;
     RECT  122.957 0.192 123.041 0.216 ;
     RECT  122.033 15.984 123.068 16.536 ;
     RECT  121.619 4.512 123.155 4.536 ;
     RECT  123.068 15.984 123.155 16.728 ;
     RECT  122.641 19.008 123.155 19.032 ;
     RECT  122.573 93.024 123.181 94.056 ;
     RECT  123.181 93.024 123.221 95.016 ;
     RECT  121.504 20.16 123.361 70.872 ;
     RECT  123.221 94.992 123.491 95.016 ;
     RECT  123.221 93.024 123.721 93.48 ;
     RECT  123.361 19.872 123.725 70.872 ;
     RECT  123.155 15.984 125.077 16.536 ;
     RECT  124.333 17.616 125.077 17.64 ;
     RECT  124.729 3.744 125.123 3.768 ;
     RECT  124.799 18.624 125.123 18.648 ;
     RECT  124.873 94.992 125.123 95.016 ;
     RECT  124.597 1.152 125.129 1.176 ;
     RECT  123.721 92.928 125.381 93.48 ;
     RECT  123.725 20.208 125.701 70.872 ;
     RECT  125.381 93.024 126.133 93.48 ;
     RECT  126.277 1.152 126.569 1.176 ;
     RECT  125.305 4.272 126.608 4.296 ;
     RECT  125.077 15.984 126.608 17.64 ;
     RECT  125.701 19.632 126.608 70.872 ;
     RECT  126.133 93.024 126.608 93.528 ;
     RECT  126.608 2.148 126.712 95.052 ;
     RECT  126.277 96.336 126.755 96.36 ;
     RECT  126.712 2.418 126.904 94.782 ;
     RECT  126.904 19.632 127.037 70.872 ;
     RECT  126.904 3.408 128.108 3.432 ;
     RECT  128.108 3.408 128.153 3.72 ;
     RECT  127.037 20.4 128.156 70.872 ;
     RECT  128.153 3.696 128.195 3.72 ;
     RECT  126.904 18.432 128.243 18.456 ;
     RECT  128.156 20.016 128.243 70.872 ;
     RECT  127.909 1.152 128.297 1.176 ;
     RECT  128.041 96.336 128.339 96.36 ;
     RECT  126.904 92.928 128.401 93.528 ;
     RECT  128.401 92.928 128.485 93.912 ;
     RECT  128.485 92.352 128.621 93.912 ;
     RECT  128.653 18.816 129.373 18.84 ;
     RECT  129.373 18.624 129.413 18.84 ;
     RECT  128.621 92.928 129.413 93.912 ;
     RECT  128.869 3.936 129.692 3.96 ;
     RECT  126.904 15.984 129.733 16.92 ;
     RECT  129.692 3.936 129.779 4.296 ;
     RECT  129.413 18.624 129.971 18.648 ;
     RECT  129.661 94.992 129.971 95.016 ;
     RECT  129.589 1.152 129.989 1.176 ;
     RECT  129.733 15.984 130.241 17.352 ;
     RECT  128.243 20.4 130.453 70.872 ;
     RECT  131.221 0.192 131.393 0.216 ;
     RECT  129.413 92.928 131.605 93.768 ;
     RECT  131.461 18.96 131.893 18.984 ;
     RECT  130.489 3.408 132.008 3.432 ;
     RECT  130.241 15.984 132.008 17.112 ;
     RECT  131.893 18.144 132.008 18.984 ;
     RECT  130.453 20.208 132.008 70.872 ;
     RECT  131.605 92.352 132.008 93.768 ;
     RECT  131.353 94.992 132.008 95.016 ;
     RECT  132.008 2.148 132.112 95.052 ;
     RECT  132.112 2.418 132.304 95.016 ;
     RECT  132.304 19.968 132.445 70.872 ;
     RECT  132.304 94.992 133.187 95.016 ;
     RECT  132.853 0.192 133.337 0.216 ;
     RECT  132.304 93.024 133.397 93.768 ;
     RECT  132.304 4.512 133.571 4.536 ;
     RECT  132.445 20.4 133.585 70.872 ;
     RECT  132.304 18.144 133.612 18.168 ;
     RECT  133.397 92.928 134.108 93.768 ;
     RECT  134.108 92.832 134.195 93.768 ;
     RECT  132.304 15.984 134.269 17.112 ;
     RECT  134.195 92.928 134.339 93.768 ;
     RECT  134.269 15.504 134.525 17.112 ;
     RECT  134.533 0.192 134.62 0.216 ;
     RECT  133.585 19.68 134.733 70.872 ;
     RECT  133.729 3.408 134.78 3.432 ;
     RECT  134.521 94.992 134.819 95.016 ;
     RECT  134.78 3.408 134.849 3.72 ;
     RECT  134.849 3.696 134.867 3.72 ;
     RECT  134.677 18.192 135.065 18.216 ;
     RECT  135.133 19.008 135.245 19.032 ;
     RECT  134.733 20.4 135.836 70.872 ;
     RECT  135.205 3.936 135.857 4.056 ;
     RECT  134.525 15.504 135.877 17.064 ;
     RECT  135.836 19.968 135.923 70.872 ;
     RECT  134.339 93.072 136.141 93.768 ;
     RECT  135.857 3.936 136.211 3.96 ;
     RECT  135.877 15.504 136.217 17.88 ;
     RECT  136.141 96.336 136.451 96.36 ;
     RECT  136.165 1.152 136.469 1.176 ;
     RECT  136.141 93.072 136.681 94.056 ;
     RECT  136.217 15.936 137.077 17.88 ;
     RECT  136.861 3.408 137.408 3.432 ;
     RECT  137.077 15.936 137.408 18.84 ;
     RECT  135.923 20.4 137.408 70.872 ;
     RECT  136.681 92.928 137.408 94.056 ;
     RECT  137.408 2.148 137.512 95.052 ;
     RECT  137.512 2.418 137.704 94.782 ;
     RECT  137.704 3.408 137.981 4.056 ;
     RECT  137.981 3.696 137.987 4.056 ;
     RECT  137.704 16.032 137.987 18.792 ;
     RECT  137.761 96.336 138.035 96.36 ;
     RECT  137.845 1.152 138.377 1.176 ;
     RECT  137.704 92.928 138.467 94.056 ;
     RECT  137.704 20.352 139.189 70.872 ;
     RECT  137.987 16.032 139.199 17.064 ;
     RECT  137.987 18.768 139.199 18.792 ;
     RECT  139.199 16.032 139.283 18.792 ;
     RECT  138.467 93.072 139.381 94.056 ;
     RECT  139.283 16.032 139.445 18.216 ;
     RECT  137.987 4.032 139.477 4.056 ;
     RECT  139.477 3.936 139.523 4.056 ;
     RECT  139.445 15.984 139.523 18.216 ;
     RECT  139.523 15.984 139.529 17.112 ;
     RECT  139.523 3.936 139.601 3.96 ;
     RECT  139.381 93.072 139.667 95.016 ;
     RECT  139.477 1.152 139.673 1.176 ;
     RECT  139.667 93.072 139.715 94.056 ;
     RECT  139.715 93.072 139.849 93.48 ;
     RECT  139.189 20.352 140.033 71.304 ;
     RECT  140.033 20.352 140.684 70.872 ;
     RECT  139.523 18.192 140.713 18.216 ;
     RECT  140.713 18.192 140.725 18.408 ;
     RECT  140.684 19.68 140.725 70.872 ;
     RECT  140.725 18.192 140.771 70.872 ;
     RECT  139.529 16.08 140.773 17.112 ;
     RECT  140.771 18.192 140.773 19.368 ;
     RECT  140.773 16.08 140.825 19.368 ;
     RECT  140.771 20.4 140.933 70.872 ;
     RECT  140.825 16.08 141.037 18.216 ;
     RECT  141.212 3.744 141.299 3.768 ;
     RECT  141.037 15.888 141.299 18.216 ;
     RECT  141.001 94.992 141.299 95.016 ;
     RECT  140.825 19.344 141.329 19.368 ;
     RECT  141.299 15.888 141.347 17.112 ;
     RECT  140.933 20.448 141.5 70.872 ;
     RECT  139.849 92.928 141.553 93.48 ;
     RECT  141.5 20.448 141.587 71.832 ;
     RECT  141.553 93.072 142.297 93.48 ;
     RECT  142.369 19.2 142.508 19.224 ;
     RECT  141.587 20.448 142.508 70.872 ;
     RECT  142.508 4.512 142.808 4.536 ;
     RECT  141.347 15.984 142.808 17.112 ;
     RECT  141.299 18.144 142.808 18.216 ;
     RECT  142.508 19.2 142.808 70.872 ;
     RECT  142.297 93.072 142.808 93.528 ;
     RECT  142.765 95.184 142.808 95.208 ;
     RECT  142.808 2.148 142.883 95.208 ;
     RECT  142.883 2.148 142.912 95.052 ;
     RECT  141.157 1.152 143.093 1.176 ;
     RECT  142.912 2.418 143.104 94.782 ;
     RECT  143.104 92.928 143.957 93.336 ;
     RECT  143.104 3.408 144.236 3.432 ;
     RECT  143.104 15.984 144.277 17.16 ;
     RECT  143.104 18.384 144.277 18.408 ;
     RECT  144.236 3.408 144.317 3.768 ;
     RECT  144.317 3.744 144.323 3.768 ;
     RECT  144.241 94.992 144.515 95.016 ;
     RECT  144.449 0.576 144.533 0.6 ;
     RECT  144.277 15.984 144.677 18.408 ;
     RECT  144.677 16.272 144.755 18.408 ;
     RECT  144.668 19.44 144.755 19.464 ;
     RECT  144.755 16.272 144.785 17.88 ;
     RECT  143.957 92.928 145.043 93.24 ;
     RECT  143.104 20.448 145.177 70.872 ;
     RECT  145.381 18.96 145.468 19.128 ;
     RECT  145.468 18.96 145.477 18.984 ;
     RECT  144.785 16.272 145.645 17.352 ;
     RECT  145.645 15.696 145.789 17.352 ;
     RECT  145.043 93.072 145.861 93.24 ;
     RECT  145.177 20.16 145.907 70.872 ;
     RECT  145.861 93.072 145.945 93.528 ;
     RECT  145.916 4.512 146.003 4.536 ;
     RECT  145.861 96.336 146.147 96.36 ;
     RECT  145.789 15.696 146.189 17.688 ;
     RECT  145.945 93.072 146.197 93.48 ;
     RECT  146.197 92.928 146.369 93.48 ;
     RECT  146.101 0.192 146.405 0.216 ;
     RECT  146.189 15.696 146.801 17.448 ;
     RECT  146.369 93.312 147.013 93.48 ;
     RECT  147.013 93.312 147.373 93.576 ;
     RECT  147.049 3.36 147.589 3.384 ;
     RECT  146.801 15.696 147.589 15.768 ;
     RECT  146.905 19.344 147.589 19.368 ;
     RECT  147.445 96.336 147.731 96.36 ;
     RECT  147.781 0.192 147.881 0.216 ;
     RECT  146.801 17.28 147.985 17.448 ;
     RECT  147.589 18.672 147.985 19.368 ;
     RECT  147.985 17.28 148.028 19.368 ;
     RECT  145.907 20.448 148.028 70.872 ;
     RECT  147.589 15.408 148.093 15.768 ;
     RECT  147.589 3.36 148.208 3.96 ;
     RECT  148.093 15.408 148.208 15.864 ;
     RECT  148.028 17.28 148.208 70.872 ;
     RECT  147.373 92.928 148.208 93.576 ;
     RECT  148.208 2.148 148.312 95.052 ;
     RECT  148.312 2.418 148.504 94.782 ;
     RECT  148.504 93.216 148.673 93.576 ;
     RECT  148.504 3.936 149.075 4.248 ;
     RECT  149.075 3.936 149.141 3.96 ;
     RECT  149.317 94.992 149.537 95.016 ;
     RECT  148.673 93.216 149.569 93.48 ;
     RECT  148.504 19.344 149.605 19.368 ;
     RECT  148.504 20.448 149.605 70.872 ;
     RECT  149.569 92.928 149.641 93.48 ;
     RECT  148.504 15.744 149.785 17.448 ;
     RECT  149.641 92.928 149.795 93.816 ;
     RECT  149.785 15.696 149.825 17.448 ;
     RECT  149.825 16.752 149.891 17.448 ;
     RECT  149.605 19.344 149.891 70.872 ;
     RECT  149.413 1.152 149.933 1.176 ;
     RECT  149.891 16.848 150.761 17.448 ;
     RECT  150.721 94.992 150.995 95.016 ;
     RECT  150.469 3.936 151.091 3.96 ;
     RECT  150.761 16.848 151.091 17.304 ;
     RECT  151.045 0.192 151.157 0.216 ;
     RECT  151.045 19.152 151.468 19.176 ;
     RECT  149.795 93.312 152.269 93.816 ;
     RECT  152.269 92.928 152.627 93.816 ;
     RECT  151.091 16.848 152.665 16.872 ;
     RECT  152.725 1.152 153.101 1.176 ;
     RECT  152.533 95.184 153.101 95.208 ;
     RECT  152.665 16.8 153.164 16.872 ;
     RECT  152.053 3.696 153.601 3.72 ;
     RECT  153.601 3.696 153.608 4.536 ;
     RECT  149.825 15.696 153.608 15.72 ;
     RECT  153.164 16.8 153.608 17.016 ;
     RECT  152.701 19.44 153.608 19.464 ;
     RECT  149.891 20.448 153.608 70.872 ;
     RECT  152.627 93.312 153.608 93.816 ;
     RECT  153.608 2.148 153.712 95.052 ;
     RECT  153.712 2.418 153.904 95.016 ;
     RECT  153.904 94.992 154.211 95.016 ;
     RECT  153.904 16.8 154.499 16.872 ;
     RECT  154.357 1.152 154.613 1.176 ;
     RECT  153.904 18.72 154.739 18.744 ;
     RECT  153.904 3.696 154.787 4.536 ;
     RECT  153.904 14.832 154.933 15.672 ;
     RECT  154.787 3.696 154.937 3.72 ;
     RECT  154.933 14.784 154.979 15.672 ;
     RECT  154.979 14.784 155.801 14.952 ;
     RECT  153.904 20.304 155.909 70.872 ;
     RECT  153.904 93.312 156.017 93.816 ;
     RECT  155.801 14.832 156.089 14.952 ;
     RECT  155.797 94.992 156.161 95.016 ;
     RECT  156.037 1.152 156.233 1.176 ;
     RECT  156.013 18.96 156.373 18.984 ;
     RECT  154.499 16.8 156.419 16.824 ;
     RECT  156.373 18.96 156.661 19.176 ;
     RECT  156.089 14.832 157.133 14.856 ;
     RECT  156.445 3.936 157.237 3.96 ;
     RECT  155.909 20.448 157.392 70.872 ;
     RECT  157.237 3.936 157.475 4.536 ;
     RECT  157.388 14.88 157.475 14.904 ;
     RECT  156.661 18.96 157.475 19.368 ;
     RECT  157.475 3.936 157.565 3.96 ;
     RECT  157.381 94.992 157.673 95.016 ;
     RECT  157.669 0.192 157.817 0.216 ;
     RECT  157.392 20.448 157.889 65.88 ;
     RECT  156.017 93.456 157.921 93.816 ;
     RECT  157.889 20.448 158.321 43.128 ;
     RECT  158.321 28.896 158.357 43.128 ;
     RECT  158.321 20.448 158.461 27.864 ;
     RECT  158.357 29.856 158.501 43.128 ;
     RECT  157.889 44.448 158.501 65.88 ;
     RECT  158.461 20.352 158.531 27.864 ;
     RECT  158.531 27.84 158.537 27.864 ;
     RECT  158.501 57.984 158.537 65.88 ;
     RECT  158.531 20.352 158.627 26.76 ;
     RECT  158.929 3.36 159.008 3.384 ;
     RECT  157.475 18.96 159.008 18.984 ;
     RECT  158.627 20.352 159.008 25.992 ;
     RECT  157.392 67.056 159.008 70.872 ;
     RECT  157.921 93.216 159.008 93.816 ;
     RECT  158.785 96.336 159.059 96.36 ;
     RECT  158.501 30.048 159.077 43.128 ;
     RECT  158.537 58.08 159.077 65.88 ;
     RECT  159.008 2.148 159.112 25.992 ;
     RECT  159.008 67.056 159.112 95.052 ;
     RECT  159.077 30.048 159.113 38.136 ;
     RECT  159.113 30.048 159.221 38.04 ;
     RECT  159.077 39.744 159.253 43.128 ;
     RECT  158.501 44.448 159.253 56.952 ;
     RECT  159.112 2.418 159.304 25.992 ;
     RECT  159.112 67.056 159.304 94.782 ;
     RECT  159.304 93.504 159.365 93.816 ;
     RECT  159.304 3.36 159.443 3.384 ;
     RECT  159.349 0.192 159.545 0.216 ;
     RECT  159.253 39.744 159.617 56.952 ;
     RECT  159.077 58.08 159.617 63.384 ;
     RECT  159.617 59.232 159.725 62.664 ;
     RECT  159.221 30.24 159.761 38.04 ;
     RECT  159.617 39.744 159.761 46.488 ;
     RECT  159.617 48.624 159.761 56.952 ;
     RECT  159.685 28.608 159.772 28.632 ;
     RECT  159.761 30.336 159.797 38.04 ;
     RECT  159.077 64.8 159.797 65.88 ;
     RECT  159.761 39.744 159.905 46.392 ;
     RECT  159.761 48.624 159.905 55.032 ;
     RECT  159.905 41.664 159.941 46.392 ;
     RECT  159.905 51.072 159.941 55.032 ;
     RECT  159.761 56.256 159.941 56.952 ;
     RECT  159.725 59.328 159.941 62.664 ;
     RECT  159.797 64.8 159.941 64.92 ;
     RECT  159.797 30.336 159.977 30.744 ;
     RECT  159.941 41.664 159.977 45.816 ;
     RECT  159.941 53.472 159.977 53.592 ;
     RECT  159.941 56.256 159.977 56.76 ;
     RECT  159.941 54.816 160.013 55.032 ;
     RECT  159.617 58.08 160.049 58.152 ;
     RECT  159.941 59.712 160.049 60.792 ;
     RECT  159.977 42.192 160.085 45.816 ;
     RECT  159.797 31.776 160.117 38.04 ;
     RECT  159.905 48.624 160.121 50.04 ;
     RECT  159.941 51.072 160.121 52.44 ;
     RECT  160.049 59.712 160.121 59.736 ;
     RECT  160.049 60.768 160.121 60.792 ;
     RECT  159.941 61.824 160.121 62.664 ;
     RECT  159.977 56.736 160.157 56.76 ;
     RECT  159.941 64.8 160.157 64.824 ;
     RECT  160.076 27.072 160.163 27.096 ;
     RECT  159.977 30.672 160.265 30.744 ;
     RECT  160.049 58.128 160.265 58.152 ;
     RECT  160.121 51.264 160.307 51.288 ;
     RECT  160.121 52.416 160.307 52.44 ;
     RECT  160.013 55.008 160.307 55.032 ;
     RECT  159.304 20.16 160.337 25.992 ;
     RECT  160.085 42.192 160.337 45.624 ;
     RECT  160.117 31.776 160.409 38.616 ;
     RECT  160.337 42.192 160.451 45.336 ;
     RECT  160.121 50.016 160.451 50.04 ;
     RECT  159.977 53.568 160.553 53.592 ;
     RECT  160.513 4.512 160.597 4.536 ;
     RECT  160.265 30.672 160.643 30.696 ;
     RECT  160.405 94.992 160.691 95.016 ;
     RECT  160.121 48.624 160.697 48.648 ;
     RECT  160.451 44.448 160.787 45.336 ;
     RECT  160.337 20.352 160.835 25.992 ;
     RECT  160.451 42.192 160.835 43.368 ;
     RECT  159.304 18.96 161.027 18.984 ;
     RECT  160.94 28.464 161.027 28.488 ;
     RECT  160.729 47.328 161.027 47.352 ;
     RECT  160.973 0.192 161.057 0.216 ;
     RECT  160.981 27.312 161.093 27.336 ;
     RECT  159.365 93.504 161.309 93.768 ;
     RECT  160.835 20.352 161.363 23.16 ;
     RECT  161.197 29.664 161.413 29.688 ;
     RECT  161.363 21.024 161.453 23.16 ;
     RECT  160.835 24.144 161.453 25.992 ;
     RECT  161.453 21.024 161.555 23.016 ;
     RECT  161.555 21.12 161.603 22.488 ;
     RECT  161.603 21.12 161.633 21.768 ;
     RECT  161.413 29.664 161.651 30.024 ;
     RECT  160.409 31.92 161.701 38.616 ;
     RECT  159.905 39.744 161.701 40.584 ;
     RECT  160.837 3.936 161.773 3.96 ;
     RECT  161.633 21.744 161.795 21.768 ;
     RECT  161.653 29.616 161.809 29.64 ;
     RECT  160.787 44.448 161.809 45.096 ;
     RECT  160.835 42.72 161.845 43.368 ;
     RECT  161.453 24.144 161.921 25.896 ;
     RECT  161.773 3.744 161.948 3.96 ;
     RECT  161.701 31.92 161.981 40.584 ;
     RECT  161.921 25.488 161.987 25.896 ;
     RECT  161.948 3.744 162.035 4.536 ;
     RECT  161.809 28.944 162.035 29.64 ;
     RECT  161.981 31.344 162.061 40.584 ;
     RECT  162.061 31.344 162.085 40.872 ;
     RECT  162.085 31.344 162.133 40.968 ;
     RECT  162.133 31.344 162.169 41.592 ;
     RECT  161.845 42.624 162.169 43.368 ;
     RECT  161.593 52.464 162.179 52.488 ;
     RECT  161.921 24.144 162.227 24.504 ;
     RECT  162.025 94.992 162.275 95.016 ;
     RECT  162.085 47.904 162.281 47.928 ;
     RECT  161.809 44.448 162.457 45.672 ;
     RECT  162.227 24.192 162.515 24.504 ;
     RECT  162.035 29.04 162.533 29.64 ;
     RECT  162.457 44.448 162.541 46.2 ;
     RECT  162.493 27.744 162.611 27.768 ;
     RECT  162.515 24.192 162.659 24.216 ;
     RECT  162.541 44.448 162.677 45.624 ;
     RECT  161.987 25.488 162.755 25.512 ;
     RECT  162.677 44.448 162.755 45.048 ;
     RECT  162.169 31.344 162.853 43.368 ;
     RECT  162.805 52.656 162.961 52.68 ;
     RECT  162.961 52.656 163.001 53.064 ;
     RECT  162.661 0.576 163.037 0.6 ;
     RECT  163.001 53.04 163.145 53.064 ;
     RECT  162.533 29.04 163.289 29.064 ;
     RECT  162.716 30.24 163.393 30.264 ;
     RECT  162.853 31.248 163.393 43.368 ;
     RECT  162.755 44.448 163.427 44.472 ;
     RECT  163.393 30.24 163.525 43.368 ;
     RECT  163.393 27.84 164.111 27.864 ;
     RECT  163.493 3.408 164.149 3.432 ;
     RECT  163.525 30 164.213 43.368 ;
     RECT  164.213 30 164.293 43.944 ;
     RECT  164.149 3.408 164.408 3.864 ;
     RECT  164.111 27.84 164.408 28.44 ;
     RECT  164.293 29.616 164.408 43.944 ;
     RECT  164.293 51.936 164.408 51.96 ;
     RECT  163.813 65.232 164.408 65.256 ;
     RECT  159.304 67.056 164.408 70.872 ;
     RECT  161.309 93.504 164.408 93.528 ;
     RECT  163.645 94.992 164.408 95.016 ;
     RECT  164.408 2.148 164.512 95.052 ;
     RECT  164.293 0.576 164.585 0.6 ;
     RECT  164.512 2.418 164.704 94.782 ;
     RECT  164.704 51.936 164.801 51.96 ;
     RECT  164.704 3.936 165.059 4.296 ;
     RECT  164.704 29.184 165.059 38.184 ;
     RECT  165.059 3.936 165.299 3.96 ;
     RECT  164.704 58.128 165.347 58.152 ;
     RECT  164.704 55.872 165.388 56.136 ;
     RECT  164.704 39.312 165.395 42.744 ;
     RECT  165.059 30.096 165.413 38.184 ;
     RECT  165.388 55.872 165.421 55.992 ;
     RECT  165.265 96.336 165.539 96.36 ;
     RECT  165.413 30.096 165.917 30.168 ;
     RECT  165.917 30.144 166.067 30.168 ;
     RECT  166.021 3.408 166.105 3.432 ;
     RECT  165.413 31.536 166.133 38.184 ;
     RECT  164.704 93.216 166.205 93.24 ;
     RECT  165.973 0.192 166.241 0.216 ;
     RECT  165.395 42.192 166.277 42.744 ;
     RECT  166.133 31.584 166.313 38.184 ;
     RECT  166.268 45.648 166.355 45.672 ;
     RECT  165.421 55.968 166.355 55.992 ;
     RECT  165.395 39.84 166.385 41.16 ;
     RECT  164.704 67.056 166.637 70.824 ;
     RECT  166.385 39.936 166.817 41.16 ;
     RECT  166.748 38.928 166.835 38.952 ;
     RECT  166.313 31.584 167.101 37.608 ;
     RECT  166.813 96.336 167.123 96.36 ;
     RECT  166.381 93.264 167.173 93.288 ;
     RECT  167.101 30.72 167.209 37.608 ;
     RECT  167.132 3.744 167.219 3.768 ;
     RECT  167.209 30.432 167.276 37.608 ;
     RECT  166.277 42.672 167.317 42.744 ;
     RECT  167.276 30.432 167.363 37.848 ;
     RECT  167.363 30.432 167.425 37.608 ;
     RECT  167.425 3.936 167.509 3.96 ;
     RECT  167.317 42.144 167.537 42.792 ;
     RECT  167.42 28.944 167.557 28.968 ;
     RECT  167.425 30.288 167.557 37.608 ;
     RECT  167.557 28.944 167.609 37.608 ;
     RECT  167.609 28.944 167.681 30.744 ;
     RECT  167.173 93.264 167.749 93.48 ;
     RECT  167.605 38.64 167.753 38.664 ;
     RECT  166.817 40.368 167.785 41.16 ;
     RECT  167.609 31.824 167.825 37.608 ;
     RECT  167.785 39.888 167.857 41.16 ;
     RECT  167.641 44.592 167.891 44.616 ;
     RECT  167.537 42.72 167.893 42.792 ;
     RECT  167.681 30.72 167.987 30.744 ;
     RECT  166.637 68.4 168.113 70.824 ;
     RECT  167.749 49.008 168.131 49.032 ;
     RECT  167.605 1.152 168.185 1.176 ;
     RECT  167.941 4.512 168.185 4.536 ;
     RECT  167.857 39.888 168.185 41.592 ;
     RECT  167.893 42.72 168.188 42.84 ;
     RECT  168.188 42.72 168.275 43.32 ;
     RECT  168.275 42.72 168.401 42.84 ;
     RECT  167.749 47.28 168.401 47.304 ;
     RECT  166.637 67.056 168.572 67.368 ;
     RECT  168.185 40.56 168.577 41.592 ;
     RECT  168.401 42.72 168.577 42.792 ;
     RECT  167.317 86.208 168.613 86.232 ;
     RECT  168.229 44.448 168.617 44.472 ;
     RECT  164.704 62.736 168.659 62.76 ;
     RECT  168.572 66.48 168.659 67.368 ;
     RECT  167.749 93.216 168.721 93.48 ;
     RECT  168.577 40.56 168.725 42.792 ;
     RECT  168.505 96.336 168.755 96.36 ;
     RECT  167.825 31.872 168.805 37.608 ;
     RECT  168.721 93.216 168.901 93.528 ;
     RECT  168.805 31.872 169.1 38.376 ;
     RECT  168.805 39.456 169.1 39.48 ;
     RECT  169.081 59.808 169.429 59.832 ;
     RECT  169.237 1.152 169.625 1.176 ;
     RECT  169.436 30.48 169.669 30.504 ;
     RECT  169.1 31.872 169.669 39.48 ;
     RECT  169.117 3.216 169.808 3.24 ;
     RECT  169.58 28.944 169.808 28.968 ;
     RECT  169.669 30.048 169.808 30.504 ;
     RECT  169.669 31.584 169.808 39.48 ;
     RECT  168.725 40.56 169.808 42.744 ;
     RECT  168.949 46.176 169.808 46.2 ;
     RECT  169.429 59.712 169.808 59.832 ;
     RECT  164.704 65.376 169.808 65.4 ;
     RECT  168.659 67.056 169.808 67.368 ;
     RECT  168.113 69.024 169.808 70.824 ;
     RECT  169.429 78.624 169.808 78.648 ;
     RECT  168.613 86.16 169.808 86.232 ;
     RECT  168.901 92.64 169.808 93.528 ;
     RECT  169.808 2.148 169.912 95.052 ;
     RECT  169.912 2.418 170.104 95.016 ;
     RECT  170.104 32.976 170.243 38.856 ;
     RECT  170.104 93.216 170.243 93.768 ;
     RECT  170.104 69.024 170.273 70.392 ;
     RECT  170.104 67.344 170.309 67.368 ;
     RECT  170.104 94.992 170.387 95.016 ;
     RECT  170.104 59.808 170.435 59.832 ;
     RECT  170.104 73.392 170.489 73.512 ;
     RECT  170.104 86.208 170.675 86.232 ;
     RECT  170.104 88.08 170.675 88.296 ;
     RECT  170.104 84.96 170.921 84.984 ;
     RECT  170.104 29.088 170.957 31.656 ;
     RECT  170.104 3.408 171.011 3.432 ;
     RECT  170.957 29.088 171.011 30.36 ;
     RECT  170.273 69.312 171.101 70.392 ;
     RECT  170.243 38.784 171.173 38.856 ;
     RECT  170.957 31.632 171.349 31.656 ;
     RECT  170.104 40.56 171.349 40.584 ;
     RECT  170.917 1.152 171.353 1.176 ;
     RECT  171.349 31.632 171.385 31.8 ;
     RECT  170.243 32.976 171.385 37.464 ;
     RECT  171.349 40.56 171.385 40.68 ;
     RECT  171.385 40.56 171.452 41.064 ;
     RECT  171.452 39.984 171.539 41.064 ;
     RECT  171.745 82.032 171.829 82.056 ;
     RECT  171.781 85.248 171.829 85.272 ;
     RECT  170.675 88.08 171.875 88.104 ;
     RECT  171.011 30.048 171.925 30.36 ;
     RECT  171.385 31.632 171.925 37.464 ;
     RECT  171.173 38.832 171.925 38.856 ;
     RECT  171.539 39.984 171.925 40.92 ;
     RECT  171.101 69.312 171.965 69.768 ;
     RECT  171.673 94.992 171.971 95.016 ;
     RECT  171.925 30.048 171.997 37.464 ;
     RECT  171.673 28.128 172.021 28.152 ;
     RECT  170.243 93.216 172.033 93.288 ;
     RECT  171.493 3.936 172.067 4.104 ;
     RECT  172.033 92.928 172.073 93.288 ;
     RECT  171.997 29.616 172.181 37.464 ;
     RECT  171.829 85.248 172.181 85.512 ;
     RECT  172.021 28.128 172.249 28.44 ;
     RECT  172.181 29.616 172.249 32.904 ;
     RECT  171.965 69.552 172.433 69.768 ;
     RECT  172.46 3.216 172.547 3.24 ;
     RECT  172.249 28.128 172.649 32.904 ;
     RECT  172.649 28.128 172.685 31.992 ;
     RECT  172.685 28.128 172.693 28.344 ;
     RECT  172.433 69.744 172.757 69.768 ;
     RECT  172.181 34.032 172.895 37.464 ;
     RECT  172.895 34.032 172.933 37.848 ;
     RECT  171.925 38.832 172.933 40.92 ;
     RECT  170.104 61.872 172.979 61.896 ;
     RECT  172.933 34.032 173.009 40.92 ;
     RECT  172.549 1.152 173.045 1.176 ;
     RECT  172.693 60.384 173.117 60.408 ;
     RECT  172.693 27.84 173.219 28.344 ;
     RECT  172.685 29.616 173.225 31.992 ;
     RECT  172.073 92.928 173.317 93.24 ;
     RECT  173.317 92.928 173.363 94.008 ;
     RECT  172.933 81.552 173.397 81.576 ;
     RECT  173.363 93.216 173.513 94.008 ;
     RECT  173.293 94.992 173.603 95.016 ;
     RECT  173.009 40.512 173.653 40.92 ;
     RECT  173.509 33.024 173.747 33.048 ;
     RECT  173.009 34.032 173.797 39.336 ;
     RECT  173.225 30.768 173.869 31.992 ;
     RECT  173.797 33.264 173.989 39.336 ;
     RECT  173.653 40.512 173.989 40.968 ;
     RECT  173.869 30.768 174.131 32.184 ;
     RECT  173.219 27.84 174.161 27.912 ;
     RECT  173.989 33.264 174.337 40.968 ;
     RECT  174.229 1.152 174.449 1.176 ;
     RECT  174.337 33.264 174.661 41.016 ;
     RECT  173.513 93.216 174.697 93.24 ;
     RECT  174.024 4.272 175.093 4.296 ;
     RECT  174.131 31.44 175.093 32.184 ;
     RECT  175.093 4.272 175.208 4.44 ;
     RECT  170.104 21.408 175.208 21.432 ;
     RECT  174.161 27.888 175.208 27.912 ;
     RECT  173.225 29.616 175.208 29.64 ;
     RECT  175.093 31.392 175.208 32.184 ;
     RECT  174.661 33.264 175.208 41.64 ;
     RECT  170.104 42.72 175.208 42.744 ;
     RECT  175.165 43.872 175.208 43.896 ;
     RECT  171.541 50.4 175.208 50.424 ;
     RECT  174.337 58.704 175.208 58.728 ;
     RECT  174.373 62.16 175.208 62.184 ;
     RECT  170.104 65.376 175.208 65.4 ;
     RECT  170.489 73.488 175.208 73.512 ;
     RECT  170.104 78.624 175.208 78.648 ;
     RECT  174.697 93.024 175.208 93.24 ;
     RECT  175.148 95.184 175.208 95.208 ;
     RECT  175.208 2.148 175.235 95.208 ;
     RECT  175.235 2.148 175.312 95.052 ;
     RECT  175.312 2.418 175.504 94.782 ;
     RECT  175.504 38.976 175.709 40.824 ;
     RECT  175.504 62.16 175.773 62.184 ;
     RECT  175.504 78.336 175.859 78.36 ;
     RECT  175.504 92.928 175.859 93.528 ;
     RECT  175.504 65.088 175.917 65.4 ;
     RECT  175.861 0.192 175.997 0.216 ;
     RECT  175.504 57.024 176.113 57.048 ;
     RECT  175.504 31.632 176.147 37.08 ;
     RECT  175.504 42.72 176.147 43.896 ;
     RECT  175.709 39.072 176.645 40.824 ;
     RECT  176.147 42.72 176.723 43.368 ;
     RECT  176.147 31.632 176.753 32.616 ;
     RECT  176.645 39.072 176.785 40.728 ;
     RECT  176.147 34.08 176.857 37.08 ;
     RECT  176.785 38.16 176.857 40.728 ;
     RECT  176.497 3.408 176.876 3.432 ;
     RECT  175.859 93.216 176.897 93.528 ;
     RECT  176.605 29.664 176.917 29.688 ;
     RECT  176.876 3.408 176.933 3.768 ;
     RECT  175.504 50.4 176.933 50.424 ;
     RECT  176.933 3.744 176.963 3.768 ;
     RECT  176.857 34.08 176.963 40.728 ;
     RECT  176.773 94.992 176.969 95.016 ;
     RECT  176.917 29.472 177.004 29.688 ;
     RECT  176.965 60.432 177.26 60.456 ;
     RECT  177.26 60.432 177.347 60.792 ;
     RECT  176.963 34.128 177.395 40.728 ;
     RECT  177.145 47.904 177.395 47.928 ;
     RECT  177.395 34.128 177.401 40.008 ;
     RECT  177.361 3.936 177.445 3.96 ;
     RECT  177.401 34.32 177.509 40.008 ;
     RECT  177.509 39.984 177.545 40.008 ;
     RECT  177.509 38.16 177.653 38.376 ;
     RECT  177.509 34.32 177.689 36.648 ;
     RECT  177.505 28.128 177.788 28.152 ;
     RECT  177.788 28.128 177.875 28.344 ;
     RECT  177.004 29.664 177.875 29.688 ;
     RECT  176.897 93.216 177.973 93.24 ;
     RECT  177.541 1.152 178.013 1.176 ;
     RECT  177.829 26.4 178.213 26.424 ;
     RECT  177.875 28.128 178.405 28.152 ;
     RECT  176.753 31.632 178.405 31.656 ;
     RECT  178.405 27.984 178.445 28.152 ;
     RECT  178.405 31.488 178.445 31.656 ;
     RECT  177.689 34.8 178.445 36.648 ;
     RECT  178.153 96.336 178.451 96.36 ;
     RECT  177.973 93.12 178.481 93.24 ;
     RECT  177.653 38.352 178.553 38.376 ;
     RECT  178.445 34.8 178.625 36.168 ;
     RECT  178.213 25.92 178.697 26.424 ;
     RECT  178.625 34.8 178.805 34.824 ;
     RECT  177.347 60.432 178.883 60.456 ;
     RECT  176.723 42.72 178.921 42.744 ;
     RECT  178.481 93.12 179.093 93.144 ;
     RECT  179.161 0.192 179.245 0.216 ;
     RECT  178.625 36.096 179.315 36.168 ;
     RECT  178.981 41.04 179.315 41.064 ;
     RECT  178.117 4.128 179.557 4.152 ;
     RECT  179.557 3.216 179.603 4.152 ;
     RECT  178.697 25.92 179.603 25.944 ;
     RECT  179.603 3.216 179.644 3.336 ;
     RECT  179.315 36.096 180.421 36.12 ;
     RECT  179.644 3.312 180.608 3.336 ;
     RECT  175.504 21.408 180.608 21.432 ;
     RECT  178.837 24.336 180.608 24.36 ;
     RECT  178.445 27.984 180.608 28.008 ;
     RECT  178.445 31.488 180.608 31.512 ;
     RECT  180.421 36.096 180.608 36.36 ;
     RECT  175.917 65.376 180.608 65.4 ;
     RECT  175.504 73.488 180.608 73.512 ;
     RECT  177.301 84.816 180.608 84.84 ;
     RECT  180.565 93.072 180.608 93.096 ;
     RECT  179.773 94.992 180.608 95.016 ;
     RECT  180.608 2.148 180.712 95.052 ;
     RECT  180.712 2.418 180.904 95.016 ;
     RECT  180.845 0.192 180.929 0.216 ;
     RECT  180.904 3.312 181.043 3.768 ;
     RECT  180.904 35.856 181.045 37.08 ;
     RECT  180.904 23.808 181.235 26.664 ;
     RECT  180.904 34.608 181.235 34.824 ;
     RECT  181.045 36.096 181.289 37.08 ;
     RECT  180.904 27.984 181.331 28.008 ;
     RECT  181.235 23.904 181.571 26.664 ;
     RECT  180.904 31.488 181.571 31.512 ;
     RECT  180.904 94.992 181.667 95.016 ;
     RECT  181.571 25.056 181.957 26.664 ;
     RECT  181.571 23.904 182.003 23.928 ;
     RECT  181.957 25.056 182.145 26.76 ;
     RECT  180.904 73.488 182.401 73.512 ;
     RECT  182.401 73.344 182.441 73.512 ;
     RECT  181.235 34.608 182.54 34.632 ;
     RECT  181.289 36.096 182.54 36.12 ;
     RECT  180.904 93.072 182.545 93.096 ;
     RECT  182.545 93.072 182.585 93.48 ;
     RECT  182.053 29.088 182.621 29.112 ;
     RECT  182.54 34.608 182.627 36.12 ;
     RECT  182.54 38.688 182.627 38.712 ;
     RECT  182.627 34.608 182.629 34.824 ;
     RECT  182.629 34.224 182.675 34.824 ;
     RECT  182.485 0.192 182.693 0.216 ;
     RECT  182.221 40.992 182.771 41.016 ;
     RECT  182.833 4.272 182.963 4.296 ;
     RECT  182.876 29.424 182.963 29.448 ;
     RECT  182.675 34.224 182.963 34.248 ;
     RECT  182.145 25.056 183.017 26.664 ;
     RECT  182.725 42.192 183.233 42.216 ;
     RECT  183.013 94.992 183.299 95.016 ;
     RECT  182.585 93.312 183.913 93.48 ;
     RECT  183.913 93.168 183.953 93.48 ;
     RECT  183.017 25.968 184.163 26.664 ;
     RECT  180.904 21.408 184.549 21.432 ;
     RECT  184.117 24.816 184.595 24.84 ;
     RECT  184.165 1.152 184.745 1.176 ;
     RECT  183.953 93.168 184.853 93.336 ;
     RECT  184.633 96.336 184.931 96.36 ;
     RECT  184.549 21.264 184.961 21.432 ;
     RECT  184.961 21.264 185.845 21.288 ;
     RECT  182.627 35.856 185.893 36.12 ;
     RECT  185.101 3.648 186.008 3.672 ;
     RECT  180.904 17.856 186.008 17.88 ;
     RECT  185.845 20.784 186.008 21.288 ;
     RECT  184.163 25.968 186.008 25.992 ;
     RECT  185.893 35.856 186.008 36.456 ;
     RECT  185.893 37.584 186.008 37.608 ;
     RECT  185.353 40.464 186.008 40.488 ;
     RECT  180.904 65.376 186.008 65.4 ;
     RECT  182.441 73.344 186.008 73.368 ;
     RECT  180.904 84.816 186.008 84.84 ;
     RECT  184.853 93.312 186.008 93.336 ;
     RECT  186.008 2.148 186.112 95.052 ;
     RECT  185.797 0.192 186.221 0.216 ;
     RECT  186.112 2.418 186.304 94.782 ;
     RECT  186.304 37.584 186.437 37.608 ;
     RECT  186.253 96.336 186.515 96.36 ;
     RECT  186.304 3.648 186.581 3.96 ;
     RECT  186.304 36.096 186.869 36.12 ;
     RECT  186.304 73.344 187.091 73.368 ;
     RECT  186.304 84.768 187.091 84.792 ;
     RECT  187.429 1.152 187.949 1.176 ;
     RECT  187.916 38.4 188.003 38.424 ;
     RECT  186.581 3.936 188.017 3.96 ;
     RECT  188.017 3.936 188.053 4.536 ;
     RECT  188.053 3.168 188.121 4.536 ;
     RECT  187.873 96.336 188.147 96.36 ;
     RECT  188.305 21.168 188.588 21.192 ;
     RECT  188.121 4.512 188.675 4.536 ;
     RECT  188.588 20.784 188.675 21.192 ;
     RECT  187.477 37.248 188.675 37.272 ;
     RECT  186.304 93.312 189.133 93.48 ;
     RECT  189.109 1.152 189.281 1.176 ;
     RECT  188.121 3.168 189.749 3.192 ;
     RECT  189.493 94.992 189.779 95.016 ;
     RECT  189.133 93.264 190.321 93.48 ;
     RECT  186.304 25.968 190.393 25.992 ;
     RECT  190.321 93.264 190.393 93.576 ;
     RECT  190.393 25.824 190.433 25.992 ;
     RECT  190.741 0.192 190.865 0.216 ;
     RECT  190.393 93.072 191.293 93.576 ;
     RECT  191.077 95.136 191.363 95.16 ;
     RECT  190.609 4.416 191.408 4.44 ;
     RECT  186.304 17.856 191.408 17.88 ;
     RECT  188.675 21.168 191.408 21.192 ;
     RECT  190.433 25.824 191.408 25.848 ;
     RECT  186.304 65.376 191.408 65.4 ;
     RECT  191.293 93.072 191.408 93.768 ;
     RECT  191.408 2.148 191.512 95.052 ;
     RECT  191.512 2.418 191.704 94.782 ;
     RECT  191.704 25.824 192.131 25.848 ;
     RECT  191.704 18.192 192.169 18.216 ;
     RECT  191.704 93.072 192.197 93.768 ;
     RECT  192.197 93.072 192.449 93.48 ;
     RECT  191.704 38.64 192.529 39.384 ;
     RECT  192.421 0.576 192.593 0.6 ;
     RECT  191.704 4.416 192.805 4.44 ;
     RECT  192.805 3.648 192.845 4.44 ;
     RECT  192.481 96.336 192.995 96.36 ;
     RECT  192.845 3.648 194.069 3.672 ;
     RECT  194.021 0.192 194.105 0.216 ;
     RECT  192.805 12.72 194.353 12.744 ;
     RECT  192.805 15.456 194.353 15.48 ;
     RECT  192.529 38.64 194.435 38.664 ;
     RECT  194.353 12.672 194.437 12.744 ;
     RECT  194.353 15.456 194.483 15.672 ;
     RECT  191.704 21.168 194.483 21.192 ;
     RECT  194.353 94.992 194.627 95.016 ;
     RECT  194.636 3.936 194.723 3.96 ;
     RECT  194.437 12.672 194.723 12.936 ;
     RECT  194.723 12.72 195.041 12.936 ;
     RECT  192.449 93.216 195.113 93.48 ;
     RECT  195.733 0.576 195.869 0.6 ;
     RECT  195.937 96.336 196.211 96.36 ;
     RECT  196.645 39.6 196.652 39.624 ;
     RECT  195.041 12.72 196.693 12.744 ;
     RECT  195.613 3.408 196.808 3.432 ;
     RECT  191.704 10.608 196.808 10.632 ;
     RECT  196.693 12.72 196.808 13.08 ;
     RECT  194.483 15.456 196.808 15.48 ;
     RECT  196.652 39.36 196.808 39.624 ;
     RECT  195.505 41.04 196.808 41.064 ;
     RECT  191.704 65.376 196.808 65.4 ;
     RECT  195.113 93.216 196.808 93.384 ;
     RECT  196.808 2.148 196.912 95.052 ;
     RECT  196.912 2.418 197.104 94.782 ;
     RECT  197.365 0.192 197.453 0.216 ;
     RECT  197.557 96.336 197.843 96.36 ;
     RECT  197.104 92.88 197.993 93.48 ;
     RECT  197.104 3.408 198.035 4.296 ;
     RECT  197.104 13.056 198.035 13.08 ;
     RECT  197.993 93.264 198.853 93.48 ;
     RECT  199.025 0.576 199.109 0.6 ;
     RECT  197.104 10.608 199.253 10.632 ;
     RECT  199.213 94.992 199.475 95.016 ;
     RECT  198.035 3.408 199.541 3.432 ;
     RECT  197.104 15.456 199.619 15.48 ;
     RECT  199.573 10.8 199.657 10.824 ;
     RECT  198.853 93.264 200.329 93.528 ;
     RECT  200.329 93.216 200.369 93.528 ;
     RECT  199.573 4.464 200.725 4.488 ;
     RECT  200.677 0.192 200.837 0.216 ;
     RECT  200.509 96.336 201.059 96.36 ;
     RECT  200.369 93.216 201.337 93.288 ;
     RECT  200.725 3.936 202.208 4.488 ;
     RECT  197.104 65.376 202.208 65.4 ;
     RECT  201.337 93.216 202.208 93.336 ;
     RECT  202.208 2.148 202.312 95.052 ;
     RECT  202.345 0.576 202.429 0.6 ;
     RECT  202.312 2.418 202.504 95.016 ;
     RECT  202.504 94.992 202.691 95.016 ;
     RECT  202.504 3.936 202.781 4.392 ;
     RECT  202.781 4.368 203.641 4.392 ;
     RECT  203.641 4.368 203.821 4.44 ;
     RECT  202.504 93.36 204.037 93.432 ;
     RECT  203.989 1.152 204.149 1.176 ;
     RECT  204.037 96.336 204.323 96.36 ;
     RECT  204.037 92.88 205.009 93.432 ;
     RECT  205.009 92.88 205.013 93.48 ;
     RECT  205.657 96.336 205.907 96.36 ;
     RECT  203.821 3.936 206.129 4.44 ;
     RECT  205.621 1.152 206.237 1.176 ;
     RECT  205.013 93.36 206.809 93.48 ;
     RECT  206.129 4.368 207.493 4.44 ;
     RECT  207.301 1.152 207.533 1.176 ;
     RECT  207.277 96.336 207.539 96.36 ;
     RECT  207.493 3.888 207.608 4.44 ;
     RECT  202.504 65.376 207.608 65.4 ;
     RECT  206.809 93.072 207.608 93.48 ;
     RECT  207.608 2.148 207.712 95.052 ;
     RECT  207.712 2.418 207.904 94.782 ;
     RECT  208.933 0.576 209.017 0.6 ;
     RECT  208.897 94.992 209.171 95.016 ;
     RECT  207.904 3.888 209.333 4.44 ;
     RECT  209.333 3.888 209.617 4.344 ;
     RECT  207.904 93.072 210.301 93.432 ;
     RECT  210.301 93.072 210.413 93.48 ;
     RECT  210.581 0.192 210.665 0.216 ;
     RECT  210.413 93.072 210.665 93.288 ;
     RECT  210.445 94.992 210.755 95.016 ;
     RECT  209.617 3.552 211.429 4.344 ;
     RECT  211.429 3.552 211.475 4.68 ;
     RECT  210.665 93.264 211.597 93.288 ;
     RECT  211.475 3.552 211.601 3.576 ;
     RECT  211.597 93.264 211.633 93.48 ;
     RECT  207.904 65.376 211.724 65.4 ;
     RECT  211.724 65.376 211.811 65.544 ;
     RECT  211.633 92.928 211.811 93.48 ;
     RECT  211.811 65.376 211.997 65.4 ;
     RECT  212.245 0.192 212.501 0.216 ;
     RECT  211.475 4.656 213.008 4.68 ;
     RECT  211.811 93.264 213.008 93.48 ;
     RECT  212.137 94.992 213.008 95.016 ;
     RECT  213.008 2.148 213.112 95.052 ;
     RECT  213.112 2.418 213.304 95.016 ;
     RECT  213.304 94.992 214.019 95.016 ;
     RECT  213.925 0.192 214.085 0.216 ;
     RECT  213.304 4.656 214.157 4.68 ;
     RECT  213.304 93.312 214.517 93.336 ;
     RECT  215.557 0.192 215.813 0.216 ;
     RECT  215.557 95.76 215.813 95.784 ;
    LAYER M5 ;
     RECT  10.512 0.144 10.536 0.227 ;
     RECT  17.136 0.144 17.16 0.227 ;
     RECT  20.448 0.144 20.472 0.227 ;
     RECT  22.08 0.144 22.104 0.227 ;
     RECT  28.704 0.144 28.728 0.227 ;
     RECT  30.336 0.144 30.36 0.227 ;
     RECT  32.016 0.144 32.04 0.227 ;
     RECT  33.648 0.144 33.672 0.227 ;
     RECT  35.328 0.144 35.352 0.227 ;
     RECT  43.584 0.144 43.608 0.227 ;
     RECT  45.216 0.144 45.24 0.227 ;
     RECT  50.208 0.144 50.232 0.227 ;
     RECT  56.832 0.144 56.856 0.227 ;
     RECT  61.776 0.144 61.8 0.227 ;
     RECT  63.408 0.144 63.432 0.227 ;
     RECT  65.088 0.144 65.112 0.227 ;
     RECT  68.4 0.144 68.424 0.227 ;
     RECT  73.344 0.144 73.368 0.227 ;
     RECT  75.024 0.144 75.048 0.227 ;
     RECT  81.6 0.144 81.624 0.227 ;
     RECT  83.28 0.144 83.304 0.227 ;
     RECT  89.904 0.144 89.928 0.227 ;
     RECT  93.216 0.144 93.24 0.227 ;
     RECT  94.848 0.144 94.872 0.227 ;
     RECT  99.792 0.144 99.816 0.227 ;
     RECT  101.472 0.144 101.496 0.227 ;
     RECT  114.672 0.144 114.696 0.227 ;
     RECT  116.352 0.144 116.376 0.227 ;
     RECT  117.984 0.144 118.008 0.227 ;
     RECT  122.976 0.144 123 0.227 ;
     RECT  131.232 0.144 131.256 0.227 ;
     RECT  132.864 0.144 132.888 0.227 ;
     RECT  134.544 0.144 134.568 0.227 ;
     RECT  146.112 0.144 146.136 0.227 ;
     RECT  147.792 0.144 147.816 0.227 ;
     RECT  151.056 0.144 151.08 0.227 ;
     RECT  157.68 0.144 157.704 0.227 ;
     RECT  159.36 0.144 159.384 0.227 ;
     RECT  160.992 0.144 161.016 0.227 ;
     RECT  165.984 0.144 166.008 0.227 ;
     RECT  175.872 0.144 175.896 0.227 ;
     RECT  179.184 0.144 179.208 0.227 ;
     RECT  180.864 0.144 180.888 0.227 ;
     RECT  182.496 0.144 182.52 0.227 ;
     RECT  185.808 0.144 185.832 0.227 ;
     RECT  190.752 0.144 190.776 0.227 ;
     RECT  194.064 0.144 194.088 0.227 ;
     RECT  197.376 0.144 197.4 0.227 ;
     RECT  200.688 0.144 200.712 0.227 ;
     RECT  210.624 0.144 210.648 0.227 ;
     RECT  212.256 0.144 212.28 0.227 ;
     RECT  213.936 0.144 213.96 0.227 ;
     RECT  215.568 0.144 215.592 0.227 ;
     RECT  5.568 0.144 5.592 0.611 ;
     RECT  8.832 0.144 8.856 0.611 ;
     RECT  27.024 0.144 27.048 0.611 ;
     RECT  79.968 0.144 79.992 0.611 ;
     RECT  96.528 0.144 96.552 0.611 ;
     RECT  98.16 0.144 98.184 0.611 ;
     RECT  111.408 0.144 111.432 0.611 ;
     RECT  113.04 0.144 113.064 0.611 ;
     RECT  144.48 0.144 144.504 0.611 ;
     RECT  162.672 0.144 162.696 0.611 ;
     RECT  164.304 0.144 164.328 0.611 ;
     RECT  192.432 0.144 192.456 0.611 ;
     RECT  195.744 0.144 195.768 0.611 ;
     RECT  199.056 0.144 199.08 0.611 ;
     RECT  202.368 0.144 202.392 0.611 ;
     RECT  208.944 0.144 208.968 0.611 ;
     RECT  7.2 0.144 7.224 1.187 ;
     RECT  12.144 0.144 12.168 1.187 ;
     RECT  13.824 0.144 13.848 1.187 ;
     RECT  15.456 0.144 15.48 1.187 ;
     RECT  18.768 0.144 18.792 1.187 ;
     RECT  23.76 0.144 23.784 1.187 ;
     RECT  25.392 0.144 25.416 1.187 ;
     RECT  38.64 0.144 38.664 1.187 ;
     RECT  41.952 0.144 41.976 1.187 ;
     RECT  46.896 0.144 46.92 1.187 ;
     RECT  48.528 0.144 48.552 1.187 ;
     RECT  53.52 0.144 53.544 1.187 ;
     RECT  55.152 0.144 55.176 1.187 ;
     RECT  60.144 0.144 60.168 1.187 ;
     RECT  66.72 0.144 66.744 1.187 ;
     RECT  70.032 0.144 70.056 1.187 ;
     RECT  71.712 0.144 71.736 1.187 ;
     RECT  76.656 0.144 76.68 1.187 ;
     RECT  78.336 0.144 78.36 1.187 ;
     RECT  84.912 0.144 84.936 1.187 ;
     RECT  86.592 0.144 86.616 1.187 ;
     RECT  88.224 0.144 88.248 1.187 ;
     RECT  91.536 0.144 91.56 1.187 ;
     RECT  103.104 0.144 103.128 1.187 ;
     RECT  104.784 0.144 104.808 1.187 ;
     RECT  106.416 0.144 106.44 1.187 ;
     RECT  108.096 0.144 108.12 1.187 ;
     RECT  109.728 0.144 109.752 1.187 ;
     RECT  119.664 0.144 119.688 1.187 ;
     RECT  124.608 0.144 124.632 1.187 ;
     RECT  126.288 0.144 126.312 1.187 ;
     RECT  127.92 0.144 127.944 1.187 ;
     RECT  129.6 0.144 129.624 1.187 ;
     RECT  136.176 0.144 136.2 1.187 ;
     RECT  137.856 0.144 137.88 1.187 ;
     RECT  139.488 0.144 139.512 1.187 ;
     RECT  141.168 0.144 141.192 1.187 ;
     RECT  149.424 0.144 149.448 1.187 ;
     RECT  152.736 0.144 152.76 1.187 ;
     RECT  154.368 0.144 154.392 1.187 ;
     RECT  156.048 0.144 156.072 1.187 ;
     RECT  167.616 0.144 167.64 1.187 ;
     RECT  169.248 0.144 169.272 1.187 ;
     RECT  170.928 0.144 170.952 1.187 ;
     RECT  172.56 0.144 172.584 1.187 ;
     RECT  174.24 0.144 174.264 1.187 ;
     RECT  177.552 0.144 177.576 1.187 ;
     RECT  184.176 0.144 184.2 1.187 ;
     RECT  187.44 0.144 187.464 1.187 ;
     RECT  189.12 0.144 189.144 1.187 ;
     RECT  204 0.144 204.024 1.187 ;
     RECT  205.632 0.144 205.656 1.187 ;
     RECT  207.312 0.144 207.336 1.187 ;
     RECT  36.96 0.144 36.984 1.763 ;
     RECT  51.84 0.144 51.864 1.763 ;
     RECT  58.464 0.144 58.488 1.763 ;
     RECT  40.272 0.144 40.296 2.137 ;
     RECT  121.296 0.144 121.32 2.137 ;
     RECT  142.8 0.144 142.824 2.137 ;
     RECT  2.4 2.137 2.52 2.151 ;
     RECT  7.8 2.137 7.92 2.151 ;
     RECT  13.2 2.137 13.32 2.151 ;
     RECT  18.6 2.137 18.72 2.151 ;
     RECT  24 2.137 24.12 2.151 ;
     RECT  29.4 2.137 29.52 2.151 ;
     RECT  34.8 2.137 34.92 2.151 ;
     RECT  40.2 2.137 40.32 2.151 ;
     RECT  45.6 2.137 45.72 2.151 ;
     RECT  56.4 2.137 56.52 2.151 ;
     RECT  61.8 2.137 61.92 2.151 ;
     RECT  67.2 2.137 67.32 2.151 ;
     RECT  72.6 2.137 72.72 2.151 ;
     RECT  78 2.137 78.12 2.151 ;
     RECT  83.4 2.137 83.52 2.151 ;
     RECT  88.8 2.137 88.92 2.151 ;
     RECT  94.2 2.137 94.32 2.151 ;
     RECT  99.6 2.137 99.72 2.151 ;
     RECT  105 2.137 105.12 2.151 ;
     RECT  110.4 2.137 110.52 2.151 ;
     RECT  115.8 2.137 115.92 2.151 ;
     RECT  121.2 2.137 121.32 2.151 ;
     RECT  126.6 2.137 126.72 2.151 ;
     RECT  132 2.137 132.12 2.151 ;
     RECT  137.4 2.137 137.52 2.151 ;
     RECT  142.8 2.137 142.92 2.151 ;
     RECT  148.2 2.137 148.32 2.151 ;
     RECT  153.6 2.137 153.72 2.151 ;
     RECT  159 2.137 159.12 2.151 ;
     RECT  164.4 2.137 164.52 2.151 ;
     RECT  169.8 2.137 169.92 2.151 ;
     RECT  175.2 2.137 175.32 2.151 ;
     RECT  180.6 2.137 180.72 2.151 ;
     RECT  186 2.137 186.12 2.151 ;
     RECT  191.4 2.137 191.52 2.151 ;
     RECT  196.8 2.137 196.92 2.151 ;
     RECT  202.2 2.137 202.32 2.151 ;
     RECT  207.6 2.137 207.72 2.151 ;
     RECT  213 2.137 213.12 2.151 ;
     RECT  72.6 2.151 72.912 3.205 ;
     RECT  94.2 2.151 94.512 3.205 ;
     RECT  169.8 2.151 170.112 3.205 ;
     RECT  45.6 2.151 45.912 3.301 ;
     RECT  180.6 2.151 180.912 3.301 ;
     RECT  7.8 2.151 8.112 3.349 ;
     RECT  40.2 2.151 40.512 3.349 ;
     RECT  148.2 2.151 148.512 3.349 ;
     RECT  159 2.151 159.312 3.349 ;
     RECT  56.4 2.151 56.712 3.397 ;
     RECT  83.4 2.151 83.712 3.397 ;
     RECT  164.4 2.151 164.712 3.397 ;
     RECT  169.632 3.205 170.112 3.397 ;
     RECT  196.8 2.151 197.112 3.397 ;
     RECT  186 2.151 186.312 3.637 ;
     RECT  110.4 2.151 110.712 3.685 ;
     RECT  137.4 2.151 137.712 3.685 ;
     RECT  153.6 2.151 153.912 3.685 ;
     RECT  67.2 2.151 67.512 3.733 ;
     RECT  72.6 3.205 73.464 3.733 ;
     RECT  51 2.137 51.312 3.829 ;
     RECT  56.4 3.397 57.288 3.925 ;
     RECT  61.8 2.151 62.112 3.925 ;
     RECT  115.8 2.151 116.112 3.925 ;
     RECT  121.2 2.151 121.512 3.925 ;
     RECT  147.6 3.349 148.512 3.925 ;
     RECT  162 3.733 162.024 3.925 ;
     RECT  163.536 3.397 164.712 3.925 ;
     RECT  166.032 3.397 166.056 3.925 ;
     RECT  167.184 3.733 167.208 3.925 ;
     RECT  172.512 3.205 172.536 3.925 ;
     RECT  176.928 3.733 176.952 3.925 ;
     RECT  7.8 3.349 8.616 3.971 ;
     RECT  188.064 3.157 188.088 3.971 ;
     RECT  97.968 3.253 97.992 4.115 ;
     RECT  93.6 3.205 94.512 4.117 ;
     RECT  92.88 4.117 94.512 4.163 ;
     RECT  36.624 3.925 36.648 4.261 ;
     RECT  78 2.151 78.312 4.261 ;
     RECT  126.6 2.151 126.912 4.261 ;
     RECT  175.2 2.151 175.512 4.405 ;
     RECT  29.4 2.151 29.712 4.501 ;
     RECT  34.8 2.151 35.112 4.501 ;
     RECT  45.6 3.301 46.008 4.501 ;
     RECT  49.2 3.925 49.224 4.501 ;
     RECT  50.88 3.829 51.312 4.501 ;
     RECT  55.104 3.733 55.128 4.501 ;
     RECT  56.4 3.925 57.864 4.501 ;
     RECT  67.2 3.733 68.232 4.501 ;
     RECT  88.8 2.151 89.112 4.501 ;
     RECT  99.6 2.151 99.912 4.501 ;
     RECT  113.088 3.157 113.112 4.501 ;
     RECT  142.8 2.151 143.112 4.501 ;
     RECT  161.376 3.925 162.024 4.501 ;
     RECT  167.184 3.925 167.496 4.501 ;
     RECT  113.088 4.501 113.688 4.547 ;
     RECT  211.44 3.685 211.464 4.691 ;
     RECT  99.6 4.501 100.296 5.987 ;
     RECT  29.4 4.501 29.832 9.301 ;
     RECT  92.88 4.163 92.904 10.453 ;
     RECT  92.688 10.453 92.904 10.499 ;
     RECT  191.4 2.151 191.712 10.597 ;
     RECT  99.6 5.987 100.008 10.643 ;
     RECT  29.4 9.301 29.88 10.693 ;
     RECT  194.688 3.925 194.712 12.661 ;
     RECT  194.4 12.661 194.712 12.707 ;
     RECT  78 4.261 78.936 12.757 ;
     RECT  80.352 3.685 80.376 12.757 ;
     RECT  22.56 4.357 22.584 12.803 ;
     RECT  90.288 10.645 90.312 12.901 ;
     RECT  90.096 12.901 90.312 12.947 ;
     RECT  196.8 3.397 198.024 13.045 ;
     RECT  196.704 13.045 198.024 13.091 ;
     RECT  82.128 3.685 82.152 13.523 ;
     RECT  88.704 4.501 89.112 13.621 ;
     RECT  90.096 12.947 90.12 13.621 ;
     RECT  91.296 3.925 91.32 13.669 ;
     RECT  91.296 13.669 91.512 13.715 ;
     RECT  85.68 4.213 85.704 14.053 ;
     RECT  78 12.757 80.376 14.099 ;
     RECT  85.536 14.053 85.704 14.099 ;
     RECT  74.88 3.733 74.904 14.197 ;
     RECT  83.4 3.397 83.88 14.197 ;
     RECT  85.536 14.099 85.56 14.197 ;
     RECT  113.664 4.547 113.688 14.245 ;
     RECT  113.664 14.245 113.784 14.291 ;
     RECT  115.8 3.925 116.232 14.725 ;
     RECT  115.2 14.725 116.232 14.771 ;
     RECT  70.32 3.925 70.344 14.773 ;
     RECT  71.856 3.733 73.464 14.773 ;
     RECT  153.216 3.685 154.776 14.773 ;
     RECT  88.704 13.621 90.12 15.011 ;
     RECT  96 6.181 96.024 15.059 ;
     RECT  74.88 14.197 75.432 15.061 ;
     RECT  76.752 3.301 76.776 15.061 ;
     RECT  78 14.099 79.32 15.253 ;
     RECT  80.352 14.099 80.376 15.253 ;
     RECT  74.88 15.061 76.776 15.347 ;
     RECT  88.704 15.011 90.072 15.347 ;
     RECT  70.32 14.773 73.464 15.349 ;
     RECT  69.504 15.349 73.464 15.491 ;
     RECT  199.584 4.453 199.608 15.491 ;
     RECT  78 15.253 80.376 15.587 ;
     RECT  112.56 14.821 112.584 15.589 ;
     RECT  112.32 15.589 112.584 15.635 ;
     RECT  153.216 14.773 154.968 15.683 ;
     RECT  145.968 4.501 145.992 15.733 ;
     RECT  134.832 3.685 134.856 15.877 ;
     RECT  141.264 3.733 141.288 15.877 ;
     RECT  134.688 15.877 134.856 15.923 ;
     RECT  141.264 15.877 141.336 15.973 ;
     RECT  69.504 15.491 70.344 16.019 ;
     RECT  139.488 3.925 139.512 16.021 ;
     RECT  141.264 15.973 141.384 16.115 ;
     RECT  66.288 4.501 68.232 16.163 ;
     RECT  72.096 15.491 73.464 16.163 ;
     RECT  91.392 13.715 91.512 16.165 ;
     RECT  76.032 15.347 76.776 16.259 ;
     RECT  79.968 15.587 80.376 16.259 ;
     RECT  132 2.151 132.312 16.261 ;
     RECT  133.536 4.501 133.56 16.261 ;
     RECT  145.968 15.733 146.328 16.307 ;
     RECT  36.624 4.261 37.08 16.357 ;
     RECT  59.424 3.925 59.448 16.405 ;
     RECT  59.424 16.405 59.544 16.451 ;
     RECT  29.4 10.693 29.928 16.501 ;
     RECT  78 15.587 78.408 16.547 ;
     RECT  141.264 16.115 141.336 16.547 ;
     RECT  61.488 3.925 62.112 16.741 ;
     RECT  147.6 3.925 149.064 16.741 ;
     RECT  128.16 3.685 128.184 16.787 ;
     RECT  147.6 16.741 149.88 16.787 ;
     RECT  27.312 4.405 27.336 16.835 ;
     RECT  132 16.261 133.56 16.835 ;
     RECT  112.32 15.635 112.344 16.883 ;
     RECT  66.432 16.163 68.232 17.029 ;
     RECT  87.552 3.301 87.576 17.029 ;
     RECT  132 16.835 132.312 17.029 ;
     RECT  133.536 16.835 133.56 17.029 ;
     RECT  87.264 17.029 87.576 17.075 ;
     RECT  110.4 3.685 110.904 17.123 ;
     RECT  61.152 16.741 62.112 17.171 ;
     RECT  70.32 16.019 70.344 17.171 ;
     RECT  83.4 14.197 85.56 17.171 ;
     RECT  145.968 16.307 146.088 17.317 ;
     RECT  83.4 17.171 83.88 17.363 ;
     RECT  85.44 17.171 85.56 17.363 ;
     RECT  145.44 17.317 146.088 17.363 ;
     RECT  88.704 15.347 89.112 17.459 ;
     RECT  76.032 16.259 76.392 17.555 ;
     RECT  141.264 16.547 141.288 17.557 ;
     RECT  140.784 17.557 141.288 17.603 ;
     RECT  61.296 17.171 62.112 17.605 ;
     RECT  63.12 3.829 63.144 17.605 ;
     RECT  78 16.547 78.312 17.605 ;
     RECT  82.176 13.621 82.2 17.605 ;
     RECT  83.4 17.363 83.712 17.605 ;
     RECT  61.296 17.605 63.144 17.651 ;
     RECT  82.176 17.605 83.712 17.651 ;
     RECT  66.432 17.029 68.376 17.699 ;
     RECT  76.32 17.555 76.392 17.699 ;
     RECT  91.2 16.165 91.512 17.699 ;
     RECT  74.88 15.347 74.904 17.843 ;
     RECT  139.2 16.021 139.512 17.843 ;
     RECT  136.176 3.925 136.2 17.845 ;
     RECT  180.6 3.301 181.032 17.845 ;
     RECT  135.888 17.845 136.2 17.891 ;
     RECT  137.4 3.685 137.976 17.989 ;
     RECT  137.088 17.989 137.976 18.035 ;
     RECT  131.472 17.029 132.312 18.133 ;
     RECT  133.536 17.029 133.656 18.179 ;
     RECT  66.432 17.699 67.896 18.373 ;
     RECT  91.488 17.699 91.512 18.373 ;
     RECT  92.688 10.499 92.712 18.373 ;
     RECT  144.288 3.733 144.312 18.373 ;
     RECT  145.44 17.363 145.464 18.373 ;
     RECT  144.288 18.373 145.464 18.419 ;
     RECT  78 17.605 78.408 18.421 ;
     RECT  121.2 3.925 121.608 18.563 ;
     RECT  72.096 16.163 73.08 18.565 ;
     RECT  125.088 3.733 125.112 18.613 ;
     RECT  129.744 4.261 129.768 18.613 ;
     RECT  124.848 18.613 125.112 18.659 ;
     RECT  129.744 18.613 129.96 18.659 ;
     RECT  72 18.565 73.08 18.709 ;
     RECT  87.264 17.075 87.288 18.757 ;
     RECT  88.8 17.459 89.112 18.757 ;
     RECT  87.264 18.757 87.672 18.803 ;
     RECT  137.088 18.035 137.712 18.851 ;
     RECT  140.784 17.603 140.808 18.851 ;
     RECT  144.72 18.419 145.464 18.995 ;
     RECT  75.168 18.133 75.192 18.997 ;
     RECT  76.32 17.699 76.344 18.997 ;
     RECT  123.12 4.501 123.144 19.043 ;
     RECT  91.488 18.373 92.712 19.045 ;
     RECT  64.8 3.925 64.824 19.139 ;
     RECT  151.056 3.925 151.08 19.141 ;
     RECT  156.384 16.789 156.408 19.141 ;
     RECT  157.44 3.925 157.464 19.141 ;
     RECT  151.056 19.141 151.416 19.187 ;
     RECT  156.384 19.141 157.464 19.187 ;
     RECT  61.296 17.651 62.952 19.285 ;
     RECT  45.504 4.501 46.008 19.333 ;
     RECT  47.232 4.501 47.256 19.333 ;
     RECT  80.352 16.259 80.376 19.333 ;
     RECT  82.512 17.651 83.712 19.333 ;
     RECT  87.648 18.803 87.672 19.333 ;
     RECT  88.8 18.757 89.208 19.333 ;
     RECT  119.952 4.501 119.976 19.333 ;
     RECT  121.2 18.563 121.512 19.333 ;
     RECT  147.6 16.787 148.512 19.333 ;
     RECT  80.208 19.333 80.376 19.379 ;
     RECT  156.72 19.187 157.464 19.379 ;
     RECT  72 18.709 73.944 19.381 ;
     RECT  65.952 18.373 67.896 19.523 ;
     RECT  113.76 14.291 113.784 19.523 ;
     RECT  87.648 19.333 89.208 19.621 ;
     RECT  124.848 18.659 124.872 19.621 ;
     RECT  126.432 4.261 126.912 19.621 ;
     RECT  133.632 18.179 133.656 19.669 ;
     RECT  134.688 15.923 134.712 19.669 ;
     RECT  91.008 19.045 92.712 19.763 ;
     RECT  75.168 18.997 76.344 19.765 ;
     RECT  77.904 18.421 78.408 19.765 ;
     RECT  119.952 19.333 121.512 19.765 ;
     RECT  119.136 19.765 121.512 19.811 ;
     RECT  133.632 19.669 134.712 19.811 ;
     RECT  149.856 16.787 149.88 19.811 ;
     RECT  45.504 19.333 47.256 19.909 ;
     RECT  75.168 19.765 78.408 20.003 ;
     RECT  131.472 18.133 132.408 20.003 ;
     RECT  128.208 16.837 128.232 20.051 ;
     RECT  82.464 19.333 83.712 20.053 ;
     RECT  85.44 17.363 85.464 20.053 ;
     RECT  61.2 19.285 62.952 20.099 ;
     RECT  144.72 18.995 145.416 20.149 ;
     RECT  159 3.349 159.432 20.149 ;
     RECT  160.56 4.501 162.024 20.149 ;
     RECT  144.72 20.149 145.896 20.195 ;
     RECT  117.744 3.925 117.768 20.245 ;
     RECT  117.408 20.245 117.768 20.291 ;
     RECT  124.848 19.621 126.912 20.339 ;
     RECT  139.2 17.843 139.272 20.437 ;
     RECT  120.144 19.811 121.512 20.483 ;
     RECT  139.056 20.437 139.272 20.483 ;
     RECT  54.432 4.501 57.864 20.485 ;
     RECT  59.52 16.451 59.544 20.485 ;
     RECT  72 19.381 74.04 20.485 ;
     RECT  112.368 19.477 112.392 20.579 ;
     RECT  76.08 20.003 78.408 20.581 ;
     RECT  81.888 20.053 83.712 20.581 ;
     RECT  85.44 20.053 86.04 20.581 ;
     RECT  137.4 18.851 137.712 20.677 ;
     RECT  54.432 20.485 59.544 20.725 ;
     RECT  61.2 20.099 62.328 20.725 ;
     RECT  142.56 4.501 143.112 20.773 ;
     RECT  144.72 20.195 144.744 20.819 ;
     RECT  129.936 18.659 129.96 20.965 ;
     RECT  129.84 20.965 129.96 21.011 ;
     RECT  64.032 19.381 64.056 21.013 ;
     RECT  65.952 19.523 67.512 21.013 ;
     RECT  131.472 20.003 132.312 21.013 ;
     RECT  115.2 14.771 116.112 21.107 ;
     RECT  147.264 19.333 148.512 21.109 ;
     RECT  91.008 19.763 92.664 21.155 ;
     RECT  117.408 20.291 117.432 21.155 ;
     RECT  133.632 19.811 133.752 21.155 ;
     RECT  156.72 19.379 157.32 21.155 ;
     RECT  151.392 19.187 151.416 21.203 ;
     RECT  194.4 12.707 194.472 21.203 ;
     RECT  65.568 21.013 67.512 21.253 ;
     RECT  140.736 19.333 140.76 21.253 ;
     RECT  63.408 21.013 64.056 21.299 ;
     RECT  54.432 20.725 62.328 21.301 ;
     RECT  63.408 21.299 63.912 21.301 ;
     RECT  68.832 21.157 68.856 21.301 ;
     RECT  157.296 21.155 157.32 21.301 ;
     RECT  153.216 15.683 154.728 21.349 ;
     RECT  65.472 21.253 67.512 21.397 ;
     RECT  68.736 21.301 68.856 21.397 ;
     RECT  87.648 19.621 89.736 21.397 ;
     RECT  91.008 21.155 91.8 21.397 ;
     RECT  119.136 19.811 119.16 21.397 ;
     RECT  140.736 21.253 141.576 21.397 ;
     RECT  142.56 20.773 143.544 21.397 ;
     RECT  169.632 3.397 171 21.397 ;
     RECT  172.032 3.925 172.536 21.397 ;
     RECT  147.264 21.109 148.728 21.443 ;
     RECT  117.312 21.253 117.336 21.491 ;
     RECT  87.648 21.397 91.8 21.539 ;
     RECT  118.56 21.397 119.16 21.539 ;
     RECT  140.736 21.397 143.544 21.539 ;
     RECT  131.472 21.013 132.648 21.637 ;
     RECT  87.648 21.539 89.736 21.683 ;
     RECT  147.264 21.443 148.632 21.683 ;
     RECT  80.208 19.379 80.328 21.685 ;
     RECT  65.472 21.397 68.856 21.781 ;
     RECT  72 20.485 74.712 21.923 ;
     RECT  79.872 21.685 80.328 21.923 ;
     RECT  125.712 20.339 126.912 21.923 ;
     RECT  65.472 21.781 68.904 22.019 ;
     RECT  70.128 18.997 70.152 22.069 ;
     RECT  145.872 20.195 145.896 22.117 ;
     RECT  152.784 21.349 154.728 22.163 ;
     RECT  72 21.923 74.472 22.165 ;
     RECT  81.888 20.581 86.04 22.213 ;
     RECT  36.624 16.357 38.04 22.259 ;
     RECT  123.696 20.293 123.72 22.259 ;
     RECT  139.056 20.483 139.224 22.259 ;
     RECT  157.296 21.301 157.704 22.259 ;
     RECT  157.584 22.259 157.704 22.309 ;
     RECT  159 20.149 162.024 22.309 ;
     RECT  114.144 22.213 114.168 22.355 ;
     RECT  81.888 22.213 86.712 22.453 ;
     RECT  135.888 17.891 135.912 22.453 ;
     RECT  110.4 17.123 110.808 22.499 ;
     RECT  54.432 21.301 63.912 22.501 ;
     RECT  94.2 4.163 94.512 22.501 ;
     RECT  139.152 22.259 139.224 22.547 ;
     RECT  76.08 20.581 78.696 22.597 ;
     RECT  44.112 3.925 44.136 22.645 ;
     RECT  139.2 22.547 139.224 22.645 ;
     RECT  140.736 21.539 141.576 22.645 ;
     RECT  147.984 21.683 148.632 22.645 ;
     RECT  32.112 3.205 32.136 22.691 ;
     RECT  142.56 21.539 143.544 22.693 ;
     RECT  36.864 22.259 38.04 22.741 ;
     RECT  39.024 3.925 39.048 22.741 ;
     RECT  75.744 22.597 78.696 22.741 ;
     RECT  81.792 22.453 86.712 22.741 ;
     RECT  109.296 22.597 109.32 22.741 ;
     RECT  110.4 22.499 110.712 22.741 ;
     RECT  36.864 22.741 39.048 22.787 ;
     RECT  54.432 22.501 64.2 22.789 ;
     RECT  54.432 22.789 64.344 22.835 ;
     RECT  69.696 22.069 70.152 22.835 ;
     RECT  129.84 21.011 129.864 22.835 ;
     RECT  133.728 21.155 133.752 22.835 ;
     RECT  152.784 22.163 154.488 22.835 ;
     RECT  131.088 21.637 132.648 22.883 ;
     RECT  94.2 22.501 94.632 22.885 ;
     RECT  91.008 21.539 91.8 22.931 ;
     RECT  64.32 22.835 64.344 22.933 ;
     RECT  64.32 22.933 64.44 22.979 ;
     RECT  65.472 22.019 68.472 22.981 ;
     RECT  122.544 20.437 122.568 23.027 ;
     RECT  64.416 22.979 64.44 23.077 ;
     RECT  65.472 22.981 68.904 23.077 ;
     RECT  113.472 22.741 113.496 23.125 ;
     RECT  115.8 21.107 116.112 23.125 ;
     RECT  64.416 23.077 68.904 23.171 ;
     RECT  145.872 22.117 146.232 23.171 ;
     RECT  123.744 22.741 124.248 23.173 ;
     RECT  150.432 22.789 150.456 23.219 ;
     RECT  123.744 23.173 124.392 23.221 ;
     RECT  125.952 21.923 126.912 23.221 ;
     RECT  64.848 23.171 68.904 23.267 ;
     RECT  117.888 23.077 117.912 23.315 ;
     RECT  142.56 22.693 143.64 23.315 ;
     RECT  32.16 22.741 32.184 23.317 ;
     RECT  33.552 3.925 33.576 23.317 ;
     RECT  111.888 23.125 111.912 23.317 ;
     RECT  115.632 23.125 116.112 23.317 ;
     RECT  120.144 20.483 120.168 23.317 ;
     RECT  121.2 20.483 121.512 23.317 ;
     RECT  123.744 23.221 126.912 23.317 ;
     RECT  128.208 21.109 128.232 23.317 ;
     RECT  135.696 22.453 135.912 23.317 ;
     RECT  137.4 20.677 137.832 23.317 ;
     RECT  65.472 23.267 68.904 23.363 ;
     RECT  29.4 16.501 29.976 23.411 ;
     RECT  157.584 22.309 162.024 23.557 ;
     RECT  147.504 22.645 148.632 23.605 ;
     RECT  135.168 23.317 137.832 23.701 ;
     RECT  139.2 22.645 141.576 23.701 ;
     RECT  147.504 23.605 148.872 23.747 ;
     RECT  119.136 21.539 119.16 23.749 ;
     RECT  120.144 23.317 122.04 23.749 ;
     RECT  123.744 23.317 128.52 23.749 ;
     RECT  142.8 23.315 143.64 23.749 ;
     RECT  49.2 4.501 51.312 23.797 ;
     RECT  52.416 4.501 52.44 23.797 ;
     RECT  29.4 23.411 29.88 23.843 ;
     RECT  119.136 23.749 122.04 23.845 ;
     RECT  132 22.883 132.552 23.893 ;
     RECT  135.168 23.701 141.576 23.893 ;
     RECT  180.6 17.845 181.56 23.893 ;
     RECT  182.928 4.261 182.952 23.893 ;
     RECT  157.536 23.557 162.024 24.133 ;
     RECT  157.536 24.133 162.216 24.181 ;
     RECT  163.536 3.925 166.056 24.181 ;
     RECT  43.584 22.645 44.136 24.323 ;
     RECT  179.568 3.205 179.592 24.325 ;
     RECT  43.824 24.323 44.136 24.469 ;
     RECT  45.504 19.909 47.4 24.469 ;
     RECT  87.936 21.683 89.736 24.517 ;
     RECT  91.008 22.931 91.368 24.517 ;
     RECT  145.008 23.317 145.032 24.517 ;
     RECT  146.208 23.171 146.232 24.517 ;
     RECT  54.432 22.835 63.288 24.755 ;
     RECT  184.56 21.253 184.584 24.805 ;
     RECT  184.128 24.805 184.584 24.851 ;
     RECT  32.16 23.317 33.576 24.899 ;
     RECT  43.824 24.469 47.4 24.899 ;
     RECT  130.464 23.173 131.016 25.045 ;
     RECT  132 23.893 141.576 25.045 ;
     RECT  142.8 23.749 143.928 25.045 ;
     RECT  147.504 23.747 148.512 25.045 ;
     RECT  149.76 23.749 149.784 25.045 ;
     RECT  33.552 24.899 33.576 25.139 ;
     RECT  36.864 22.787 38.808 25.139 ;
     RECT  43.824 24.899 46.92 25.139 ;
     RECT  31.104 4.501 31.128 25.669 ;
     RECT  32.16 24.899 32.184 25.669 ;
     RECT  31.104 25.669 32.184 25.715 ;
     RECT  36.864 25.139 38.76 25.715 ;
     RECT  43.824 25.139 46.296 25.715 ;
     RECT  94.2 22.885 94.728 25.859 ;
     RECT  191.4 10.597 192.12 25.859 ;
     RECT  36.864 25.715 37.704 25.907 ;
     RECT  176.928 3.925 177.432 25.909 ;
     RECT  178.848 24.325 179.592 25.909 ;
     RECT  176.928 25.909 179.592 25.955 ;
     RECT  42.768 24.805 42.792 26.149 ;
     RECT  49.2 23.797 52.44 26.291 ;
     RECT  184.128 24.851 184.152 26.675 ;
     RECT  49.2 26.291 51.312 26.725 ;
     RECT  31.104 25.715 31.8 26.771 ;
     RECT  38.736 25.715 38.76 26.771 ;
     RECT  48.432 26.725 51.312 26.771 ;
     RECT  41.568 3.685 41.592 26.915 ;
     RECT  45.504 25.715 46.296 26.917 ;
     RECT  40.08 3.349 40.512 27.205 ;
     RECT  45.504 26.917 47.16 27.395 ;
     RECT  169.632 21.397 172.536 27.829 ;
     RECT  48.432 26.771 48.456 27.971 ;
     RECT  42.72 26.149 42.792 28.211 ;
     RECT  33.696 26.725 33.72 28.213 ;
     RECT  169.632 27.829 172.728 28.309 ;
     RECT  174.096 4.261 174.12 28.309 ;
     RECT  157.536 24.181 166.056 28.355 ;
     RECT  50.016 26.771 51.312 28.405 ;
     RECT  52.416 26.291 52.44 28.405 ;
     RECT  29.4 23.843 29.832 28.453 ;
     RECT  36.96 25.907 37.704 28.453 ;
     RECT  38.688 27.301 38.712 28.453 ;
     RECT  44.016 25.715 44.472 28.453 ;
     RECT  45.6 27.395 47.16 28.453 ;
     RECT  50.016 28.405 52.44 28.645 ;
     RECT  49.824 28.645 52.44 28.691 ;
     RECT  40.08 27.205 40.968 28.789 ;
     RECT  169.632 28.309 174.12 28.931 ;
     RECT  44.016 28.453 47.16 29.029 ;
     RECT  42.768 28.211 42.792 29.075 ;
     RECT  50.88 28.691 52.44 29.123 ;
     RECT  180.6 23.893 182.952 29.123 ;
     RECT  52.416 29.123 52.44 29.173 ;
     RECT  52.416 29.173 53.064 29.219 ;
     RECT  173.184 28.931 174.12 29.605 ;
     RECT  175.104 4.405 175.512 29.605 ;
     RECT  31.104 26.771 31.464 29.651 ;
     RECT  33.024 28.213 33.72 29.651 ;
     RECT  40.08 28.789 41.016 29.797 ;
     RECT  42.48 29.605 42.504 29.797 ;
     RECT  169.632 28.931 172.056 29.893 ;
     RECT  40.08 29.797 42.504 29.939 ;
     RECT  34.8 4.501 35.208 30.083 ;
     RECT  40.08 29.939 41.016 30.323 ;
     RECT  44.016 29.029 47.928 30.323 ;
     RECT  54.432 24.755 62.568 30.421 ;
     RECT  173.184 29.605 175.512 30.421 ;
     RECT  169.632 29.893 172.152 30.469 ;
     RECT  49.824 28.691 49.848 30.565 ;
     RECT  50.88 29.123 51.312 30.565 ;
     RECT  33.024 29.651 33.48 30.709 ;
     RECT  47.136 30.323 47.928 30.851 ;
     RECT  34.8 30.083 35.112 31.093 ;
     RECT  31.104 29.651 31.368 31.379 ;
     RECT  32.976 30.709 33.48 31.379 ;
     RECT  36.96 28.453 38.712 31.379 ;
     RECT  40.2 30.323 41.016 31.379 ;
     RECT  42.48 29.939 42.504 31.379 ;
     RECT  180.6 29.123 181.56 31.523 ;
     RECT  53.04 29.219 53.064 31.525 ;
     RECT  157.584 28.355 166.056 31.571 ;
     RECT  54.144 30.421 62.568 31.619 ;
     RECT  169.488 30.469 172.152 31.861 ;
     RECT  29.4 28.453 30.072 31.955 ;
     RECT  31.344 31.379 31.368 31.955 ;
     RECT  47.136 30.851 47.16 31.955 ;
     RECT  49.824 30.565 51.312 31.955 ;
     RECT  173.136 30.421 175.512 32.003 ;
     RECT  37.68 31.379 38.712 32.051 ;
     RECT  53.04 31.525 53.112 32.053 ;
     RECT  32.976 31.379 33.048 32.099 ;
     RECT  53.04 32.053 53.16 32.099 ;
     RECT  38.688 32.051 38.712 32.435 ;
     RECT  44.016 30.323 45.912 32.531 ;
     RECT  34.8 31.093 35.208 32.771 ;
     RECT  48.384 31.333 48.408 32.771 ;
     RECT  169.44 31.861 172.152 32.869 ;
     RECT  174.096 32.003 175.512 33.013 ;
     RECT  49.824 31.955 49.848 33.107 ;
     RECT  173.712 33.013 175.512 33.253 ;
     RECT  176.928 25.955 178.872 33.253 ;
     RECT  53.136 32.099 53.16 33.541 ;
     RECT  52.656 33.541 53.16 33.587 ;
     RECT  167.184 4.501 167.976 34.021 ;
     RECT  169.44 32.869 172.344 34.021 ;
     RECT  173.712 33.253 178.872 34.067 ;
     RECT  54.144 31.619 54.168 34.117 ;
     RECT  53.856 34.117 54.168 34.163 ;
     RECT  157.584 31.571 165.96 34.213 ;
     RECT  167.184 34.021 172.344 34.213 ;
     RECT  182.928 29.123 182.952 34.213 ;
     RECT  182.64 34.213 182.952 34.259 ;
     RECT  174.912 34.067 178.872 34.787 ;
     RECT  157.584 34.213 172.344 34.835 ;
     RECT  180.6 31.523 181.224 34.835 ;
     RECT  182.64 34.259 182.664 34.835 ;
     RECT  173.712 34.067 173.736 35.461 ;
     RECT  174.912 34.787 176.424 35.461 ;
     RECT  180.6 34.835 180.912 35.845 ;
     RECT  185.856 3.637 186.312 35.891 ;
     RECT  171.552 34.835 172.344 35.941 ;
     RECT  173.712 35.461 176.424 35.941 ;
     RECT  177.408 34.787 178.872 36.133 ;
     RECT  177.408 36.133 179.304 36.179 ;
     RECT  171.552 35.941 176.424 36.515 ;
     RECT  177.408 36.179 177.432 36.755 ;
     RECT  173.232 36.515 176.424 36.853 ;
     RECT  171.552 36.515 172.152 36.901 ;
     RECT  180.6 35.845 181.032 37.091 ;
     RECT  188.64 4.501 188.664 37.237 ;
     RECT  187.968 37.237 188.664 37.283 ;
     RECT  171.504 36.901 172.152 37.813 ;
     RECT  173.232 36.853 177.336 37.813 ;
     RECT  171.504 37.813 177.336 37.859 ;
     RECT  187.968 37.283 187.992 38.435 ;
     RECT  191.4 25.859 191.712 38.629 ;
     RECT  194.4 21.203 194.424 38.675 ;
     RECT  157.584 34.835 170.376 38.819 ;
     RECT  171.504 37.859 172.968 39.011 ;
     RECT  191.4 38.629 192.504 39.395 ;
     RECT  157.584 38.819 170.112 39.443 ;
     RECT  53.856 34.163 53.88 39.589 ;
     RECT  55.152 31.619 62.568 39.589 ;
     RECT  196.704 13.091 197.112 39.589 ;
     RECT  157.68 39.443 170.112 39.779 ;
     RECT  174 37.859 177.336 39.923 ;
     RECT  172.944 39.011 172.968 40.019 ;
     RECT  185.904 35.891 186.312 40.499 ;
     RECT  53.856 39.589 62.568 40.691 ;
     RECT  174.816 39.923 177.336 40.693 ;
     RECT  182.592 35.557 182.616 40.981 ;
     RECT  182.592 40.981 182.76 41.027 ;
     RECT  171.504 39.011 171.576 41.075 ;
     RECT  178.848 36.179 179.304 41.075 ;
     RECT  196.656 39.589 197.112 41.075 ;
     RECT  174.816 40.693 177.384 41.605 ;
     RECT  52.656 33.587 52.68 41.651 ;
     RECT  54.336 40.691 62.568 42.035 ;
     RECT  182.736 41.027 182.76 42.227 ;
     RECT  158.16 39.779 170.112 42.707 ;
     RECT  167.328 42.707 170.112 42.803 ;
     RECT  55.152 42.035 62.568 42.851 ;
     RECT  61.344 42.851 62.568 43.043 ;
     RECT  55.152 42.851 60.36 43.139 ;
     RECT  174.672 41.605 177.384 43.379 ;
     RECT  174.672 43.379 176.136 43.907 ;
     RECT  55.152 43.139 60.264 44.147 ;
     RECT  56.16 44.147 60.264 44.195 ;
     RECT  158.16 42.707 166.344 44.483 ;
     RECT  167.856 42.803 170.112 44.483 ;
     RECT  167.856 44.483 167.88 44.581 ;
     RECT  167.76 44.581 167.88 44.627 ;
     RECT  61.8 43.043 62.568 44.867 ;
     RECT  158.16 44.483 162.84 44.915 ;
     RECT  61.8 44.867 62.52 44.963 ;
     RECT  56.256 44.195 60.264 45.109 ;
     RECT  158.688 44.915 162.84 45.203 ;
     RECT  61.8 44.963 62.112 45.397 ;
     RECT  159 45.203 162.84 45.683 ;
     RECT  55.152 44.147 55.176 46.117 ;
     RECT  56.256 45.109 60.6 46.117 ;
     RECT  168.96 44.483 170.112 46.211 ;
     RECT  55.152 46.117 60.6 46.547 ;
     RECT  6.768 41.989 6.792 46.787 ;
     RECT  61.632 45.397 62.112 47.029 ;
     RECT  167.76 44.627 167.784 47.269 ;
     RECT  61.632 47.029 62.52 47.315 ;
     RECT  167.76 47.269 168.12 47.315 ;
     RECT  159 45.683 161.016 47.363 ;
     RECT  162.096 45.683 162.84 47.939 ;
     RECT  177.312 43.379 177.384 47.939 ;
     RECT  168.096 47.315 168.12 49.043 ;
     RECT  37.68 32.051 37.704 49.141 ;
     RECT  56.112 46.547 60.6 49.141 ;
     RECT  61.632 47.315 62.112 49.141 ;
     RECT  37.68 49.141 38.136 49.187 ;
     RECT  56.112 49.141 62.112 49.235 ;
     RECT  171.552 41.075 171.576 50.435 ;
     RECT  162.144 47.939 162.84 52.499 ;
     RECT  162.816 52.499 162.84 52.691 ;
     RECT  159 47.363 160.44 53.603 ;
     RECT  159 53.603 160.296 55.043 ;
     RECT  33.024 32.099 33.048 55.237 ;
     RECT  32.832 55.237 33.048 55.283 ;
     RECT  163.824 44.483 166.344 55.907 ;
     RECT  166.32 55.907 166.344 56.003 ;
     RECT  174.672 43.907 176.088 57.059 ;
     RECT  159 55.043 160.2 58.163 ;
     RECT  163.824 55.907 165.336 58.163 ;
     RECT  174.672 57.059 175.512 58.739 ;
     RECT  169.44 46.211 170.112 59.797 ;
     RECT  178.848 41.075 178.872 60.467 ;
     RECT  56.4 49.235 62.112 60.805 ;
     RECT  56.4 60.805 62.568 60.995 ;
     RECT  56.4 60.995 62.112 61.043 ;
     RECT  40.2 31.379 40.512 61.141 ;
     RECT  58.08 61.043 62.112 61.763 ;
     RECT  172.704 60.373 172.728 61.861 ;
     RECT  172.704 61.861 172.968 61.907 ;
     RECT  175.2 58.739 175.512 62.149 ;
     RECT  169.44 59.797 170.424 62.725 ;
     RECT  58.656 61.763 62.112 63.157 ;
     RECT  58.656 63.157 62.328 63.349 ;
     RECT  58.656 63.349 62.52 65.077 ;
     RECT  175.2 62.149 175.752 65.077 ;
     RECT  163.824 58.163 164.712 65.267 ;
     RECT  87.936 24.517 91.368 67.283 ;
     RECT  119.088 23.845 122.04 67.283 ;
     RECT  123.072 23.749 129.336 67.283 ;
     RECT  94.2 25.859 94.632 67.523 ;
     RECT  58.656 65.077 62.568 67.619 ;
     RECT  58.656 67.619 62.52 67.715 ;
     RECT  71.424 22.165 74.472 67.765 ;
     RECT  75.648 22.741 78.696 67.765 ;
     RECT  65.472 23.363 68.472 67.811 ;
     RECT  71.424 67.765 78.696 67.811 ;
     RECT  130.464 25.045 143.928 67.811 ;
     RECT  66.624 67.811 68.472 67.955 ;
     RECT  71.424 67.811 78.312 67.955 ;
     RECT  65.472 67.811 65.592 68.435 ;
     RECT  65.568 68.435 65.592 68.531 ;
     RECT  66.624 67.955 68.376 68.963 ;
     RECT  70.128 22.835 70.152 69.011 ;
     RECT  71.424 67.955 74.04 69.011 ;
     RECT  80.064 21.923 80.328 69.011 ;
     RECT  81.504 22.741 86.712 69.011 ;
     RECT  87.936 67.283 91.272 69.011 ;
     RECT  109.296 22.741 110.712 69.011 ;
     RECT  75.024 67.955 78.312 69.059 ;
     RECT  58.656 67.715 62.376 69.061 ;
     RECT  76.752 69.059 77.016 69.107 ;
     RECT  87.936 69.011 89.256 69.107 ;
     RECT  109.392 69.011 109.416 69.107 ;
     RECT  115.2 23.317 116.112 69.155 ;
     RECT  86.4 69.011 86.712 69.205 ;
     RECT  111.888 23.317 112.2 69.251 ;
     RECT  113.424 23.125 113.496 69.251 ;
     RECT  115.632 69.155 116.112 69.251 ;
     RECT  75.024 69.059 75.048 69.253 ;
     RECT  58.656 69.061 62.76 69.302 ;
     RECT  86.4 69.205 86.76 69.347 ;
     RECT  113.424 69.251 113.448 69.395 ;
     RECT  74.688 69.253 75.048 69.443 ;
     RECT  88.08 69.107 89.256 69.443 ;
     RECT  86.4 69.347 86.664 69.491 ;
     RECT  88.128 69.443 89.256 69.491 ;
     RECT  90.624 69.011 90.648 69.491 ;
     RECT  66.624 68.963 67.512 69.683 ;
     RECT  58.656 69.302 62.112 69.779 ;
     RECT  71.424 69.011 71.448 70.115 ;
     RECT  111.888 69.251 111.912 70.163 ;
     RECT  59.616 69.779 62.112 70.307 ;
     RECT  59.712 70.307 62.112 70.403 ;
     RECT  59.76 70.403 62.112 70.835 ;
     RECT  135.888 67.811 143.928 71.315 ;
     RECT  78 69.059 78.312 71.413 ;
     RECT  60.624 70.835 62.112 71.651 ;
     RECT  81.504 69.011 82.392 71.797 ;
     RECT  186 40.499 186.312 73.333 ;
     RECT  38.112 49.187 38.136 77.555 ;
     RECT  81.264 71.797 82.392 78.227 ;
     RECT  56.4 61.043 56.808 78.659 ;
     RECT  168.624 62.725 170.424 78.659 ;
     RECT  172.944 61.907 172.968 81.541 ;
     RECT  172.944 81.541 173.352 81.587 ;
     RECT  177.312 47.939 177.336 84.851 ;
     RECT  169.8 78.659 170.424 84.995 ;
     RECT  171.792 82.021 171.816 85.283 ;
     RECT  168.624 78.659 168.648 86.149 ;
     RECT  169.8 84.995 170.112 86.149 ;
     RECT  168.624 86.149 170.112 86.195 ;
     RECT  168.912 86.195 170.112 86.197 ;
     RECT  75.024 69.443 75.048 87.827 ;
     RECT  171.84 85.477 171.864 88.115 ;
     RECT  88.128 69.491 89.112 90.659 ;
     RECT  86.4 69.491 86.424 90.901 ;
     RECT  88.8 90.659 89.112 91.141 ;
     RECT  76.752 69.107 76.776 91.235 ;
     RECT  56.4 78.659 56.712 91.429 ;
     RECT  81.264 78.227 81.288 91.477 ;
     RECT  80.736 91.477 81.288 91.573 ;
     RECT  75.216 88.309 75.24 91.619 ;
     RECT  72.6 69.011 73.32 91.717 ;
     RECT  88.8 91.141 89.496 91.717 ;
     RECT  32.832 55.283 32.856 91.955 ;
     RECT  80.4 91.573 81.288 91.955 ;
     RECT  52.464 91.141 52.488 92.051 ;
     RECT  86.4 90.901 86.712 92.099 ;
     RECT  45.504 32.531 45.912 92.101 ;
     RECT  86.688 92.099 86.712 92.197 ;
     RECT  83.4 69.011 83.712 92.245 ;
     RECT  84.72 78.613 84.744 92.245 ;
     RECT  37.584 91.861 37.608 92.293 ;
     RECT  39.408 61.141 40.512 92.293 ;
     RECT  99.6 10.643 99.912 92.293 ;
     RECT  56.4 91.429 57 92.387 ;
     RECT  82.368 78.227 82.392 92.387 ;
     RECT  83.4 92.245 84.744 92.387 ;
     RECT  88.8 91.717 89.88 92.387 ;
     RECT  121.2 67.283 122.04 92.387 ;
     RECT  128.496 67.283 129.336 92.387 ;
     RECT  37.584 92.293 40.512 92.435 ;
     RECT  29.4 31.955 29.712 92.437 ;
     RECT  61.2 71.651 62.112 92.531 ;
     RECT  71.808 91.717 73.32 92.579 ;
     RECT  51 31.955 51.312 92.581 ;
     RECT  43.872 91.717 43.896 92.675 ;
     RECT  34.8 32.771 35.112 92.677 ;
     RECT  61.44 92.531 62.112 92.723 ;
     RECT  67.2 69.683 67.512 92.773 ;
     RECT  121.2 92.387 121.512 92.821 ;
     RECT  74.688 92.005 74.712 92.915 ;
     RECT  94.2 67.523 94.512 92.917 ;
     RECT  115.8 69.251 116.112 92.917 ;
     RECT  42.192 92.677 42.216 92.963 ;
     RECT  99.6 92.293 100.872 92.963 ;
     RECT  119.088 67.283 119.304 92.963 ;
     RECT  123.072 67.283 126.912 92.963 ;
     RECT  130.464 67.811 134.328 92.963 ;
     RECT  135.888 71.315 139.08 92.963 ;
     RECT  140.064 71.315 143.928 92.963 ;
     RECT  145.008 24.517 146.232 92.963 ;
     RECT  147.504 25.045 149.784 92.963 ;
     RECT  152.592 23.701 152.616 92.963 ;
     RECT  175.2 65.077 175.848 92.963 ;
     RECT  211.776 65.509 211.8 92.963 ;
     RECT  86.688 92.197 87.24 93.011 ;
     RECT  119.088 92.963 119.112 93.011 ;
     RECT  137.28 92.963 137.712 93.011 ;
     RECT  78 71.413 78.84 93.013 ;
     RECT  141.552 92.963 143.112 93.107 ;
     RECT  6.576 47.221 6.6 93.109 ;
     RECT  48.432 91.717 48.456 93.203 ;
     RECT  80.4 91.955 80.568 93.203 ;
     RECT  30.72 91.189 30.744 93.251 ;
     RECT  80.544 93.203 80.568 93.251 ;
     RECT  148.2 92.963 148.824 93.251 ;
     RECT  168.912 86.197 170.664 93.251 ;
     RECT  196.8 41.075 197.112 93.253 ;
     RECT  13.2 2.151 13.512 93.301 ;
     RECT  76.992 92.821 77.016 93.301 ;
     RECT  121.104 92.821 121.512 93.347 ;
     RECT  186 73.333 187.08 93.347 ;
     RECT  129.312 92.387 129.336 93.349 ;
     RECT  130.464 92.963 130.488 93.349 ;
     RECT  21.12 93.205 21.144 93.395 ;
     RECT  196.704 93.253 197.112 93.395 ;
     RECT  86.688 93.011 86.712 93.397 ;
     RECT  139.056 92.963 139.08 93.397 ;
     RECT  5.952 93.109 6.6 93.443 ;
     RECT  37.584 92.435 38.472 93.443 ;
     RECT  43.344 92.869 43.368 93.443 ;
     RECT  27.552 91.621 27.576 93.491 ;
     RECT  134.16 92.963 134.184 93.491 ;
     RECT  150 93.301 150.024 93.491 ;
     RECT  66.096 92.293 66.12 93.539 ;
     RECT  67.104 92.773 67.512 93.539 ;
     RECT  88.8 92.387 89.496 93.539 ;
     RECT  102.432 92.917 102.456 93.539 ;
     RECT  123.072 92.963 123.096 93.539 ;
     RECT  126.144 92.963 126.912 93.539 ;
     RECT  129.312 93.349 130.488 93.539 ;
     RECT  131.664 92.963 132.552 93.539 ;
     RECT  135.888 92.963 135.912 93.539 ;
     RECT  139.056 93.397 139.704 93.539 ;
     RECT  142.32 93.107 143.112 93.539 ;
     RECT  145.872 92.963 145.896 93.539 ;
     RECT  168.912 93.251 170.232 93.539 ;
     RECT  28.896 92.437 29.712 93.587 ;
     RECT  45.456 92.101 45.912 93.587 ;
     RECT  86.592 93.397 86.712 93.587 ;
     RECT  38.448 93.443 38.472 93.731 ;
     RECT  69.552 92.389 69.576 93.731 ;
     RECT  131.664 93.539 132.312 93.731 ;
     RECT  33.648 92.389 33.672 93.779 ;
     RECT  71.808 92.579 72.912 93.779 ;
     RECT  82.224 93.109 82.248 93.779 ;
     RECT  129.696 93.539 129.72 93.779 ;
     RECT  169.8 93.539 170.232 93.779 ;
     RECT  12.528 93.301 13.512 93.827 ;
     RECT  76.368 93.301 77.016 93.923 ;
     RECT  83.4 92.387 84.648 93.923 ;
     RECT  78 93.013 79.224 94.019 ;
     RECT  115.8 92.917 116.376 94.019 ;
     RECT  173.328 81.587 173.352 94.019 ;
     RECT  86.592 93.587 86.616 94.067 ;
     RECT  139.68 93.539 139.704 94.067 ;
     RECT  76.368 93.923 76.392 94.115 ;
     RECT  5.952 93.443 5.976 94.259 ;
     RECT  93.648 92.917 94.512 94.259 ;
     RECT  34.8 92.677 35.352 94.355 ;
     RECT  51 92.581 52.008 94.355 ;
     RECT  7.8 3.971 8.112 94.981 ;
     RECT  24 2.151 24.312 94.981 ;
     RECT  34.8 94.355 35.112 94.981 ;
     RECT  56.4 92.387 56.712 94.981 ;
     RECT  72.6 93.779 72.912 94.981 ;
     RECT  83.4 93.923 83.712 94.981 ;
     RECT  99.6 92.963 99.912 94.981 ;
     RECT  105 2.151 105.312 94.981 ;
     RECT  115.8 94.019 116.112 94.981 ;
     RECT  121.2 93.347 121.512 94.981 ;
     RECT  132 93.731 132.312 94.981 ;
     RECT  148.2 93.251 148.512 94.981 ;
     RECT  153.6 22.835 153.912 94.981 ;
     RECT  164.4 65.267 164.712 94.981 ;
     RECT  169.8 93.779 170.112 94.981 ;
     RECT  180.6 37.091 180.912 94.981 ;
     RECT  202.2 2.151 202.512 94.981 ;
     RECT  213 2.151 213.312 94.981 ;
     RECT  2.4 2.151 2.712 95.049 ;
     RECT  18.6 2.151 18.912 95.049 ;
     RECT  34.608 94.981 35.112 95.049 ;
     RECT  40.2 92.435 40.512 95.049 ;
     RECT  51 94.355 51.312 95.049 ;
     RECT  55.632 94.981 56.712 95.049 ;
     RECT  61.8 92.723 62.112 95.049 ;
     RECT  67.2 93.539 67.512 95.049 ;
     RECT  78 94.019 78.312 95.049 ;
     RECT  83.088 94.981 83.712 95.049 ;
     RECT  88.8 93.539 89.112 95.049 ;
     RECT  94.2 94.259 94.512 95.049 ;
     RECT  99.6 94.981 100.872 95.049 ;
     RECT  110.4 69.011 110.712 95.049 ;
     RECT  115.392 94.981 116.112 95.049 ;
     RECT  126.6 93.539 126.912 95.049 ;
     RECT  131.568 94.981 133.176 95.049 ;
     RECT  137.4 93.011 137.712 95.049 ;
     RECT  142.8 93.539 143.112 95.049 ;
     RECT  148.2 94.981 149.352 95.049 ;
     RECT  159 58.163 159.312 95.049 ;
     RECT  163.872 94.981 164.712 95.049 ;
     RECT  175.2 92.963 175.512 95.049 ;
     RECT  186 93.347 186.312 95.049 ;
     RECT  191.4 39.395 191.712 95.049 ;
     RECT  196.8 93.395 197.112 95.049 ;
     RECT  207.6 2.151 207.912 95.049 ;
     RECT  2.4 95.049 2.52 95.063 ;
     RECT  7.152 94.981 8.76 95.063 ;
     RECT  13.2 93.827 13.512 95.063 ;
     RECT  18.6 95.049 18.72 95.063 ;
     RECT  24 94.981 24.936 95.063 ;
     RECT  29.4 93.587 29.712 95.063 ;
     RECT  34.608 95.049 34.92 95.063 ;
     RECT  40.2 95.049 40.32 95.063 ;
     RECT  45.6 93.587 45.912 95.063 ;
     RECT  51 95.049 51.12 95.063 ;
     RECT  55.632 95.049 56.52 95.063 ;
     RECT  61.8 95.049 62.088 95.063 ;
     RECT  67.2 95.049 67.32 95.063 ;
     RECT  71.76 94.981 73.416 95.063 ;
     RECT  78 95.049 78.12 95.063 ;
     RECT  83.088 95.049 83.52 95.063 ;
     RECT  88.8 95.049 88.92 95.063 ;
     RECT  94.2 95.049 94.44 95.063 ;
     RECT  99.6 95.049 99.72 95.063 ;
     RECT  104.112 94.981 105.72 95.063 ;
     RECT  110.4 95.049 110.568 95.063 ;
     RECT  115.392 95.049 115.92 95.063 ;
     RECT  120.24 94.981 121.896 95.063 ;
     RECT  126.6 95.049 126.72 95.063 ;
     RECT  131.568 95.049 132.12 95.063 ;
     RECT  137.4 95.049 137.52 95.063 ;
     RECT  142.8 95.049 142.92 95.063 ;
     RECT  148.2 95.049 148.32 95.063 ;
     RECT  153.6 94.981 154.2 95.063 ;
     RECT  159 95.049 159.12 95.063 ;
     RECT  163.872 95.049 164.52 95.063 ;
     RECT  169.8 94.981 170.376 95.063 ;
     RECT  175.2 95.049 175.32 95.063 ;
     RECT  180.048 94.981 181.656 95.063 ;
     RECT  186 95.049 186.12 95.063 ;
     RECT  191.4 95.049 191.52 95.063 ;
     RECT  196.8 95.049 196.92 95.063 ;
     RECT  202.2 94.981 202.68 95.063 ;
     RECT  207.6 95.049 207.72 95.063 ;
     RECT  212.352 94.981 214.008 95.063 ;
     RECT  106.992 21.637 107.016 96.371 ;
     RECT  5.52 94.981 5.544 97.04 ;
     RECT  7.152 95.063 7.176 97.04 ;
     RECT  8.736 95.063 8.76 97.04 ;
     RECT  10.368 96.325 10.392 97.04 ;
     RECT  12 96.325 12.024 97.04 ;
     RECT  13.584 95.125 13.608 97.04 ;
     RECT  15.216 94.981 15.24 97.04 ;
     RECT  16.848 94.981 16.872 97.04 ;
     RECT  18.432 96.325 18.456 97.04 ;
     RECT  20.064 96.325 20.088 97.04 ;
     RECT  21.696 94.981 21.72 97.04 ;
     RECT  23.28 95.173 23.304 97.04 ;
     RECT  24.912 95.063 24.936 97.04 ;
     RECT  26.544 94.981 26.568 97.04 ;
     RECT  28.128 96.325 28.152 97.04 ;
     RECT  29.76 95.125 29.784 97.04 ;
     RECT  31.392 96.325 31.416 97.04 ;
     RECT  32.976 94.981 33 97.04 ;
     RECT  34.608 95.063 34.632 97.04 ;
     RECT  36.24 94.981 36.264 97.04 ;
     RECT  37.824 94.981 37.848 97.04 ;
     RECT  39.456 96.325 39.48 97.04 ;
     RECT  41.088 96.325 41.112 97.04 ;
     RECT  42.672 94.981 42.696 97.04 ;
     RECT  44.304 94.981 44.328 97.04 ;
     RECT  45.936 95.125 45.96 97.04 ;
     RECT  47.52 96.325 47.544 97.04 ;
     RECT  49.152 96.325 49.176 97.04 ;
     RECT  50.784 96.325 50.808 97.04 ;
     RECT  52.368 94.981 52.392 97.04 ;
     RECT  54 94.981 54.024 97.04 ;
     RECT  55.632 95.063 55.656 97.04 ;
     RECT  57.216 96.325 57.24 97.04 ;
     RECT  58.848 96.325 58.872 97.04 ;
     RECT  60.48 96.325 60.504 97.04 ;
     RECT  62.064 95.063 62.088 97.04 ;
     RECT  63.696 94.981 63.72 97.04 ;
     RECT  65.328 94.981 65.352 97.04 ;
     RECT  66.912 96.325 66.936 97.04 ;
     RECT  68.544 96.325 68.568 97.04 ;
     RECT  70.176 96.325 70.2 97.04 ;
     RECT  71.76 95.063 71.784 97.04 ;
     RECT  73.392 95.063 73.416 97.04 ;
     RECT  75.024 94.981 75.048 97.04 ;
     RECT  76.608 94.981 76.632 97.04 ;
     RECT  78.24 96.325 78.264 97.04 ;
     RECT  79.872 96.325 79.896 97.04 ;
     RECT  81.456 94.981 81.48 97.04 ;
     RECT  83.088 95.063 83.112 97.04 ;
     RECT  84.72 94.981 84.744 97.04 ;
     RECT  86.304 96.325 86.328 97.04 ;
     RECT  87.936 96.325 87.96 97.04 ;
     RECT  89.568 96.325 89.592 97.04 ;
     RECT  91.152 94.981 91.176 97.04 ;
     RECT  92.784 94.981 92.808 97.04 ;
     RECT  94.416 95.063 94.44 97.04 ;
     RECT  96 94.981 96.024 97.04 ;
     RECT  97.632 96.325 97.656 97.04 ;
     RECT  99.264 96.325 99.288 97.04 ;
     RECT  100.848 95.049 100.872 97.04 ;
     RECT  102.48 94.981 102.504 97.04 ;
     RECT  104.112 95.063 104.136 97.04 ;
     RECT  105.696 95.063 105.72 97.04 ;
     RECT  107.328 96.373 107.352 97.04 ;
     RECT  108.96 96.373 108.984 97.04 ;
     RECT  110.544 95.063 110.568 97.04 ;
     RECT  112.176 94.981 112.2 97.04 ;
     RECT  113.76 94.981 113.784 97.04 ;
     RECT  115.392 95.063 115.416 97.04 ;
     RECT  117.024 96.325 117.048 97.04 ;
     RECT  118.608 96.325 118.632 97.04 ;
     RECT  120.24 95.063 120.264 97.04 ;
     RECT  121.872 95.063 121.896 97.04 ;
     RECT  123.456 94.981 123.48 97.04 ;
     RECT  125.088 94.981 125.112 97.04 ;
     RECT  126.72 96.325 126.744 97.04 ;
     RECT  128.304 96.325 128.328 97.04 ;
     RECT  129.936 94.981 129.96 97.04 ;
     RECT  131.568 95.063 131.592 97.04 ;
     RECT  133.152 95.049 133.176 97.04 ;
     RECT  134.784 94.981 134.808 97.04 ;
     RECT  136.416 96.325 136.44 97.04 ;
     RECT  138 96.325 138.024 97.04 ;
     RECT  139.632 94.981 139.656 97.04 ;
     RECT  141.264 94.981 141.288 97.04 ;
     RECT  142.848 95.063 142.872 97.04 ;
     RECT  144.48 94.981 144.504 97.04 ;
     RECT  146.112 96.325 146.136 97.04 ;
     RECT  147.696 96.325 147.72 97.04 ;
     RECT  149.328 95.049 149.352 97.04 ;
     RECT  150.96 94.981 150.984 97.04 ;
     RECT  152.544 95.173 152.568 97.04 ;
     RECT  154.176 95.063 154.2 97.04 ;
     RECT  155.808 94.981 155.832 97.04 ;
     RECT  157.392 94.981 157.416 97.04 ;
     RECT  159.024 96.325 159.048 97.04 ;
     RECT  160.656 94.981 160.68 97.04 ;
     RECT  162.24 94.981 162.264 97.04 ;
     RECT  163.872 95.063 163.896 97.04 ;
     RECT  165.504 96.325 165.528 97.04 ;
     RECT  167.088 96.325 167.112 97.04 ;
     RECT  168.72 96.325 168.744 97.04 ;
     RECT  170.352 95.063 170.376 97.04 ;
     RECT  171.936 94.981 171.96 97.04 ;
     RECT  173.568 94.981 173.592 97.04 ;
     RECT  175.2 95.063 175.224 97.04 ;
     RECT  176.784 94.981 176.808 97.04 ;
     RECT  178.416 96.325 178.44 97.04 ;
     RECT  180.048 95.063 180.072 97.04 ;
     RECT  181.632 95.063 181.656 97.04 ;
     RECT  183.264 94.981 183.288 97.04 ;
     RECT  184.896 96.325 184.92 97.04 ;
     RECT  186.48 96.325 186.504 97.04 ;
     RECT  188.112 96.325 188.136 97.04 ;
     RECT  189.744 94.981 189.768 97.04 ;
     RECT  191.328 95.125 191.352 97.04 ;
     RECT  192.96 96.325 192.984 97.04 ;
     RECT  194.592 94.981 194.616 97.04 ;
     RECT  196.176 96.325 196.2 97.04 ;
     RECT  197.808 96.325 197.832 97.04 ;
     RECT  199.44 94.981 199.464 97.04 ;
     RECT  201.024 96.325 201.048 97.04 ;
     RECT  202.656 95.063 202.68 97.04 ;
     RECT  204.288 96.325 204.312 97.04 ;
     RECT  205.872 96.325 205.896 97.04 ;
     RECT  207.504 96.325 207.528 97.04 ;
     RECT  209.136 94.981 209.16 97.04 ;
     RECT  210.72 94.981 210.744 97.04 ;
     RECT  212.352 95.063 212.376 97.04 ;
     RECT  213.984 95.063 214.008 97.04 ;
     RECT  215.568 95.749 215.592 97.04 ;
  END
END ot_s81_hc_ccf_bankpipe_bank256
END LIBRARY
